VERSION 5.7 ;
BUSBITCHARS "[]" ;
DIVIDERCHAR "/" ;

PROPERTYDEFINITIONS
  MACRO CatenaDesignType STRING ;
END PROPERTYDEFINITIONS

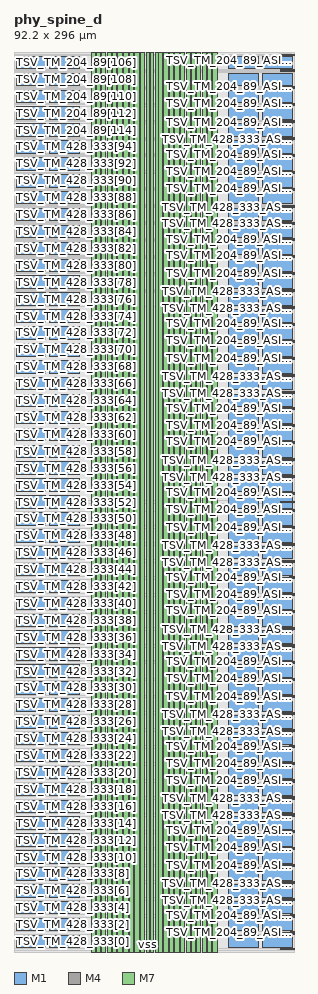
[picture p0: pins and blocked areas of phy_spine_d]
MACRO phy_spine_d
  CLASS RING ;
  ORIGIN 0 0 ;
  FOREIGN phy_spine_d 0 0 ;
  SIZE 92.2 BY 296 ;
  SYMMETRY X Y R90 ;
  PIN TSV_TM_204_89[0]
    DIRECTION OUTPUT ;
    USE SIGNAL ;
    PORT
      LAYER M1 ;
        RECT 81.82 1.38 91.5 5.5 ;
    END
  END TSV_TM_204_89[0]
  PIN TSV_TM_204_89[100]
    DIRECTION OUTPUT ;
    USE SIGNAL ;
    PORT
      LAYER M1 ;
        RECT 81.82 279.38 91.5 283.5 ;
    END
  END TSV_TM_204_89[100]
  PIN TSV_TM_204_89[101]
    DIRECTION OUTPUT ;
    USE SIGNAL ;
    PORT
      LAYER M1 ;
        RECT 70.7 279.38 80.38 283.5 ;
    END
  END TSV_TM_204_89[101]
  PIN TSV_TM_204_89[102]
    DIRECTION OUTPUT ;
    USE SIGNAL ;
    PORT
      LAYER M1 ;
        RECT 81.82 284.94 91.5 289.06 ;
    END
  END TSV_TM_204_89[102]
  PIN TSV_TM_204_89[103]
    DIRECTION OUTPUT ;
    USE SIGNAL ;
    PORT
      LAYER M1 ;
        RECT 70.7 284.94 80.38 289.06 ;
    END
  END TSV_TM_204_89[103]
  PIN TSV_TM_204_89[104]
    DIRECTION OUTPUT ;
    USE SIGNAL ;
    PORT
      LAYER M1 ;
        RECT 81.82 290.5 91.5 294.62 ;
    END
  END TSV_TM_204_89[104]
  PIN TSV_TM_204_89[105]
    DIRECTION OUTPUT ;
    USE SIGNAL ;
    PORT
      LAYER M1 ;
        RECT 70.7 290.5 80.38 294.62 ;
    END
  END TSV_TM_204_89[105]
  PIN TSV_TM_204_89[106]
    DIRECTION OUTPUT ;
    USE SIGNAL ;
    PORT
      LAYER M1 ;
        RECT 11.79 290.5 21.47 294.62 ;
    END
  END TSV_TM_204_89[106]
  PIN TSV_TM_204_89[107]
    DIRECTION OUTPUT ;
    USE SIGNAL ;
    PORT
      LAYER M1 ;
        RECT 0.67 290.5 10.35 294.62 ;
    END
  END TSV_TM_204_89[107]
  PIN TSV_TM_204_89[108]
    DIRECTION OUTPUT ;
    USE SIGNAL ;
    PORT
      LAYER M1 ;
        RECT 11.79 284.94 21.47 289.06 ;
    END
  END TSV_TM_204_89[108]
  PIN TSV_TM_204_89[109]
    DIRECTION OUTPUT ;
    USE SIGNAL ;
    PORT
      LAYER M1 ;
        RECT 0.67 284.94 10.35 289.06 ;
    END
  END TSV_TM_204_89[109]
  PIN TSV_TM_204_89[10]
    DIRECTION OUTPUT ;
    USE SIGNAL ;
    PORT
      LAYER M1 ;
        RECT 81.82 29.18 91.5 33.3 ;
    END
  END TSV_TM_204_89[10]
  PIN TSV_TM_204_89[110]
    DIRECTION OUTPUT ;
    USE SIGNAL ;
    PORT
      LAYER M1 ;
        RECT 11.79 279.38 21.47 283.5 ;
    END
  END TSV_TM_204_89[110]
  PIN TSV_TM_204_89[111]
    DIRECTION OUTPUT ;
    USE SIGNAL ;
    PORT
      LAYER M1 ;
        RECT 0.67 279.38 10.35 283.5 ;
    END
  END TSV_TM_204_89[111]
  PIN TSV_TM_204_89[112]
    DIRECTION OUTPUT ;
    USE SIGNAL ;
    PORT
      LAYER M1 ;
        RECT 11.79 273.82 21.47 277.94 ;
    END
  END TSV_TM_204_89[112]
  PIN TSV_TM_204_89[113]
    DIRECTION OUTPUT ;
    USE SIGNAL ;
    PORT
      LAYER M1 ;
        RECT 0.67 273.82 10.35 277.94 ;
    END
  END TSV_TM_204_89[113]
  PIN TSV_TM_204_89[114]
    DIRECTION OUTPUT ;
    USE SIGNAL ;
    PORT
      LAYER M1 ;
        RECT 11.79 268.26 21.47 272.38 ;
    END
  END TSV_TM_204_89[114]
  PIN TSV_TM_204_89[115]
    DIRECTION OUTPUT ;
    USE SIGNAL ;
    PORT
      LAYER M1 ;
        RECT 0.67 268.26 10.35 272.38 ;
    END
  END TSV_TM_204_89[115]
  PIN TSV_TM_204_89[11]
    DIRECTION OUTPUT ;
    USE SIGNAL ;
    PORT
      LAYER M1 ;
        RECT 70.7 29.18 80.38 33.3 ;
    END
  END TSV_TM_204_89[11]
  PIN TSV_TM_204_89[12]
    DIRECTION OUTPUT ;
    USE SIGNAL ;
    PORT
      LAYER M1 ;
        RECT 81.82 34.74 91.5 38.86 ;
    END
  END TSV_TM_204_89[12]
  PIN TSV_TM_204_89[13]
    DIRECTION OUTPUT ;
    USE SIGNAL ;
    PORT
      LAYER M1 ;
        RECT 70.7 34.74 80.38 38.86 ;
    END
  END TSV_TM_204_89[13]
  PIN TSV_TM_204_89[14]
    DIRECTION OUTPUT ;
    USE SIGNAL ;
    PORT
      LAYER M1 ;
        RECT 81.82 40.3 91.5 44.42 ;
    END
  END TSV_TM_204_89[14]
  PIN TSV_TM_204_89[15]
    DIRECTION OUTPUT ;
    USE SIGNAL ;
    PORT
      LAYER M1 ;
        RECT 70.7 40.3 80.38 44.42 ;
    END
  END TSV_TM_204_89[15]
  PIN TSV_TM_204_89[16]
    DIRECTION OUTPUT ;
    USE SIGNAL ;
    PORT
      LAYER M1 ;
        RECT 81.82 45.86 91.5 49.98 ;
    END
  END TSV_TM_204_89[16]
  PIN TSV_TM_204_89[17]
    DIRECTION OUTPUT ;
    USE SIGNAL ;
    PORT
      LAYER M1 ;
        RECT 70.7 45.86 80.38 49.98 ;
    END
  END TSV_TM_204_89[17]
  PIN TSV_TM_204_89[18]
    DIRECTION OUTPUT ;
    USE SIGNAL ;
    PORT
      LAYER M1 ;
        RECT 81.82 51.42 91.5 55.54 ;
    END
  END TSV_TM_204_89[18]
  PIN TSV_TM_204_89[19]
    DIRECTION OUTPUT ;
    USE SIGNAL ;
    PORT
      LAYER M1 ;
        RECT 70.7 51.42 80.38 55.54 ;
    END
  END TSV_TM_204_89[19]
  PIN TSV_TM_204_89[1]
    DIRECTION OUTPUT ;
    USE SIGNAL ;
    PORT
      LAYER M1 ;
        RECT 70.7 1.38 80.38 5.5 ;
    END
  END TSV_TM_204_89[1]
  PIN TSV_TM_204_89[20]
    DIRECTION OUTPUT ;
    USE SIGNAL ;
    PORT
      LAYER M1 ;
        RECT 81.82 56.98 91.5 61.1 ;
    END
  END TSV_TM_204_89[20]
  PIN TSV_TM_204_89[21]
    DIRECTION OUTPUT ;
    USE SIGNAL ;
    PORT
      LAYER M1 ;
        RECT 70.7 56.98 80.38 61.1 ;
    END
  END TSV_TM_204_89[21]
  PIN TSV_TM_204_89[22]
    DIRECTION OUTPUT ;
    USE SIGNAL ;
    PORT
      LAYER M1 ;
        RECT 81.82 62.54 91.5 66.66 ;
    END
  END TSV_TM_204_89[22]
  PIN TSV_TM_204_89[23]
    DIRECTION OUTPUT ;
    USE SIGNAL ;
    PORT
      LAYER M1 ;
        RECT 70.7 62.54 80.38 66.66 ;
    END
  END TSV_TM_204_89[23]
  PIN TSV_TM_204_89[24]
    DIRECTION OUTPUT ;
    USE SIGNAL ;
    PORT
      LAYER M1 ;
        RECT 81.82 68.1 91.5 72.22 ;
    END
  END TSV_TM_204_89[24]
  PIN TSV_TM_204_89[25]
    DIRECTION OUTPUT ;
    USE SIGNAL ;
    PORT
      LAYER M1 ;
        RECT 70.7 68.1 80.38 72.22 ;
    END
  END TSV_TM_204_89[25]
  PIN TSV_TM_204_89[26]
    DIRECTION OUTPUT ;
    USE SIGNAL ;
    PORT
      LAYER M1 ;
        RECT 81.82 73.66 91.5 77.78 ;
    END
  END TSV_TM_204_89[26]
  PIN TSV_TM_204_89[27]
    DIRECTION OUTPUT ;
    USE SIGNAL ;
    PORT
      LAYER M1 ;
        RECT 70.7 73.66 80.38 77.78 ;
    END
  END TSV_TM_204_89[27]
  PIN TSV_TM_204_89[28]
    DIRECTION OUTPUT ;
    USE SIGNAL ;
    PORT
      LAYER M1 ;
        RECT 81.82 79.22 91.5 83.34 ;
    END
  END TSV_TM_204_89[28]
  PIN TSV_TM_204_89[29]
    DIRECTION OUTPUT ;
    USE SIGNAL ;
    PORT
      LAYER M1 ;
        RECT 70.7 79.22 80.38 83.34 ;
    END
  END TSV_TM_204_89[29]
  PIN TSV_TM_204_89[2]
    DIRECTION OUTPUT ;
    USE SIGNAL ;
    PORT
      LAYER M1 ;
        RECT 81.82 6.94 91.5 11.06 ;
    END
  END TSV_TM_204_89[2]
  PIN TSV_TM_204_89[30]
    DIRECTION OUTPUT ;
    USE SIGNAL ;
    PORT
      LAYER M1 ;
        RECT 81.82 84.78 91.5 88.9 ;
    END
  END TSV_TM_204_89[30]
  PIN TSV_TM_204_89[31]
    DIRECTION OUTPUT ;
    USE SIGNAL ;
    PORT
      LAYER M1 ;
        RECT 70.7 84.78 80.38 88.9 ;
    END
  END TSV_TM_204_89[31]
  PIN TSV_TM_204_89[32]
    DIRECTION OUTPUT ;
    USE SIGNAL ;
    PORT
      LAYER M1 ;
        RECT 81.82 90.34 91.5 94.46 ;
    END
  END TSV_TM_204_89[32]
  PIN TSV_TM_204_89[33]
    DIRECTION OUTPUT ;
    USE SIGNAL ;
    PORT
      LAYER M1 ;
        RECT 70.7 90.34 80.38 94.46 ;
    END
  END TSV_TM_204_89[33]
  PIN TSV_TM_204_89[34]
    DIRECTION OUTPUT ;
    USE SIGNAL ;
    PORT
      LAYER M1 ;
        RECT 81.82 95.9 91.5 100.02 ;
    END
  END TSV_TM_204_89[34]
  PIN TSV_TM_204_89[35]
    DIRECTION OUTPUT ;
    USE SIGNAL ;
    PORT
      LAYER M1 ;
        RECT 70.7 95.9 80.38 100.02 ;
    END
  END TSV_TM_204_89[35]
  PIN TSV_TM_204_89[36]
    DIRECTION OUTPUT ;
    USE SIGNAL ;
    PORT
      LAYER M1 ;
        RECT 81.82 101.46 91.5 105.58 ;
    END
  END TSV_TM_204_89[36]
  PIN TSV_TM_204_89[37]
    DIRECTION OUTPUT ;
    USE SIGNAL ;
    PORT
      LAYER M1 ;
        RECT 70.7 101.46 80.38 105.58 ;
    END
  END TSV_TM_204_89[37]
  PIN TSV_TM_204_89[38]
    DIRECTION OUTPUT ;
    USE SIGNAL ;
    PORT
      LAYER M1 ;
        RECT 81.82 107.02 91.5 111.14 ;
    END
  END TSV_TM_204_89[38]
  PIN TSV_TM_204_89[39]
    DIRECTION OUTPUT ;
    USE SIGNAL ;
    PORT
      LAYER M1 ;
        RECT 70.7 107.02 80.38 111.14 ;
    END
  END TSV_TM_204_89[39]
  PIN TSV_TM_204_89[3]
    DIRECTION OUTPUT ;
    USE SIGNAL ;
    PORT
      LAYER M1 ;
        RECT 70.7 6.94 80.38 11.06 ;
    END
  END TSV_TM_204_89[3]
  PIN TSV_TM_204_89[40]
    DIRECTION OUTPUT ;
    USE SIGNAL ;
    PORT
      LAYER M1 ;
        RECT 81.82 112.58 91.5 116.7 ;
    END
  END TSV_TM_204_89[40]
  PIN TSV_TM_204_89[41]
    DIRECTION OUTPUT ;
    USE SIGNAL ;
    PORT
      LAYER M1 ;
        RECT 70.7 112.58 80.38 116.7 ;
    END
  END TSV_TM_204_89[41]
  PIN TSV_TM_204_89[42]
    DIRECTION OUTPUT ;
    USE SIGNAL ;
    PORT
      LAYER M1 ;
        RECT 81.82 118.14 91.5 122.26 ;
    END
  END TSV_TM_204_89[42]
  PIN TSV_TM_204_89[43]
    DIRECTION OUTPUT ;
    USE SIGNAL ;
    PORT
      LAYER M1 ;
        RECT 70.7 118.14 80.38 122.26 ;
    END
  END TSV_TM_204_89[43]
  PIN TSV_TM_204_89[44]
    DIRECTION OUTPUT ;
    USE SIGNAL ;
    PORT
      LAYER M1 ;
        RECT 81.82 123.7 91.5 127.82 ;
    END
  END TSV_TM_204_89[44]
  PIN TSV_TM_204_89[45]
    DIRECTION OUTPUT ;
    USE SIGNAL ;
    PORT
      LAYER M1 ;
        RECT 70.7 123.7 80.38 127.82 ;
    END
  END TSV_TM_204_89[45]
  PIN TSV_TM_204_89[46]
    DIRECTION OUTPUT ;
    USE SIGNAL ;
    PORT
      LAYER M1 ;
        RECT 81.82 129.26 91.5 133.38 ;
    END
  END TSV_TM_204_89[46]
  PIN TSV_TM_204_89[47]
    DIRECTION OUTPUT ;
    USE SIGNAL ;
    PORT
      LAYER M1 ;
        RECT 70.7 129.26 80.38 133.38 ;
    END
  END TSV_TM_204_89[47]
  PIN TSV_TM_204_89[48]
    DIRECTION OUTPUT ;
    USE SIGNAL ;
    PORT
      LAYER M1 ;
        RECT 81.82 134.82 91.5 138.94 ;
    END
  END TSV_TM_204_89[48]
  PIN TSV_TM_204_89[49]
    DIRECTION OUTPUT ;
    USE SIGNAL ;
    PORT
      LAYER M1 ;
        RECT 70.7 134.82 80.38 138.94 ;
    END
  END TSV_TM_204_89[49]
  PIN TSV_TM_204_89[4]
    DIRECTION OUTPUT ;
    USE SIGNAL ;
    PORT
      LAYER M1 ;
        RECT 81.82 12.5 91.5 16.62 ;
    END
  END TSV_TM_204_89[4]
  PIN TSV_TM_204_89[50]
    DIRECTION OUTPUT ;
    USE SIGNAL ;
    PORT
      LAYER M1 ;
        RECT 81.82 140.38 91.5 144.5 ;
    END
  END TSV_TM_204_89[50]
  PIN TSV_TM_204_89[51]
    DIRECTION OUTPUT ;
    USE SIGNAL ;
    PORT
      LAYER M1 ;
        RECT 70.7 140.38 80.38 144.5 ;
    END
  END TSV_TM_204_89[51]
  PIN TSV_TM_204_89[52]
    DIRECTION OUTPUT ;
    USE SIGNAL ;
    PORT
      LAYER M1 ;
        RECT 81.82 145.94 91.5 150.06 ;
    END
  END TSV_TM_204_89[52]
  PIN TSV_TM_204_89[53]
    DIRECTION OUTPUT ;
    USE SIGNAL ;
    PORT
      LAYER M1 ;
        RECT 70.7 145.94 80.38 150.06 ;
    END
  END TSV_TM_204_89[53]
  PIN TSV_TM_204_89[54]
    DIRECTION OUTPUT ;
    USE SIGNAL ;
    PORT
      LAYER M1 ;
        RECT 81.82 151.5 91.5 155.62 ;
    END
  END TSV_TM_204_89[54]
  PIN TSV_TM_204_89[55]
    DIRECTION OUTPUT ;
    USE SIGNAL ;
    PORT
      LAYER M1 ;
        RECT 70.7 151.5 80.38 155.62 ;
    END
  END TSV_TM_204_89[55]
  PIN TSV_TM_204_89[56]
    DIRECTION OUTPUT ;
    USE SIGNAL ;
    PORT
      LAYER M1 ;
        RECT 81.82 157.06 91.5 161.18 ;
    END
  END TSV_TM_204_89[56]
  PIN TSV_TM_204_89[57]
    DIRECTION OUTPUT ;
    USE SIGNAL ;
    PORT
      LAYER M1 ;
        RECT 70.7 157.06 80.38 161.18 ;
    END
  END TSV_TM_204_89[57]
  PIN TSV_TM_204_89[58]
    DIRECTION OUTPUT ;
    USE SIGNAL ;
    PORT
      LAYER M1 ;
        RECT 81.82 162.62 91.5 166.74 ;
    END
  END TSV_TM_204_89[58]
  PIN TSV_TM_204_89[59]
    DIRECTION OUTPUT ;
    USE SIGNAL ;
    PORT
      LAYER M1 ;
        RECT 70.7 162.62 80.38 166.74 ;
    END
  END TSV_TM_204_89[59]
  PIN TSV_TM_204_89[5]
    DIRECTION OUTPUT ;
    USE SIGNAL ;
    PORT
      LAYER M1 ;
        RECT 70.7 12.5 80.38 16.62 ;
    END
  END TSV_TM_204_89[5]
  PIN TSV_TM_204_89[60]
    DIRECTION OUTPUT ;
    USE SIGNAL ;
    PORT
      LAYER M1 ;
        RECT 81.82 168.18 91.5 172.3 ;
    END
  END TSV_TM_204_89[60]
  PIN TSV_TM_204_89[61]
    DIRECTION OUTPUT ;
    USE SIGNAL ;
    PORT
      LAYER M1 ;
        RECT 70.7 168.18 80.38 172.3 ;
    END
  END TSV_TM_204_89[61]
  PIN TSV_TM_204_89[62]
    DIRECTION OUTPUT ;
    USE SIGNAL ;
    PORT
      LAYER M1 ;
        RECT 81.82 173.74 91.5 177.86 ;
    END
  END TSV_TM_204_89[62]
  PIN TSV_TM_204_89[63]
    DIRECTION OUTPUT ;
    USE SIGNAL ;
    PORT
      LAYER M1 ;
        RECT 70.7 173.74 80.38 177.86 ;
    END
  END TSV_TM_204_89[63]
  PIN TSV_TM_204_89[64]
    DIRECTION OUTPUT ;
    USE SIGNAL ;
    PORT
      LAYER M1 ;
        RECT 81.82 179.3 91.5 183.42 ;
    END
  END TSV_TM_204_89[64]
  PIN TSV_TM_204_89[65]
    DIRECTION OUTPUT ;
    USE SIGNAL ;
    PORT
      LAYER M1 ;
        RECT 70.7 179.3 80.38 183.42 ;
    END
  END TSV_TM_204_89[65]
  PIN TSV_TM_204_89[66]
    DIRECTION OUTPUT ;
    USE SIGNAL ;
    PORT
      LAYER M1 ;
        RECT 81.82 184.86 91.5 188.98 ;
    END
  END TSV_TM_204_89[66]
  PIN TSV_TM_204_89[67]
    DIRECTION OUTPUT ;
    USE SIGNAL ;
    PORT
      LAYER M1 ;
        RECT 70.7 184.86 80.38 188.98 ;
    END
  END TSV_TM_204_89[67]
  PIN TSV_TM_204_89[68]
    DIRECTION OUTPUT ;
    USE SIGNAL ;
    PORT
      LAYER M1 ;
        RECT 81.82 190.42 91.5 194.54 ;
    END
  END TSV_TM_204_89[68]
  PIN TSV_TM_204_89[69]
    DIRECTION OUTPUT ;
    USE SIGNAL ;
    PORT
      LAYER M1 ;
        RECT 70.7 190.42 80.38 194.54 ;
    END
  END TSV_TM_204_89[69]
  PIN TSV_TM_204_89[6]
    DIRECTION OUTPUT ;
    USE SIGNAL ;
    PORT
      LAYER M1 ;
        RECT 81.82 18.06 91.5 22.18 ;
    END
  END TSV_TM_204_89[6]
  PIN TSV_TM_204_89[70]
    DIRECTION OUTPUT ;
    USE SIGNAL ;
    PORT
      LAYER M1 ;
        RECT 81.82 195.98 91.5 200.1 ;
    END
  END TSV_TM_204_89[70]
  PIN TSV_TM_204_89[71]
    DIRECTION OUTPUT ;
    USE SIGNAL ;
    PORT
      LAYER M1 ;
        RECT 70.7 195.98 80.38 200.1 ;
    END
  END TSV_TM_204_89[71]
  PIN TSV_TM_204_89[72]
    DIRECTION OUTPUT ;
    USE SIGNAL ;
    PORT
      LAYER M1 ;
        RECT 81.82 201.54 91.5 205.66 ;
    END
  END TSV_TM_204_89[72]
  PIN TSV_TM_204_89[73]
    DIRECTION OUTPUT ;
    USE SIGNAL ;
    PORT
      LAYER M1 ;
        RECT 70.7 201.54 80.38 205.66 ;
    END
  END TSV_TM_204_89[73]
  PIN TSV_TM_204_89[74]
    DIRECTION OUTPUT ;
    USE SIGNAL ;
    PORT
      LAYER M1 ;
        RECT 81.82 207.1 91.5 211.22 ;
    END
  END TSV_TM_204_89[74]
  PIN TSV_TM_204_89[75]
    DIRECTION OUTPUT ;
    USE SIGNAL ;
    PORT
      LAYER M1 ;
        RECT 70.7 207.1 80.38 211.22 ;
    END
  END TSV_TM_204_89[75]
  PIN TSV_TM_204_89[76]
    DIRECTION OUTPUT ;
    USE SIGNAL ;
    PORT
      LAYER M1 ;
        RECT 81.82 212.66 91.5 216.78 ;
    END
  END TSV_TM_204_89[76]
  PIN TSV_TM_204_89[77]
    DIRECTION OUTPUT ;
    USE SIGNAL ;
    PORT
      LAYER M1 ;
        RECT 70.7 212.66 80.38 216.78 ;
    END
  END TSV_TM_204_89[77]
  PIN TSV_TM_204_89[78]
    DIRECTION OUTPUT ;
    USE SIGNAL ;
    PORT
      LAYER M1 ;
        RECT 81.82 218.22 91.5 222.34 ;
    END
  END TSV_TM_204_89[78]
  PIN TSV_TM_204_89[79]
    DIRECTION OUTPUT ;
    USE SIGNAL ;
    PORT
      LAYER M1 ;
        RECT 70.7 218.22 80.38 222.34 ;
    END
  END TSV_TM_204_89[79]
  PIN TSV_TM_204_89[7]
    DIRECTION OUTPUT ;
    USE SIGNAL ;
    PORT
      LAYER M1 ;
        RECT 70.7 18.06 80.38 22.18 ;
    END
  END TSV_TM_204_89[7]
  PIN TSV_TM_204_89[80]
    DIRECTION OUTPUT ;
    USE SIGNAL ;
    PORT
      LAYER M1 ;
        RECT 81.82 223.78 91.5 227.9 ;
    END
  END TSV_TM_204_89[80]
  PIN TSV_TM_204_89[81]
    DIRECTION OUTPUT ;
    USE SIGNAL ;
    PORT
      LAYER M1 ;
        RECT 70.7 223.78 80.38 227.9 ;
    END
  END TSV_TM_204_89[81]
  PIN TSV_TM_204_89[82]
    DIRECTION OUTPUT ;
    USE SIGNAL ;
    PORT
      LAYER M1 ;
        RECT 81.82 229.34 91.5 233.46 ;
    END
  END TSV_TM_204_89[82]
  PIN TSV_TM_204_89[83]
    DIRECTION OUTPUT ;
    USE SIGNAL ;
    PORT
      LAYER M1 ;
        RECT 70.7 229.34 80.38 233.46 ;
    END
  END TSV_TM_204_89[83]
  PIN TSV_TM_204_89[84]
    DIRECTION OUTPUT ;
    USE SIGNAL ;
    PORT
      LAYER M1 ;
        RECT 81.82 234.9 91.5 239.02 ;
    END
  END TSV_TM_204_89[84]
  PIN TSV_TM_204_89[85]
    DIRECTION OUTPUT ;
    USE SIGNAL ;
    PORT
      LAYER M1 ;
        RECT 70.7 234.9 80.38 239.02 ;
    END
  END TSV_TM_204_89[85]
  PIN TSV_TM_204_89[86]
    DIRECTION OUTPUT ;
    USE SIGNAL ;
    PORT
      LAYER M1 ;
        RECT 81.82 240.46 91.5 244.58 ;
    END
  END TSV_TM_204_89[86]
  PIN TSV_TM_204_89[87]
    DIRECTION OUTPUT ;
    USE SIGNAL ;
    PORT
      LAYER M1 ;
        RECT 70.7 240.46 80.38 244.58 ;
    END
  END TSV_TM_204_89[87]
  PIN TSV_TM_204_89[88]
    DIRECTION OUTPUT ;
    USE SIGNAL ;
    PORT
      LAYER M1 ;
        RECT 81.82 246.02 91.5 250.14 ;
    END
  END TSV_TM_204_89[88]
  PIN TSV_TM_204_89[89]
    DIRECTION OUTPUT ;
    USE SIGNAL ;
    PORT
      LAYER M1 ;
        RECT 70.7 246.02 80.38 250.14 ;
    END
  END TSV_TM_204_89[89]
  PIN TSV_TM_204_89[8]
    DIRECTION OUTPUT ;
    USE SIGNAL ;
    PORT
      LAYER M1 ;
        RECT 81.82 23.62 91.5 27.74 ;
    END
  END TSV_TM_204_89[8]
  PIN TSV_TM_204_89[90]
    DIRECTION OUTPUT ;
    USE SIGNAL ;
    PORT
      LAYER M1 ;
        RECT 81.82 251.58 91.5 255.7 ;
    END
  END TSV_TM_204_89[90]
  PIN TSV_TM_204_89[91]
    DIRECTION OUTPUT ;
    USE SIGNAL ;
    PORT
      LAYER M1 ;
        RECT 70.7 251.58 80.38 255.7 ;
    END
  END TSV_TM_204_89[91]
  PIN TSV_TM_204_89[92]
    DIRECTION OUTPUT ;
    USE SIGNAL ;
    PORT
      LAYER M1 ;
        RECT 81.82 257.14 91.5 261.26 ;
    END
  END TSV_TM_204_89[92]
  PIN TSV_TM_204_89[93]
    DIRECTION OUTPUT ;
    USE SIGNAL ;
    PORT
      LAYER M1 ;
        RECT 70.7 257.14 80.38 261.26 ;
    END
  END TSV_TM_204_89[93]
  PIN TSV_TM_204_89[94]
    DIRECTION OUTPUT ;
    USE SIGNAL ;
    PORT
      LAYER M1 ;
        RECT 81.82 262.7 91.5 266.82 ;
    END
  END TSV_TM_204_89[94]
  PIN TSV_TM_204_89[95]
    DIRECTION OUTPUT ;
    USE SIGNAL ;
    PORT
      LAYER M1 ;
        RECT 70.7 262.7 80.38 266.82 ;
    END
  END TSV_TM_204_89[95]
  PIN TSV_TM_204_89[96]
    DIRECTION OUTPUT ;
    USE SIGNAL ;
    PORT
      LAYER M1 ;
        RECT 81.82 268.26 91.5 272.38 ;
    END
  END TSV_TM_204_89[96]
  PIN TSV_TM_204_89[97]
    DIRECTION OUTPUT ;
    USE SIGNAL ;
    PORT
      LAYER M1 ;
        RECT 70.7 268.26 80.38 272.38 ;
    END
  END TSV_TM_204_89[97]
  PIN TSV_TM_204_89[98]
    DIRECTION OUTPUT ;
    USE SIGNAL ;
    PORT
      LAYER M1 ;
        RECT 81.82 273.82 91.5 277.94 ;
    END
  END TSV_TM_204_89[98]
  PIN TSV_TM_204_89[99]
    DIRECTION OUTPUT ;
    USE SIGNAL ;
    PORT
      LAYER M1 ;
        RECT 70.7 273.82 80.38 277.94 ;
    END
  END TSV_TM_204_89[99]
  PIN TSV_TM_204_89[9]
    DIRECTION OUTPUT ;
    USE SIGNAL ;
    PORT
      LAYER M1 ;
        RECT 70.7 23.62 80.38 27.74 ;
    END
  END TSV_TM_204_89[9]
  PIN TSV_TM_428_333[0]
    DIRECTION OUTPUT ;
    USE SIGNAL ;
    PORT
      LAYER M1 ;
        RECT 11.79 1.38 21.47 5.5 ;
    END
  END TSV_TM_428_333[0]
  PIN TSV_TM_428_333[10]
    DIRECTION OUTPUT ;
    USE SIGNAL ;
    PORT
      LAYER M1 ;
        RECT 11.79 29.18 21.47 33.3 ;
    END
  END TSV_TM_428_333[10]
  PIN TSV_TM_428_333[11]
    DIRECTION OUTPUT ;
    USE SIGNAL ;
    PORT
      LAYER M1 ;
        RECT 0.67 29.18 10.35 33.3 ;
    END
  END TSV_TM_428_333[11]
  PIN TSV_TM_428_333[12]
    DIRECTION OUTPUT ;
    USE SIGNAL ;
    PORT
      LAYER M1 ;
        RECT 11.79 34.74 21.47 38.86 ;
    END
  END TSV_TM_428_333[12]
  PIN TSV_TM_428_333[13]
    DIRECTION OUTPUT ;
    USE SIGNAL ;
    PORT
      LAYER M1 ;
        RECT 0.67 34.74 10.35 38.86 ;
    END
  END TSV_TM_428_333[13]
  PIN TSV_TM_428_333[14]
    DIRECTION OUTPUT ;
    USE SIGNAL ;
    PORT
      LAYER M1 ;
        RECT 11.79 40.3 21.47 44.42 ;
    END
  END TSV_TM_428_333[14]
  PIN TSV_TM_428_333[15]
    DIRECTION OUTPUT ;
    USE SIGNAL ;
    PORT
      LAYER M1 ;
        RECT 0.67 40.3 10.35 44.42 ;
    END
  END TSV_TM_428_333[15]
  PIN TSV_TM_428_333[16]
    DIRECTION OUTPUT ;
    USE SIGNAL ;
    PORT
      LAYER M1 ;
        RECT 11.79 45.86 21.47 49.98 ;
    END
  END TSV_TM_428_333[16]
  PIN TSV_TM_428_333[17]
    DIRECTION OUTPUT ;
    USE SIGNAL ;
    PORT
      LAYER M1 ;
        RECT 0.67 45.86 10.35 49.98 ;
    END
  END TSV_TM_428_333[17]
  PIN TSV_TM_428_333[18]
    DIRECTION OUTPUT ;
    USE SIGNAL ;
    PORT
      LAYER M1 ;
        RECT 11.79 51.42 21.47 55.54 ;
    END
  END TSV_TM_428_333[18]
  PIN TSV_TM_428_333[19]
    DIRECTION OUTPUT ;
    USE SIGNAL ;
    PORT
      LAYER M1 ;
        RECT 0.67 51.42 10.35 55.54 ;
    END
  END TSV_TM_428_333[19]
  PIN TSV_TM_428_333[1]
    DIRECTION OUTPUT ;
    USE SIGNAL ;
    PORT
      LAYER M1 ;
        RECT 0.67 1.38 10.35 5.5 ;
    END
  END TSV_TM_428_333[1]
  PIN TSV_TM_428_333[20]
    DIRECTION OUTPUT ;
    USE SIGNAL ;
    PORT
      LAYER M1 ;
        RECT 11.79 56.98 21.47 61.1 ;
    END
  END TSV_TM_428_333[20]
  PIN TSV_TM_428_333[21]
    DIRECTION OUTPUT ;
    USE SIGNAL ;
    PORT
      LAYER M1 ;
        RECT 0.67 56.98 10.35 61.1 ;
    END
  END TSV_TM_428_333[21]
  PIN TSV_TM_428_333[22]
    DIRECTION OUTPUT ;
    USE SIGNAL ;
    PORT
      LAYER M1 ;
        RECT 11.79 62.54 21.47 66.66 ;
    END
  END TSV_TM_428_333[22]
  PIN TSV_TM_428_333[23]
    DIRECTION OUTPUT ;
    USE SIGNAL ;
    PORT
      LAYER M1 ;
        RECT 0.67 62.54 10.35 66.66 ;
    END
  END TSV_TM_428_333[23]
  PIN TSV_TM_428_333[24]
    DIRECTION OUTPUT ;
    USE SIGNAL ;
    PORT
      LAYER M1 ;
        RECT 11.79 68.1 21.47 72.22 ;
    END
  END TSV_TM_428_333[24]
  PIN TSV_TM_428_333[25]
    DIRECTION OUTPUT ;
    USE SIGNAL ;
    PORT
      LAYER M1 ;
        RECT 0.67 68.1 10.35 72.22 ;
    END
  END TSV_TM_428_333[25]
  PIN TSV_TM_428_333[26]
    DIRECTION OUTPUT ;
    USE SIGNAL ;
    PORT
      LAYER M1 ;
        RECT 11.79 73.66 21.47 77.78 ;
    END
  END TSV_TM_428_333[26]
  PIN TSV_TM_428_333[27]
    DIRECTION OUTPUT ;
    USE SIGNAL ;
    PORT
      LAYER M1 ;
        RECT 0.67 73.66 10.35 77.78 ;
    END
  END TSV_TM_428_333[27]
  PIN TSV_TM_428_333[28]
    DIRECTION OUTPUT ;
    USE SIGNAL ;
    PORT
      LAYER M1 ;
        RECT 11.79 79.22 21.47 83.34 ;
    END
  END TSV_TM_428_333[28]
  PIN TSV_TM_428_333[29]
    DIRECTION OUTPUT ;
    USE SIGNAL ;
    PORT
      LAYER M1 ;
        RECT 0.67 79.22 10.35 83.34 ;
    END
  END TSV_TM_428_333[29]
  PIN TSV_TM_428_333[2]
    DIRECTION OUTPUT ;
    USE SIGNAL ;
    PORT
      LAYER M1 ;
        RECT 11.79 6.94 21.47 11.06 ;
    END
  END TSV_TM_428_333[2]
  PIN TSV_TM_428_333[30]
    DIRECTION OUTPUT ;
    USE SIGNAL ;
    PORT
      LAYER M1 ;
        RECT 11.79 84.78 21.47 88.9 ;
    END
  END TSV_TM_428_333[30]
  PIN TSV_TM_428_333[31]
    DIRECTION OUTPUT ;
    USE SIGNAL ;
    PORT
      LAYER M1 ;
        RECT 0.67 84.78 10.35 88.9 ;
    END
  END TSV_TM_428_333[31]
  PIN TSV_TM_428_333[32]
    DIRECTION OUTPUT ;
    USE SIGNAL ;
    PORT
      LAYER M1 ;
        RECT 11.79 90.34 21.47 94.46 ;
    END
  END TSV_TM_428_333[32]
  PIN TSV_TM_428_333[33]
    DIRECTION OUTPUT ;
    USE SIGNAL ;
    PORT
      LAYER M1 ;
        RECT 0.67 90.34 10.35 94.46 ;
    END
  END TSV_TM_428_333[33]
  PIN TSV_TM_428_333[34]
    DIRECTION OUTPUT ;
    USE SIGNAL ;
    PORT
      LAYER M1 ;
        RECT 11.79 95.9 21.47 100.02 ;
    END
  END TSV_TM_428_333[34]
  PIN TSV_TM_428_333[35]
    DIRECTION OUTPUT ;
    USE SIGNAL ;
    PORT
      LAYER M1 ;
        RECT 0.67 95.9 10.35 100.02 ;
    END
  END TSV_TM_428_333[35]
  PIN TSV_TM_428_333[36]
    DIRECTION OUTPUT ;
    USE SIGNAL ;
    PORT
      LAYER M1 ;
        RECT 11.79 101.46 21.47 105.58 ;
    END
  END TSV_TM_428_333[36]
  PIN TSV_TM_428_333[37]
    DIRECTION OUTPUT ;
    USE SIGNAL ;
    PORT
      LAYER M1 ;
        RECT 0.67 101.46 10.35 105.58 ;
    END
  END TSV_TM_428_333[37]
  PIN TSV_TM_428_333[38]
    DIRECTION OUTPUT ;
    USE SIGNAL ;
    PORT
      LAYER M1 ;
        RECT 11.79 107.02 21.47 111.14 ;
    END
  END TSV_TM_428_333[38]
  PIN TSV_TM_428_333[39]
    DIRECTION OUTPUT ;
    USE SIGNAL ;
    PORT
      LAYER M1 ;
        RECT 0.67 107.02 10.35 111.14 ;
    END
  END TSV_TM_428_333[39]
  PIN TSV_TM_428_333[3]
    DIRECTION OUTPUT ;
    USE SIGNAL ;
    PORT
      LAYER M1 ;
        RECT 0.67 6.94 10.35 11.06 ;
    END
  END TSV_TM_428_333[3]
  PIN TSV_TM_428_333[40]
    DIRECTION OUTPUT ;
    USE SIGNAL ;
    PORT
      LAYER M1 ;
        RECT 11.79 112.58 21.47 116.7 ;
    END
  END TSV_TM_428_333[40]
  PIN TSV_TM_428_333[41]
    DIRECTION OUTPUT ;
    USE SIGNAL ;
    PORT
      LAYER M1 ;
        RECT 0.67 112.58 10.35 116.7 ;
    END
  END TSV_TM_428_333[41]
  PIN TSV_TM_428_333[42]
    DIRECTION OUTPUT ;
    USE SIGNAL ;
    PORT
      LAYER M1 ;
        RECT 11.79 118.14 21.47 122.26 ;
    END
  END TSV_TM_428_333[42]
  PIN TSV_TM_428_333[43]
    DIRECTION OUTPUT ;
    USE SIGNAL ;
    PORT
      LAYER M1 ;
        RECT 0.67 118.14 10.35 122.26 ;
    END
  END TSV_TM_428_333[43]
  PIN TSV_TM_428_333[44]
    DIRECTION OUTPUT ;
    USE SIGNAL ;
    PORT
      LAYER M1 ;
        RECT 11.79 123.7 21.47 127.82 ;
    END
  END TSV_TM_428_333[44]
  PIN TSV_TM_428_333[45]
    DIRECTION OUTPUT ;
    USE SIGNAL ;
    PORT
      LAYER M1 ;
        RECT 0.67 123.7 10.35 127.82 ;
    END
  END TSV_TM_428_333[45]
  PIN TSV_TM_428_333[46]
    DIRECTION OUTPUT ;
    USE SIGNAL ;
    PORT
      LAYER M1 ;
        RECT 11.79 129.26 21.47 133.38 ;
    END
  END TSV_TM_428_333[46]
  PIN TSV_TM_428_333[47]
    DIRECTION OUTPUT ;
    USE SIGNAL ;
    PORT
      LAYER M1 ;
        RECT 0.67 129.26 10.35 133.38 ;
    END
  END TSV_TM_428_333[47]
  PIN TSV_TM_428_333[48]
    DIRECTION OUTPUT ;
    USE SIGNAL ;
    PORT
      LAYER M1 ;
        RECT 11.79 134.82 21.47 138.94 ;
    END
  END TSV_TM_428_333[48]
  PIN TSV_TM_428_333[49]
    DIRECTION OUTPUT ;
    USE SIGNAL ;
    PORT
      LAYER M1 ;
        RECT 0.67 134.82 10.35 138.94 ;
    END
  END TSV_TM_428_333[49]
  PIN TSV_TM_428_333[4]
    DIRECTION OUTPUT ;
    USE SIGNAL ;
    PORT
      LAYER M1 ;
        RECT 11.79 12.5 21.47 16.62 ;
    END
  END TSV_TM_428_333[4]
  PIN TSV_TM_428_333[50]
    DIRECTION OUTPUT ;
    USE SIGNAL ;
    PORT
      LAYER M1 ;
        RECT 11.79 140.38 21.47 144.5 ;
    END
  END TSV_TM_428_333[50]
  PIN TSV_TM_428_333[51]
    DIRECTION OUTPUT ;
    USE SIGNAL ;
    PORT
      LAYER M1 ;
        RECT 0.67 140.38 10.35 144.5 ;
    END
  END TSV_TM_428_333[51]
  PIN TSV_TM_428_333[52]
    DIRECTION OUTPUT ;
    USE SIGNAL ;
    PORT
      LAYER M1 ;
        RECT 11.79 145.94 21.47 150.06 ;
    END
  END TSV_TM_428_333[52]
  PIN TSV_TM_428_333[53]
    DIRECTION OUTPUT ;
    USE SIGNAL ;
    PORT
      LAYER M1 ;
        RECT 0.67 145.94 10.35 150.06 ;
    END
  END TSV_TM_428_333[53]
  PIN TSV_TM_428_333[54]
    DIRECTION OUTPUT ;
    USE SIGNAL ;
    PORT
      LAYER M1 ;
        RECT 11.79 151.5 21.47 155.62 ;
    END
  END TSV_TM_428_333[54]
  PIN TSV_TM_428_333[55]
    DIRECTION OUTPUT ;
    USE SIGNAL ;
    PORT
      LAYER M1 ;
        RECT 0.67 151.5 10.35 155.62 ;
    END
  END TSV_TM_428_333[55]
  PIN TSV_TM_428_333[56]
    DIRECTION OUTPUT ;
    USE SIGNAL ;
    PORT
      LAYER M1 ;
        RECT 11.79 157.06 21.47 161.18 ;
    END
  END TSV_TM_428_333[56]
  PIN TSV_TM_428_333[57]
    DIRECTION OUTPUT ;
    USE SIGNAL ;
    PORT
      LAYER M1 ;
        RECT 0.67 157.06 10.35 161.18 ;
    END
  END TSV_TM_428_333[57]
  PIN TSV_TM_428_333[58]
    DIRECTION OUTPUT ;
    USE SIGNAL ;
    PORT
      LAYER M1 ;
        RECT 11.79 162.62 21.47 166.74 ;
    END
  END TSV_TM_428_333[58]
  PIN TSV_TM_428_333[59]
    DIRECTION OUTPUT ;
    USE SIGNAL ;
    PORT
      LAYER M1 ;
        RECT 0.67 162.62 10.35 166.74 ;
    END
  END TSV_TM_428_333[59]
  PIN TSV_TM_428_333[5]
    DIRECTION OUTPUT ;
    USE SIGNAL ;
    PORT
      LAYER M1 ;
        RECT 0.67 12.5 10.35 16.62 ;
    END
  END TSV_TM_428_333[5]
  PIN TSV_TM_428_333[60]
    DIRECTION OUTPUT ;
    USE SIGNAL ;
    PORT
      LAYER M1 ;
        RECT 11.79 168.18 21.47 172.3 ;
    END
  END TSV_TM_428_333[60]
  PIN TSV_TM_428_333[61]
    DIRECTION OUTPUT ;
    USE SIGNAL ;
    PORT
      LAYER M1 ;
        RECT 0.67 168.18 10.35 172.3 ;
    END
  END TSV_TM_428_333[61]
  PIN TSV_TM_428_333[62]
    DIRECTION OUTPUT ;
    USE SIGNAL ;
    PORT
      LAYER M1 ;
        RECT 11.79 173.74 21.47 177.86 ;
    END
  END TSV_TM_428_333[62]
  PIN TSV_TM_428_333[63]
    DIRECTION OUTPUT ;
    USE SIGNAL ;
    PORT
      LAYER M1 ;
        RECT 0.67 173.74 10.35 177.86 ;
    END
  END TSV_TM_428_333[63]
  PIN TSV_TM_428_333[64]
    DIRECTION OUTPUT ;
    USE SIGNAL ;
    PORT
      LAYER M1 ;
        RECT 11.79 179.3 21.47 183.42 ;
    END
  END TSV_TM_428_333[64]
  PIN TSV_TM_428_333[65]
    DIRECTION OUTPUT ;
    USE SIGNAL ;
    PORT
      LAYER M1 ;
        RECT 0.67 179.3 10.35 183.42 ;
    END
  END TSV_TM_428_333[65]
  PIN TSV_TM_428_333[66]
    DIRECTION OUTPUT ;
    USE SIGNAL ;
    PORT
      LAYER M1 ;
        RECT 11.79 184.86 21.47 188.98 ;
    END
  END TSV_TM_428_333[66]
  PIN TSV_TM_428_333[67]
    DIRECTION OUTPUT ;
    USE SIGNAL ;
    PORT
      LAYER M1 ;
        RECT 0.67 184.86 10.35 188.98 ;
    END
  END TSV_TM_428_333[67]
  PIN TSV_TM_428_333[68]
    DIRECTION OUTPUT ;
    USE SIGNAL ;
    PORT
      LAYER M1 ;
        RECT 11.79 190.42 21.47 194.54 ;
    END
  END TSV_TM_428_333[68]
  PIN TSV_TM_428_333[69]
    DIRECTION OUTPUT ;
    USE SIGNAL ;
    PORT
      LAYER M1 ;
        RECT 0.67 190.42 10.35 194.54 ;
    END
  END TSV_TM_428_333[69]
  PIN TSV_TM_428_333[6]
    DIRECTION OUTPUT ;
    USE SIGNAL ;
    PORT
      LAYER M1 ;
        RECT 11.79 18.06 21.47 22.18 ;
    END
  END TSV_TM_428_333[6]
  PIN TSV_TM_428_333[70]
    DIRECTION OUTPUT ;
    USE SIGNAL ;
    PORT
      LAYER M1 ;
        RECT 11.79 195.98 21.47 200.1 ;
    END
  END TSV_TM_428_333[70]
  PIN TSV_TM_428_333[71]
    DIRECTION OUTPUT ;
    USE SIGNAL ;
    PORT
      LAYER M1 ;
        RECT 0.67 195.98 10.35 200.1 ;
    END
  END TSV_TM_428_333[71]
  PIN TSV_TM_428_333[72]
    DIRECTION OUTPUT ;
    USE SIGNAL ;
    PORT
      LAYER M1 ;
        RECT 11.79 201.54 21.47 205.66 ;
    END
  END TSV_TM_428_333[72]
  PIN TSV_TM_428_333[73]
    DIRECTION OUTPUT ;
    USE SIGNAL ;
    PORT
      LAYER M1 ;
        RECT 0.67 201.54 10.35 205.66 ;
    END
  END TSV_TM_428_333[73]
  PIN TSV_TM_428_333[74]
    DIRECTION OUTPUT ;
    USE SIGNAL ;
    PORT
      LAYER M1 ;
        RECT 11.79 207.1 21.47 211.22 ;
    END
  END TSV_TM_428_333[74]
  PIN TSV_TM_428_333[75]
    DIRECTION OUTPUT ;
    USE SIGNAL ;
    PORT
      LAYER M1 ;
        RECT 0.67 207.1 10.35 211.22 ;
    END
  END TSV_TM_428_333[75]
  PIN TSV_TM_428_333[76]
    DIRECTION OUTPUT ;
    USE SIGNAL ;
    PORT
      LAYER M1 ;
        RECT 11.79 212.66 21.47 216.78 ;
    END
  END TSV_TM_428_333[76]
  PIN TSV_TM_428_333[77]
    DIRECTION OUTPUT ;
    USE SIGNAL ;
    PORT
      LAYER M1 ;
        RECT 0.67 212.66 10.35 216.78 ;
    END
  END TSV_TM_428_333[77]
  PIN TSV_TM_428_333[78]
    DIRECTION OUTPUT ;
    USE SIGNAL ;
    PORT
      LAYER M1 ;
        RECT 11.79 218.22 21.47 222.34 ;
    END
  END TSV_TM_428_333[78]
  PIN TSV_TM_428_333[79]
    DIRECTION OUTPUT ;
    USE SIGNAL ;
    PORT
      LAYER M1 ;
        RECT 0.67 218.22 10.35 222.34 ;
    END
  END TSV_TM_428_333[79]
  PIN TSV_TM_428_333[7]
    DIRECTION OUTPUT ;
    USE SIGNAL ;
    PORT
      LAYER M1 ;
        RECT 0.67 18.06 10.35 22.18 ;
    END
  END TSV_TM_428_333[7]
  PIN TSV_TM_428_333[80]
    DIRECTION OUTPUT ;
    USE SIGNAL ;
    PORT
      LAYER M1 ;
        RECT 11.79 223.78 21.47 227.9 ;
    END
  END TSV_TM_428_333[80]
  PIN TSV_TM_428_333[81]
    DIRECTION OUTPUT ;
    USE SIGNAL ;
    PORT
      LAYER M1 ;
        RECT 0.67 223.78 10.35 227.9 ;
    END
  END TSV_TM_428_333[81]
  PIN TSV_TM_428_333[82]
    DIRECTION OUTPUT ;
    USE SIGNAL ;
    PORT
      LAYER M1 ;
        RECT 11.79 229.34 21.47 233.46 ;
    END
  END TSV_TM_428_333[82]
  PIN TSV_TM_428_333[83]
    DIRECTION OUTPUT ;
    USE SIGNAL ;
    PORT
      LAYER M1 ;
        RECT 0.67 229.34 10.35 233.46 ;
    END
  END TSV_TM_428_333[83]
  PIN TSV_TM_428_333[84]
    DIRECTION OUTPUT ;
    USE SIGNAL ;
    PORT
      LAYER M1 ;
        RECT 11.79 234.9 21.47 239.02 ;
    END
  END TSV_TM_428_333[84]
  PIN TSV_TM_428_333[85]
    DIRECTION OUTPUT ;
    USE SIGNAL ;
    PORT
      LAYER M1 ;
        RECT 0.67 234.9 10.35 239.02 ;
    END
  END TSV_TM_428_333[85]
  PIN TSV_TM_428_333[86]
    DIRECTION OUTPUT ;
    USE SIGNAL ;
    PORT
      LAYER M1 ;
        RECT 11.79 240.46 21.47 244.58 ;
    END
  END TSV_TM_428_333[86]
  PIN TSV_TM_428_333[87]
    DIRECTION OUTPUT ;
    USE SIGNAL ;
    PORT
      LAYER M1 ;
        RECT 0.67 240.46 10.35 244.58 ;
    END
  END TSV_TM_428_333[87]
  PIN TSV_TM_428_333[88]
    DIRECTION OUTPUT ;
    USE SIGNAL ;
    PORT
      LAYER M1 ;
        RECT 11.79 246.02 21.47 250.14 ;
    END
  END TSV_TM_428_333[88]
  PIN TSV_TM_428_333[89]
    DIRECTION OUTPUT ;
    USE SIGNAL ;
    PORT
      LAYER M1 ;
        RECT 0.67 246.02 10.35 250.14 ;
    END
  END TSV_TM_428_333[89]
  PIN TSV_TM_428_333[8]
    DIRECTION OUTPUT ;
    USE SIGNAL ;
    PORT
      LAYER M1 ;
        RECT 11.79 23.62 21.47 27.74 ;
    END
  END TSV_TM_428_333[8]
  PIN TSV_TM_428_333[90]
    DIRECTION OUTPUT ;
    USE SIGNAL ;
    PORT
      LAYER M1 ;
        RECT 11.79 251.58 21.47 255.7 ;
    END
  END TSV_TM_428_333[90]
  PIN TSV_TM_428_333[91]
    DIRECTION OUTPUT ;
    USE SIGNAL ;
    PORT
      LAYER M1 ;
        RECT 0.67 251.58 10.35 255.7 ;
    END
  END TSV_TM_428_333[91]
  PIN TSV_TM_428_333[92]
    DIRECTION OUTPUT ;
    USE SIGNAL ;
    PORT
      LAYER M1 ;
        RECT 11.79 257.14 21.47 261.26 ;
    END
  END TSV_TM_428_333[92]
  PIN TSV_TM_428_333[93]
    DIRECTION OUTPUT ;
    USE SIGNAL ;
    PORT
      LAYER M1 ;
        RECT 0.67 257.14 10.35 261.26 ;
    END
  END TSV_TM_428_333[93]
  PIN TSV_TM_428_333[94]
    DIRECTION OUTPUT ;
    USE SIGNAL ;
    PORT
      LAYER M1 ;
        RECT 11.79 262.7 21.47 266.82 ;
    END
  END TSV_TM_428_333[94]
  PIN TSV_TM_428_333[95]
    DIRECTION OUTPUT ;
    USE SIGNAL ;
    PORT
      LAYER M1 ;
        RECT 0.67 262.7 10.35 266.82 ;
    END
  END TSV_TM_428_333[95]
  PIN TSV_TM_428_333[9]
    DIRECTION OUTPUT ;
    USE SIGNAL ;
    PORT
      LAYER M1 ;
        RECT 0.67 23.62 10.35 27.74 ;
    END
  END TSV_TM_428_333[9]
  PIN TSV_TM_204_89_ASIC[0]
    DIRECTION INPUT ;
    USE SIGNAL ;
    PORT
      LAYER M4 ;
        RECT 87.505 0.71 92.2 0.81 ;
    END
  END TSV_TM_204_89_ASIC[0]
  PIN TSV_TM_204_89_ASIC[100]
    DIRECTION INPUT ;
    USE SIGNAL ;
    PORT
      LAYER M4 ;
        RECT 87.505 278.71 92.2 278.81 ;
    END
  END TSV_TM_204_89_ASIC[100]
  PIN TSV_TM_204_89_ASIC[101]
    DIRECTION INPUT ;
    USE SIGNAL ;
    PORT
      LAYER M4 ;
        RECT 87.505 278.91 92.2 279.01 ;
    END
  END TSV_TM_204_89_ASIC[101]
  PIN TSV_TM_204_89_ASIC[102]
    DIRECTION INPUT ;
    USE SIGNAL ;
    PORT
      LAYER M4 ;
        RECT 90.865 284.31 92.2 284.41 ;
        RECT 87.505 284.27 90.965 284.37 ;
    END
  END TSV_TM_204_89_ASIC[102]
  PIN TSV_TM_204_89_ASIC[103]
    DIRECTION INPUT ;
    USE SIGNAL ;
    PORT
      LAYER M4 ;
        RECT 90.665 284.51 92.2 284.61 ;
        RECT 87.505 284.47 90.765 284.57 ;
    END
  END TSV_TM_204_89_ASIC[103]
  PIN TSV_TM_204_89_ASIC[104]
    DIRECTION INPUT ;
    USE SIGNAL ;
    PORT
      LAYER M4 ;
        RECT 90.865 289.91 92.2 290.01 ;
        RECT 87.505 289.83 90.965 289.93 ;
    END
  END TSV_TM_204_89_ASIC[104]
  PIN TSV_TM_204_89_ASIC[105]
    DIRECTION INPUT ;
    USE SIGNAL ;
    PORT
      LAYER M4 ;
        RECT 90.665 290.11 92.2 290.21 ;
        RECT 87.505 290.03 90.765 290.13 ;
    END
  END TSV_TM_204_89_ASIC[105]
  PIN TSV_TM_204_89_ASIC[106]
    DIRECTION INPUT ;
    USE SIGNAL ;
    PORT
      LAYER M4 ;
        RECT 90.865 295.11 92.2 295.21 ;
        RECT 87.505 295.19 90.965 295.29 ;
    END
  END TSV_TM_204_89_ASIC[106]
  PIN TSV_TM_204_89_ASIC[107]
    DIRECTION INPUT ;
    USE SIGNAL ;
    PORT
      LAYER M4 ;
        RECT 90.665 294.91 92.2 295.01 ;
        RECT 87.505 294.99 90.765 295.09 ;
    END
  END TSV_TM_204_89_ASIC[107]
  PIN TSV_TM_204_89_ASIC[108]
    DIRECTION INPUT ;
    USE SIGNAL ;
    PORT
      LAYER M4 ;
        RECT 91.065 289.71 92.2 289.81 ;
        RECT 87.505 289.63 91.165 289.73 ;
    END
  END TSV_TM_204_89_ASIC[108]
  PIN TSV_TM_204_89_ASIC[109]
    DIRECTION INPUT ;
    USE SIGNAL ;
    PORT
      LAYER M4 ;
        RECT 91.265 289.51 92.2 289.61 ;
        RECT 87.505 289.43 91.365 289.53 ;
    END
  END TSV_TM_204_89_ASIC[109]
  PIN TSV_TM_204_89_ASIC[10]
    DIRECTION INPUT ;
    USE SIGNAL ;
    PORT
      LAYER M4 ;
        RECT 87.505 28.51 92.2 28.61 ;
    END
  END TSV_TM_204_89_ASIC[10]
  PIN TSV_TM_204_89_ASIC[110]
    DIRECTION INPUT ;
    USE SIGNAL ;
    PORT
      LAYER M4 ;
        RECT 91.065 284.11 92.2 284.21 ;
        RECT 87.505 284.07 91.165 284.17 ;
    END
  END TSV_TM_204_89_ASIC[110]
  PIN TSV_TM_204_89_ASIC[111]
    DIRECTION INPUT ;
    USE SIGNAL ;
    PORT
      LAYER M4 ;
        RECT 91.265 283.91 92.2 284.01 ;
        RECT 87.505 283.87 91.365 283.97 ;
    END
  END TSV_TM_204_89_ASIC[111]
  PIN TSV_TM_204_89_ASIC[112]
    DIRECTION INPUT ;
    USE SIGNAL ;
    PORT
      LAYER M4 ;
        RECT 87.505 278.51 92.2 278.61 ;
    END
  END TSV_TM_204_89_ASIC[112]
  PIN TSV_TM_204_89_ASIC[113]
    DIRECTION INPUT ;
    USE SIGNAL ;
    PORT
      LAYER M4 ;
        RECT 87.505 278.31 92.2 278.41 ;
    END
  END TSV_TM_204_89_ASIC[113]
  PIN TSV_TM_204_89_ASIC[114]
    DIRECTION INPUT ;
    USE SIGNAL ;
    PORT
      LAYER M4 ;
        RECT 90.865 272.91 92.2 273.01 ;
        RECT 87.505 272.95 90.965 273.05 ;
    END
  END TSV_TM_204_89_ASIC[114]
  PIN TSV_TM_204_89_ASIC[115]
    DIRECTION INPUT ;
    USE SIGNAL ;
    PORT
      LAYER M4 ;
        RECT 90.665 272.71 92.2 272.81 ;
        RECT 87.505 272.75 90.765 272.85 ;
    END
  END TSV_TM_204_89_ASIC[115]
  PIN TSV_TM_204_89_ASIC[11]
    DIRECTION INPUT ;
    USE SIGNAL ;
    PORT
      LAYER M4 ;
        RECT 87.505 28.71 92.2 28.81 ;
    END
  END TSV_TM_204_89_ASIC[11]
  PIN TSV_TM_204_89_ASIC[12]
    DIRECTION INPUT ;
    USE SIGNAL ;
    PORT
      LAYER M4 ;
        RECT 90.865 34.11 92.2 34.21 ;
        RECT 87.505 34.07 90.965 34.17 ;
    END
  END TSV_TM_204_89_ASIC[12]
  PIN TSV_TM_204_89_ASIC[13]
    DIRECTION INPUT ;
    USE SIGNAL ;
    PORT
      LAYER M4 ;
        RECT 90.665 34.31 92.2 34.41 ;
        RECT 87.505 34.27 90.765 34.37 ;
    END
  END TSV_TM_204_89_ASIC[13]
  PIN TSV_TM_204_89_ASIC[14]
    DIRECTION INPUT ;
    USE SIGNAL ;
    PORT
      LAYER M4 ;
        RECT 90.865 39.71 92.2 39.81 ;
        RECT 87.505 39.63 90.965 39.73 ;
    END
  END TSV_TM_204_89_ASIC[14]
  PIN TSV_TM_204_89_ASIC[15]
    DIRECTION INPUT ;
    USE SIGNAL ;
    PORT
      LAYER M4 ;
        RECT 90.665 39.91 92.2 40.01 ;
        RECT 87.505 39.83 90.765 39.93 ;
    END
  END TSV_TM_204_89_ASIC[15]
  PIN TSV_TM_204_89_ASIC[16]
    DIRECTION INPUT ;
    USE SIGNAL ;
    PORT
      LAYER M4 ;
        RECT 91.065 45.11 92.2 45.21 ;
        RECT 87.505 45.19 91.165 45.29 ;
    END
  END TSV_TM_204_89_ASIC[16]
  PIN TSV_TM_204_89_ASIC[17]
    DIRECTION INPUT ;
    USE SIGNAL ;
    PORT
      LAYER M4 ;
        RECT 91.265 45.31 92.2 45.41 ;
        RECT 87.505 45.39 91.365 45.49 ;
    END
  END TSV_TM_204_89_ASIC[17]
  PIN TSV_TM_204_89_ASIC[18]
    DIRECTION INPUT ;
    USE SIGNAL ;
    PORT
      LAYER M4 ;
        RECT 91.065 50.71 92.2 50.81 ;
        RECT 87.505 50.75 91.165 50.85 ;
    END
  END TSV_TM_204_89_ASIC[18]
  PIN TSV_TM_204_89_ASIC[19]
    DIRECTION INPUT ;
    USE SIGNAL ;
    PORT
      LAYER M4 ;
        RECT 91.265 50.91 92.2 51.01 ;
        RECT 87.505 50.95 91.365 51.05 ;
    END
  END TSV_TM_204_89_ASIC[19]
  PIN TSV_TM_204_89_ASIC[1]
    DIRECTION INPUT ;
    USE SIGNAL ;
    PORT
      LAYER M4 ;
        RECT 87.505 0.91 92.2 1.01 ;
    END
  END TSV_TM_204_89_ASIC[1]
  PIN TSV_TM_204_89_ASIC[20]
    DIRECTION INPUT ;
    USE SIGNAL ;
    PORT
      LAYER M4 ;
        RECT 87.505 56.31 92.2 56.41 ;
    END
  END TSV_TM_204_89_ASIC[20]
  PIN TSV_TM_204_89_ASIC[21]
    DIRECTION INPUT ;
    USE SIGNAL ;
    PORT
      LAYER M4 ;
        RECT 87.505 56.51 92.2 56.61 ;
    END
  END TSV_TM_204_89_ASIC[21]
  PIN TSV_TM_204_89_ASIC[22]
    DIRECTION INPUT ;
    USE SIGNAL ;
    PORT
      LAYER M4 ;
        RECT 90.865 61.91 92.2 62.01 ;
        RECT 87.505 61.87 90.965 61.97 ;
    END
  END TSV_TM_204_89_ASIC[22]
  PIN TSV_TM_204_89_ASIC[23]
    DIRECTION INPUT ;
    USE SIGNAL ;
    PORT
      LAYER M4 ;
        RECT 90.665 62.11 92.2 62.21 ;
        RECT 87.505 62.07 90.765 62.17 ;
    END
  END TSV_TM_204_89_ASIC[23]
  PIN TSV_TM_204_89_ASIC[24]
    DIRECTION INPUT ;
    USE SIGNAL ;
    PORT
      LAYER M4 ;
        RECT 90.865 67.51 92.2 67.61 ;
        RECT 87.505 67.43 90.965 67.53 ;
    END
  END TSV_TM_204_89_ASIC[24]
  PIN TSV_TM_204_89_ASIC[25]
    DIRECTION INPUT ;
    USE SIGNAL ;
    PORT
      LAYER M4 ;
        RECT 90.665 67.71 92.2 67.81 ;
        RECT 87.505 67.63 90.765 67.73 ;
    END
  END TSV_TM_204_89_ASIC[25]
  PIN TSV_TM_204_89_ASIC[26]
    DIRECTION INPUT ;
    USE SIGNAL ;
    PORT
      LAYER M4 ;
        RECT 91.065 72.91 92.2 73.01 ;
        RECT 87.505 72.99 91.165 73.09 ;
    END
  END TSV_TM_204_89_ASIC[26]
  PIN TSV_TM_204_89_ASIC[27]
    DIRECTION INPUT ;
    USE SIGNAL ;
    PORT
      LAYER M4 ;
        RECT 91.265 73.11 92.2 73.21 ;
        RECT 87.505 73.19 91.365 73.29 ;
    END
  END TSV_TM_204_89_ASIC[27]
  PIN TSV_TM_204_89_ASIC[28]
    DIRECTION INPUT ;
    USE SIGNAL ;
    PORT
      LAYER M4 ;
        RECT 91.065 78.51 92.2 78.61 ;
        RECT 87.505 78.55 91.165 78.65 ;
    END
  END TSV_TM_204_89_ASIC[28]
  PIN TSV_TM_204_89_ASIC[29]
    DIRECTION INPUT ;
    USE SIGNAL ;
    PORT
      LAYER M4 ;
        RECT 91.265 78.71 92.2 78.81 ;
        RECT 87.505 78.75 91.365 78.85 ;
    END
  END TSV_TM_204_89_ASIC[29]
  PIN TSV_TM_204_89_ASIC[2]
    DIRECTION INPUT ;
    USE SIGNAL ;
    PORT
      LAYER M4 ;
        RECT 91 6.31 92.2 6.41 ;
        RECT 87.505 6.27 91.1 6.37 ;
    END
  END TSV_TM_204_89_ASIC[2]
  PIN TSV_TM_204_89_ASIC[30]
    DIRECTION INPUT ;
    USE SIGNAL ;
    PORT
      LAYER M4 ;
        RECT 87.505 84.11 92.2 84.21 ;
    END
  END TSV_TM_204_89_ASIC[30]
  PIN TSV_TM_204_89_ASIC[31]
    DIRECTION INPUT ;
    USE SIGNAL ;
    PORT
      LAYER M4 ;
        RECT 87.505 84.31 92.2 84.41 ;
    END
  END TSV_TM_204_89_ASIC[31]
  PIN TSV_TM_204_89_ASIC[32]
    DIRECTION INPUT ;
    USE SIGNAL ;
    PORT
      LAYER M4 ;
        RECT 90.865 89.71 92.2 89.81 ;
        RECT 87.505 89.67 90.965 89.77 ;
    END
  END TSV_TM_204_89_ASIC[32]
  PIN TSV_TM_204_89_ASIC[33]
    DIRECTION INPUT ;
    USE SIGNAL ;
    PORT
      LAYER M4 ;
        RECT 90.665 89.91 92.2 90.01 ;
        RECT 87.505 89.87 90.765 89.97 ;
    END
  END TSV_TM_204_89_ASIC[33]
  PIN TSV_TM_204_89_ASIC[34]
    DIRECTION INPUT ;
    USE SIGNAL ;
    PORT
      LAYER M4 ;
        RECT 90.865 95.31 92.2 95.41 ;
        RECT 87.505 95.23 90.965 95.33 ;
    END
  END TSV_TM_204_89_ASIC[34]
  PIN TSV_TM_204_89_ASIC[35]
    DIRECTION INPUT ;
    USE SIGNAL ;
    PORT
      LAYER M4 ;
        RECT 90.665 95.51 92.2 95.61 ;
        RECT 87.505 95.43 90.765 95.53 ;
    END
  END TSV_TM_204_89_ASIC[35]
  PIN TSV_TM_204_89_ASIC[36]
    DIRECTION INPUT ;
    USE SIGNAL ;
    PORT
      LAYER M4 ;
        RECT 91.065 100.71 92.2 100.81 ;
        RECT 87.505 100.79 91.165 100.89 ;
    END
  END TSV_TM_204_89_ASIC[36]
  PIN TSV_TM_204_89_ASIC[37]
    DIRECTION INPUT ;
    USE SIGNAL ;
    PORT
      LAYER M4 ;
        RECT 91.265 100.91 92.2 101.01 ;
        RECT 87.505 100.99 91.365 101.09 ;
    END
  END TSV_TM_204_89_ASIC[37]
  PIN TSV_TM_204_89_ASIC[38]
    DIRECTION INPUT ;
    USE SIGNAL ;
    PORT
      LAYER M4 ;
        RECT 91.065 106.31 92.2 106.41 ;
        RECT 87.505 106.35 91.165 106.45 ;
    END
  END TSV_TM_204_89_ASIC[38]
  PIN TSV_TM_204_89_ASIC[39]
    DIRECTION INPUT ;
    USE SIGNAL ;
    PORT
      LAYER M4 ;
        RECT 91.265 106.51 92.2 106.61 ;
        RECT 87.505 106.55 91.365 106.65 ;
    END
  END TSV_TM_204_89_ASIC[39]
  PIN TSV_TM_204_89_ASIC[3]
    DIRECTION INPUT ;
    USE SIGNAL ;
    PORT
      LAYER M4 ;
        RECT 90.8 6.51 92.2 6.61 ;
        RECT 87.505 6.47 90.9 6.57 ;
    END
  END TSV_TM_204_89_ASIC[3]
  PIN TSV_TM_204_89_ASIC[40]
    DIRECTION INPUT ;
    USE SIGNAL ;
    PORT
      LAYER M4 ;
        RECT 87.505 111.91 92.2 112.01 ;
    END
  END TSV_TM_204_89_ASIC[40]
  PIN TSV_TM_204_89_ASIC[41]
    DIRECTION INPUT ;
    USE SIGNAL ;
    PORT
      LAYER M4 ;
        RECT 87.505 112.11 92.2 112.21 ;
    END
  END TSV_TM_204_89_ASIC[41]
  PIN TSV_TM_204_89_ASIC[42]
    DIRECTION INPUT ;
    USE SIGNAL ;
    PORT
      LAYER M4 ;
        RECT 90.865 117.51 92.2 117.61 ;
        RECT 87.505 117.47 90.965 117.57 ;
    END
  END TSV_TM_204_89_ASIC[42]
  PIN TSV_TM_204_89_ASIC[43]
    DIRECTION INPUT ;
    USE SIGNAL ;
    PORT
      LAYER M4 ;
        RECT 90.665 117.71 92.2 117.81 ;
        RECT 87.505 117.67 90.765 117.77 ;
    END
  END TSV_TM_204_89_ASIC[43]
  PIN TSV_TM_204_89_ASIC[44]
    DIRECTION INPUT ;
    USE SIGNAL ;
    PORT
      LAYER M4 ;
        RECT 90.865 123.11 92.2 123.21 ;
        RECT 87.505 123.03 90.965 123.13 ;
    END
  END TSV_TM_204_89_ASIC[44]
  PIN TSV_TM_204_89_ASIC[45]
    DIRECTION INPUT ;
    USE SIGNAL ;
    PORT
      LAYER M4 ;
        RECT 90.665 123.31 92.2 123.41 ;
        RECT 87.505 123.23 90.765 123.33 ;
    END
  END TSV_TM_204_89_ASIC[45]
  PIN TSV_TM_204_89_ASIC[46]
    DIRECTION INPUT ;
    USE SIGNAL ;
    PORT
      LAYER M4 ;
        RECT 91.065 128.51 92.2 128.61 ;
        RECT 87.505 128.59 91.165 128.69 ;
    END
  END TSV_TM_204_89_ASIC[46]
  PIN TSV_TM_204_89_ASIC[47]
    DIRECTION INPUT ;
    USE SIGNAL ;
    PORT
      LAYER M4 ;
        RECT 91.265 128.71 92.2 128.81 ;
        RECT 87.505 128.79 91.365 128.89 ;
    END
  END TSV_TM_204_89_ASIC[47]
  PIN TSV_TM_204_89_ASIC[48]
    DIRECTION INPUT ;
    USE SIGNAL ;
    PORT
      LAYER M4 ;
        RECT 91.065 134.11 92.2 134.21 ;
        RECT 87.505 134.15 91.165 134.25 ;
    END
  END TSV_TM_204_89_ASIC[48]
  PIN TSV_TM_204_89_ASIC[49]
    DIRECTION INPUT ;
    USE SIGNAL ;
    PORT
      LAYER M4 ;
        RECT 91.265 134.31 92.2 134.41 ;
        RECT 87.505 134.35 91.365 134.45 ;
    END
  END TSV_TM_204_89_ASIC[49]
  PIN TSV_TM_204_89_ASIC[4]
    DIRECTION INPUT ;
    USE SIGNAL ;
    PORT
      LAYER M4 ;
        RECT 91 11.91 92.2 12.01 ;
        RECT 87.505 11.83 91.1 11.93 ;
    END
  END TSV_TM_204_89_ASIC[4]
  PIN TSV_TM_204_89_ASIC[50]
    DIRECTION INPUT ;
    USE SIGNAL ;
    PORT
      LAYER M4 ;
        RECT 87.505 139.71 92.2 139.81 ;
    END
  END TSV_TM_204_89_ASIC[50]
  PIN TSV_TM_204_89_ASIC[51]
    DIRECTION INPUT ;
    USE SIGNAL ;
    PORT
      LAYER M4 ;
        RECT 87.505 139.91 92.2 140.01 ;
    END
  END TSV_TM_204_89_ASIC[51]
  PIN TSV_TM_204_89_ASIC[52]
    DIRECTION INPUT ;
    USE SIGNAL ;
    PORT
      LAYER M4 ;
        RECT 90.865 145.31 92.2 145.41 ;
        RECT 87.505 145.27 90.965 145.37 ;
    END
  END TSV_TM_204_89_ASIC[52]
  PIN TSV_TM_204_89_ASIC[53]
    DIRECTION INPUT ;
    USE SIGNAL ;
    PORT
      LAYER M4 ;
        RECT 90.665 145.51 92.2 145.61 ;
        RECT 87.505 145.47 90.765 145.57 ;
    END
  END TSV_TM_204_89_ASIC[53]
  PIN TSV_TM_204_89_ASIC[54]
    DIRECTION INPUT ;
    USE SIGNAL ;
    PORT
      LAYER M4 ;
        RECT 90.865 150.91 92.2 151.01 ;
        RECT 87.505 150.83 90.965 150.93 ;
    END
  END TSV_TM_204_89_ASIC[54]
  PIN TSV_TM_204_89_ASIC[55]
    DIRECTION INPUT ;
    USE SIGNAL ;
    PORT
      LAYER M4 ;
        RECT 90.665 151.11 92.2 151.21 ;
        RECT 87.505 151.03 90.765 151.13 ;
    END
  END TSV_TM_204_89_ASIC[55]
  PIN TSV_TM_204_89_ASIC[56]
    DIRECTION INPUT ;
    USE SIGNAL ;
    PORT
      LAYER M4 ;
        RECT 91.065 156.31 92.2 156.41 ;
        RECT 87.505 156.39 91.165 156.49 ;
    END
  END TSV_TM_204_89_ASIC[56]
  PIN TSV_TM_204_89_ASIC[57]
    DIRECTION INPUT ;
    USE SIGNAL ;
    PORT
      LAYER M4 ;
        RECT 91.265 156.51 92.2 156.61 ;
        RECT 87.505 156.59 91.365 156.69 ;
    END
  END TSV_TM_204_89_ASIC[57]
  PIN TSV_TM_204_89_ASIC[58]
    DIRECTION INPUT ;
    USE SIGNAL ;
    PORT
      LAYER M4 ;
        RECT 91.065 161.91 92.2 162.01 ;
        RECT 87.505 161.95 91.165 162.05 ;
    END
  END TSV_TM_204_89_ASIC[58]
  PIN TSV_TM_204_89_ASIC[59]
    DIRECTION INPUT ;
    USE SIGNAL ;
    PORT
      LAYER M4 ;
        RECT 91.265 162.11 92.2 162.21 ;
        RECT 87.505 162.15 91.365 162.25 ;
    END
  END TSV_TM_204_89_ASIC[59]
  PIN TSV_TM_204_89_ASIC[5]
    DIRECTION INPUT ;
    USE SIGNAL ;
    PORT
      LAYER M4 ;
        RECT 90.8 12.11 92.2 12.21 ;
        RECT 87.505 12.03 90.9 12.13 ;
    END
  END TSV_TM_204_89_ASIC[5]
  PIN TSV_TM_204_89_ASIC[60]
    DIRECTION INPUT ;
    USE SIGNAL ;
    PORT
      LAYER M4 ;
        RECT 87.505 167.51 92.2 167.61 ;
    END
  END TSV_TM_204_89_ASIC[60]
  PIN TSV_TM_204_89_ASIC[61]
    DIRECTION INPUT ;
    USE SIGNAL ;
    PORT
      LAYER M4 ;
        RECT 87.505 167.71 92.2 167.81 ;
    END
  END TSV_TM_204_89_ASIC[61]
  PIN TSV_TM_204_89_ASIC[62]
    DIRECTION INPUT ;
    USE SIGNAL ;
    PORT
      LAYER M4 ;
        RECT 90.865 173.11 92.2 173.21 ;
        RECT 87.505 173.07 90.965 173.17 ;
    END
  END TSV_TM_204_89_ASIC[62]
  PIN TSV_TM_204_89_ASIC[63]
    DIRECTION INPUT ;
    USE SIGNAL ;
    PORT
      LAYER M4 ;
        RECT 90.665 173.31 92.2 173.41 ;
        RECT 87.505 173.27 90.765 173.37 ;
    END
  END TSV_TM_204_89_ASIC[63]
  PIN TSV_TM_204_89_ASIC[64]
    DIRECTION INPUT ;
    USE SIGNAL ;
    PORT
      LAYER M4 ;
        RECT 90.865 178.71 92.2 178.81 ;
        RECT 87.505 178.63 90.965 178.73 ;
    END
  END TSV_TM_204_89_ASIC[64]
  PIN TSV_TM_204_89_ASIC[65]
    DIRECTION INPUT ;
    USE SIGNAL ;
    PORT
      LAYER M4 ;
        RECT 90.665 178.91 92.2 179.01 ;
        RECT 87.505 178.83 90.765 178.93 ;
    END
  END TSV_TM_204_89_ASIC[65]
  PIN TSV_TM_204_89_ASIC[66]
    DIRECTION INPUT ;
    USE SIGNAL ;
    PORT
      LAYER M4 ;
        RECT 91.065 184.11 92.2 184.21 ;
        RECT 87.505 184.19 91.165 184.29 ;
    END
  END TSV_TM_204_89_ASIC[66]
  PIN TSV_TM_204_89_ASIC[67]
    DIRECTION INPUT ;
    USE SIGNAL ;
    PORT
      LAYER M4 ;
        RECT 91.265 184.31 92.2 184.41 ;
        RECT 87.505 184.39 91.365 184.49 ;
    END
  END TSV_TM_204_89_ASIC[67]
  PIN TSV_TM_204_89_ASIC[68]
    DIRECTION INPUT ;
    USE SIGNAL ;
    PORT
      LAYER M4 ;
        RECT 91.065 189.71 92.2 189.81 ;
        RECT 87.505 189.75 91.165 189.85 ;
    END
  END TSV_TM_204_89_ASIC[68]
  PIN TSV_TM_204_89_ASIC[69]
    DIRECTION INPUT ;
    USE SIGNAL ;
    PORT
      LAYER M4 ;
        RECT 91.265 189.91 92.2 190.01 ;
        RECT 87.505 189.95 91.365 190.05 ;
    END
  END TSV_TM_204_89_ASIC[69]
  PIN TSV_TM_204_89_ASIC[6]
    DIRECTION INPUT ;
    USE SIGNAL ;
    PORT
      LAYER M4 ;
        RECT 91.2 17.31 92.2 17.41 ;
        RECT 87.505 17.39 91.3 17.49 ;
    END
  END TSV_TM_204_89_ASIC[6]
  PIN TSV_TM_204_89_ASIC[70]
    DIRECTION INPUT ;
    USE SIGNAL ;
    PORT
      LAYER M4 ;
        RECT 87.505 195.31 92.2 195.41 ;
    END
  END TSV_TM_204_89_ASIC[70]
  PIN TSV_TM_204_89_ASIC[71]
    DIRECTION INPUT ;
    USE SIGNAL ;
    PORT
      LAYER M4 ;
        RECT 87.505 195.51 92.2 195.61 ;
    END
  END TSV_TM_204_89_ASIC[71]
  PIN TSV_TM_204_89_ASIC[72]
    DIRECTION INPUT ;
    USE SIGNAL ;
    PORT
      LAYER M4 ;
        RECT 90.865 200.91 92.2 201.01 ;
        RECT 87.505 200.87 90.965 200.97 ;
    END
  END TSV_TM_204_89_ASIC[72]
  PIN TSV_TM_204_89_ASIC[73]
    DIRECTION INPUT ;
    USE SIGNAL ;
    PORT
      LAYER M4 ;
        RECT 90.665 201.11 92.2 201.21 ;
        RECT 87.505 201.07 90.765 201.17 ;
    END
  END TSV_TM_204_89_ASIC[73]
  PIN TSV_TM_204_89_ASIC[74]
    DIRECTION INPUT ;
    USE SIGNAL ;
    PORT
      LAYER M4 ;
        RECT 90.865 206.51 92.2 206.61 ;
        RECT 87.505 206.43 90.965 206.53 ;
    END
  END TSV_TM_204_89_ASIC[74]
  PIN TSV_TM_204_89_ASIC[75]
    DIRECTION INPUT ;
    USE SIGNAL ;
    PORT
      LAYER M4 ;
        RECT 90.665 206.71 92.2 206.81 ;
        RECT 87.505 206.63 90.765 206.73 ;
    END
  END TSV_TM_204_89_ASIC[75]
  PIN TSV_TM_204_89_ASIC[76]
    DIRECTION INPUT ;
    USE SIGNAL ;
    PORT
      LAYER M4 ;
        RECT 91.065 211.91 92.2 212.01 ;
        RECT 87.505 211.99 91.165 212.09 ;
    END
  END TSV_TM_204_89_ASIC[76]
  PIN TSV_TM_204_89_ASIC[77]
    DIRECTION INPUT ;
    USE SIGNAL ;
    PORT
      LAYER M4 ;
        RECT 91.265 212.11 92.2 212.21 ;
        RECT 87.505 212.19 91.365 212.29 ;
    END
  END TSV_TM_204_89_ASIC[77]
  PIN TSV_TM_204_89_ASIC[78]
    DIRECTION INPUT ;
    USE SIGNAL ;
    PORT
      LAYER M4 ;
        RECT 91.065 217.51 92.2 217.61 ;
        RECT 87.505 217.55 91.165 217.65 ;
    END
  END TSV_TM_204_89_ASIC[78]
  PIN TSV_TM_204_89_ASIC[79]
    DIRECTION INPUT ;
    USE SIGNAL ;
    PORT
      LAYER M4 ;
        RECT 91.265 217.71 92.2 217.81 ;
        RECT 87.505 217.75 91.365 217.85 ;
    END
  END TSV_TM_204_89_ASIC[79]
  PIN TSV_TM_204_89_ASIC[7]
    DIRECTION INPUT ;
    USE SIGNAL ;
    PORT
      LAYER M4 ;
        RECT 91.4 17.51 92.2 17.61 ;
        RECT 87.505 17.59 91.5 17.69 ;
    END
  END TSV_TM_204_89_ASIC[7]
  PIN TSV_TM_204_89_ASIC[80]
    DIRECTION INPUT ;
    USE SIGNAL ;
    PORT
      LAYER M4 ;
        RECT 87.505 223.11 92.2 223.21 ;
    END
  END TSV_TM_204_89_ASIC[80]
  PIN TSV_TM_204_89_ASIC[81]
    DIRECTION INPUT ;
    USE SIGNAL ;
    PORT
      LAYER M4 ;
        RECT 87.505 223.31 92.2 223.41 ;
    END
  END TSV_TM_204_89_ASIC[81]
  PIN TSV_TM_204_89_ASIC[82]
    DIRECTION INPUT ;
    USE SIGNAL ;
    PORT
      LAYER M4 ;
        RECT 90.865 228.71 92.2 228.81 ;
        RECT 87.505 228.67 90.965 228.77 ;
    END
  END TSV_TM_204_89_ASIC[82]
  PIN TSV_TM_204_89_ASIC[83]
    DIRECTION INPUT ;
    USE SIGNAL ;
    PORT
      LAYER M4 ;
        RECT 90.665 228.91 92.2 229.01 ;
        RECT 87.505 228.87 90.765 228.97 ;
    END
  END TSV_TM_204_89_ASIC[83]
  PIN TSV_TM_204_89_ASIC[84]
    DIRECTION INPUT ;
    USE SIGNAL ;
    PORT
      LAYER M4 ;
        RECT 90.865 234.31 92.2 234.41 ;
        RECT 87.505 234.23 90.965 234.33 ;
    END
  END TSV_TM_204_89_ASIC[84]
  PIN TSV_TM_204_89_ASIC[85]
    DIRECTION INPUT ;
    USE SIGNAL ;
    PORT
      LAYER M4 ;
        RECT 90.665 234.51 92.2 234.61 ;
        RECT 87.505 234.43 90.765 234.53 ;
    END
  END TSV_TM_204_89_ASIC[85]
  PIN TSV_TM_204_89_ASIC[86]
    DIRECTION INPUT ;
    USE SIGNAL ;
    PORT
      LAYER M4 ;
        RECT 91.065 239.71 92.2 239.81 ;
        RECT 87.505 239.79 91.165 239.89 ;
    END
  END TSV_TM_204_89_ASIC[86]
  PIN TSV_TM_204_89_ASIC[87]
    DIRECTION INPUT ;
    USE SIGNAL ;
    PORT
      LAYER M4 ;
        RECT 91.265 239.91 92.2 240.01 ;
        RECT 87.505 239.99 91.365 240.09 ;
    END
  END TSV_TM_204_89_ASIC[87]
  PIN TSV_TM_204_89_ASIC[88]
    DIRECTION INPUT ;
    USE SIGNAL ;
    PORT
      LAYER M4 ;
        RECT 91.065 245.31 92.2 245.41 ;
        RECT 87.505 245.35 91.165 245.45 ;
    END
  END TSV_TM_204_89_ASIC[88]
  PIN TSV_TM_204_89_ASIC[89]
    DIRECTION INPUT ;
    USE SIGNAL ;
    PORT
      LAYER M4 ;
        RECT 91.265 245.51 92.2 245.61 ;
        RECT 87.505 245.55 91.365 245.65 ;
    END
  END TSV_TM_204_89_ASIC[89]
  PIN TSV_TM_204_89_ASIC[8]
    DIRECTION INPUT ;
    USE SIGNAL ;
    PORT
      LAYER M4 ;
        RECT 91.065 22.91 92.2 23.01 ;
        RECT 87.505 22.95 91.165 23.05 ;
    END
  END TSV_TM_204_89_ASIC[8]
  PIN TSV_TM_204_89_ASIC[90]
    DIRECTION INPUT ;
    USE SIGNAL ;
    PORT
      LAYER M4 ;
        RECT 87.505 250.91 92.2 251.01 ;
    END
  END TSV_TM_204_89_ASIC[90]
  PIN TSV_TM_204_89_ASIC[91]
    DIRECTION INPUT ;
    USE SIGNAL ;
    PORT
      LAYER M4 ;
        RECT 87.505 251.11 92.2 251.21 ;
    END
  END TSV_TM_204_89_ASIC[91]
  PIN TSV_TM_204_89_ASIC[92]
    DIRECTION INPUT ;
    USE SIGNAL ;
    PORT
      LAYER M4 ;
        RECT 90.865 256.51 92.2 256.61 ;
        RECT 87.505 256.47 90.965 256.57 ;
    END
  END TSV_TM_204_89_ASIC[92]
  PIN TSV_TM_204_89_ASIC[93]
    DIRECTION INPUT ;
    USE SIGNAL ;
    PORT
      LAYER M4 ;
        RECT 90.665 256.71 92.2 256.81 ;
        RECT 87.505 256.67 90.765 256.77 ;
    END
  END TSV_TM_204_89_ASIC[93]
  PIN TSV_TM_204_89_ASIC[94]
    DIRECTION INPUT ;
    USE SIGNAL ;
    PORT
      LAYER M4 ;
        RECT 90.865 262.11 92.2 262.21 ;
        RECT 87.505 262.03 90.965 262.13 ;
    END
  END TSV_TM_204_89_ASIC[94]
  PIN TSV_TM_204_89_ASIC[95]
    DIRECTION INPUT ;
    USE SIGNAL ;
    PORT
      LAYER M4 ;
        RECT 90.665 262.31 92.2 262.41 ;
        RECT 87.505 262.23 90.765 262.33 ;
    END
  END TSV_TM_204_89_ASIC[95]
  PIN TSV_TM_204_89_ASIC[96]
    DIRECTION INPUT ;
    USE SIGNAL ;
    PORT
      LAYER M4 ;
        RECT 91.065 267.51 92.2 267.61 ;
        RECT 87.505 267.59 91.165 267.69 ;
    END
  END TSV_TM_204_89_ASIC[96]
  PIN TSV_TM_204_89_ASIC[97]
    DIRECTION INPUT ;
    USE SIGNAL ;
    PORT
      LAYER M4 ;
        RECT 91.265 267.71 92.2 267.81 ;
        RECT 87.505 267.79 91.365 267.89 ;
    END
  END TSV_TM_204_89_ASIC[97]
  PIN TSV_TM_204_89_ASIC[98]
    DIRECTION INPUT ;
    USE SIGNAL ;
    PORT
      LAYER M4 ;
        RECT 91.065 273.11 92.2 273.21 ;
        RECT 87.505 273.15 91.165 273.25 ;
    END
  END TSV_TM_204_89_ASIC[98]
  PIN TSV_TM_204_89_ASIC[99]
    DIRECTION INPUT ;
    USE SIGNAL ;
    PORT
      LAYER M4 ;
        RECT 91.265 273.31 92.2 273.41 ;
        RECT 87.505 273.35 91.365 273.45 ;
    END
  END TSV_TM_204_89_ASIC[99]
  PIN TSV_TM_204_89_ASIC[9]
    DIRECTION INPUT ;
    USE SIGNAL ;
    PORT
      LAYER M4 ;
        RECT 91.265 23.11 92.2 23.21 ;
        RECT 87.505 23.15 91.365 23.25 ;
    END
  END TSV_TM_204_89_ASIC[9]
  PIN TSV_TM_428_333_ASIC[0]
    DIRECTION INPUT ;
    USE SIGNAL ;
    PORT
      LAYER M4 ;
        RECT 91.4 5.91 92.2 6.01 ;
        RECT 87.505 5.87 91.5 5.97 ;
    END
  END TSV_TM_428_333_ASIC[0]
  PIN TSV_TM_428_333_ASIC[10]
    DIRECTION INPUT ;
    USE SIGNAL ;
    PORT
      LAYER M4 ;
        RECT 91.265 33.71 92.2 33.81 ;
        RECT 87.505 33.67 91.365 33.77 ;
    END
  END TSV_TM_428_333_ASIC[10]
  PIN TSV_TM_428_333_ASIC[11]
    DIRECTION INPUT ;
    USE SIGNAL ;
    PORT
      LAYER M4 ;
        RECT 91.065 33.91 92.2 34.01 ;
        RECT 87.505 33.87 91.165 33.97 ;
    END
  END TSV_TM_428_333_ASIC[11]
  PIN TSV_TM_428_333_ASIC[12]
    DIRECTION INPUT ;
    USE SIGNAL ;
    PORT
      LAYER M4 ;
        RECT 91.265 39.31 92.2 39.41 ;
        RECT 87.505 39.23 91.365 39.33 ;
    END
  END TSV_TM_428_333_ASIC[12]
  PIN TSV_TM_428_333_ASIC[13]
    DIRECTION INPUT ;
    USE SIGNAL ;
    PORT
      LAYER M4 ;
        RECT 91.065 39.51 92.2 39.61 ;
        RECT 87.505 39.43 91.165 39.53 ;
    END
  END TSV_TM_428_333_ASIC[13]
  PIN TSV_TM_428_333_ASIC[14]
    DIRECTION INPUT ;
    USE SIGNAL ;
    PORT
      LAYER M4 ;
        RECT 90.665 44.71 92.2 44.81 ;
        RECT 87.505 44.79 90.765 44.89 ;
    END
  END TSV_TM_428_333_ASIC[14]
  PIN TSV_TM_428_333_ASIC[15]
    DIRECTION INPUT ;
    USE SIGNAL ;
    PORT
      LAYER M4 ;
        RECT 90.865 44.91 92.2 45.01 ;
        RECT 87.505 44.99 90.965 45.09 ;
    END
  END TSV_TM_428_333_ASIC[15]
  PIN TSV_TM_428_333_ASIC[16]
    DIRECTION INPUT ;
    USE SIGNAL ;
    PORT
      LAYER M4 ;
        RECT 90.665 50.31 92.2 50.41 ;
        RECT 87.505 50.35 90.765 50.45 ;
    END
  END TSV_TM_428_333_ASIC[16]
  PIN TSV_TM_428_333_ASIC[17]
    DIRECTION INPUT ;
    USE SIGNAL ;
    PORT
      LAYER M4 ;
        RECT 90.865 50.51 92.2 50.61 ;
        RECT 87.505 50.55 90.965 50.65 ;
    END
  END TSV_TM_428_333_ASIC[17]
  PIN TSV_TM_428_333_ASIC[18]
    DIRECTION INPUT ;
    USE SIGNAL ;
    PORT
      LAYER M4 ;
        RECT 87.505 55.91 92.2 56.01 ;
    END
  END TSV_TM_428_333_ASIC[18]
  PIN TSV_TM_428_333_ASIC[19]
    DIRECTION INPUT ;
    USE SIGNAL ;
    PORT
      LAYER M4 ;
        RECT 87.505 56.11 92.2 56.21 ;
    END
  END TSV_TM_428_333_ASIC[19]
  PIN TSV_TM_428_333_ASIC[1]
    DIRECTION INPUT ;
    USE SIGNAL ;
    PORT
      LAYER M4 ;
        RECT 91.2 6.11 92.2 6.21 ;
        RECT 87.505 6.07 91.3 6.17 ;
    END
  END TSV_TM_428_333_ASIC[1]
  PIN TSV_TM_428_333_ASIC[20]
    DIRECTION INPUT ;
    USE SIGNAL ;
    PORT
      LAYER M4 ;
        RECT 91.265 61.51 92.2 61.61 ;
        RECT 87.505 61.47 91.365 61.57 ;
    END
  END TSV_TM_428_333_ASIC[20]
  PIN TSV_TM_428_333_ASIC[21]
    DIRECTION INPUT ;
    USE SIGNAL ;
    PORT
      LAYER M4 ;
        RECT 91.065 61.71 92.2 61.81 ;
        RECT 87.505 61.67 91.165 61.77 ;
    END
  END TSV_TM_428_333_ASIC[21]
  PIN TSV_TM_428_333_ASIC[22]
    DIRECTION INPUT ;
    USE SIGNAL ;
    PORT
      LAYER M4 ;
        RECT 91.265 67.11 92.2 67.21 ;
        RECT 87.505 67.03 91.365 67.13 ;
    END
  END TSV_TM_428_333_ASIC[22]
  PIN TSV_TM_428_333_ASIC[23]
    DIRECTION INPUT ;
    USE SIGNAL ;
    PORT
      LAYER M4 ;
        RECT 91.065 67.31 92.2 67.41 ;
        RECT 87.505 67.23 91.165 67.33 ;
    END
  END TSV_TM_428_333_ASIC[23]
  PIN TSV_TM_428_333_ASIC[24]
    DIRECTION INPUT ;
    USE SIGNAL ;
    PORT
      LAYER M4 ;
        RECT 90.665 72.51 92.2 72.61 ;
        RECT 87.505 72.59 90.765 72.69 ;
    END
  END TSV_TM_428_333_ASIC[24]
  PIN TSV_TM_428_333_ASIC[25]
    DIRECTION INPUT ;
    USE SIGNAL ;
    PORT
      LAYER M4 ;
        RECT 90.865 72.71 92.2 72.81 ;
        RECT 87.505 72.79 90.965 72.89 ;
    END
  END TSV_TM_428_333_ASIC[25]
  PIN TSV_TM_428_333_ASIC[26]
    DIRECTION INPUT ;
    USE SIGNAL ;
    PORT
      LAYER M4 ;
        RECT 90.665 78.11 92.2 78.21 ;
        RECT 87.505 78.15 90.765 78.25 ;
    END
  END TSV_TM_428_333_ASIC[26]
  PIN TSV_TM_428_333_ASIC[27]
    DIRECTION INPUT ;
    USE SIGNAL ;
    PORT
      LAYER M4 ;
        RECT 90.865 78.31 92.2 78.41 ;
        RECT 87.505 78.35 90.965 78.45 ;
    END
  END TSV_TM_428_333_ASIC[27]
  PIN TSV_TM_428_333_ASIC[28]
    DIRECTION INPUT ;
    USE SIGNAL ;
    PORT
      LAYER M4 ;
        RECT 87.505 83.71 92.2 83.81 ;
    END
  END TSV_TM_428_333_ASIC[28]
  PIN TSV_TM_428_333_ASIC[29]
    DIRECTION INPUT ;
    USE SIGNAL ;
    PORT
      LAYER M4 ;
        RECT 87.505 83.91 92.2 84.01 ;
    END
  END TSV_TM_428_333_ASIC[29]
  PIN TSV_TM_428_333_ASIC[2]
    DIRECTION INPUT ;
    USE SIGNAL ;
    PORT
      LAYER M4 ;
        RECT 91.4 11.51 92.2 11.61 ;
        RECT 87.505 11.43 91.5 11.53 ;
    END
  END TSV_TM_428_333_ASIC[2]
  PIN TSV_TM_428_333_ASIC[30]
    DIRECTION INPUT ;
    USE SIGNAL ;
    PORT
      LAYER M4 ;
        RECT 91.265 89.31 92.2 89.41 ;
        RECT 87.505 89.27 91.365 89.37 ;
    END
  END TSV_TM_428_333_ASIC[30]
  PIN TSV_TM_428_333_ASIC[31]
    DIRECTION INPUT ;
    USE SIGNAL ;
    PORT
      LAYER M4 ;
        RECT 91.065 89.51 92.2 89.61 ;
        RECT 87.505 89.47 91.165 89.57 ;
    END
  END TSV_TM_428_333_ASIC[31]
  PIN TSV_TM_428_333_ASIC[32]
    DIRECTION INPUT ;
    USE SIGNAL ;
    PORT
      LAYER M4 ;
        RECT 91.265 94.91 92.2 95.01 ;
        RECT 87.505 94.83 91.365 94.93 ;
    END
  END TSV_TM_428_333_ASIC[32]
  PIN TSV_TM_428_333_ASIC[33]
    DIRECTION INPUT ;
    USE SIGNAL ;
    PORT
      LAYER M4 ;
        RECT 91.065 95.11 92.2 95.21 ;
        RECT 87.505 95.03 91.165 95.13 ;
    END
  END TSV_TM_428_333_ASIC[33]
  PIN TSV_TM_428_333_ASIC[34]
    DIRECTION INPUT ;
    USE SIGNAL ;
    PORT
      LAYER M4 ;
        RECT 90.665 100.31 92.2 100.41 ;
        RECT 87.505 100.39 90.765 100.49 ;
    END
  END TSV_TM_428_333_ASIC[34]
  PIN TSV_TM_428_333_ASIC[35]
    DIRECTION INPUT ;
    USE SIGNAL ;
    PORT
      LAYER M4 ;
        RECT 90.865 100.51 92.2 100.61 ;
        RECT 87.505 100.59 90.965 100.69 ;
    END
  END TSV_TM_428_333_ASIC[35]
  PIN TSV_TM_428_333_ASIC[36]
    DIRECTION INPUT ;
    USE SIGNAL ;
    PORT
      LAYER M4 ;
        RECT 90.665 105.91 92.2 106.01 ;
        RECT 87.505 105.95 90.765 106.05 ;
    END
  END TSV_TM_428_333_ASIC[36]
  PIN TSV_TM_428_333_ASIC[37]
    DIRECTION INPUT ;
    USE SIGNAL ;
    PORT
      LAYER M4 ;
        RECT 90.865 106.11 92.2 106.21 ;
        RECT 87.505 106.15 90.965 106.25 ;
    END
  END TSV_TM_428_333_ASIC[37]
  PIN TSV_TM_428_333_ASIC[38]
    DIRECTION INPUT ;
    USE SIGNAL ;
    PORT
      LAYER M4 ;
        RECT 87.505 111.51 92.2 111.61 ;
    END
  END TSV_TM_428_333_ASIC[38]
  PIN TSV_TM_428_333_ASIC[39]
    DIRECTION INPUT ;
    USE SIGNAL ;
    PORT
      LAYER M4 ;
        RECT 87.505 111.71 92.2 111.81 ;
    END
  END TSV_TM_428_333_ASIC[39]
  PIN TSV_TM_428_333_ASIC[3]
    DIRECTION INPUT ;
    USE SIGNAL ;
    PORT
      LAYER M4 ;
        RECT 91.2 11.71 92.2 11.81 ;
        RECT 87.505 11.63 91.3 11.73 ;
    END
  END TSV_TM_428_333_ASIC[3]
  PIN TSV_TM_428_333_ASIC[40]
    DIRECTION INPUT ;
    USE SIGNAL ;
    PORT
      LAYER M4 ;
        RECT 91.265 117.11 92.2 117.21 ;
        RECT 87.505 117.07 91.365 117.17 ;
    END
  END TSV_TM_428_333_ASIC[40]
  PIN TSV_TM_428_333_ASIC[41]
    DIRECTION INPUT ;
    USE SIGNAL ;
    PORT
      LAYER M4 ;
        RECT 91.065 117.31 92.2 117.41 ;
        RECT 87.505 117.27 91.165 117.37 ;
    END
  END TSV_TM_428_333_ASIC[41]
  PIN TSV_TM_428_333_ASIC[42]
    DIRECTION INPUT ;
    USE SIGNAL ;
    PORT
      LAYER M4 ;
        RECT 91.265 122.71 92.2 122.81 ;
        RECT 87.505 122.63 91.365 122.73 ;
    END
  END TSV_TM_428_333_ASIC[42]
  PIN TSV_TM_428_333_ASIC[43]
    DIRECTION INPUT ;
    USE SIGNAL ;
    PORT
      LAYER M4 ;
        RECT 91.065 122.91 92.2 123.01 ;
        RECT 87.505 122.83 91.165 122.93 ;
    END
  END TSV_TM_428_333_ASIC[43]
  PIN TSV_TM_428_333_ASIC[44]
    DIRECTION INPUT ;
    USE SIGNAL ;
    PORT
      LAYER M4 ;
        RECT 90.665 128.11 92.2 128.21 ;
        RECT 87.505 128.19 90.765 128.29 ;
    END
  END TSV_TM_428_333_ASIC[44]
  PIN TSV_TM_428_333_ASIC[45]
    DIRECTION INPUT ;
    USE SIGNAL ;
    PORT
      LAYER M4 ;
        RECT 90.865 128.31 92.2 128.41 ;
        RECT 87.505 128.39 90.965 128.49 ;
    END
  END TSV_TM_428_333_ASIC[45]
  PIN TSV_TM_428_333_ASIC[46]
    DIRECTION INPUT ;
    USE SIGNAL ;
    PORT
      LAYER M4 ;
        RECT 90.665 133.71 92.2 133.81 ;
        RECT 87.505 133.75 90.765 133.85 ;
    END
  END TSV_TM_428_333_ASIC[46]
  PIN TSV_TM_428_333_ASIC[47]
    DIRECTION INPUT ;
    USE SIGNAL ;
    PORT
      LAYER M4 ;
        RECT 90.865 133.91 92.2 134.01 ;
        RECT 87.505 133.95 90.965 134.05 ;
    END
  END TSV_TM_428_333_ASIC[47]
  PIN TSV_TM_428_333_ASIC[48]
    DIRECTION INPUT ;
    USE SIGNAL ;
    PORT
      LAYER M4 ;
        RECT 87.505 139.31 92.2 139.41 ;
    END
  END TSV_TM_428_333_ASIC[48]
  PIN TSV_TM_428_333_ASIC[49]
    DIRECTION INPUT ;
    USE SIGNAL ;
    PORT
      LAYER M4 ;
        RECT 87.505 139.51 92.2 139.61 ;
    END
  END TSV_TM_428_333_ASIC[49]
  PIN TSV_TM_428_333_ASIC[4]
    DIRECTION INPUT ;
    USE SIGNAL ;
    PORT
      LAYER M4 ;
        RECT 90.8 16.91 92.2 17.01 ;
        RECT 87.505 16.99 90.9 17.09 ;
    END
  END TSV_TM_428_333_ASIC[4]
  PIN TSV_TM_428_333_ASIC[50]
    DIRECTION INPUT ;
    USE SIGNAL ;
    PORT
      LAYER M4 ;
        RECT 91.265 144.91 92.2 145.01 ;
        RECT 87.505 144.87 91.365 144.97 ;
    END
  END TSV_TM_428_333_ASIC[50]
  PIN TSV_TM_428_333_ASIC[51]
    DIRECTION INPUT ;
    USE SIGNAL ;
    PORT
      LAYER M4 ;
        RECT 91.065 145.11 92.2 145.21 ;
        RECT 87.505 145.07 91.165 145.17 ;
    END
  END TSV_TM_428_333_ASIC[51]
  PIN TSV_TM_428_333_ASIC[52]
    DIRECTION INPUT ;
    USE SIGNAL ;
    PORT
      LAYER M4 ;
        RECT 91.265 150.51 92.2 150.61 ;
        RECT 87.505 150.43 91.365 150.53 ;
    END
  END TSV_TM_428_333_ASIC[52]
  PIN TSV_TM_428_333_ASIC[53]
    DIRECTION INPUT ;
    USE SIGNAL ;
    PORT
      LAYER M4 ;
        RECT 91.065 150.71 92.2 150.81 ;
        RECT 87.505 150.63 91.165 150.73 ;
    END
  END TSV_TM_428_333_ASIC[53]
  PIN TSV_TM_428_333_ASIC[54]
    DIRECTION INPUT ;
    USE SIGNAL ;
    PORT
      LAYER M4 ;
        RECT 90.665 155.91 92.2 156.01 ;
        RECT 87.505 155.99 90.765 156.09 ;
    END
  END TSV_TM_428_333_ASIC[54]
  PIN TSV_TM_428_333_ASIC[55]
    DIRECTION INPUT ;
    USE SIGNAL ;
    PORT
      LAYER M4 ;
        RECT 90.865 156.11 92.2 156.21 ;
        RECT 87.505 156.19 90.965 156.29 ;
    END
  END TSV_TM_428_333_ASIC[55]
  PIN TSV_TM_428_333_ASIC[56]
    DIRECTION INPUT ;
    USE SIGNAL ;
    PORT
      LAYER M4 ;
        RECT 90.665 161.51 92.2 161.61 ;
        RECT 87.505 161.55 90.765 161.65 ;
    END
  END TSV_TM_428_333_ASIC[56]
  PIN TSV_TM_428_333_ASIC[57]
    DIRECTION INPUT ;
    USE SIGNAL ;
    PORT
      LAYER M4 ;
        RECT 90.865 161.71 92.2 161.81 ;
        RECT 87.505 161.75 90.965 161.85 ;
    END
  END TSV_TM_428_333_ASIC[57]
  PIN TSV_TM_428_333_ASIC[58]
    DIRECTION INPUT ;
    USE SIGNAL ;
    PORT
      LAYER M4 ;
        RECT 87.505 167.11 92.2 167.21 ;
    END
  END TSV_TM_428_333_ASIC[58]
  PIN TSV_TM_428_333_ASIC[59]
    DIRECTION INPUT ;
    USE SIGNAL ;
    PORT
      LAYER M4 ;
        RECT 87.505 167.31 92.2 167.41 ;
    END
  END TSV_TM_428_333_ASIC[59]
  PIN TSV_TM_428_333_ASIC[5]
    DIRECTION INPUT ;
    USE SIGNAL ;
    PORT
      LAYER M4 ;
        RECT 91 17.11 92.2 17.21 ;
        RECT 87.505 17.19 91.1 17.29 ;
    END
  END TSV_TM_428_333_ASIC[5]
  PIN TSV_TM_428_333_ASIC[60]
    DIRECTION INPUT ;
    USE SIGNAL ;
    PORT
      LAYER M4 ;
        RECT 91.265 172.71 92.2 172.81 ;
        RECT 87.505 172.67 91.365 172.77 ;
    END
  END TSV_TM_428_333_ASIC[60]
  PIN TSV_TM_428_333_ASIC[61]
    DIRECTION INPUT ;
    USE SIGNAL ;
    PORT
      LAYER M4 ;
        RECT 91.065 172.91 92.2 173.01 ;
        RECT 87.505 172.87 91.165 172.97 ;
    END
  END TSV_TM_428_333_ASIC[61]
  PIN TSV_TM_428_333_ASIC[62]
    DIRECTION INPUT ;
    USE SIGNAL ;
    PORT
      LAYER M4 ;
        RECT 91.265 178.31 92.2 178.41 ;
        RECT 87.505 178.23 91.365 178.33 ;
    END
  END TSV_TM_428_333_ASIC[62]
  PIN TSV_TM_428_333_ASIC[63]
    DIRECTION INPUT ;
    USE SIGNAL ;
    PORT
      LAYER M4 ;
        RECT 91.065 178.51 92.2 178.61 ;
        RECT 87.505 178.43 91.165 178.53 ;
    END
  END TSV_TM_428_333_ASIC[63]
  PIN TSV_TM_428_333_ASIC[64]
    DIRECTION INPUT ;
    USE SIGNAL ;
    PORT
      LAYER M4 ;
        RECT 90.665 183.71 92.2 183.81 ;
        RECT 87.505 183.79 90.765 183.89 ;
    END
  END TSV_TM_428_333_ASIC[64]
  PIN TSV_TM_428_333_ASIC[65]
    DIRECTION INPUT ;
    USE SIGNAL ;
    PORT
      LAYER M4 ;
        RECT 90.865 183.91 92.2 184.01 ;
        RECT 87.505 183.99 90.965 184.09 ;
    END
  END TSV_TM_428_333_ASIC[65]
  PIN TSV_TM_428_333_ASIC[66]
    DIRECTION INPUT ;
    USE SIGNAL ;
    PORT
      LAYER M4 ;
        RECT 90.665 189.31 92.2 189.41 ;
        RECT 87.505 189.35 90.765 189.45 ;
    END
  END TSV_TM_428_333_ASIC[66]
  PIN TSV_TM_428_333_ASIC[67]
    DIRECTION INPUT ;
    USE SIGNAL ;
    PORT
      LAYER M4 ;
        RECT 90.865 189.51 92.2 189.61 ;
        RECT 87.505 189.55 90.965 189.65 ;
    END
  END TSV_TM_428_333_ASIC[67]
  PIN TSV_TM_428_333_ASIC[68]
    DIRECTION INPUT ;
    USE SIGNAL ;
    PORT
      LAYER M4 ;
        RECT 87.505 194.91 92.2 195.01 ;
    END
  END TSV_TM_428_333_ASIC[68]
  PIN TSV_TM_428_333_ASIC[69]
    DIRECTION INPUT ;
    USE SIGNAL ;
    PORT
      LAYER M4 ;
        RECT 87.505 195.11 92.2 195.21 ;
    END
  END TSV_TM_428_333_ASIC[69]
  PIN TSV_TM_428_333_ASIC[6]
    DIRECTION INPUT ;
    USE SIGNAL ;
    PORT
      LAYER M4 ;
        RECT 90.665 22.51 92.2 22.61 ;
        RECT 87.505 22.55 90.765 22.65 ;
    END
  END TSV_TM_428_333_ASIC[6]
  PIN TSV_TM_428_333_ASIC[70]
    DIRECTION INPUT ;
    USE SIGNAL ;
    PORT
      LAYER M4 ;
        RECT 91.265 200.51 92.2 200.61 ;
        RECT 87.505 200.47 91.365 200.57 ;
    END
  END TSV_TM_428_333_ASIC[70]
  PIN TSV_TM_428_333_ASIC[71]
    DIRECTION INPUT ;
    USE SIGNAL ;
    PORT
      LAYER M4 ;
        RECT 91.065 200.71 92.2 200.81 ;
        RECT 87.505 200.67 91.165 200.77 ;
    END
  END TSV_TM_428_333_ASIC[71]
  PIN TSV_TM_428_333_ASIC[72]
    DIRECTION INPUT ;
    USE SIGNAL ;
    PORT
      LAYER M4 ;
        RECT 91.265 206.11 92.2 206.21 ;
        RECT 87.505 206.03 91.365 206.13 ;
    END
  END TSV_TM_428_333_ASIC[72]
  PIN TSV_TM_428_333_ASIC[73]
    DIRECTION INPUT ;
    USE SIGNAL ;
    PORT
      LAYER M4 ;
        RECT 91.065 206.31 92.2 206.41 ;
        RECT 87.505 206.23 91.165 206.33 ;
    END
  END TSV_TM_428_333_ASIC[73]
  PIN TSV_TM_428_333_ASIC[74]
    DIRECTION INPUT ;
    USE SIGNAL ;
    PORT
      LAYER M4 ;
        RECT 90.665 211.51 92.2 211.61 ;
        RECT 87.505 211.59 90.765 211.69 ;
    END
  END TSV_TM_428_333_ASIC[74]
  PIN TSV_TM_428_333_ASIC[75]
    DIRECTION INPUT ;
    USE SIGNAL ;
    PORT
      LAYER M4 ;
        RECT 90.865 211.71 92.2 211.81 ;
        RECT 87.505 211.79 90.965 211.89 ;
    END
  END TSV_TM_428_333_ASIC[75]
  PIN TSV_TM_428_333_ASIC[76]
    DIRECTION INPUT ;
    USE SIGNAL ;
    PORT
      LAYER M4 ;
        RECT 90.665 217.11 92.2 217.21 ;
        RECT 87.505 217.15 90.765 217.25 ;
    END
  END TSV_TM_428_333_ASIC[76]
  PIN TSV_TM_428_333_ASIC[77]
    DIRECTION INPUT ;
    USE SIGNAL ;
    PORT
      LAYER M4 ;
        RECT 90.865 217.31 92.2 217.41 ;
        RECT 87.505 217.35 90.965 217.45 ;
    END
  END TSV_TM_428_333_ASIC[77]
  PIN TSV_TM_428_333_ASIC[78]
    DIRECTION INPUT ;
    USE SIGNAL ;
    PORT
      LAYER M4 ;
        RECT 87.505 222.71 92.2 222.81 ;
    END
  END TSV_TM_428_333_ASIC[78]
  PIN TSV_TM_428_333_ASIC[79]
    DIRECTION INPUT ;
    USE SIGNAL ;
    PORT
      LAYER M4 ;
        RECT 87.505 222.91 92.2 223.01 ;
    END
  END TSV_TM_428_333_ASIC[79]
  PIN TSV_TM_428_333_ASIC[7]
    DIRECTION INPUT ;
    USE SIGNAL ;
    PORT
      LAYER M4 ;
        RECT 90.865 22.71 92.2 22.81 ;
        RECT 87.505 22.75 90.965 22.85 ;
    END
  END TSV_TM_428_333_ASIC[7]
  PIN TSV_TM_428_333_ASIC[80]
    DIRECTION INPUT ;
    USE SIGNAL ;
    PORT
      LAYER M4 ;
        RECT 91.265 228.31 92.2 228.41 ;
        RECT 87.505 228.27 91.365 228.37 ;
    END
  END TSV_TM_428_333_ASIC[80]
  PIN TSV_TM_428_333_ASIC[81]
    DIRECTION INPUT ;
    USE SIGNAL ;
    PORT
      LAYER M4 ;
        RECT 91.065 228.51 92.2 228.61 ;
        RECT 87.505 228.47 91.165 228.57 ;
    END
  END TSV_TM_428_333_ASIC[81]
  PIN TSV_TM_428_333_ASIC[82]
    DIRECTION INPUT ;
    USE SIGNAL ;
    PORT
      LAYER M4 ;
        RECT 91.265 233.91 92.2 234.01 ;
        RECT 87.505 233.83 91.365 233.93 ;
    END
  END TSV_TM_428_333_ASIC[82]
  PIN TSV_TM_428_333_ASIC[83]
    DIRECTION INPUT ;
    USE SIGNAL ;
    PORT
      LAYER M4 ;
        RECT 91.065 234.11 92.2 234.21 ;
        RECT 87.505 234.03 91.165 234.13 ;
    END
  END TSV_TM_428_333_ASIC[83]
  PIN TSV_TM_428_333_ASIC[84]
    DIRECTION INPUT ;
    USE SIGNAL ;
    PORT
      LAYER M4 ;
        RECT 90.665 239.31 92.2 239.41 ;
        RECT 87.505 239.39 90.765 239.49 ;
    END
  END TSV_TM_428_333_ASIC[84]
  PIN TSV_TM_428_333_ASIC[85]
    DIRECTION INPUT ;
    USE SIGNAL ;
    PORT
      LAYER M4 ;
        RECT 90.865 239.51 92.2 239.61 ;
        RECT 87.505 239.59 90.965 239.69 ;
    END
  END TSV_TM_428_333_ASIC[85]
  PIN TSV_TM_428_333_ASIC[86]
    DIRECTION INPUT ;
    USE SIGNAL ;
    PORT
      LAYER M4 ;
        RECT 90.665 244.91 92.2 245.01 ;
        RECT 87.505 244.95 90.765 245.05 ;
    END
  END TSV_TM_428_333_ASIC[86]
  PIN TSV_TM_428_333_ASIC[87]
    DIRECTION INPUT ;
    USE SIGNAL ;
    PORT
      LAYER M4 ;
        RECT 90.865 245.11 92.2 245.21 ;
        RECT 87.505 245.15 90.965 245.25 ;
    END
  END TSV_TM_428_333_ASIC[87]
  PIN TSV_TM_428_333_ASIC[88]
    DIRECTION INPUT ;
    USE SIGNAL ;
    PORT
      LAYER M4 ;
        RECT 87.505 250.51 92.2 250.61 ;
    END
  END TSV_TM_428_333_ASIC[88]
  PIN TSV_TM_428_333_ASIC[89]
    DIRECTION INPUT ;
    USE SIGNAL ;
    PORT
      LAYER M4 ;
        RECT 87.505 250.71 92.2 250.81 ;
    END
  END TSV_TM_428_333_ASIC[89]
  PIN TSV_TM_428_333_ASIC[8]
    DIRECTION INPUT ;
    USE SIGNAL ;
    PORT
      LAYER M4 ;
        RECT 87.505 28.11 92.2 28.21 ;
    END
  END TSV_TM_428_333_ASIC[8]
  PIN TSV_TM_428_333_ASIC[90]
    DIRECTION INPUT ;
    USE SIGNAL ;
    PORT
      LAYER M4 ;
        RECT 91.265 256.11 92.2 256.21 ;
        RECT 87.505 256.07 91.365 256.17 ;
    END
  END TSV_TM_428_333_ASIC[90]
  PIN TSV_TM_428_333_ASIC[91]
    DIRECTION INPUT ;
    USE SIGNAL ;
    PORT
      LAYER M4 ;
        RECT 91.065 256.31 92.2 256.41 ;
        RECT 87.505 256.27 91.165 256.37 ;
    END
  END TSV_TM_428_333_ASIC[91]
  PIN TSV_TM_428_333_ASIC[92]
    DIRECTION INPUT ;
    USE SIGNAL ;
    PORT
      LAYER M4 ;
        RECT 91.265 261.71 92.2 261.81 ;
        RECT 87.505 261.63 91.365 261.73 ;
    END
  END TSV_TM_428_333_ASIC[92]
  PIN TSV_TM_428_333_ASIC[93]
    DIRECTION INPUT ;
    USE SIGNAL ;
    PORT
      LAYER M4 ;
        RECT 91.065 261.91 92.2 262.01 ;
        RECT 87.505 261.83 91.165 261.93 ;
    END
  END TSV_TM_428_333_ASIC[93]
  PIN TSV_TM_428_333_ASIC[94]
    DIRECTION INPUT ;
    USE SIGNAL ;
    PORT
      LAYER M4 ;
        RECT 90.665 267.11 92.2 267.21 ;
        RECT 87.505 267.19 90.765 267.29 ;
    END
  END TSV_TM_428_333_ASIC[94]
  PIN TSV_TM_428_333_ASIC[95]
    DIRECTION INPUT ;
    USE SIGNAL ;
    PORT
      LAYER M4 ;
        RECT 90.865 267.31 92.2 267.41 ;
        RECT 87.505 267.39 90.965 267.49 ;
    END
  END TSV_TM_428_333_ASIC[95]
  PIN TSV_TM_428_333_ASIC[9]
    DIRECTION INPUT ;
    USE SIGNAL ;
    PORT
      LAYER M4 ;
        RECT 87.505 28.31 92.2 28.41 ;
    END
  END TSV_TM_428_333_ASIC[9]
  PIN ls_en_asic
    DIRECTION INPUT ;
    USE SIGNAL ;
    PORT
      LAYER M4 ;
        RECT 87.485 147.95 92.2 148.05 ;
    END
  END ls_en_asic
  PIN vss
    DIRECTION INOUT ;
    USE GROUND ;
    SHAPE RING ;
    PORT
      LAYER M4 ;
        RECT 87.485 148.15 92.2 148.25 ;
    END
    PORT
      LAYER M4 ;
        RECT 87.485 147.75 92.2 147.85 ;
    END
    PORT
      LAYER M7 ;
        RECT 43.485 0 44.485 296 ;
    END
    PORT
      LAYER M7 ;
        RECT 47.685 0 48.685 296 ;
    END
  END vss
  PIN vdd
    DIRECTION INOUT ;
    USE POWER ;
    SHAPE RING ;
    PORT
      LAYER M7 ;
        RECT 44.785 0 45.785 296 ;
    END
    PORT
      LAYER M7 ;
        RECT 46.385 0 47.385 296 ;
    END
  END vdd
  PIN vdd_array
    DIRECTION INOUT ;
    USE SIGNAL ;
    PORT
      LAYER M7 ;
        RECT 25.385 0 26.785 296 ;
    END
    PORT
      LAYER M7 ;
        RECT 27.085 0 28.485 296 ;
    END
    PORT
      LAYER M7 ;
        RECT 28.785 0 30.185 296 ;
    END
    PORT
      LAYER M7 ;
        RECT 36.155 0 37.555 296 ;
    END
    PORT
      LAYER M7 ;
        RECT 37.855 0 39.255 296 ;
    END
    PORT
      LAYER M7 ;
        RECT 52.915 0 54.315 296 ;
    END
    PORT
      LAYER M7 ;
        RECT 54.615 0 56.015 296 ;
    END
    PORT
      LAYER M7 ;
        RECT 61.985 0 63.385 296 ;
    END
    PORT
      LAYER M7 ;
        RECT 63.685 0 65.085 296 ;
    END
    PORT
      LAYER M7 ;
        RECT 65.385 0 66.785 296 ;
    END
  END vdd_array
  PIN vss_array
    DIRECTION INOUT ;
    USE SIGNAL ;
    PORT
      LAYER M7 ;
        RECT 30.765 0 32.165 296 ;
    END
    PORT
      LAYER M7 ;
        RECT 32.465 0 33.865 296 ;
    END
    PORT
      LAYER M7 ;
        RECT 34.165 0 35.565 296 ;
    END
    PORT
      LAYER M7 ;
        RECT 39.755 0 41.155 296 ;
    END
    PORT
      LAYER M7 ;
        RECT 41.455 0 42.855 296 ;
    END
    PORT
      LAYER M7 ;
        RECT 49.315 0 50.715 296 ;
    END
    PORT
      LAYER M7 ;
        RECT 51.015 0 52.415 296 ;
    END
    PORT
      LAYER M7 ;
        RECT 56.605 0 58.005 296 ;
    END
    PORT
      LAYER M7 ;
        RECT 58.305 0 59.705 296 ;
    END
    PORT
      LAYER M7 ;
        RECT 60.005 0 61.405 296 ;
    END
  END vss_array
  OBS
    LAYER M1 ;
      RECT 42.89 0.07 49.28 0.62 ;
      RECT 67.8 0.07 68.03 0.61 ;
      RECT 24.14 0.07 24.37 0.61 ;
      RECT 24.14 0.07 68.03 0.3 ;
      RECT 24.14 295.7 68.03 295.93 ;
      RECT 67.8 295.39 68.03 295.93 ;
      RECT 42.89 295.38 49.28 295.93 ;
      RECT 24.14 295.39 24.37 295.93 ;
    LAYER M1 SPACING 0.05 ;
      RECT 0 294.725 92.2 296 ;
      RECT 91.605 0 92.2 296 ;
      RECT 80.485 0 81.715 296 ;
      RECT 21.575 0 70.595 296 ;
      RECT 10.455 0 11.685 296 ;
      RECT 0 0 0.565 296 ;
      RECT 0 289.165 92.2 290.395 ;
      RECT 0 283.605 92.2 284.835 ;
      RECT 0 278.045 92.2 279.275 ;
      RECT 0 272.485 92.2 273.715 ;
      RECT 0 266.925 92.2 268.155 ;
      RECT 0 261.365 92.2 262.595 ;
      RECT 0 255.805 92.2 257.035 ;
      RECT 0 250.245 92.2 251.475 ;
      RECT 0 244.685 92.2 245.915 ;
      RECT 0 239.125 92.2 240.355 ;
      RECT 0 233.565 92.2 234.795 ;
      RECT 0 228.005 92.2 229.235 ;
      RECT 0 222.445 92.2 223.675 ;
      RECT 0 216.885 92.2 218.115 ;
      RECT 0 211.325 92.2 212.555 ;
      RECT 0 205.765 92.2 206.995 ;
      RECT 0 200.205 92.2 201.435 ;
      RECT 0 194.645 92.2 195.875 ;
      RECT 0 189.085 92.2 190.315 ;
      RECT 0 183.525 92.2 184.755 ;
      RECT 0 177.965 92.2 179.195 ;
      RECT 0 172.405 92.2 173.635 ;
      RECT 0 166.845 92.2 168.075 ;
      RECT 0 161.285 92.2 162.515 ;
      RECT 0 155.725 92.2 156.955 ;
      RECT 0 150.165 92.2 151.395 ;
      RECT 0 144.605 92.2 145.835 ;
      RECT 0 139.045 92.2 140.275 ;
      RECT 0 133.485 92.2 134.715 ;
      RECT 0 127.925 92.2 129.155 ;
      RECT 0 122.365 92.2 123.595 ;
      RECT 0 116.805 92.2 118.035 ;
      RECT 0 111.245 92.2 112.475 ;
      RECT 0 105.685 92.2 106.915 ;
      RECT 0 100.125 92.2 101.355 ;
      RECT 0 94.565 92.2 95.795 ;
      RECT 0 89.005 92.2 90.235 ;
      RECT 0 83.445 92.2 84.675 ;
      RECT 0 77.885 92.2 79.115 ;
      RECT 0 72.325 92.2 73.555 ;
      RECT 0 66.765 92.2 67.995 ;
      RECT 0 61.205 92.2 62.435 ;
      RECT 0 55.645 92.2 56.875 ;
      RECT 0 50.085 92.2 51.315 ;
      RECT 0 44.525 92.2 45.755 ;
      RECT 0 38.965 92.2 40.195 ;
      RECT 0 33.405 92.2 34.635 ;
      RECT 0 27.845 92.2 29.075 ;
      RECT 0 22.285 92.2 23.515 ;
      RECT 0 16.725 92.2 17.955 ;
      RECT 0 11.165 92.2 12.395 ;
      RECT 0 5.605 92.2 6.835 ;
      RECT 0 0 92.2 1.275 ;
    LAYER M2 ;
      RECT 47.6 0.07 48.1 0.62 ;
      RECT 47.6 295.38 48.1 295.93 ;
      RECT 44.07 0.07 44.57 0.62 ;
      RECT 44.07 295.38 44.57 295.93 ;
    LAYER M2 SPACING 0.05 ;
      RECT 0 294.725 92.2 296 ;
      RECT 91.605 0 92.2 296 ;
      RECT 86.61 294.435 86.68 296 ;
      RECT 80.485 0 81.715 296 ;
      RECT 75.565 294.645 75.635 296 ;
      RECT 75.425 294.645 75.495 296 ;
      RECT 21.575 0 70.595 296 ;
      RECT 16.655 294.645 16.725 296 ;
      RECT 16.515 294.645 16.585 296 ;
      RECT 10.455 0 11.685 296 ;
      RECT 5.535 294.435 5.605 296 ;
      RECT 5.395 294.435 5.465 296 ;
      RECT 0 0 0.565 296 ;
      RECT 75.565 289.165 75.635 290.725 ;
      RECT 75.425 289.165 75.495 290.725 ;
      RECT 16.655 289.085 16.725 290.42 ;
      RECT 16.515 289.085 16.585 290.42 ;
      RECT 0 289.165 92.2 290.395 ;
      RECT 86.62 288.875 86.69 290.395 ;
      RECT 75.45 289.085 75.52 290.395 ;
      RECT 5.535 288.875 5.605 290.395 ;
      RECT 5.395 288.875 5.465 290.395 ;
      RECT 75.565 283.605 75.635 285.165 ;
      RECT 75.425 283.605 75.495 285.165 ;
      RECT 16.655 283.605 16.725 285.165 ;
      RECT 16.515 283.605 16.585 285.165 ;
      RECT 5.535 283.315 5.605 284.84 ;
      RECT 5.395 283.315 5.465 284.84 ;
      RECT 0 283.605 92.2 284.835 ;
      RECT 86.685 283.315 86.755 284.835 ;
      RECT 86.545 283.315 86.615 284.835 ;
      RECT 75.46 283.525 75.53 284.835 ;
      RECT 16.61 283.525 16.68 284.835 ;
      RECT 16.655 278.045 16.725 279.605 ;
      RECT 16.515 278.045 16.585 279.605 ;
      RECT 86.685 277.755 86.755 279.29 ;
      RECT 86.545 277.755 86.615 279.29 ;
      RECT 0 278.045 92.2 279.275 ;
      RECT 75.565 277.965 75.635 279.275 ;
      RECT 75.425 277.965 75.495 279.275 ;
      RECT 16.62 277.965 16.69 279.275 ;
      RECT 5.45 277.755 5.52 279.275 ;
      RECT 16.63 272.405 16.7 274.105 ;
      RECT 0 272.485 92.2 273.715 ;
      RECT 86.62 272.195 86.69 273.715 ;
      RECT 75.565 272.405 75.635 273.715 ;
      RECT 75.425 272.405 75.495 273.715 ;
      RECT 5.46 272.195 5.53 273.715 ;
      RECT 75.565 266.845 75.635 268.545 ;
      RECT 75.425 266.845 75.495 268.545 ;
      RECT 16.655 266.845 16.725 268.16 ;
      RECT 16.515 266.845 16.585 268.16 ;
      RECT 0 266.925 92.2 268.155 ;
      RECT 86.63 266.635 86.7 268.155 ;
      RECT 5.535 266.635 5.605 268.155 ;
      RECT 5.395 266.635 5.465 268.155 ;
      RECT 16.655 261.285 16.725 262.985 ;
      RECT 16.515 261.285 16.585 262.985 ;
      RECT 75.565 261.365 75.635 262.925 ;
      RECT 75.425 261.365 75.495 262.925 ;
      RECT 5.535 261.075 5.605 262.61 ;
      RECT 5.395 261.075 5.465 262.61 ;
      RECT 0 261.365 92.2 262.595 ;
      RECT 86.64 261.075 86.71 262.595 ;
      RECT 75.47 261.285 75.54 262.595 ;
      RECT 75.48 255.725 75.55 257.425 ;
      RECT 16.655 255.805 16.725 257.365 ;
      RECT 16.515 255.805 16.585 257.365 ;
      RECT 0 255.805 92.2 257.035 ;
      RECT 86.685 255.515 86.755 257.035 ;
      RECT 86.545 255.515 86.615 257.035 ;
      RECT 16.63 255.725 16.7 257.035 ;
      RECT 5.46 255.515 5.53 257.035 ;
      RECT 16.655 250.165 16.725 251.87 ;
      RECT 16.515 250.165 16.585 251.87 ;
      RECT 86.685 249.955 86.755 251.51 ;
      RECT 86.545 249.955 86.615 251.51 ;
      RECT 75.565 250.165 75.635 251.48 ;
      RECT 75.425 250.165 75.495 251.48 ;
      RECT 0 250.245 92.2 251.475 ;
      RECT 5.47 249.955 5.54 251.475 ;
      RECT 75.565 244.605 75.635 245.96 ;
      RECT 75.425 244.605 75.495 245.96 ;
      RECT 16.655 244.605 16.725 245.93 ;
      RECT 16.515 244.605 16.585 245.93 ;
      RECT 0 244.685 92.2 245.915 ;
      RECT 86.64 244.395 86.71 245.915 ;
      RECT 5.535 244.395 5.605 245.915 ;
      RECT 5.395 244.395 5.465 245.915 ;
      RECT 75.565 239.125 75.635 240.685 ;
      RECT 75.425 239.125 75.495 240.685 ;
      RECT 16.655 239.125 16.725 240.685 ;
      RECT 16.515 239.125 16.585 240.685 ;
      RECT 0 239.125 92.2 240.355 ;
      RECT 86.685 238.835 86.755 240.355 ;
      RECT 86.545 238.835 86.615 240.355 ;
      RECT 75.48 239.045 75.55 240.355 ;
      RECT 16.63 239.045 16.7 240.355 ;
      RECT 5.535 238.835 5.605 240.355 ;
      RECT 5.395 238.835 5.465 240.355 ;
      RECT 75.565 233.485 75.635 235.19 ;
      RECT 75.425 233.485 75.495 235.19 ;
      RECT 16.655 233.565 16.725 235.125 ;
      RECT 16.515 233.565 16.585 235.125 ;
      RECT 0 233.565 92.2 234.795 ;
      RECT 86.685 233.275 86.755 234.795 ;
      RECT 86.545 233.275 86.615 234.795 ;
      RECT 16.64 233.485 16.71 234.795 ;
      RECT 5.47 233.275 5.54 234.795 ;
      RECT 16.65 227.925 16.72 229.625 ;
      RECT 86.685 227.715 86.755 229.28 ;
      RECT 86.545 227.715 86.615 229.28 ;
      RECT 0 228.005 92.2 229.235 ;
      RECT 75.565 227.925 75.635 229.235 ;
      RECT 75.425 227.925 75.495 229.235 ;
      RECT 5.48 227.715 5.55 229.235 ;
      RECT 75.565 222.365 75.635 224.065 ;
      RECT 75.425 222.365 75.495 224.065 ;
      RECT 0 222.445 92.2 223.675 ;
      RECT 86.65 222.155 86.72 223.675 ;
      RECT 16.655 222.365 16.725 223.675 ;
      RECT 16.515 222.365 16.585 223.675 ;
      RECT 5.535 222.155 5.605 223.675 ;
      RECT 5.395 222.155 5.465 223.675 ;
      RECT 16.655 216.805 16.725 218.505 ;
      RECT 16.515 216.805 16.585 218.505 ;
      RECT 75.565 216.885 75.635 218.445 ;
      RECT 75.425 216.885 75.495 218.445 ;
      RECT 5.535 216.595 5.605 218.12 ;
      RECT 5.395 216.595 5.465 218.12 ;
      RECT 0 216.885 92.2 218.115 ;
      RECT 86.66 216.595 86.73 218.115 ;
      RECT 75.49 216.805 75.56 218.115 ;
      RECT 75.565 211.325 75.635 212.885 ;
      RECT 75.425 211.325 75.495 212.885 ;
      RECT 16.655 211.325 16.725 212.885 ;
      RECT 16.515 211.325 16.585 212.885 ;
      RECT 5.535 211.035 5.605 212.6 ;
      RECT 5.395 211.035 5.465 212.6 ;
      RECT 0 211.325 92.2 212.555 ;
      RECT 86.685 211.035 86.755 212.555 ;
      RECT 86.545 211.035 86.615 212.555 ;
      RECT 75.5 211.245 75.57 212.555 ;
      RECT 16.65 211.245 16.72 212.555 ;
      RECT 16.655 205.765 16.725 207.325 ;
      RECT 16.515 205.765 16.585 207.325 ;
      RECT 86.685 205.475 86.755 207.02 ;
      RECT 86.545 205.475 86.615 207.02 ;
      RECT 0 205.765 92.2 206.995 ;
      RECT 75.565 205.685 75.635 206.995 ;
      RECT 75.425 205.685 75.495 206.995 ;
      RECT 16.66 205.685 16.73 206.995 ;
      RECT 16.52 205.685 16.59 206.995 ;
      RECT 5.49 205.475 5.56 206.995 ;
      RECT 75.565 200.125 75.635 201.47 ;
      RECT 75.425 200.125 75.495 201.47 ;
      RECT 16.655 200.125 16.725 201.44 ;
      RECT 16.515 200.125 16.585 201.44 ;
      RECT 0 200.205 92.2 201.435 ;
      RECT 86.66 199.915 86.73 201.435 ;
      RECT 5.535 199.915 5.605 201.435 ;
      RECT 5.395 199.915 5.465 201.435 ;
      RECT 75.565 194.645 75.635 196.205 ;
      RECT 75.425 194.645 75.495 196.205 ;
      RECT 16.655 194.565 16.725 195.92 ;
      RECT 16.515 194.565 16.585 195.92 ;
      RECT 0 194.645 92.2 195.875 ;
      RECT 86.67 194.355 86.74 195.875 ;
      RECT 75.5 194.565 75.57 195.875 ;
      RECT 5.535 194.355 5.605 195.875 ;
      RECT 5.395 194.355 5.465 195.875 ;
      RECT 75.565 189.085 75.635 190.645 ;
      RECT 75.425 189.085 75.495 190.645 ;
      RECT 16.655 189.085 16.725 190.645 ;
      RECT 16.515 189.085 16.585 190.645 ;
      RECT 0 189.085 92.2 190.315 ;
      RECT 86.685 188.795 86.755 190.315 ;
      RECT 86.545 188.795 86.615 190.315 ;
      RECT 75.51 189.005 75.58 190.315 ;
      RECT 16.66 189.005 16.73 190.315 ;
      RECT 16.52 189.005 16.59 190.315 ;
      RECT 5.49 188.795 5.56 190.315 ;
      RECT 16.67 183.445 16.74 185.145 ;
      RECT 16.53 183.445 16.6 185.145 ;
      RECT 86.685 183.235 86.755 184.79 ;
      RECT 86.545 183.235 86.615 184.79 ;
      RECT 0 183.525 92.2 184.755 ;
      RECT 75.565 183.445 75.635 184.755 ;
      RECT 75.425 183.445 75.495 184.755 ;
      RECT 5.5 183.235 5.57 184.755 ;
      RECT 75.565 177.885 75.635 179.24 ;
      RECT 75.425 177.885 75.495 179.24 ;
      RECT 0 177.965 92.2 179.195 ;
      RECT 86.67 177.675 86.74 179.195 ;
      RECT 16.655 177.885 16.725 179.195 ;
      RECT 16.515 177.885 16.585 179.195 ;
      RECT 5.535 177.675 5.605 179.195 ;
      RECT 5.395 177.675 5.465 179.195 ;
      RECT 16.655 172.325 16.725 174.025 ;
      RECT 16.515 172.325 16.585 174.025 ;
      RECT 75.565 172.405 75.635 173.965 ;
      RECT 75.425 172.405 75.495 173.965 ;
      RECT 0 172.405 92.2 173.635 ;
      RECT 86.685 172.115 86.755 173.635 ;
      RECT 86.545 172.115 86.615 173.635 ;
      RECT 75.51 172.325 75.58 173.635 ;
      RECT 5.535 172.115 5.605 173.635 ;
      RECT 5.395 172.115 5.465 173.635 ;
      RECT 75.565 166.845 75.635 168.405 ;
      RECT 75.425 166.845 75.495 168.405 ;
      RECT 16.655 166.845 16.725 168.405 ;
      RECT 16.515 166.845 16.585 168.405 ;
      RECT 5.535 166.555 5.605 168.11 ;
      RECT 5.395 166.555 5.465 168.11 ;
      RECT 0 166.845 92.2 168.075 ;
      RECT 86.685 166.555 86.755 168.075 ;
      RECT 86.545 166.555 86.615 168.075 ;
      RECT 75.52 166.765 75.59 168.075 ;
      RECT 16.67 166.765 16.74 168.075 ;
      RECT 16.53 166.765 16.6 168.075 ;
      RECT 16.655 161.285 16.725 162.845 ;
      RECT 16.515 161.285 16.585 162.845 ;
      RECT 86.685 160.995 86.755 162.56 ;
      RECT 86.545 160.995 86.615 162.56 ;
      RECT 0 161.285 92.2 162.515 ;
      RECT 75.565 161.205 75.635 162.515 ;
      RECT 75.425 161.205 75.495 162.515 ;
      RECT 16.54 161.205 16.61 162.515 ;
      RECT 5.51 160.995 5.58 162.515 ;
      RECT 75.565 155.645 75.635 156.98 ;
      RECT 75.425 155.645 75.495 156.98 ;
      RECT 0 155.725 92.2 156.955 ;
      RECT 86.68 155.435 86.75 156.955 ;
      RECT 16.655 155.645 16.725 156.955 ;
      RECT 16.515 155.645 16.585 156.955 ;
      RECT 5.535 155.435 5.605 156.955 ;
      RECT 5.395 155.435 5.465 156.955 ;
      RECT 75.565 150.165 75.635 151.725 ;
      RECT 75.425 150.165 75.495 151.725 ;
      RECT 16.655 150.085 16.725 151.43 ;
      RECT 16.515 150.085 16.585 151.43 ;
      RECT 0 150.165 92.2 151.395 ;
      RECT 86.69 149.875 86.76 151.395 ;
      RECT 86.55 149.875 86.62 151.395 ;
      RECT 75.52 150.085 75.59 151.395 ;
      RECT 5.535 149.875 5.605 151.395 ;
      RECT 5.395 149.875 5.465 151.395 ;
      RECT 75.565 144.605 75.635 146.165 ;
      RECT 75.425 144.605 75.495 146.165 ;
      RECT 16.655 144.605 16.725 146.165 ;
      RECT 16.515 144.605 16.585 146.165 ;
      RECT 5.535 144.315 5.605 145.88 ;
      RECT 5.395 144.315 5.465 145.88 ;
      RECT 0 144.605 92.2 145.835 ;
      RECT 86.685 144.315 86.755 145.835 ;
      RECT 86.545 144.315 86.615 145.835 ;
      RECT 75.53 144.525 75.6 145.835 ;
      RECT 16.54 144.525 16.61 145.835 ;
      RECT 16.655 139.045 16.725 140.605 ;
      RECT 16.515 139.045 16.585 140.605 ;
      RECT 86.685 138.755 86.755 140.3 ;
      RECT 86.545 138.755 86.615 140.3 ;
      RECT 0 139.045 92.2 140.275 ;
      RECT 75.565 138.965 75.635 140.275 ;
      RECT 75.425 138.965 75.495 140.275 ;
      RECT 16.55 138.965 16.62 140.275 ;
      RECT 5.52 138.755 5.59 140.275 ;
      RECT 75.565 133.405 75.635 134.75 ;
      RECT 75.425 133.405 75.495 134.75 ;
      RECT 0 133.485 92.2 134.715 ;
      RECT 86.69 133.195 86.76 134.715 ;
      RECT 86.55 133.195 86.62 134.715 ;
      RECT 16.655 133.405 16.725 134.715 ;
      RECT 16.515 133.405 16.585 134.715 ;
      RECT 5.535 133.195 5.605 134.715 ;
      RECT 5.395 133.195 5.465 134.715 ;
      RECT 75.565 127.925 75.635 129.485 ;
      RECT 75.425 127.925 75.495 129.485 ;
      RECT 16.655 127.845 16.725 129.2 ;
      RECT 16.515 127.845 16.585 129.2 ;
      RECT 0 127.925 92.2 129.155 ;
      RECT 86.7 127.635 86.77 129.155 ;
      RECT 86.56 127.635 86.63 129.155 ;
      RECT 75.53 127.845 75.6 129.155 ;
      RECT 5.535 127.635 5.605 129.155 ;
      RECT 5.395 127.635 5.465 129.155 ;
      RECT 75.565 122.365 75.635 123.925 ;
      RECT 75.425 122.365 75.495 123.925 ;
      RECT 16.655 122.365 16.725 123.925 ;
      RECT 16.515 122.365 16.585 123.925 ;
      RECT 5.535 122.075 5.605 123.62 ;
      RECT 5.395 122.075 5.465 123.62 ;
      RECT 0 122.365 92.2 123.595 ;
      RECT 86.685 122.075 86.755 123.595 ;
      RECT 86.545 122.075 86.615 123.595 ;
      RECT 75.54 122.285 75.61 123.595 ;
      RECT 16.55 122.285 16.62 123.595 ;
      RECT 16.655 116.805 16.725 118.365 ;
      RECT 16.515 116.805 16.585 118.365 ;
      RECT 86.685 116.515 86.755 118.07 ;
      RECT 86.545 116.515 86.615 118.07 ;
      RECT 0 116.805 92.2 118.035 ;
      RECT 75.565 116.725 75.635 118.035 ;
      RECT 75.425 116.725 75.495 118.035 ;
      RECT 16.56 116.725 16.63 118.035 ;
      RECT 5.53 116.515 5.6 118.035 ;
      RECT 75.565 111.165 75.635 112.49 ;
      RECT 75.425 111.165 75.495 112.49 ;
      RECT 0 111.245 92.2 112.475 ;
      RECT 86.7 110.955 86.77 112.475 ;
      RECT 86.56 110.955 86.63 112.475 ;
      RECT 16.655 111.165 16.725 112.475 ;
      RECT 16.515 111.165 16.585 112.475 ;
      RECT 5.54 110.955 5.61 112.475 ;
      RECT 5.4 110.955 5.47 112.475 ;
      RECT 75.565 105.685 75.635 107.245 ;
      RECT 75.425 105.685 75.495 107.245 ;
      RECT 16.655 105.605 16.725 106.94 ;
      RECT 16.515 105.605 16.585 106.94 ;
      RECT 0 105.685 92.2 106.915 ;
      RECT 86.57 105.395 86.64 106.915 ;
      RECT 75.54 105.605 75.61 106.915 ;
      RECT 5.535 105.395 5.605 106.915 ;
      RECT 5.395 105.395 5.465 106.915 ;
      RECT 75.565 100.125 75.635 101.685 ;
      RECT 75.425 100.125 75.495 101.685 ;
      RECT 16.655 100.125 16.725 101.685 ;
      RECT 16.515 100.125 16.585 101.685 ;
      RECT 5.535 99.835 5.605 101.39 ;
      RECT 5.395 99.835 5.465 101.39 ;
      RECT 0 100.125 92.2 101.355 ;
      RECT 86.685 99.835 86.755 101.355 ;
      RECT 86.545 99.835 86.615 101.355 ;
      RECT 75.55 100.045 75.62 101.355 ;
      RECT 16.56 100.045 16.63 101.355 ;
      RECT 16.655 94.565 16.725 96.125 ;
      RECT 16.515 94.565 16.585 96.125 ;
      RECT 86.685 94.275 86.755 95.81 ;
      RECT 86.545 94.275 86.615 95.81 ;
      RECT 0 94.565 92.2 95.795 ;
      RECT 75.565 94.485 75.635 95.795 ;
      RECT 75.425 94.485 75.495 95.795 ;
      RECT 16.57 94.485 16.64 95.795 ;
      RECT 5.54 94.275 5.61 95.795 ;
      RECT 5.4 94.275 5.47 95.795 ;
      RECT 75.565 88.925 75.635 90.26 ;
      RECT 75.425 88.925 75.495 90.26 ;
      RECT 0 89.005 92.2 90.235 ;
      RECT 86.57 88.715 86.64 90.235 ;
      RECT 16.655 88.925 16.725 90.235 ;
      RECT 16.515 88.925 16.585 90.235 ;
      RECT 5.535 88.715 5.605 90.235 ;
      RECT 5.395 88.715 5.465 90.235 ;
      RECT 75.565 83.445 75.635 85.005 ;
      RECT 75.425 83.445 75.495 85.005 ;
      RECT 16.655 83.365 16.725 84.71 ;
      RECT 16.515 83.365 16.585 84.71 ;
      RECT 0 83.445 92.2 84.675 ;
      RECT 86.58 83.155 86.65 84.675 ;
      RECT 75.55 83.365 75.62 84.675 ;
      RECT 5.535 83.155 5.605 84.675 ;
      RECT 5.395 83.155 5.465 84.675 ;
      RECT 75.565 77.885 75.635 79.445 ;
      RECT 75.425 77.885 75.495 79.445 ;
      RECT 16.655 77.885 16.725 79.445 ;
      RECT 16.515 77.885 16.585 79.445 ;
      RECT 5.535 77.595 5.605 79.13 ;
      RECT 5.395 77.595 5.465 79.13 ;
      RECT 0 77.885 92.2 79.115 ;
      RECT 86.685 77.595 86.755 79.115 ;
      RECT 86.545 77.595 86.615 79.115 ;
      RECT 75.56 77.805 75.63 79.115 ;
      RECT 16.57 77.805 16.64 79.115 ;
      RECT 16.655 72.325 16.725 73.885 ;
      RECT 16.515 72.325 16.585 73.885 ;
      RECT 86.685 72.035 86.755 73.58 ;
      RECT 86.545 72.035 86.615 73.58 ;
      RECT 0 72.325 92.2 73.555 ;
      RECT 75.565 72.245 75.635 73.555 ;
      RECT 75.425 72.245 75.495 73.555 ;
      RECT 16.58 72.245 16.65 73.555 ;
      RECT 5.55 72.035 5.62 73.555 ;
      RECT 5.41 72.035 5.48 73.555 ;
      RECT 75.565 66.685 75.635 68 ;
      RECT 75.425 66.685 75.495 68 ;
      RECT 0 66.765 92.2 67.995 ;
      RECT 86.58 66.475 86.65 67.995 ;
      RECT 16.655 66.685 16.725 67.995 ;
      RECT 16.515 66.685 16.585 67.995 ;
      RECT 5.42 66.475 5.49 67.995 ;
      RECT 75.565 61.205 75.635 62.765 ;
      RECT 75.425 61.205 75.495 62.765 ;
      RECT 16.655 61.125 16.725 62.45 ;
      RECT 16.515 61.125 16.585 62.45 ;
      RECT 0 61.205 92.2 62.435 ;
      RECT 86.59 60.915 86.66 62.435 ;
      RECT 75.56 61.125 75.63 62.435 ;
      RECT 5.535 60.915 5.605 62.435 ;
      RECT 5.395 60.915 5.465 62.435 ;
      RECT 75.565 55.645 75.635 57.205 ;
      RECT 75.425 55.645 75.495 57.205 ;
      RECT 16.655 55.645 16.725 57.205 ;
      RECT 16.515 55.645 16.585 57.205 ;
      RECT 5.535 55.355 5.605 56.9 ;
      RECT 5.395 55.355 5.465 56.9 ;
      RECT 0 55.645 92.2 56.875 ;
      RECT 86.685 55.355 86.755 56.875 ;
      RECT 86.545 55.355 86.615 56.875 ;
      RECT 75.57 55.565 75.64 56.875 ;
      RECT 75.43 55.565 75.5 56.875 ;
      RECT 16.58 55.565 16.65 56.875 ;
      RECT 75.565 50.005 75.635 51.71 ;
      RECT 75.425 50.005 75.495 51.71 ;
      RECT 16.655 50.085 16.725 51.645 ;
      RECT 16.515 50.085 16.585 51.645 ;
      RECT 86.685 49.795 86.755 51.32 ;
      RECT 86.545 49.795 86.615 51.32 ;
      RECT 0 50.085 92.2 51.315 ;
      RECT 16.59 50.005 16.66 51.315 ;
      RECT 5.42 49.795 5.49 51.315 ;
      RECT 86.685 44.235 86.755 45.8 ;
      RECT 86.545 44.235 86.615 45.8 ;
      RECT 75.565 44.445 75.635 45.77 ;
      RECT 75.425 44.445 75.495 45.77 ;
      RECT 0 44.525 92.2 45.755 ;
      RECT 16.655 44.445 16.725 45.755 ;
      RECT 16.515 44.445 16.585 45.755 ;
      RECT 5.43 44.235 5.5 45.755 ;
      RECT 75.565 38.965 75.635 40.525 ;
      RECT 75.425 38.965 75.495 40.525 ;
      RECT 16.655 38.885 16.725 40.22 ;
      RECT 16.515 38.885 16.585 40.22 ;
      RECT 0 38.965 92.2 40.195 ;
      RECT 86.6 38.675 86.67 40.195 ;
      RECT 75.57 38.885 75.64 40.195 ;
      RECT 75.43 38.885 75.5 40.195 ;
      RECT 5.535 38.675 5.605 40.195 ;
      RECT 5.395 38.675 5.465 40.195 ;
      RECT 75.565 33.405 75.635 34.965 ;
      RECT 75.425 33.405 75.495 34.965 ;
      RECT 16.655 33.405 16.725 34.965 ;
      RECT 16.515 33.405 16.585 34.965 ;
      RECT 5.535 33.115 5.605 34.64 ;
      RECT 5.395 33.115 5.465 34.64 ;
      RECT 0 33.405 92.2 34.635 ;
      RECT 86.685 33.115 86.755 34.635 ;
      RECT 86.545 33.115 86.615 34.635 ;
      RECT 75.58 33.325 75.65 34.635 ;
      RECT 75.44 33.325 75.51 34.635 ;
      RECT 16.59 33.325 16.66 34.635 ;
      RECT 16.655 27.845 16.725 29.405 ;
      RECT 16.515 27.845 16.585 29.405 ;
      RECT 86.685 27.555 86.755 29.09 ;
      RECT 86.545 27.555 86.615 29.09 ;
      RECT 0 27.845 92.2 29.075 ;
      RECT 75.565 27.765 75.635 29.075 ;
      RECT 75.425 27.765 75.495 29.075 ;
      RECT 16.6 27.765 16.67 29.075 ;
      RECT 5.43 27.555 5.5 29.075 ;
      RECT 0 22.285 92.2 23.515 ;
      RECT 86.6 21.995 86.67 23.515 ;
      RECT 75.565 22.205 75.635 23.515 ;
      RECT 75.425 22.205 75.495 23.515 ;
      RECT 16.655 22.205 16.725 23.515 ;
      RECT 16.515 22.205 16.585 23.515 ;
      RECT 5.44 21.995 5.51 23.515 ;
      RECT 75.565 16.645 75.635 18.345 ;
      RECT 75.425 16.645 75.495 18.345 ;
      RECT 16.655 16.645 16.725 17.96 ;
      RECT 16.515 16.645 16.585 17.96 ;
      RECT 0 16.725 92.2 17.955 ;
      RECT 86.61 16.435 86.68 17.955 ;
      RECT 5.535 16.435 5.605 17.955 ;
      RECT 5.395 16.435 5.465 17.955 ;
      RECT 16.655 11.085 16.725 12.785 ;
      RECT 16.515 11.085 16.585 12.785 ;
      RECT 75.565 11.165 75.635 12.725 ;
      RECT 75.425 11.165 75.495 12.725 ;
      RECT 5.535 10.875 5.605 12.41 ;
      RECT 5.395 10.875 5.465 12.41 ;
      RECT 0 11.165 92.2 12.395 ;
      RECT 86.62 10.875 86.69 12.395 ;
      RECT 75.45 11.085 75.52 12.395 ;
      RECT 75.46 5.525 75.53 7.225 ;
      RECT 16.655 5.605 16.725 7.165 ;
      RECT 16.515 5.605 16.585 7.165 ;
      RECT 0 5.605 92.2 6.835 ;
      RECT 86.685 5.315 86.755 6.835 ;
      RECT 86.545 5.315 86.615 6.835 ;
      RECT 16.61 5.525 16.68 6.835 ;
      RECT 5.44 5.315 5.51 6.835 ;
      RECT 16.55 0 16.62 1.405 ;
      RECT 86.685 0 86.755 1.31 ;
      RECT 86.545 0 86.615 1.31 ;
      RECT 75.565 0 75.635 1.28 ;
      RECT 75.425 0 75.495 1.28 ;
      RECT 5.535 0 5.605 1.28 ;
      RECT 5.395 0 5.465 1.28 ;
      RECT 0 0 92.2 1.275 ;
      RECT 81.885 1.55 91.435 1.97 ;
      RECT 81.885 7.11 91.435 7.53 ;
      RECT 81.885 12.67 91.435 13.09 ;
      RECT 81.885 18.23 91.435 18.65 ;
      RECT 81.885 23.79 91.435 24.21 ;
      RECT 81.885 29.35 91.435 29.77 ;
      RECT 81.885 34.91 91.435 35.33 ;
      RECT 81.885 40.47 91.435 40.89 ;
      RECT 81.885 46.03 91.435 46.45 ;
      RECT 81.885 51.59 91.435 52.01 ;
      RECT 81.885 57.15 91.435 57.57 ;
      RECT 81.885 62.71 91.435 63.13 ;
      RECT 81.885 68.27 91.435 68.69 ;
      RECT 81.885 73.83 91.435 74.25 ;
      RECT 81.885 79.39 91.435 79.81 ;
      RECT 81.885 84.95 91.435 85.37 ;
      RECT 81.885 90.51 91.435 90.93 ;
      RECT 81.885 96.07 91.435 96.49 ;
      RECT 81.885 101.63 91.435 102.05 ;
      RECT 81.885 107.19 91.435 107.61 ;
      RECT 81.885 112.75 91.435 113.17 ;
      RECT 81.885 118.31 91.435 118.73 ;
      RECT 81.885 123.87 91.435 124.29 ;
      RECT 81.885 129.43 91.435 129.85 ;
      RECT 81.885 134.99 91.435 135.41 ;
      RECT 81.885 140.55 91.435 140.97 ;
      RECT 81.885 146.11 91.435 146.53 ;
      RECT 81.885 151.67 91.435 152.09 ;
      RECT 81.885 157.23 91.435 157.65 ;
      RECT 81.885 162.79 91.435 163.21 ;
      RECT 81.885 168.35 91.435 168.77 ;
      RECT 81.885 173.91 91.435 174.33 ;
      RECT 81.885 179.47 91.435 179.89 ;
      RECT 81.885 185.03 91.435 185.45 ;
      RECT 81.885 190.59 91.435 191.01 ;
      RECT 81.885 196.15 91.435 196.57 ;
      RECT 81.885 201.71 91.435 202.13 ;
      RECT 81.885 207.27 91.435 207.69 ;
      RECT 81.885 212.83 91.435 213.25 ;
      RECT 81.885 218.39 91.435 218.81 ;
      RECT 81.885 223.95 91.435 224.37 ;
      RECT 81.885 229.51 91.435 229.93 ;
      RECT 81.885 235.07 91.435 235.49 ;
      RECT 81.885 240.63 91.435 241.05 ;
      RECT 81.885 246.19 91.435 246.61 ;
      RECT 81.885 251.75 91.435 252.17 ;
      RECT 81.885 257.31 91.435 257.73 ;
      RECT 81.885 262.87 91.435 263.29 ;
      RECT 81.885 268.43 91.435 268.85 ;
      RECT 81.885 273.99 91.435 274.41 ;
      RECT 81.885 279.55 91.435 279.97 ;
      RECT 81.885 285.11 91.435 285.53 ;
      RECT 81.885 290.67 91.435 291.09 ;
      RECT 86.7 107.805 86.77 108.155 ;
      RECT 86.7 108.255 86.77 108.605 ;
      RECT 86.7 108.705 86.77 109.055 ;
      RECT 86.7 109.155 86.77 109.505 ;
      RECT 86.7 109.605 86.77 109.955 ;
      RECT 86.7 110.055 86.77 110.405 ;
      RECT 86.7 110.505 86.77 110.855 ;
      RECT 86.7 124.485 86.77 124.835 ;
      RECT 86.7 124.935 86.77 125.285 ;
      RECT 86.7 125.385 86.77 125.735 ;
      RECT 86.7 125.835 86.77 126.185 ;
      RECT 86.7 126.285 86.77 126.635 ;
      RECT 86.7 126.735 86.77 127.085 ;
      RECT 86.7 127.185 86.77 127.535 ;
      RECT 86.69 130.045 86.76 130.395 ;
      RECT 86.69 130.495 86.76 130.845 ;
      RECT 86.69 130.945 86.76 131.295 ;
      RECT 86.69 131.395 86.76 131.745 ;
      RECT 86.69 131.845 86.76 132.195 ;
      RECT 86.69 132.295 86.76 132.645 ;
      RECT 86.69 132.745 86.76 133.095 ;
      RECT 86.69 146.725 86.76 147.075 ;
      RECT 86.69 147.175 86.76 147.525 ;
      RECT 86.69 147.625 86.76 147.975 ;
      RECT 86.69 148.075 86.76 148.425 ;
      RECT 86.69 148.525 86.76 148.875 ;
      RECT 86.69 148.975 86.76 149.325 ;
      RECT 86.69 149.425 86.76 149.775 ;
      RECT 86.685 2.165 86.755 2.515 ;
      RECT 86.685 2.615 86.755 2.965 ;
      RECT 86.685 3.065 86.755 3.415 ;
      RECT 86.685 3.515 86.755 3.865 ;
      RECT 86.685 3.965 86.755 4.315 ;
      RECT 86.685 4.415 86.755 4.765 ;
      RECT 86.685 4.865 86.755 5.215 ;
      RECT 86.685 24.405 86.755 24.755 ;
      RECT 86.685 24.855 86.755 25.205 ;
      RECT 86.685 25.305 86.755 25.655 ;
      RECT 86.685 25.755 86.755 26.105 ;
      RECT 86.685 26.205 86.755 26.555 ;
      RECT 86.685 26.655 86.755 27.005 ;
      RECT 86.685 27.105 86.755 27.455 ;
      RECT 86.685 29.965 86.755 30.315 ;
      RECT 86.685 30.415 86.755 30.765 ;
      RECT 86.685 30.865 86.755 31.215 ;
      RECT 86.685 31.315 86.755 31.665 ;
      RECT 86.685 31.765 86.755 32.115 ;
      RECT 86.685 32.215 86.755 32.565 ;
      RECT 86.685 32.665 86.755 33.015 ;
      RECT 86.685 41.085 86.755 41.435 ;
      RECT 86.685 41.535 86.755 41.885 ;
      RECT 86.685 41.985 86.755 42.335 ;
      RECT 86.685 42.435 86.755 42.785 ;
      RECT 86.685 42.885 86.755 43.235 ;
      RECT 86.685 43.335 86.755 43.685 ;
      RECT 86.685 43.785 86.755 44.135 ;
      RECT 86.685 46.645 86.755 46.995 ;
      RECT 86.685 47.095 86.755 47.445 ;
      RECT 86.685 47.545 86.755 47.895 ;
      RECT 86.685 47.995 86.755 48.345 ;
      RECT 86.685 48.445 86.755 48.795 ;
      RECT 86.685 48.895 86.755 49.245 ;
      RECT 86.685 49.345 86.755 49.695 ;
      RECT 86.685 52.205 86.755 52.555 ;
      RECT 86.685 52.655 86.755 53.005 ;
      RECT 86.685 53.105 86.755 53.455 ;
      RECT 86.685 53.555 86.755 53.905 ;
      RECT 86.685 54.005 86.755 54.355 ;
      RECT 86.685 54.455 86.755 54.805 ;
      RECT 86.685 54.905 86.755 55.255 ;
      RECT 86.685 68.885 86.755 69.235 ;
      RECT 86.685 69.335 86.755 69.685 ;
      RECT 86.685 69.785 86.755 70.135 ;
      RECT 86.685 70.235 86.755 70.585 ;
      RECT 86.685 70.685 86.755 71.035 ;
      RECT 86.685 71.135 86.755 71.485 ;
      RECT 86.685 71.585 86.755 71.935 ;
      RECT 86.685 74.445 86.755 74.795 ;
      RECT 86.685 74.895 86.755 75.245 ;
      RECT 86.685 75.345 86.755 75.695 ;
      RECT 86.685 75.795 86.755 76.145 ;
      RECT 86.685 76.245 86.755 76.595 ;
      RECT 86.685 76.695 86.755 77.045 ;
      RECT 86.685 77.145 86.755 77.495 ;
      RECT 86.685 91.125 86.755 91.475 ;
      RECT 86.685 91.575 86.755 91.925 ;
      RECT 86.685 92.025 86.755 92.375 ;
      RECT 86.685 92.475 86.755 92.825 ;
      RECT 86.685 92.925 86.755 93.275 ;
      RECT 86.685 93.375 86.755 93.725 ;
      RECT 86.685 93.825 86.755 94.175 ;
      RECT 86.685 96.685 86.755 97.035 ;
      RECT 86.685 97.135 86.755 97.485 ;
      RECT 86.685 97.585 86.755 97.935 ;
      RECT 86.685 98.035 86.755 98.385 ;
      RECT 86.685 98.485 86.755 98.835 ;
      RECT 86.685 98.935 86.755 99.285 ;
      RECT 86.685 99.385 86.755 99.735 ;
      RECT 86.685 113.365 86.755 113.715 ;
      RECT 86.685 113.815 86.755 114.165 ;
      RECT 86.685 114.265 86.755 114.615 ;
      RECT 86.685 114.715 86.755 115.065 ;
      RECT 86.685 115.165 86.755 115.515 ;
      RECT 86.685 115.615 86.755 115.965 ;
      RECT 86.685 116.065 86.755 116.415 ;
      RECT 86.685 118.925 86.755 119.275 ;
      RECT 86.685 119.375 86.755 119.725 ;
      RECT 86.685 119.825 86.755 120.175 ;
      RECT 86.685 120.275 86.755 120.625 ;
      RECT 86.685 120.725 86.755 121.075 ;
      RECT 86.685 121.175 86.755 121.525 ;
      RECT 86.685 121.625 86.755 121.975 ;
      RECT 86.685 135.605 86.755 135.955 ;
      RECT 86.685 136.055 86.755 136.405 ;
      RECT 86.685 136.505 86.755 136.855 ;
      RECT 86.685 136.955 86.755 137.305 ;
      RECT 86.685 137.405 86.755 137.755 ;
      RECT 86.685 137.855 86.755 138.205 ;
      RECT 86.685 138.305 86.755 138.655 ;
      RECT 86.685 141.165 86.755 141.515 ;
      RECT 86.685 141.615 86.755 141.965 ;
      RECT 86.685 142.065 86.755 142.415 ;
      RECT 86.685 142.515 86.755 142.865 ;
      RECT 86.685 142.965 86.755 143.315 ;
      RECT 86.685 143.415 86.755 143.765 ;
      RECT 86.685 143.865 86.755 144.215 ;
      RECT 86.685 157.845 86.755 158.195 ;
      RECT 86.685 158.295 86.755 158.645 ;
      RECT 86.685 158.745 86.755 159.095 ;
      RECT 86.685 159.195 86.755 159.545 ;
      RECT 86.685 159.645 86.755 159.995 ;
      RECT 86.685 160.095 86.755 160.445 ;
      RECT 86.685 160.545 86.755 160.895 ;
      RECT 86.685 163.405 86.755 163.755 ;
      RECT 86.685 163.855 86.755 164.205 ;
      RECT 86.685 164.305 86.755 164.655 ;
      RECT 86.685 164.755 86.755 165.105 ;
      RECT 86.685 165.205 86.755 165.555 ;
      RECT 86.685 165.655 86.755 166.005 ;
      RECT 86.685 166.105 86.755 166.455 ;
      RECT 86.685 168.965 86.755 169.315 ;
      RECT 86.685 169.415 86.755 169.765 ;
      RECT 86.685 169.865 86.755 170.215 ;
      RECT 86.685 170.315 86.755 170.665 ;
      RECT 86.685 170.765 86.755 171.115 ;
      RECT 86.685 171.215 86.755 171.565 ;
      RECT 86.685 171.665 86.755 172.015 ;
      RECT 86.685 180.085 86.755 180.435 ;
      RECT 86.685 180.535 86.755 180.885 ;
      RECT 86.685 180.985 86.755 181.335 ;
      RECT 86.685 181.435 86.755 181.785 ;
      RECT 86.685 181.885 86.755 182.235 ;
      RECT 86.685 182.335 86.755 182.685 ;
      RECT 86.685 182.785 86.755 183.135 ;
      RECT 86.685 185.645 86.755 185.995 ;
      RECT 86.685 186.095 86.755 186.445 ;
      RECT 86.685 186.545 86.755 186.895 ;
      RECT 86.685 186.995 86.755 187.345 ;
      RECT 86.685 187.445 86.755 187.795 ;
      RECT 86.685 187.895 86.755 188.245 ;
      RECT 86.685 188.345 86.755 188.695 ;
      RECT 86.685 202.325 86.755 202.675 ;
      RECT 86.685 202.775 86.755 203.125 ;
      RECT 86.685 203.225 86.755 203.575 ;
      RECT 86.685 203.675 86.755 204.025 ;
      RECT 86.685 204.125 86.755 204.475 ;
      RECT 86.685 204.575 86.755 204.925 ;
      RECT 86.685 205.025 86.755 205.375 ;
      RECT 86.685 207.885 86.755 208.235 ;
      RECT 86.685 208.335 86.755 208.685 ;
      RECT 86.685 208.785 86.755 209.135 ;
      RECT 86.685 209.235 86.755 209.585 ;
      RECT 86.685 209.685 86.755 210.035 ;
      RECT 86.685 210.135 86.755 210.485 ;
      RECT 86.685 210.585 86.755 210.935 ;
      RECT 86.685 224.565 86.755 224.915 ;
      RECT 86.685 225.015 86.755 225.365 ;
      RECT 86.685 225.465 86.755 225.815 ;
      RECT 86.685 225.915 86.755 226.265 ;
      RECT 86.685 226.365 86.755 226.715 ;
      RECT 86.685 226.815 86.755 227.165 ;
      RECT 86.685 227.265 86.755 227.615 ;
      RECT 86.685 230.125 86.755 230.475 ;
      RECT 86.685 230.575 86.755 230.925 ;
      RECT 86.685 231.025 86.755 231.375 ;
      RECT 86.685 231.475 86.755 231.825 ;
      RECT 86.685 231.925 86.755 232.275 ;
      RECT 86.685 232.375 86.755 232.725 ;
      RECT 86.685 232.825 86.755 233.175 ;
      RECT 86.685 235.685 86.755 236.035 ;
      RECT 86.685 236.135 86.755 236.485 ;
      RECT 86.685 236.585 86.755 236.935 ;
      RECT 86.685 237.035 86.755 237.385 ;
      RECT 86.685 237.485 86.755 237.835 ;
      RECT 86.685 237.935 86.755 238.285 ;
      RECT 86.685 238.385 86.755 238.735 ;
      RECT 86.685 246.805 86.755 247.155 ;
      RECT 86.685 247.255 86.755 247.605 ;
      RECT 86.685 247.705 86.755 248.055 ;
      RECT 86.685 248.155 86.755 248.505 ;
      RECT 86.685 248.605 86.755 248.955 ;
      RECT 86.685 249.055 86.755 249.405 ;
      RECT 86.685 249.505 86.755 249.855 ;
      RECT 86.685 252.365 86.755 252.715 ;
      RECT 86.685 252.815 86.755 253.165 ;
      RECT 86.685 253.265 86.755 253.615 ;
      RECT 86.685 253.715 86.755 254.065 ;
      RECT 86.685 254.165 86.755 254.515 ;
      RECT 86.685 254.615 86.755 254.965 ;
      RECT 86.685 255.065 86.755 255.415 ;
      RECT 86.685 274.605 86.755 274.955 ;
      RECT 86.685 275.055 86.755 275.405 ;
      RECT 86.685 275.505 86.755 275.855 ;
      RECT 86.685 275.955 86.755 276.305 ;
      RECT 86.685 276.405 86.755 276.755 ;
      RECT 86.685 276.855 86.755 277.205 ;
      RECT 86.685 277.305 86.755 277.655 ;
      RECT 86.685 280.165 86.755 280.515 ;
      RECT 86.685 280.615 86.755 280.965 ;
      RECT 86.685 281.065 86.755 281.415 ;
      RECT 86.685 281.515 86.755 281.865 ;
      RECT 86.685 281.965 86.755 282.315 ;
      RECT 86.685 282.415 86.755 282.765 ;
      RECT 86.685 282.865 86.755 283.215 ;
      RECT 86.68 152.285 86.75 152.635 ;
      RECT 86.68 152.735 86.75 153.085 ;
      RECT 86.68 153.185 86.75 153.535 ;
      RECT 86.68 153.635 86.75 153.985 ;
      RECT 86.68 154.085 86.75 154.435 ;
      RECT 86.68 154.535 86.75 154.885 ;
      RECT 86.68 154.985 86.75 155.335 ;
      RECT 86.67 174.525 86.74 174.875 ;
      RECT 86.67 174.975 86.74 175.325 ;
      RECT 86.67 175.425 86.74 175.775 ;
      RECT 86.67 175.875 86.74 176.225 ;
      RECT 86.67 176.325 86.74 176.675 ;
      RECT 86.67 176.775 86.74 177.125 ;
      RECT 86.67 177.225 86.74 177.575 ;
      RECT 86.67 191.205 86.74 191.555 ;
      RECT 86.67 191.655 86.74 192.005 ;
      RECT 86.67 192.105 86.74 192.455 ;
      RECT 86.67 192.555 86.74 192.905 ;
      RECT 86.67 193.005 86.74 193.355 ;
      RECT 86.67 193.455 86.74 193.805 ;
      RECT 86.67 193.905 86.74 194.255 ;
      RECT 86.66 196.765 86.73 197.115 ;
      RECT 86.66 197.215 86.73 197.565 ;
      RECT 86.66 197.665 86.73 198.015 ;
      RECT 86.66 198.115 86.73 198.465 ;
      RECT 86.66 198.565 86.73 198.915 ;
      RECT 86.66 199.015 86.73 199.365 ;
      RECT 86.66 199.465 86.73 199.815 ;
      RECT 86.66 213.445 86.73 213.795 ;
      RECT 86.66 213.895 86.73 214.245 ;
      RECT 86.66 214.345 86.73 214.695 ;
      RECT 86.66 214.795 86.73 215.145 ;
      RECT 86.66 215.245 86.73 215.595 ;
      RECT 86.66 215.695 86.73 216.045 ;
      RECT 86.66 216.145 86.73 216.495 ;
      RECT 86.65 219.005 86.72 219.355 ;
      RECT 86.65 219.455 86.72 219.805 ;
      RECT 86.65 219.905 86.72 220.255 ;
      RECT 86.65 220.355 86.72 220.705 ;
      RECT 86.65 220.805 86.72 221.155 ;
      RECT 86.65 221.255 86.72 221.605 ;
      RECT 86.65 221.705 86.72 222.055 ;
      RECT 86.64 241.245 86.71 241.595 ;
      RECT 86.64 241.695 86.71 242.045 ;
      RECT 86.64 242.145 86.71 242.495 ;
      RECT 86.64 242.595 86.71 242.945 ;
      RECT 86.64 243.045 86.71 243.395 ;
      RECT 86.64 243.495 86.71 243.845 ;
      RECT 86.64 243.945 86.71 244.295 ;
      RECT 86.64 257.925 86.71 258.275 ;
      RECT 86.64 258.375 86.71 258.725 ;
      RECT 86.64 258.825 86.71 259.175 ;
      RECT 86.64 259.275 86.71 259.625 ;
      RECT 86.64 259.725 86.71 260.075 ;
      RECT 86.64 260.175 86.71 260.525 ;
      RECT 86.64 260.625 86.71 260.975 ;
      RECT 86.63 263.485 86.7 263.835 ;
      RECT 86.63 263.935 86.7 264.285 ;
      RECT 86.63 264.385 86.7 264.735 ;
      RECT 86.63 264.835 86.7 265.185 ;
      RECT 86.63 265.285 86.7 265.635 ;
      RECT 86.63 265.735 86.7 266.085 ;
      RECT 86.63 266.185 86.7 266.535 ;
      RECT 86.62 7.725 86.69 8.075 ;
      RECT 86.62 8.175 86.69 8.525 ;
      RECT 86.62 8.625 86.69 8.975 ;
      RECT 86.62 9.075 86.69 9.425 ;
      RECT 86.62 9.525 86.69 9.875 ;
      RECT 86.62 9.975 86.69 10.325 ;
      RECT 86.62 10.425 86.69 10.775 ;
      RECT 86.62 269.045 86.69 269.395 ;
      RECT 86.62 269.495 86.69 269.845 ;
      RECT 86.62 269.945 86.69 270.295 ;
      RECT 86.62 270.395 86.69 270.745 ;
      RECT 86.62 270.845 86.69 271.195 ;
      RECT 86.62 271.295 86.69 271.645 ;
      RECT 86.62 271.745 86.69 272.095 ;
      RECT 86.62 285.725 86.69 286.075 ;
      RECT 86.62 286.175 86.69 286.525 ;
      RECT 86.62 286.625 86.69 286.975 ;
      RECT 86.62 287.075 86.69 287.425 ;
      RECT 86.62 287.525 86.69 287.875 ;
      RECT 86.62 287.975 86.69 288.325 ;
      RECT 86.62 288.425 86.69 288.775 ;
      RECT 86.61 13.285 86.68 13.635 ;
      RECT 86.61 13.735 86.68 14.085 ;
      RECT 86.61 14.185 86.68 14.535 ;
      RECT 86.61 14.635 86.68 14.985 ;
      RECT 86.61 15.085 86.68 15.435 ;
      RECT 86.61 15.535 86.68 15.885 ;
      RECT 86.61 15.985 86.68 16.335 ;
      RECT 86.61 291.285 86.68 291.635 ;
      RECT 86.61 291.735 86.68 292.085 ;
      RECT 86.61 292.185 86.68 292.535 ;
      RECT 86.61 292.635 86.68 292.985 ;
      RECT 86.61 293.085 86.68 293.435 ;
      RECT 86.61 293.535 86.68 293.885 ;
      RECT 86.61 293.985 86.68 294.335 ;
      RECT 86.6 18.845 86.67 19.195 ;
      RECT 86.6 19.295 86.67 19.645 ;
      RECT 86.6 19.745 86.67 20.095 ;
      RECT 86.6 20.195 86.67 20.545 ;
      RECT 86.6 20.645 86.67 20.995 ;
      RECT 86.6 21.095 86.67 21.445 ;
      RECT 86.6 21.545 86.67 21.895 ;
      RECT 86.6 35.525 86.67 35.875 ;
      RECT 86.6 35.975 86.67 36.325 ;
      RECT 86.6 36.425 86.67 36.775 ;
      RECT 86.6 36.875 86.67 37.225 ;
      RECT 86.6 37.325 86.67 37.675 ;
      RECT 86.6 37.775 86.67 38.125 ;
      RECT 86.6 38.225 86.67 38.575 ;
      RECT 86.59 57.765 86.66 58.115 ;
      RECT 86.59 58.215 86.66 58.565 ;
      RECT 86.59 58.665 86.66 59.015 ;
      RECT 86.59 59.115 86.66 59.465 ;
      RECT 86.59 59.565 86.66 59.915 ;
      RECT 86.59 60.015 86.66 60.365 ;
      RECT 86.59 60.465 86.66 60.815 ;
      RECT 86.58 63.325 86.65 63.675 ;
      RECT 86.58 63.775 86.65 64.125 ;
      RECT 86.58 64.225 86.65 64.575 ;
      RECT 86.58 64.675 86.65 65.025 ;
      RECT 86.58 65.125 86.65 65.475 ;
      RECT 86.58 65.575 86.65 65.925 ;
      RECT 86.58 66.025 86.65 66.375 ;
      RECT 86.58 80.005 86.65 80.355 ;
      RECT 86.58 80.455 86.65 80.805 ;
      RECT 86.58 80.905 86.65 81.255 ;
      RECT 86.58 81.355 86.65 81.705 ;
      RECT 86.58 81.805 86.65 82.155 ;
      RECT 86.58 82.255 86.65 82.605 ;
      RECT 86.58 82.705 86.65 83.055 ;
      RECT 86.57 85.565 86.64 85.915 ;
      RECT 86.57 86.015 86.64 86.365 ;
      RECT 86.57 86.465 86.64 86.815 ;
      RECT 86.57 86.915 86.64 87.265 ;
      RECT 86.57 87.365 86.64 87.715 ;
      RECT 86.57 87.815 86.64 88.165 ;
      RECT 86.57 88.265 86.64 88.615 ;
      RECT 86.57 102.245 86.64 102.595 ;
      RECT 86.57 102.695 86.64 103.045 ;
      RECT 86.57 103.145 86.64 103.495 ;
      RECT 86.57 103.595 86.64 103.945 ;
      RECT 86.57 104.045 86.64 104.395 ;
      RECT 86.57 104.495 86.64 104.845 ;
      RECT 86.57 104.945 86.64 105.295 ;
      RECT 86.56 107.805 86.63 108.155 ;
      RECT 86.56 108.255 86.63 108.605 ;
      RECT 86.56 108.705 86.63 109.055 ;
      RECT 86.56 109.155 86.63 109.505 ;
      RECT 86.56 109.605 86.63 109.955 ;
      RECT 86.56 110.055 86.63 110.405 ;
      RECT 86.56 110.505 86.63 110.855 ;
      RECT 86.56 124.485 86.63 124.835 ;
      RECT 86.56 124.935 86.63 125.285 ;
      RECT 86.56 125.385 86.63 125.735 ;
      RECT 86.56 125.835 86.63 126.185 ;
      RECT 86.56 126.285 86.63 126.635 ;
      RECT 86.56 126.735 86.63 127.085 ;
      RECT 86.56 127.185 86.63 127.535 ;
      RECT 86.55 130.045 86.62 130.395 ;
      RECT 86.55 130.495 86.62 130.845 ;
      RECT 86.55 130.945 86.62 131.295 ;
      RECT 86.55 131.395 86.62 131.745 ;
      RECT 86.55 131.845 86.62 132.195 ;
      RECT 86.55 132.295 86.62 132.645 ;
      RECT 86.55 132.745 86.62 133.095 ;
      RECT 86.55 146.725 86.62 147.075 ;
      RECT 86.55 147.175 86.62 147.525 ;
      RECT 86.55 147.625 86.62 147.975 ;
      RECT 86.55 148.075 86.62 148.425 ;
      RECT 86.55 148.525 86.62 148.875 ;
      RECT 86.55 148.975 86.62 149.325 ;
      RECT 86.55 149.425 86.62 149.775 ;
      RECT 86.545 2.165 86.615 2.515 ;
      RECT 86.545 2.615 86.615 2.965 ;
      RECT 86.545 3.065 86.615 3.415 ;
      RECT 86.545 3.515 86.615 3.865 ;
      RECT 86.545 3.965 86.615 4.315 ;
      RECT 86.545 4.415 86.615 4.765 ;
      RECT 86.545 4.865 86.615 5.215 ;
      RECT 86.545 24.405 86.615 24.755 ;
      RECT 86.545 24.855 86.615 25.205 ;
      RECT 86.545 25.305 86.615 25.655 ;
      RECT 86.545 25.755 86.615 26.105 ;
      RECT 86.545 26.205 86.615 26.555 ;
      RECT 86.545 26.655 86.615 27.005 ;
      RECT 86.545 27.105 86.615 27.455 ;
      RECT 86.545 29.965 86.615 30.315 ;
      RECT 86.545 30.415 86.615 30.765 ;
      RECT 86.545 30.865 86.615 31.215 ;
      RECT 86.545 31.315 86.615 31.665 ;
      RECT 86.545 31.765 86.615 32.115 ;
      RECT 86.545 32.215 86.615 32.565 ;
      RECT 86.545 32.665 86.615 33.015 ;
      RECT 86.545 41.085 86.615 41.435 ;
      RECT 86.545 41.535 86.615 41.885 ;
      RECT 86.545 41.985 86.615 42.335 ;
      RECT 86.545 42.435 86.615 42.785 ;
      RECT 86.545 42.885 86.615 43.235 ;
      RECT 86.545 43.335 86.615 43.685 ;
      RECT 86.545 43.785 86.615 44.135 ;
      RECT 86.545 46.645 86.615 46.995 ;
      RECT 86.545 47.095 86.615 47.445 ;
      RECT 86.545 47.545 86.615 47.895 ;
      RECT 86.545 47.995 86.615 48.345 ;
      RECT 86.545 48.445 86.615 48.795 ;
      RECT 86.545 48.895 86.615 49.245 ;
      RECT 86.545 49.345 86.615 49.695 ;
      RECT 86.545 52.205 86.615 52.555 ;
      RECT 86.545 52.655 86.615 53.005 ;
      RECT 86.545 53.105 86.615 53.455 ;
      RECT 86.545 53.555 86.615 53.905 ;
      RECT 86.545 54.005 86.615 54.355 ;
      RECT 86.545 54.455 86.615 54.805 ;
      RECT 86.545 54.905 86.615 55.255 ;
      RECT 86.545 68.885 86.615 69.235 ;
      RECT 86.545 69.335 86.615 69.685 ;
      RECT 86.545 69.785 86.615 70.135 ;
      RECT 86.545 70.235 86.615 70.585 ;
      RECT 86.545 70.685 86.615 71.035 ;
      RECT 86.545 71.135 86.615 71.485 ;
      RECT 86.545 71.585 86.615 71.935 ;
      RECT 86.545 74.445 86.615 74.795 ;
      RECT 86.545 74.895 86.615 75.245 ;
      RECT 86.545 75.345 86.615 75.695 ;
      RECT 86.545 75.795 86.615 76.145 ;
      RECT 86.545 76.245 86.615 76.595 ;
      RECT 86.545 76.695 86.615 77.045 ;
      RECT 86.545 77.145 86.615 77.495 ;
      RECT 86.545 91.125 86.615 91.475 ;
      RECT 86.545 91.575 86.615 91.925 ;
      RECT 86.545 92.025 86.615 92.375 ;
      RECT 86.545 92.475 86.615 92.825 ;
      RECT 86.545 92.925 86.615 93.275 ;
      RECT 86.545 93.375 86.615 93.725 ;
      RECT 86.545 93.825 86.615 94.175 ;
      RECT 86.545 96.685 86.615 97.035 ;
      RECT 86.545 97.135 86.615 97.485 ;
      RECT 86.545 97.585 86.615 97.935 ;
      RECT 86.545 98.035 86.615 98.385 ;
      RECT 86.545 98.485 86.615 98.835 ;
      RECT 86.545 98.935 86.615 99.285 ;
      RECT 86.545 99.385 86.615 99.735 ;
      RECT 86.545 113.365 86.615 113.715 ;
      RECT 86.545 113.815 86.615 114.165 ;
      RECT 86.545 114.265 86.615 114.615 ;
      RECT 86.545 114.715 86.615 115.065 ;
      RECT 86.545 115.165 86.615 115.515 ;
      RECT 86.545 115.615 86.615 115.965 ;
      RECT 86.545 116.065 86.615 116.415 ;
      RECT 86.545 118.925 86.615 119.275 ;
      RECT 86.545 119.375 86.615 119.725 ;
      RECT 86.545 119.825 86.615 120.175 ;
      RECT 86.545 120.275 86.615 120.625 ;
      RECT 86.545 120.725 86.615 121.075 ;
      RECT 86.545 121.175 86.615 121.525 ;
      RECT 86.545 121.625 86.615 121.975 ;
      RECT 86.545 135.605 86.615 135.955 ;
      RECT 86.545 136.055 86.615 136.405 ;
      RECT 86.545 136.505 86.615 136.855 ;
      RECT 86.545 136.955 86.615 137.305 ;
      RECT 86.545 137.405 86.615 137.755 ;
      RECT 86.545 137.855 86.615 138.205 ;
      RECT 86.545 138.305 86.615 138.655 ;
      RECT 86.545 141.165 86.615 141.515 ;
      RECT 86.545 141.615 86.615 141.965 ;
      RECT 86.545 142.065 86.615 142.415 ;
      RECT 86.545 142.515 86.615 142.865 ;
      RECT 86.545 142.965 86.615 143.315 ;
      RECT 86.545 143.415 86.615 143.765 ;
      RECT 86.545 143.865 86.615 144.215 ;
      RECT 86.545 157.845 86.615 158.195 ;
      RECT 86.545 158.295 86.615 158.645 ;
      RECT 86.545 158.745 86.615 159.095 ;
      RECT 86.545 159.195 86.615 159.545 ;
      RECT 86.545 159.645 86.615 159.995 ;
      RECT 86.545 160.095 86.615 160.445 ;
      RECT 86.545 160.545 86.615 160.895 ;
      RECT 86.545 163.405 86.615 163.755 ;
      RECT 86.545 163.855 86.615 164.205 ;
      RECT 86.545 164.305 86.615 164.655 ;
      RECT 86.545 164.755 86.615 165.105 ;
      RECT 86.545 165.205 86.615 165.555 ;
      RECT 86.545 165.655 86.615 166.005 ;
      RECT 86.545 166.105 86.615 166.455 ;
      RECT 86.545 168.965 86.615 169.315 ;
      RECT 86.545 169.415 86.615 169.765 ;
      RECT 86.545 169.865 86.615 170.215 ;
      RECT 86.545 170.315 86.615 170.665 ;
      RECT 86.545 170.765 86.615 171.115 ;
      RECT 86.545 171.215 86.615 171.565 ;
      RECT 86.545 171.665 86.615 172.015 ;
      RECT 86.545 180.085 86.615 180.435 ;
      RECT 86.545 180.535 86.615 180.885 ;
      RECT 86.545 180.985 86.615 181.335 ;
      RECT 86.545 181.435 86.615 181.785 ;
      RECT 86.545 181.885 86.615 182.235 ;
      RECT 86.545 182.335 86.615 182.685 ;
      RECT 86.545 182.785 86.615 183.135 ;
      RECT 86.545 185.645 86.615 185.995 ;
      RECT 86.545 186.095 86.615 186.445 ;
      RECT 86.545 186.545 86.615 186.895 ;
      RECT 86.545 186.995 86.615 187.345 ;
      RECT 86.545 187.445 86.615 187.795 ;
      RECT 86.545 187.895 86.615 188.245 ;
      RECT 86.545 188.345 86.615 188.695 ;
      RECT 86.545 202.325 86.615 202.675 ;
      RECT 86.545 202.775 86.615 203.125 ;
      RECT 86.545 203.225 86.615 203.575 ;
      RECT 86.545 203.675 86.615 204.025 ;
      RECT 86.545 204.125 86.615 204.475 ;
      RECT 86.545 204.575 86.615 204.925 ;
      RECT 86.545 205.025 86.615 205.375 ;
      RECT 86.545 207.885 86.615 208.235 ;
      RECT 86.545 208.335 86.615 208.685 ;
      RECT 86.545 208.785 86.615 209.135 ;
      RECT 86.545 209.235 86.615 209.585 ;
      RECT 86.545 209.685 86.615 210.035 ;
      RECT 86.545 210.135 86.615 210.485 ;
      RECT 86.545 210.585 86.615 210.935 ;
      RECT 86.545 224.565 86.615 224.915 ;
      RECT 86.545 225.015 86.615 225.365 ;
      RECT 86.545 225.465 86.615 225.815 ;
      RECT 86.545 225.915 86.615 226.265 ;
      RECT 86.545 226.365 86.615 226.715 ;
      RECT 86.545 226.815 86.615 227.165 ;
      RECT 86.545 227.265 86.615 227.615 ;
      RECT 86.545 230.125 86.615 230.475 ;
      RECT 86.545 230.575 86.615 230.925 ;
      RECT 86.545 231.025 86.615 231.375 ;
      RECT 86.545 231.475 86.615 231.825 ;
      RECT 86.545 231.925 86.615 232.275 ;
      RECT 86.545 232.375 86.615 232.725 ;
      RECT 86.545 232.825 86.615 233.175 ;
      RECT 86.545 235.685 86.615 236.035 ;
      RECT 86.545 236.135 86.615 236.485 ;
      RECT 86.545 236.585 86.615 236.935 ;
      RECT 86.545 237.035 86.615 237.385 ;
      RECT 86.545 237.485 86.615 237.835 ;
      RECT 86.545 237.935 86.615 238.285 ;
      RECT 86.545 238.385 86.615 238.735 ;
      RECT 86.545 246.805 86.615 247.155 ;
      RECT 86.545 247.255 86.615 247.605 ;
      RECT 86.545 247.705 86.615 248.055 ;
      RECT 86.545 248.155 86.615 248.505 ;
      RECT 86.545 248.605 86.615 248.955 ;
      RECT 86.545 249.055 86.615 249.405 ;
      RECT 86.545 249.505 86.615 249.855 ;
      RECT 86.545 252.365 86.615 252.715 ;
      RECT 86.545 252.815 86.615 253.165 ;
      RECT 86.545 253.265 86.615 253.615 ;
      RECT 86.545 253.715 86.615 254.065 ;
      RECT 86.545 254.165 86.615 254.515 ;
      RECT 86.545 254.615 86.615 254.965 ;
      RECT 86.545 255.065 86.615 255.415 ;
      RECT 86.545 274.605 86.615 274.955 ;
      RECT 86.545 275.055 86.615 275.405 ;
      RECT 86.545 275.505 86.615 275.855 ;
      RECT 86.545 275.955 86.615 276.305 ;
      RECT 86.545 276.405 86.615 276.755 ;
      RECT 86.545 276.855 86.615 277.205 ;
      RECT 86.545 277.305 86.615 277.655 ;
      RECT 86.545 280.165 86.615 280.515 ;
      RECT 86.545 280.615 86.615 280.965 ;
      RECT 86.545 281.065 86.615 281.415 ;
      RECT 86.545 281.515 86.615 281.865 ;
      RECT 86.545 281.965 86.615 282.315 ;
      RECT 86.545 282.415 86.615 282.765 ;
      RECT 86.545 282.865 86.615 283.215 ;
      RECT 70.765 4.91 80.315 5.33 ;
      RECT 70.765 10.47 80.315 10.89 ;
      RECT 70.765 16.03 80.315 16.45 ;
      RECT 70.765 21.59 80.315 22.01 ;
      RECT 70.765 27.15 80.315 27.57 ;
      RECT 70.765 32.71 80.315 33.13 ;
      RECT 70.765 38.27 80.315 38.69 ;
      RECT 70.765 43.83 80.315 44.25 ;
      RECT 70.765 49.39 80.315 49.81 ;
      RECT 70.765 54.95 80.315 55.37 ;
      RECT 70.765 60.51 80.315 60.93 ;
      RECT 70.765 66.07 80.315 66.49 ;
      RECT 70.765 71.63 80.315 72.05 ;
      RECT 70.765 77.19 80.315 77.61 ;
      RECT 70.765 82.75 80.315 83.17 ;
      RECT 70.765 88.31 80.315 88.73 ;
      RECT 70.765 93.87 80.315 94.29 ;
      RECT 70.765 99.43 80.315 99.85 ;
      RECT 70.765 104.99 80.315 105.41 ;
      RECT 70.765 110.55 80.315 110.97 ;
      RECT 70.765 116.11 80.315 116.53 ;
      RECT 70.765 121.67 80.315 122.09 ;
      RECT 70.765 127.23 80.315 127.65 ;
      RECT 70.765 132.79 80.315 133.21 ;
      RECT 70.765 138.35 80.315 138.77 ;
      RECT 70.765 143.91 80.315 144.33 ;
      RECT 70.765 149.47 80.315 149.89 ;
      RECT 70.765 155.03 80.315 155.45 ;
      RECT 70.765 160.59 80.315 161.01 ;
      RECT 70.765 166.15 80.315 166.57 ;
      RECT 70.765 171.71 80.315 172.13 ;
      RECT 70.765 177.27 80.315 177.69 ;
      RECT 70.765 182.83 80.315 183.25 ;
      RECT 70.765 188.39 80.315 188.81 ;
      RECT 70.765 193.95 80.315 194.37 ;
      RECT 70.765 199.51 80.315 199.93 ;
      RECT 70.765 205.07 80.315 205.49 ;
      RECT 70.765 210.63 80.315 211.05 ;
      RECT 70.765 216.19 80.315 216.61 ;
      RECT 70.765 221.75 80.315 222.17 ;
      RECT 70.765 227.31 80.315 227.73 ;
      RECT 70.765 232.87 80.315 233.29 ;
      RECT 70.765 238.43 80.315 238.85 ;
      RECT 70.765 243.99 80.315 244.41 ;
      RECT 70.765 249.55 80.315 249.97 ;
      RECT 70.765 255.11 80.315 255.53 ;
      RECT 70.765 260.67 80.315 261.09 ;
      RECT 70.765 266.23 80.315 266.65 ;
      RECT 70.765 271.79 80.315 272.21 ;
      RECT 70.765 277.35 80.315 277.77 ;
      RECT 70.765 282.91 80.315 283.33 ;
      RECT 70.765 288.47 80.315 288.89 ;
      RECT 70.765 294.03 80.315 294.45 ;
      RECT 75.565 1.38 75.635 1.73 ;
      RECT 75.565 1.83 75.635 2.18 ;
      RECT 75.565 2.28 75.635 2.63 ;
      RECT 75.565 2.73 75.635 3.08 ;
      RECT 75.565 3.18 75.635 3.53 ;
      RECT 75.565 3.63 75.635 3.98 ;
      RECT 75.565 4.08 75.635 4.43 ;
      RECT 75.565 12.825 75.635 13.175 ;
      RECT 75.565 13.275 75.635 13.625 ;
      RECT 75.565 13.725 75.635 14.075 ;
      RECT 75.565 14.175 75.635 14.525 ;
      RECT 75.565 14.625 75.635 14.975 ;
      RECT 75.565 15.075 75.635 15.425 ;
      RECT 75.565 18.445 75.635 18.795 ;
      RECT 75.565 18.895 75.635 19.245 ;
      RECT 75.565 19.345 75.635 19.695 ;
      RECT 75.565 19.795 75.635 20.145 ;
      RECT 75.565 20.245 75.635 20.595 ;
      RECT 75.565 20.695 75.635 21.045 ;
      RECT 75.565 23.61 75.635 23.96 ;
      RECT 75.565 24.06 75.635 24.41 ;
      RECT 75.565 24.51 75.635 24.86 ;
      RECT 75.565 24.96 75.635 25.31 ;
      RECT 75.565 25.41 75.635 25.76 ;
      RECT 75.565 25.86 75.635 26.21 ;
      RECT 75.565 26.31 75.635 26.66 ;
      RECT 75.565 29.13 75.635 29.48 ;
      RECT 75.565 29.58 75.635 29.93 ;
      RECT 75.565 30.03 75.635 30.38 ;
      RECT 75.565 30.48 75.635 30.83 ;
      RECT 75.565 30.93 75.635 31.28 ;
      RECT 75.565 31.38 75.635 31.73 ;
      RECT 75.565 31.83 75.635 32.18 ;
      RECT 75.565 35.065 75.635 35.415 ;
      RECT 75.565 35.515 75.635 35.865 ;
      RECT 75.565 35.965 75.635 36.315 ;
      RECT 75.565 36.415 75.635 36.765 ;
      RECT 75.565 36.865 75.635 37.215 ;
      RECT 75.565 37.315 75.635 37.665 ;
      RECT 75.565 40.625 75.635 40.975 ;
      RECT 75.565 41.075 75.635 41.425 ;
      RECT 75.565 41.525 75.635 41.875 ;
      RECT 75.565 41.975 75.635 42.325 ;
      RECT 75.565 42.425 75.635 42.775 ;
      RECT 75.565 42.875 75.635 43.225 ;
      RECT 75.565 45.87 75.635 46.22 ;
      RECT 75.565 46.32 75.635 46.67 ;
      RECT 75.565 46.77 75.635 47.12 ;
      RECT 75.565 47.22 75.635 47.57 ;
      RECT 75.565 47.67 75.635 48.02 ;
      RECT 75.565 48.12 75.635 48.47 ;
      RECT 75.565 48.57 75.635 48.92 ;
      RECT 75.565 51.81 75.635 52.16 ;
      RECT 75.565 52.26 75.635 52.61 ;
      RECT 75.565 52.71 75.635 53.06 ;
      RECT 75.565 53.16 75.635 53.51 ;
      RECT 75.565 53.61 75.635 53.96 ;
      RECT 75.565 54.06 75.635 54.41 ;
      RECT 75.565 57.305 75.635 57.655 ;
      RECT 75.565 57.755 75.635 58.105 ;
      RECT 75.565 58.205 75.635 58.555 ;
      RECT 75.565 58.655 75.635 59.005 ;
      RECT 75.565 59.105 75.635 59.455 ;
      RECT 75.565 59.555 75.635 59.905 ;
      RECT 75.565 62.865 75.635 63.215 ;
      RECT 75.565 63.315 75.635 63.665 ;
      RECT 75.565 63.765 75.635 64.115 ;
      RECT 75.565 64.215 75.635 64.565 ;
      RECT 75.565 64.665 75.635 65.015 ;
      RECT 75.565 65.115 75.635 65.465 ;
      RECT 75.565 68.1 75.635 68.45 ;
      RECT 75.565 68.55 75.635 68.9 ;
      RECT 75.565 69 75.635 69.35 ;
      RECT 75.565 69.45 75.635 69.8 ;
      RECT 75.565 69.9 75.635 70.25 ;
      RECT 75.565 70.35 75.635 70.7 ;
      RECT 75.565 70.8 75.635 71.15 ;
      RECT 75.565 73.62 75.635 73.97 ;
      RECT 75.565 74.07 75.635 74.42 ;
      RECT 75.565 74.52 75.635 74.87 ;
      RECT 75.565 74.97 75.635 75.32 ;
      RECT 75.565 75.42 75.635 75.77 ;
      RECT 75.565 75.87 75.635 76.22 ;
      RECT 75.565 76.32 75.635 76.67 ;
      RECT 75.565 79.545 75.635 79.895 ;
      RECT 75.565 79.995 75.635 80.345 ;
      RECT 75.565 80.445 75.635 80.795 ;
      RECT 75.565 80.895 75.635 81.245 ;
      RECT 75.565 81.345 75.635 81.695 ;
      RECT 75.565 81.795 75.635 82.145 ;
      RECT 75.565 85.105 75.635 85.455 ;
      RECT 75.565 85.555 75.635 85.905 ;
      RECT 75.565 86.005 75.635 86.355 ;
      RECT 75.565 86.455 75.635 86.805 ;
      RECT 75.565 86.905 75.635 87.255 ;
      RECT 75.565 87.355 75.635 87.705 ;
      RECT 75.565 90.36 75.635 90.71 ;
      RECT 75.565 90.81 75.635 91.16 ;
      RECT 75.565 91.26 75.635 91.61 ;
      RECT 75.565 91.71 75.635 92.06 ;
      RECT 75.565 92.16 75.635 92.51 ;
      RECT 75.565 92.61 75.635 92.96 ;
      RECT 75.565 93.06 75.635 93.41 ;
      RECT 75.565 95.85 75.635 96.2 ;
      RECT 75.565 96.3 75.635 96.65 ;
      RECT 75.565 96.75 75.635 97.1 ;
      RECT 75.565 97.2 75.635 97.55 ;
      RECT 75.565 97.65 75.635 98 ;
      RECT 75.565 98.1 75.635 98.45 ;
      RECT 75.565 98.55 75.635 98.9 ;
      RECT 75.565 101.785 75.635 102.135 ;
      RECT 75.565 102.235 75.635 102.585 ;
      RECT 75.565 102.685 75.635 103.035 ;
      RECT 75.565 103.135 75.635 103.485 ;
      RECT 75.565 103.585 75.635 103.935 ;
      RECT 75.565 104.035 75.635 104.385 ;
      RECT 75.565 107.345 75.635 107.695 ;
      RECT 75.565 107.795 75.635 108.145 ;
      RECT 75.565 108.245 75.635 108.595 ;
      RECT 75.565 108.695 75.635 109.045 ;
      RECT 75.565 109.145 75.635 109.495 ;
      RECT 75.565 109.595 75.635 109.945 ;
      RECT 75.565 112.59 75.635 112.94 ;
      RECT 75.565 113.04 75.635 113.39 ;
      RECT 75.565 113.49 75.635 113.84 ;
      RECT 75.565 113.94 75.635 114.29 ;
      RECT 75.565 114.39 75.635 114.74 ;
      RECT 75.565 114.84 75.635 115.19 ;
      RECT 75.565 115.29 75.635 115.64 ;
      RECT 75.565 118.11 75.635 118.46 ;
      RECT 75.565 118.56 75.635 118.91 ;
      RECT 75.565 119.01 75.635 119.36 ;
      RECT 75.565 119.46 75.635 119.81 ;
      RECT 75.565 119.91 75.635 120.26 ;
      RECT 75.565 120.36 75.635 120.71 ;
      RECT 75.565 120.81 75.635 121.16 ;
      RECT 75.565 124.025 75.635 124.375 ;
      RECT 75.565 124.475 75.635 124.825 ;
      RECT 75.565 124.925 75.635 125.275 ;
      RECT 75.565 125.375 75.635 125.725 ;
      RECT 75.565 125.825 75.635 126.175 ;
      RECT 75.565 126.275 75.635 126.625 ;
      RECT 75.565 129.585 75.635 129.935 ;
      RECT 75.565 130.035 75.635 130.385 ;
      RECT 75.565 130.485 75.635 130.835 ;
      RECT 75.565 130.935 75.635 131.285 ;
      RECT 75.565 131.385 75.635 131.735 ;
      RECT 75.565 131.835 75.635 132.185 ;
      RECT 75.565 134.85 75.635 135.2 ;
      RECT 75.565 135.3 75.635 135.65 ;
      RECT 75.565 135.75 75.635 136.1 ;
      RECT 75.565 136.2 75.635 136.55 ;
      RECT 75.565 136.65 75.635 137 ;
      RECT 75.565 137.1 75.635 137.45 ;
      RECT 75.565 137.55 75.635 137.9 ;
      RECT 75.565 140.34 75.635 140.69 ;
      RECT 75.565 140.79 75.635 141.14 ;
      RECT 75.565 141.24 75.635 141.59 ;
      RECT 75.565 141.69 75.635 142.04 ;
      RECT 75.565 142.14 75.635 142.49 ;
      RECT 75.565 142.59 75.635 142.94 ;
      RECT 75.565 143.04 75.635 143.39 ;
      RECT 75.565 146.265 75.635 146.615 ;
      RECT 75.565 146.715 75.635 147.065 ;
      RECT 75.565 147.165 75.635 147.515 ;
      RECT 75.565 147.615 75.635 147.965 ;
      RECT 75.565 148.065 75.635 148.415 ;
      RECT 75.565 148.515 75.635 148.865 ;
      RECT 75.565 151.825 75.635 152.175 ;
      RECT 75.565 152.275 75.635 152.625 ;
      RECT 75.565 152.725 75.635 153.075 ;
      RECT 75.565 153.175 75.635 153.525 ;
      RECT 75.565 153.625 75.635 153.975 ;
      RECT 75.565 154.075 75.635 154.425 ;
      RECT 75.565 157.08 75.635 157.43 ;
      RECT 75.565 157.53 75.635 157.88 ;
      RECT 75.565 157.98 75.635 158.33 ;
      RECT 75.565 158.43 75.635 158.78 ;
      RECT 75.565 158.88 75.635 159.23 ;
      RECT 75.565 159.33 75.635 159.68 ;
      RECT 75.565 159.78 75.635 160.13 ;
      RECT 75.565 162.6 75.635 162.95 ;
      RECT 75.565 163.05 75.635 163.4 ;
      RECT 75.565 163.5 75.635 163.85 ;
      RECT 75.565 163.95 75.635 164.3 ;
      RECT 75.565 164.4 75.635 164.75 ;
      RECT 75.565 164.85 75.635 165.2 ;
      RECT 75.565 165.3 75.635 165.65 ;
      RECT 75.565 168.505 75.635 168.855 ;
      RECT 75.565 168.955 75.635 169.305 ;
      RECT 75.565 169.405 75.635 169.755 ;
      RECT 75.565 169.855 75.635 170.205 ;
      RECT 75.565 170.305 75.635 170.655 ;
      RECT 75.565 170.755 75.635 171.105 ;
      RECT 75.565 174.065 75.635 174.415 ;
      RECT 75.565 174.515 75.635 174.865 ;
      RECT 75.565 174.965 75.635 175.315 ;
      RECT 75.565 175.415 75.635 175.765 ;
      RECT 75.565 175.865 75.635 176.215 ;
      RECT 75.565 176.315 75.635 176.665 ;
      RECT 75.565 179.34 75.635 179.69 ;
      RECT 75.565 179.79 75.635 180.14 ;
      RECT 75.565 180.24 75.635 180.59 ;
      RECT 75.565 180.69 75.635 181.04 ;
      RECT 75.565 181.14 75.635 181.49 ;
      RECT 75.565 181.59 75.635 181.94 ;
      RECT 75.565 182.04 75.635 182.39 ;
      RECT 75.565 184.83 75.635 185.18 ;
      RECT 75.565 185.28 75.635 185.63 ;
      RECT 75.565 185.73 75.635 186.08 ;
      RECT 75.565 186.18 75.635 186.53 ;
      RECT 75.565 186.63 75.635 186.98 ;
      RECT 75.565 187.08 75.635 187.43 ;
      RECT 75.565 187.53 75.635 187.88 ;
      RECT 75.565 190.745 75.635 191.095 ;
      RECT 75.565 191.195 75.635 191.545 ;
      RECT 75.565 191.645 75.635 191.995 ;
      RECT 75.565 192.095 75.635 192.445 ;
      RECT 75.565 192.545 75.635 192.895 ;
      RECT 75.565 192.995 75.635 193.345 ;
      RECT 75.565 196.305 75.635 196.655 ;
      RECT 75.565 196.755 75.635 197.105 ;
      RECT 75.565 197.205 75.635 197.555 ;
      RECT 75.565 197.655 75.635 198.005 ;
      RECT 75.565 198.105 75.635 198.455 ;
      RECT 75.565 198.555 75.635 198.905 ;
      RECT 75.565 201.57 75.635 201.92 ;
      RECT 75.565 202.02 75.635 202.37 ;
      RECT 75.565 202.47 75.635 202.82 ;
      RECT 75.565 202.92 75.635 203.27 ;
      RECT 75.565 203.37 75.635 203.72 ;
      RECT 75.565 203.82 75.635 204.17 ;
      RECT 75.565 204.27 75.635 204.62 ;
      RECT 75.565 207.09 75.635 207.44 ;
      RECT 75.565 207.54 75.635 207.89 ;
      RECT 75.565 207.99 75.635 208.34 ;
      RECT 75.565 208.44 75.635 208.79 ;
      RECT 75.565 208.89 75.635 209.24 ;
      RECT 75.565 209.34 75.635 209.69 ;
      RECT 75.565 209.79 75.635 210.14 ;
      RECT 75.565 212.985 75.635 213.335 ;
      RECT 75.565 213.435 75.635 213.785 ;
      RECT 75.565 213.885 75.635 214.235 ;
      RECT 75.565 214.335 75.635 214.685 ;
      RECT 75.565 214.785 75.635 215.135 ;
      RECT 75.565 215.235 75.635 215.585 ;
      RECT 75.565 218.545 75.635 218.895 ;
      RECT 75.565 218.995 75.635 219.345 ;
      RECT 75.565 219.445 75.635 219.795 ;
      RECT 75.565 219.895 75.635 220.245 ;
      RECT 75.565 220.345 75.635 220.695 ;
      RECT 75.565 220.795 75.635 221.145 ;
      RECT 75.565 224.165 75.635 224.515 ;
      RECT 75.565 224.615 75.635 224.965 ;
      RECT 75.565 225.065 75.635 225.415 ;
      RECT 75.565 225.515 75.635 225.865 ;
      RECT 75.565 225.965 75.635 226.315 ;
      RECT 75.565 226.415 75.635 226.765 ;
      RECT 75.565 229.32 75.635 229.67 ;
      RECT 75.565 229.77 75.635 230.12 ;
      RECT 75.565 230.22 75.635 230.57 ;
      RECT 75.565 230.67 75.635 231.02 ;
      RECT 75.565 231.12 75.635 231.47 ;
      RECT 75.565 231.57 75.635 231.92 ;
      RECT 75.565 232.02 75.635 232.37 ;
      RECT 75.565 235.29 75.635 235.64 ;
      RECT 75.565 235.74 75.635 236.09 ;
      RECT 75.565 236.19 75.635 236.54 ;
      RECT 75.565 236.64 75.635 236.99 ;
      RECT 75.565 237.09 75.635 237.44 ;
      RECT 75.565 237.54 75.635 237.89 ;
      RECT 75.565 240.785 75.635 241.135 ;
      RECT 75.565 241.235 75.635 241.585 ;
      RECT 75.565 241.685 75.635 242.035 ;
      RECT 75.565 242.135 75.635 242.485 ;
      RECT 75.565 242.585 75.635 242.935 ;
      RECT 75.565 243.035 75.635 243.385 ;
      RECT 75.565 246.06 75.635 246.41 ;
      RECT 75.565 246.51 75.635 246.86 ;
      RECT 75.565 246.96 75.635 247.31 ;
      RECT 75.565 247.41 75.635 247.76 ;
      RECT 75.565 247.86 75.635 248.21 ;
      RECT 75.565 248.31 75.635 248.66 ;
      RECT 75.565 248.76 75.635 249.11 ;
      RECT 75.565 251.58 75.635 251.93 ;
      RECT 75.565 252.03 75.635 252.38 ;
      RECT 75.565 252.48 75.635 252.83 ;
      RECT 75.565 252.93 75.635 253.28 ;
      RECT 75.565 253.38 75.635 253.73 ;
      RECT 75.565 253.83 75.635 254.18 ;
      RECT 75.565 254.28 75.635 254.63 ;
      RECT 75.565 263.025 75.635 263.375 ;
      RECT 75.565 263.475 75.635 263.825 ;
      RECT 75.565 263.925 75.635 264.275 ;
      RECT 75.565 264.375 75.635 264.725 ;
      RECT 75.565 264.825 75.635 265.175 ;
      RECT 75.565 265.275 75.635 265.625 ;
      RECT 75.565 268.645 75.635 268.995 ;
      RECT 75.565 269.095 75.635 269.445 ;
      RECT 75.565 269.545 75.635 269.895 ;
      RECT 75.565 269.995 75.635 270.345 ;
      RECT 75.565 270.445 75.635 270.795 ;
      RECT 75.565 270.895 75.635 271.245 ;
      RECT 75.565 273.81 75.635 274.16 ;
      RECT 75.565 274.26 75.635 274.61 ;
      RECT 75.565 274.71 75.635 275.06 ;
      RECT 75.565 275.16 75.635 275.51 ;
      RECT 75.565 275.61 75.635 275.96 ;
      RECT 75.565 276.06 75.635 276.41 ;
      RECT 75.565 276.51 75.635 276.86 ;
      RECT 75.565 279.33 75.635 279.68 ;
      RECT 75.565 279.78 75.635 280.13 ;
      RECT 75.565 280.23 75.635 280.58 ;
      RECT 75.565 280.68 75.635 281.03 ;
      RECT 75.565 281.13 75.635 281.48 ;
      RECT 75.565 281.58 75.635 281.93 ;
      RECT 75.565 282.03 75.635 282.38 ;
      RECT 75.565 285.265 75.635 285.615 ;
      RECT 75.565 285.715 75.635 286.065 ;
      RECT 75.565 286.165 75.635 286.515 ;
      RECT 75.565 286.615 75.635 286.965 ;
      RECT 75.565 287.065 75.635 287.415 ;
      RECT 75.565 287.515 75.635 287.865 ;
      RECT 75.565 290.825 75.635 291.175 ;
      RECT 75.565 291.275 75.635 291.625 ;
      RECT 75.565 291.725 75.635 292.075 ;
      RECT 75.565 292.175 75.635 292.525 ;
      RECT 75.565 292.625 75.635 292.975 ;
      RECT 75.565 293.075 75.635 293.425 ;
      RECT 75.48 257.525 75.55 257.875 ;
      RECT 75.48 257.975 75.55 258.325 ;
      RECT 75.48 258.425 75.55 258.775 ;
      RECT 75.48 258.875 75.55 259.225 ;
      RECT 75.48 259.325 75.55 259.675 ;
      RECT 75.48 259.775 75.55 260.125 ;
      RECT 75.46 7.325 75.53 7.675 ;
      RECT 75.46 7.775 75.53 8.125 ;
      RECT 75.46 8.225 75.53 8.575 ;
      RECT 75.46 8.675 75.53 9.025 ;
      RECT 75.46 9.125 75.53 9.475 ;
      RECT 75.46 9.575 75.53 9.925 ;
      RECT 75.425 1.38 75.495 1.73 ;
      RECT 75.425 1.83 75.495 2.18 ;
      RECT 75.425 2.28 75.495 2.63 ;
      RECT 75.425 2.73 75.495 3.08 ;
      RECT 75.425 3.18 75.495 3.53 ;
      RECT 75.425 3.63 75.495 3.98 ;
      RECT 75.425 4.08 75.495 4.43 ;
      RECT 75.425 12.825 75.495 13.175 ;
      RECT 75.425 13.275 75.495 13.625 ;
      RECT 75.425 13.725 75.495 14.075 ;
      RECT 75.425 14.175 75.495 14.525 ;
      RECT 75.425 14.625 75.495 14.975 ;
      RECT 75.425 15.075 75.495 15.425 ;
      RECT 75.425 18.445 75.495 18.795 ;
      RECT 75.425 18.895 75.495 19.245 ;
      RECT 75.425 19.345 75.495 19.695 ;
      RECT 75.425 19.795 75.495 20.145 ;
      RECT 75.425 20.245 75.495 20.595 ;
      RECT 75.425 20.695 75.495 21.045 ;
      RECT 75.425 23.61 75.495 23.96 ;
      RECT 75.425 24.06 75.495 24.41 ;
      RECT 75.425 24.51 75.495 24.86 ;
      RECT 75.425 24.96 75.495 25.31 ;
      RECT 75.425 25.41 75.495 25.76 ;
      RECT 75.425 25.86 75.495 26.21 ;
      RECT 75.425 26.31 75.495 26.66 ;
      RECT 75.425 29.13 75.495 29.48 ;
      RECT 75.425 29.58 75.495 29.93 ;
      RECT 75.425 30.03 75.495 30.38 ;
      RECT 75.425 30.48 75.495 30.83 ;
      RECT 75.425 30.93 75.495 31.28 ;
      RECT 75.425 31.38 75.495 31.73 ;
      RECT 75.425 31.83 75.495 32.18 ;
      RECT 75.425 35.065 75.495 35.415 ;
      RECT 75.425 35.515 75.495 35.865 ;
      RECT 75.425 35.965 75.495 36.315 ;
      RECT 75.425 36.415 75.495 36.765 ;
      RECT 75.425 36.865 75.495 37.215 ;
      RECT 75.425 37.315 75.495 37.665 ;
      RECT 75.425 40.625 75.495 40.975 ;
      RECT 75.425 41.075 75.495 41.425 ;
      RECT 75.425 41.525 75.495 41.875 ;
      RECT 75.425 41.975 75.495 42.325 ;
      RECT 75.425 42.425 75.495 42.775 ;
      RECT 75.425 42.875 75.495 43.225 ;
      RECT 75.425 45.87 75.495 46.22 ;
      RECT 75.425 46.32 75.495 46.67 ;
      RECT 75.425 46.77 75.495 47.12 ;
      RECT 75.425 47.22 75.495 47.57 ;
      RECT 75.425 47.67 75.495 48.02 ;
      RECT 75.425 48.12 75.495 48.47 ;
      RECT 75.425 48.57 75.495 48.92 ;
      RECT 75.425 51.81 75.495 52.16 ;
      RECT 75.425 52.26 75.495 52.61 ;
      RECT 75.425 52.71 75.495 53.06 ;
      RECT 75.425 53.16 75.495 53.51 ;
      RECT 75.425 53.61 75.495 53.96 ;
      RECT 75.425 54.06 75.495 54.41 ;
      RECT 75.425 57.305 75.495 57.655 ;
      RECT 75.425 57.755 75.495 58.105 ;
      RECT 75.425 58.205 75.495 58.555 ;
      RECT 75.425 58.655 75.495 59.005 ;
      RECT 75.425 59.105 75.495 59.455 ;
      RECT 75.425 59.555 75.495 59.905 ;
      RECT 75.425 62.865 75.495 63.215 ;
      RECT 75.425 63.315 75.495 63.665 ;
      RECT 75.425 63.765 75.495 64.115 ;
      RECT 75.425 64.215 75.495 64.565 ;
      RECT 75.425 64.665 75.495 65.015 ;
      RECT 75.425 65.115 75.495 65.465 ;
      RECT 75.425 68.1 75.495 68.45 ;
      RECT 75.425 68.55 75.495 68.9 ;
      RECT 75.425 69 75.495 69.35 ;
      RECT 75.425 69.45 75.495 69.8 ;
      RECT 75.425 69.9 75.495 70.25 ;
      RECT 75.425 70.35 75.495 70.7 ;
      RECT 75.425 70.8 75.495 71.15 ;
      RECT 75.425 73.62 75.495 73.97 ;
      RECT 75.425 74.07 75.495 74.42 ;
      RECT 75.425 74.52 75.495 74.87 ;
      RECT 75.425 74.97 75.495 75.32 ;
      RECT 75.425 75.42 75.495 75.77 ;
      RECT 75.425 75.87 75.495 76.22 ;
      RECT 75.425 76.32 75.495 76.67 ;
      RECT 75.425 79.545 75.495 79.895 ;
      RECT 75.425 79.995 75.495 80.345 ;
      RECT 75.425 80.445 75.495 80.795 ;
      RECT 75.425 80.895 75.495 81.245 ;
      RECT 75.425 81.345 75.495 81.695 ;
      RECT 75.425 81.795 75.495 82.145 ;
      RECT 75.425 85.105 75.495 85.455 ;
      RECT 75.425 85.555 75.495 85.905 ;
      RECT 75.425 86.005 75.495 86.355 ;
      RECT 75.425 86.455 75.495 86.805 ;
      RECT 75.425 86.905 75.495 87.255 ;
      RECT 75.425 87.355 75.495 87.705 ;
      RECT 75.425 90.36 75.495 90.71 ;
      RECT 75.425 90.81 75.495 91.16 ;
      RECT 75.425 91.26 75.495 91.61 ;
      RECT 75.425 91.71 75.495 92.06 ;
      RECT 75.425 92.16 75.495 92.51 ;
      RECT 75.425 92.61 75.495 92.96 ;
      RECT 75.425 93.06 75.495 93.41 ;
      RECT 75.425 95.85 75.495 96.2 ;
      RECT 75.425 96.3 75.495 96.65 ;
      RECT 75.425 96.75 75.495 97.1 ;
      RECT 75.425 97.2 75.495 97.55 ;
      RECT 75.425 97.65 75.495 98 ;
      RECT 75.425 98.1 75.495 98.45 ;
      RECT 75.425 98.55 75.495 98.9 ;
      RECT 75.425 101.785 75.495 102.135 ;
      RECT 75.425 102.235 75.495 102.585 ;
      RECT 75.425 102.685 75.495 103.035 ;
      RECT 75.425 103.135 75.495 103.485 ;
      RECT 75.425 103.585 75.495 103.935 ;
      RECT 75.425 104.035 75.495 104.385 ;
      RECT 75.425 107.345 75.495 107.695 ;
      RECT 75.425 107.795 75.495 108.145 ;
      RECT 75.425 108.245 75.495 108.595 ;
      RECT 75.425 108.695 75.495 109.045 ;
      RECT 75.425 109.145 75.495 109.495 ;
      RECT 75.425 109.595 75.495 109.945 ;
      RECT 75.425 112.59 75.495 112.94 ;
      RECT 75.425 113.04 75.495 113.39 ;
      RECT 75.425 113.49 75.495 113.84 ;
      RECT 75.425 113.94 75.495 114.29 ;
      RECT 75.425 114.39 75.495 114.74 ;
      RECT 75.425 114.84 75.495 115.19 ;
      RECT 75.425 115.29 75.495 115.64 ;
      RECT 75.425 118.11 75.495 118.46 ;
      RECT 75.425 118.56 75.495 118.91 ;
      RECT 75.425 119.01 75.495 119.36 ;
      RECT 75.425 119.46 75.495 119.81 ;
      RECT 75.425 119.91 75.495 120.26 ;
      RECT 75.425 120.36 75.495 120.71 ;
      RECT 75.425 120.81 75.495 121.16 ;
      RECT 75.425 124.025 75.495 124.375 ;
      RECT 75.425 124.475 75.495 124.825 ;
      RECT 75.425 124.925 75.495 125.275 ;
      RECT 75.425 125.375 75.495 125.725 ;
      RECT 75.425 125.825 75.495 126.175 ;
      RECT 75.425 126.275 75.495 126.625 ;
      RECT 75.425 129.585 75.495 129.935 ;
      RECT 75.425 130.035 75.495 130.385 ;
      RECT 75.425 130.485 75.495 130.835 ;
      RECT 75.425 130.935 75.495 131.285 ;
      RECT 75.425 131.385 75.495 131.735 ;
      RECT 75.425 131.835 75.495 132.185 ;
      RECT 75.425 134.85 75.495 135.2 ;
      RECT 75.425 135.3 75.495 135.65 ;
      RECT 75.425 135.75 75.495 136.1 ;
      RECT 75.425 136.2 75.495 136.55 ;
      RECT 75.425 136.65 75.495 137 ;
      RECT 75.425 137.1 75.495 137.45 ;
      RECT 75.425 137.55 75.495 137.9 ;
      RECT 75.425 140.34 75.495 140.69 ;
      RECT 75.425 140.79 75.495 141.14 ;
      RECT 75.425 141.24 75.495 141.59 ;
      RECT 75.425 141.69 75.495 142.04 ;
      RECT 75.425 142.14 75.495 142.49 ;
      RECT 75.425 142.59 75.495 142.94 ;
      RECT 75.425 143.04 75.495 143.39 ;
      RECT 75.425 146.265 75.495 146.615 ;
      RECT 75.425 146.715 75.495 147.065 ;
      RECT 75.425 147.165 75.495 147.515 ;
      RECT 75.425 147.615 75.495 147.965 ;
      RECT 75.425 148.065 75.495 148.415 ;
      RECT 75.425 148.515 75.495 148.865 ;
      RECT 75.425 151.825 75.495 152.175 ;
      RECT 75.425 152.275 75.495 152.625 ;
      RECT 75.425 152.725 75.495 153.075 ;
      RECT 75.425 153.175 75.495 153.525 ;
      RECT 75.425 153.625 75.495 153.975 ;
      RECT 75.425 154.075 75.495 154.425 ;
      RECT 75.425 157.08 75.495 157.43 ;
      RECT 75.425 157.53 75.495 157.88 ;
      RECT 75.425 157.98 75.495 158.33 ;
      RECT 75.425 158.43 75.495 158.78 ;
      RECT 75.425 158.88 75.495 159.23 ;
      RECT 75.425 159.33 75.495 159.68 ;
      RECT 75.425 159.78 75.495 160.13 ;
      RECT 75.425 162.6 75.495 162.95 ;
      RECT 75.425 163.05 75.495 163.4 ;
      RECT 75.425 163.5 75.495 163.85 ;
      RECT 75.425 163.95 75.495 164.3 ;
      RECT 75.425 164.4 75.495 164.75 ;
      RECT 75.425 164.85 75.495 165.2 ;
      RECT 75.425 165.3 75.495 165.65 ;
      RECT 75.425 168.505 75.495 168.855 ;
      RECT 75.425 168.955 75.495 169.305 ;
      RECT 75.425 169.405 75.495 169.755 ;
      RECT 75.425 169.855 75.495 170.205 ;
      RECT 75.425 170.305 75.495 170.655 ;
      RECT 75.425 170.755 75.495 171.105 ;
      RECT 75.425 174.065 75.495 174.415 ;
      RECT 75.425 174.515 75.495 174.865 ;
      RECT 75.425 174.965 75.495 175.315 ;
      RECT 75.425 175.415 75.495 175.765 ;
      RECT 75.425 175.865 75.495 176.215 ;
      RECT 75.425 176.315 75.495 176.665 ;
      RECT 75.425 179.34 75.495 179.69 ;
      RECT 75.425 179.79 75.495 180.14 ;
      RECT 75.425 180.24 75.495 180.59 ;
      RECT 75.425 180.69 75.495 181.04 ;
      RECT 75.425 181.14 75.495 181.49 ;
      RECT 75.425 181.59 75.495 181.94 ;
      RECT 75.425 182.04 75.495 182.39 ;
      RECT 75.425 184.83 75.495 185.18 ;
      RECT 75.425 185.28 75.495 185.63 ;
      RECT 75.425 185.73 75.495 186.08 ;
      RECT 75.425 186.18 75.495 186.53 ;
      RECT 75.425 186.63 75.495 186.98 ;
      RECT 75.425 187.08 75.495 187.43 ;
      RECT 75.425 187.53 75.495 187.88 ;
      RECT 75.425 190.745 75.495 191.095 ;
      RECT 75.425 191.195 75.495 191.545 ;
      RECT 75.425 191.645 75.495 191.995 ;
      RECT 75.425 192.095 75.495 192.445 ;
      RECT 75.425 192.545 75.495 192.895 ;
      RECT 75.425 192.995 75.495 193.345 ;
      RECT 75.425 196.305 75.495 196.655 ;
      RECT 75.425 196.755 75.495 197.105 ;
      RECT 75.425 197.205 75.495 197.555 ;
      RECT 75.425 197.655 75.495 198.005 ;
      RECT 75.425 198.105 75.495 198.455 ;
      RECT 75.425 198.555 75.495 198.905 ;
      RECT 75.425 201.57 75.495 201.92 ;
      RECT 75.425 202.02 75.495 202.37 ;
      RECT 75.425 202.47 75.495 202.82 ;
      RECT 75.425 202.92 75.495 203.27 ;
      RECT 75.425 203.37 75.495 203.72 ;
      RECT 75.425 203.82 75.495 204.17 ;
      RECT 75.425 204.27 75.495 204.62 ;
      RECT 75.425 207.09 75.495 207.44 ;
      RECT 75.425 207.54 75.495 207.89 ;
      RECT 75.425 207.99 75.495 208.34 ;
      RECT 75.425 208.44 75.495 208.79 ;
      RECT 75.425 208.89 75.495 209.24 ;
      RECT 75.425 209.34 75.495 209.69 ;
      RECT 75.425 209.79 75.495 210.14 ;
      RECT 75.425 212.985 75.495 213.335 ;
      RECT 75.425 213.435 75.495 213.785 ;
      RECT 75.425 213.885 75.495 214.235 ;
      RECT 75.425 214.335 75.495 214.685 ;
      RECT 75.425 214.785 75.495 215.135 ;
      RECT 75.425 215.235 75.495 215.585 ;
      RECT 75.425 218.545 75.495 218.895 ;
      RECT 75.425 218.995 75.495 219.345 ;
      RECT 75.425 219.445 75.495 219.795 ;
      RECT 75.425 219.895 75.495 220.245 ;
      RECT 75.425 220.345 75.495 220.695 ;
      RECT 75.425 220.795 75.495 221.145 ;
      RECT 75.425 224.165 75.495 224.515 ;
      RECT 75.425 224.615 75.495 224.965 ;
      RECT 75.425 225.065 75.495 225.415 ;
      RECT 75.425 225.515 75.495 225.865 ;
      RECT 75.425 225.965 75.495 226.315 ;
      RECT 75.425 226.415 75.495 226.765 ;
      RECT 75.425 229.32 75.495 229.67 ;
      RECT 75.425 229.77 75.495 230.12 ;
      RECT 75.425 230.22 75.495 230.57 ;
      RECT 75.425 230.67 75.495 231.02 ;
      RECT 75.425 231.12 75.495 231.47 ;
      RECT 75.425 231.57 75.495 231.92 ;
      RECT 75.425 232.02 75.495 232.37 ;
      RECT 75.425 235.29 75.495 235.64 ;
      RECT 75.425 235.74 75.495 236.09 ;
      RECT 75.425 236.19 75.495 236.54 ;
      RECT 75.425 236.64 75.495 236.99 ;
      RECT 75.425 237.09 75.495 237.44 ;
      RECT 75.425 237.54 75.495 237.89 ;
      RECT 75.425 240.785 75.495 241.135 ;
      RECT 75.425 241.235 75.495 241.585 ;
      RECT 75.425 241.685 75.495 242.035 ;
      RECT 75.425 242.135 75.495 242.485 ;
      RECT 75.425 242.585 75.495 242.935 ;
      RECT 75.425 243.035 75.495 243.385 ;
      RECT 75.425 246.06 75.495 246.41 ;
      RECT 75.425 246.51 75.495 246.86 ;
      RECT 75.425 246.96 75.495 247.31 ;
      RECT 75.425 247.41 75.495 247.76 ;
      RECT 75.425 247.86 75.495 248.21 ;
      RECT 75.425 248.31 75.495 248.66 ;
      RECT 75.425 248.76 75.495 249.11 ;
      RECT 75.425 251.58 75.495 251.93 ;
      RECT 75.425 252.03 75.495 252.38 ;
      RECT 75.425 252.48 75.495 252.83 ;
      RECT 75.425 252.93 75.495 253.28 ;
      RECT 75.425 253.38 75.495 253.73 ;
      RECT 75.425 253.83 75.495 254.18 ;
      RECT 75.425 254.28 75.495 254.63 ;
      RECT 75.425 263.025 75.495 263.375 ;
      RECT 75.425 263.475 75.495 263.825 ;
      RECT 75.425 263.925 75.495 264.275 ;
      RECT 75.425 264.375 75.495 264.725 ;
      RECT 75.425 264.825 75.495 265.175 ;
      RECT 75.425 265.275 75.495 265.625 ;
      RECT 75.425 268.645 75.495 268.995 ;
      RECT 75.425 269.095 75.495 269.445 ;
      RECT 75.425 269.545 75.495 269.895 ;
      RECT 75.425 269.995 75.495 270.345 ;
      RECT 75.425 270.445 75.495 270.795 ;
      RECT 75.425 270.895 75.495 271.245 ;
      RECT 75.425 273.81 75.495 274.16 ;
      RECT 75.425 274.26 75.495 274.61 ;
      RECT 75.425 274.71 75.495 275.06 ;
      RECT 75.425 275.16 75.495 275.51 ;
      RECT 75.425 275.61 75.495 275.96 ;
      RECT 75.425 276.06 75.495 276.41 ;
      RECT 75.425 276.51 75.495 276.86 ;
      RECT 75.425 279.33 75.495 279.68 ;
      RECT 75.425 279.78 75.495 280.13 ;
      RECT 75.425 280.23 75.495 280.58 ;
      RECT 75.425 280.68 75.495 281.03 ;
      RECT 75.425 281.13 75.495 281.48 ;
      RECT 75.425 281.58 75.495 281.93 ;
      RECT 75.425 282.03 75.495 282.38 ;
      RECT 75.425 285.265 75.495 285.615 ;
      RECT 75.425 285.715 75.495 286.065 ;
      RECT 75.425 286.165 75.495 286.515 ;
      RECT 75.425 286.615 75.495 286.965 ;
      RECT 75.425 287.065 75.495 287.415 ;
      RECT 75.425 287.515 75.495 287.865 ;
      RECT 75.425 290.825 75.495 291.175 ;
      RECT 75.425 291.275 75.495 291.625 ;
      RECT 75.425 291.725 75.495 292.075 ;
      RECT 75.425 292.175 75.495 292.525 ;
      RECT 75.425 292.625 75.495 292.975 ;
      RECT 75.425 293.075 75.495 293.425 ;
      RECT 11.855 4.91 21.405 5.33 ;
      RECT 11.855 10.47 21.405 10.89 ;
      RECT 11.855 16.03 21.405 16.45 ;
      RECT 11.855 21.59 21.405 22.01 ;
      RECT 11.855 27.15 21.405 27.57 ;
      RECT 11.855 32.71 21.405 33.13 ;
      RECT 11.855 38.27 21.405 38.69 ;
      RECT 11.855 43.83 21.405 44.25 ;
      RECT 11.855 49.39 21.405 49.81 ;
      RECT 11.855 54.95 21.405 55.37 ;
      RECT 11.855 60.51 21.405 60.93 ;
      RECT 11.855 66.07 21.405 66.49 ;
      RECT 11.855 71.63 21.405 72.05 ;
      RECT 11.855 77.19 21.405 77.61 ;
      RECT 11.855 82.75 21.405 83.17 ;
      RECT 11.855 88.31 21.405 88.73 ;
      RECT 11.855 93.87 21.405 94.29 ;
      RECT 11.855 99.43 21.405 99.85 ;
      RECT 11.855 104.99 21.405 105.41 ;
      RECT 11.855 110.55 21.405 110.97 ;
      RECT 11.855 116.11 21.405 116.53 ;
      RECT 11.855 121.67 21.405 122.09 ;
      RECT 11.855 127.23 21.405 127.65 ;
      RECT 11.855 132.79 21.405 133.21 ;
      RECT 11.855 138.35 21.405 138.77 ;
      RECT 11.855 143.91 21.405 144.33 ;
      RECT 11.855 149.47 21.405 149.89 ;
      RECT 11.855 155.03 21.405 155.45 ;
      RECT 11.855 160.59 21.405 161.01 ;
      RECT 11.855 166.15 21.405 166.57 ;
      RECT 11.855 171.71 21.405 172.13 ;
      RECT 11.855 177.27 21.405 177.69 ;
      RECT 11.855 182.83 21.405 183.25 ;
      RECT 11.855 188.39 21.405 188.81 ;
      RECT 11.855 193.95 21.405 194.37 ;
      RECT 11.855 199.51 21.405 199.93 ;
      RECT 11.855 205.07 21.405 205.49 ;
      RECT 11.855 210.63 21.405 211.05 ;
      RECT 11.855 216.19 21.405 216.61 ;
      RECT 11.855 221.75 21.405 222.17 ;
      RECT 11.855 227.31 21.405 227.73 ;
      RECT 11.855 232.87 21.405 233.29 ;
      RECT 11.855 238.43 21.405 238.85 ;
      RECT 11.855 243.99 21.405 244.41 ;
      RECT 11.855 249.55 21.405 249.97 ;
      RECT 11.855 255.11 21.405 255.53 ;
      RECT 11.855 260.67 21.405 261.09 ;
      RECT 11.855 266.23 21.405 266.65 ;
      RECT 11.855 271.79 21.405 272.21 ;
      RECT 11.855 277.35 21.405 277.77 ;
      RECT 11.855 282.91 21.405 283.33 ;
      RECT 11.855 288.47 21.405 288.89 ;
      RECT 11.855 294.03 21.405 294.45 ;
      RECT 16.67 185.245 16.74 185.595 ;
      RECT 16.67 185.695 16.74 186.045 ;
      RECT 16.67 186.145 16.74 186.495 ;
      RECT 16.67 186.595 16.74 186.945 ;
      RECT 16.67 187.045 16.74 187.395 ;
      RECT 16.67 187.495 16.74 187.845 ;
      RECT 16.655 7.265 16.725 7.615 ;
      RECT 16.655 7.715 16.725 8.065 ;
      RECT 16.655 8.165 16.725 8.515 ;
      RECT 16.655 8.615 16.725 8.965 ;
      RECT 16.655 9.065 16.725 9.415 ;
      RECT 16.655 9.515 16.725 9.865 ;
      RECT 16.655 12.885 16.725 13.235 ;
      RECT 16.655 13.335 16.725 13.685 ;
      RECT 16.655 13.785 16.725 14.135 ;
      RECT 16.655 14.235 16.725 14.585 ;
      RECT 16.655 14.685 16.725 15.035 ;
      RECT 16.655 15.135 16.725 15.485 ;
      RECT 16.655 18.06 16.725 18.41 ;
      RECT 16.655 18.51 16.725 18.86 ;
      RECT 16.655 18.96 16.725 19.31 ;
      RECT 16.655 19.41 16.725 19.76 ;
      RECT 16.655 19.86 16.725 20.21 ;
      RECT 16.655 20.31 16.725 20.66 ;
      RECT 16.655 20.76 16.725 21.11 ;
      RECT 16.655 23.58 16.725 23.93 ;
      RECT 16.655 24.03 16.725 24.38 ;
      RECT 16.655 24.48 16.725 24.83 ;
      RECT 16.655 24.93 16.725 25.28 ;
      RECT 16.655 25.38 16.725 25.73 ;
      RECT 16.655 25.83 16.725 26.18 ;
      RECT 16.655 26.28 16.725 26.63 ;
      RECT 16.655 29.505 16.725 29.855 ;
      RECT 16.655 29.955 16.725 30.305 ;
      RECT 16.655 30.405 16.725 30.755 ;
      RECT 16.655 30.855 16.725 31.205 ;
      RECT 16.655 31.305 16.725 31.655 ;
      RECT 16.655 31.755 16.725 32.105 ;
      RECT 16.655 35.065 16.725 35.415 ;
      RECT 16.655 35.515 16.725 35.865 ;
      RECT 16.655 35.965 16.725 36.315 ;
      RECT 16.655 36.415 16.725 36.765 ;
      RECT 16.655 36.865 16.725 37.215 ;
      RECT 16.655 37.315 16.725 37.665 ;
      RECT 16.655 40.32 16.725 40.67 ;
      RECT 16.655 40.77 16.725 41.12 ;
      RECT 16.655 41.22 16.725 41.57 ;
      RECT 16.655 41.67 16.725 42.02 ;
      RECT 16.655 42.12 16.725 42.47 ;
      RECT 16.655 42.57 16.725 42.92 ;
      RECT 16.655 43.02 16.725 43.37 ;
      RECT 16.655 45.81 16.725 46.16 ;
      RECT 16.655 46.26 16.725 46.61 ;
      RECT 16.655 46.71 16.725 47.06 ;
      RECT 16.655 47.16 16.725 47.51 ;
      RECT 16.655 47.61 16.725 47.96 ;
      RECT 16.655 48.06 16.725 48.41 ;
      RECT 16.655 48.51 16.725 48.86 ;
      RECT 16.655 51.745 16.725 52.095 ;
      RECT 16.655 52.195 16.725 52.545 ;
      RECT 16.655 52.645 16.725 52.995 ;
      RECT 16.655 53.095 16.725 53.445 ;
      RECT 16.655 53.545 16.725 53.895 ;
      RECT 16.655 53.995 16.725 54.345 ;
      RECT 16.655 57.305 16.725 57.655 ;
      RECT 16.655 57.755 16.725 58.105 ;
      RECT 16.655 58.205 16.725 58.555 ;
      RECT 16.655 58.655 16.725 59.005 ;
      RECT 16.655 59.105 16.725 59.455 ;
      RECT 16.655 59.555 16.725 59.905 ;
      RECT 16.655 62.55 16.725 62.9 ;
      RECT 16.655 63 16.725 63.35 ;
      RECT 16.655 63.45 16.725 63.8 ;
      RECT 16.655 63.9 16.725 64.25 ;
      RECT 16.655 64.35 16.725 64.7 ;
      RECT 16.655 64.8 16.725 65.15 ;
      RECT 16.655 65.25 16.725 65.6 ;
      RECT 16.655 68.07 16.725 68.42 ;
      RECT 16.655 68.52 16.725 68.87 ;
      RECT 16.655 68.97 16.725 69.32 ;
      RECT 16.655 69.42 16.725 69.77 ;
      RECT 16.655 69.87 16.725 70.22 ;
      RECT 16.655 70.32 16.725 70.67 ;
      RECT 16.655 70.77 16.725 71.12 ;
      RECT 16.655 73.985 16.725 74.335 ;
      RECT 16.655 74.435 16.725 74.785 ;
      RECT 16.655 74.885 16.725 75.235 ;
      RECT 16.655 75.335 16.725 75.685 ;
      RECT 16.655 75.785 16.725 76.135 ;
      RECT 16.655 76.235 16.725 76.585 ;
      RECT 16.655 79.545 16.725 79.895 ;
      RECT 16.655 79.995 16.725 80.345 ;
      RECT 16.655 80.445 16.725 80.795 ;
      RECT 16.655 80.895 16.725 81.245 ;
      RECT 16.655 81.345 16.725 81.695 ;
      RECT 16.655 81.795 16.725 82.145 ;
      RECT 16.655 84.81 16.725 85.16 ;
      RECT 16.655 85.26 16.725 85.61 ;
      RECT 16.655 85.71 16.725 86.06 ;
      RECT 16.655 86.16 16.725 86.51 ;
      RECT 16.655 86.61 16.725 86.96 ;
      RECT 16.655 87.06 16.725 87.41 ;
      RECT 16.655 87.51 16.725 87.86 ;
      RECT 16.655 90.3 16.725 90.65 ;
      RECT 16.655 90.75 16.725 91.1 ;
      RECT 16.655 91.2 16.725 91.55 ;
      RECT 16.655 91.65 16.725 92 ;
      RECT 16.655 92.1 16.725 92.45 ;
      RECT 16.655 92.55 16.725 92.9 ;
      RECT 16.655 93 16.725 93.35 ;
      RECT 16.655 96.225 16.725 96.575 ;
      RECT 16.655 96.675 16.725 97.025 ;
      RECT 16.655 97.125 16.725 97.475 ;
      RECT 16.655 97.575 16.725 97.925 ;
      RECT 16.655 98.025 16.725 98.375 ;
      RECT 16.655 98.475 16.725 98.825 ;
      RECT 16.655 101.785 16.725 102.135 ;
      RECT 16.655 102.235 16.725 102.585 ;
      RECT 16.655 102.685 16.725 103.035 ;
      RECT 16.655 103.135 16.725 103.485 ;
      RECT 16.655 103.585 16.725 103.935 ;
      RECT 16.655 104.035 16.725 104.385 ;
      RECT 16.655 107.04 16.725 107.39 ;
      RECT 16.655 107.49 16.725 107.84 ;
      RECT 16.655 107.94 16.725 108.29 ;
      RECT 16.655 108.39 16.725 108.74 ;
      RECT 16.655 108.84 16.725 109.19 ;
      RECT 16.655 109.29 16.725 109.64 ;
      RECT 16.655 109.74 16.725 110.09 ;
      RECT 16.655 112.56 16.725 112.91 ;
      RECT 16.655 113.01 16.725 113.36 ;
      RECT 16.655 113.46 16.725 113.81 ;
      RECT 16.655 113.91 16.725 114.26 ;
      RECT 16.655 114.36 16.725 114.71 ;
      RECT 16.655 114.81 16.725 115.16 ;
      RECT 16.655 115.26 16.725 115.61 ;
      RECT 16.655 118.465 16.725 118.815 ;
      RECT 16.655 118.915 16.725 119.265 ;
      RECT 16.655 119.365 16.725 119.715 ;
      RECT 16.655 119.815 16.725 120.165 ;
      RECT 16.655 120.265 16.725 120.615 ;
      RECT 16.655 120.715 16.725 121.065 ;
      RECT 16.655 124.025 16.725 124.375 ;
      RECT 16.655 124.475 16.725 124.825 ;
      RECT 16.655 124.925 16.725 125.275 ;
      RECT 16.655 125.375 16.725 125.725 ;
      RECT 16.655 125.825 16.725 126.175 ;
      RECT 16.655 126.275 16.725 126.625 ;
      RECT 16.655 129.3 16.725 129.65 ;
      RECT 16.655 129.75 16.725 130.1 ;
      RECT 16.655 130.2 16.725 130.55 ;
      RECT 16.655 130.65 16.725 131 ;
      RECT 16.655 131.1 16.725 131.45 ;
      RECT 16.655 131.55 16.725 131.9 ;
      RECT 16.655 132 16.725 132.35 ;
      RECT 16.655 134.79 16.725 135.14 ;
      RECT 16.655 135.24 16.725 135.59 ;
      RECT 16.655 135.69 16.725 136.04 ;
      RECT 16.655 136.14 16.725 136.49 ;
      RECT 16.655 136.59 16.725 136.94 ;
      RECT 16.655 137.04 16.725 137.39 ;
      RECT 16.655 137.49 16.725 137.84 ;
      RECT 16.655 140.705 16.725 141.055 ;
      RECT 16.655 141.155 16.725 141.505 ;
      RECT 16.655 141.605 16.725 141.955 ;
      RECT 16.655 142.055 16.725 142.405 ;
      RECT 16.655 142.505 16.725 142.855 ;
      RECT 16.655 142.955 16.725 143.305 ;
      RECT 16.655 146.265 16.725 146.615 ;
      RECT 16.655 146.715 16.725 147.065 ;
      RECT 16.655 147.165 16.725 147.515 ;
      RECT 16.655 147.615 16.725 147.965 ;
      RECT 16.655 148.065 16.725 148.415 ;
      RECT 16.655 148.515 16.725 148.865 ;
      RECT 16.655 151.53 16.725 151.88 ;
      RECT 16.655 151.98 16.725 152.33 ;
      RECT 16.655 152.43 16.725 152.78 ;
      RECT 16.655 152.88 16.725 153.23 ;
      RECT 16.655 153.33 16.725 153.68 ;
      RECT 16.655 153.78 16.725 154.13 ;
      RECT 16.655 154.23 16.725 154.58 ;
      RECT 16.655 157.05 16.725 157.4 ;
      RECT 16.655 157.5 16.725 157.85 ;
      RECT 16.655 157.95 16.725 158.3 ;
      RECT 16.655 158.4 16.725 158.75 ;
      RECT 16.655 158.85 16.725 159.2 ;
      RECT 16.655 159.3 16.725 159.65 ;
      RECT 16.655 159.75 16.725 160.1 ;
      RECT 16.655 162.945 16.725 163.295 ;
      RECT 16.655 163.395 16.725 163.745 ;
      RECT 16.655 163.845 16.725 164.195 ;
      RECT 16.655 164.295 16.725 164.645 ;
      RECT 16.655 164.745 16.725 165.095 ;
      RECT 16.655 165.195 16.725 165.545 ;
      RECT 16.655 168.505 16.725 168.855 ;
      RECT 16.655 168.955 16.725 169.305 ;
      RECT 16.655 169.405 16.725 169.755 ;
      RECT 16.655 169.855 16.725 170.205 ;
      RECT 16.655 170.305 16.725 170.655 ;
      RECT 16.655 170.755 16.725 171.105 ;
      RECT 16.655 174.125 16.725 174.475 ;
      RECT 16.655 174.575 16.725 174.925 ;
      RECT 16.655 175.025 16.725 175.375 ;
      RECT 16.655 175.475 16.725 175.825 ;
      RECT 16.655 175.925 16.725 176.275 ;
      RECT 16.655 176.375 16.725 176.725 ;
      RECT 16.655 179.28 16.725 179.63 ;
      RECT 16.655 179.73 16.725 180.08 ;
      RECT 16.655 180.18 16.725 180.53 ;
      RECT 16.655 180.63 16.725 180.98 ;
      RECT 16.655 181.08 16.725 181.43 ;
      RECT 16.655 181.53 16.725 181.88 ;
      RECT 16.655 181.98 16.725 182.33 ;
      RECT 16.655 190.745 16.725 191.095 ;
      RECT 16.655 191.195 16.725 191.545 ;
      RECT 16.655 191.645 16.725 191.995 ;
      RECT 16.655 192.095 16.725 192.445 ;
      RECT 16.655 192.545 16.725 192.895 ;
      RECT 16.655 192.995 16.725 193.345 ;
      RECT 16.655 196.02 16.725 196.37 ;
      RECT 16.655 196.47 16.725 196.82 ;
      RECT 16.655 196.92 16.725 197.27 ;
      RECT 16.655 197.37 16.725 197.72 ;
      RECT 16.655 197.82 16.725 198.17 ;
      RECT 16.655 198.27 16.725 198.62 ;
      RECT 16.655 198.72 16.725 199.07 ;
      RECT 16.655 201.54 16.725 201.89 ;
      RECT 16.655 201.99 16.725 202.34 ;
      RECT 16.655 202.44 16.725 202.79 ;
      RECT 16.655 202.89 16.725 203.24 ;
      RECT 16.655 203.34 16.725 203.69 ;
      RECT 16.655 203.79 16.725 204.14 ;
      RECT 16.655 204.24 16.725 204.59 ;
      RECT 16.655 207.425 16.725 207.775 ;
      RECT 16.655 207.875 16.725 208.225 ;
      RECT 16.655 208.325 16.725 208.675 ;
      RECT 16.655 208.775 16.725 209.125 ;
      RECT 16.655 209.225 16.725 209.575 ;
      RECT 16.655 209.675 16.725 210.025 ;
      RECT 16.655 212.985 16.725 213.335 ;
      RECT 16.655 213.435 16.725 213.785 ;
      RECT 16.655 213.885 16.725 214.235 ;
      RECT 16.655 214.335 16.725 214.685 ;
      RECT 16.655 214.785 16.725 215.135 ;
      RECT 16.655 215.235 16.725 215.585 ;
      RECT 16.655 218.605 16.725 218.955 ;
      RECT 16.655 219.055 16.725 219.405 ;
      RECT 16.655 219.505 16.725 219.855 ;
      RECT 16.655 219.955 16.725 220.305 ;
      RECT 16.655 220.405 16.725 220.755 ;
      RECT 16.655 220.855 16.725 221.205 ;
      RECT 16.655 223.77 16.725 224.12 ;
      RECT 16.655 224.22 16.725 224.57 ;
      RECT 16.655 224.67 16.725 225.02 ;
      RECT 16.655 225.12 16.725 225.47 ;
      RECT 16.655 225.57 16.725 225.92 ;
      RECT 16.655 226.02 16.725 226.37 ;
      RECT 16.655 226.47 16.725 226.82 ;
      RECT 16.655 235.225 16.725 235.575 ;
      RECT 16.655 235.675 16.725 236.025 ;
      RECT 16.655 236.125 16.725 236.475 ;
      RECT 16.655 236.575 16.725 236.925 ;
      RECT 16.655 237.025 16.725 237.375 ;
      RECT 16.655 237.475 16.725 237.825 ;
      RECT 16.655 240.785 16.725 241.135 ;
      RECT 16.655 241.235 16.725 241.585 ;
      RECT 16.655 241.685 16.725 242.035 ;
      RECT 16.655 242.135 16.725 242.485 ;
      RECT 16.655 242.585 16.725 242.935 ;
      RECT 16.655 243.035 16.725 243.385 ;
      RECT 16.655 246.03 16.725 246.38 ;
      RECT 16.655 246.48 16.725 246.83 ;
      RECT 16.655 246.93 16.725 247.28 ;
      RECT 16.655 247.38 16.725 247.73 ;
      RECT 16.655 247.83 16.725 248.18 ;
      RECT 16.655 248.28 16.725 248.63 ;
      RECT 16.655 248.73 16.725 249.08 ;
      RECT 16.655 251.97 16.725 252.32 ;
      RECT 16.655 252.42 16.725 252.77 ;
      RECT 16.655 252.87 16.725 253.22 ;
      RECT 16.655 253.32 16.725 253.67 ;
      RECT 16.655 253.77 16.725 254.12 ;
      RECT 16.655 254.22 16.725 254.57 ;
      RECT 16.655 257.465 16.725 257.815 ;
      RECT 16.655 257.915 16.725 258.265 ;
      RECT 16.655 258.365 16.725 258.715 ;
      RECT 16.655 258.815 16.725 259.165 ;
      RECT 16.655 259.265 16.725 259.615 ;
      RECT 16.655 259.715 16.725 260.065 ;
      RECT 16.655 263.085 16.725 263.435 ;
      RECT 16.655 263.535 16.725 263.885 ;
      RECT 16.655 263.985 16.725 264.335 ;
      RECT 16.655 264.435 16.725 264.785 ;
      RECT 16.655 264.885 16.725 265.235 ;
      RECT 16.655 265.335 16.725 265.685 ;
      RECT 16.655 268.26 16.725 268.61 ;
      RECT 16.655 268.71 16.725 269.06 ;
      RECT 16.655 269.16 16.725 269.51 ;
      RECT 16.655 269.61 16.725 269.96 ;
      RECT 16.655 270.06 16.725 270.41 ;
      RECT 16.655 270.51 16.725 270.86 ;
      RECT 16.655 270.96 16.725 271.31 ;
      RECT 16.655 279.705 16.725 280.055 ;
      RECT 16.655 280.155 16.725 280.505 ;
      RECT 16.655 280.605 16.725 280.955 ;
      RECT 16.655 281.055 16.725 281.405 ;
      RECT 16.655 281.505 16.725 281.855 ;
      RECT 16.655 281.955 16.725 282.305 ;
      RECT 16.655 285.265 16.725 285.615 ;
      RECT 16.655 285.715 16.725 286.065 ;
      RECT 16.655 286.165 16.725 286.515 ;
      RECT 16.655 286.615 16.725 286.965 ;
      RECT 16.655 287.065 16.725 287.415 ;
      RECT 16.655 287.515 16.725 287.865 ;
      RECT 16.655 290.52 16.725 290.87 ;
      RECT 16.655 290.97 16.725 291.32 ;
      RECT 16.655 291.42 16.725 291.77 ;
      RECT 16.655 291.87 16.725 292.22 ;
      RECT 16.655 292.32 16.725 292.67 ;
      RECT 16.655 292.77 16.725 293.12 ;
      RECT 16.655 293.22 16.725 293.57 ;
      RECT 16.65 229.725 16.72 230.075 ;
      RECT 16.65 230.175 16.72 230.525 ;
      RECT 16.65 230.625 16.72 230.975 ;
      RECT 16.65 231.075 16.72 231.425 ;
      RECT 16.65 231.525 16.72 231.875 ;
      RECT 16.65 231.975 16.72 232.325 ;
      RECT 16.63 274.205 16.7 274.555 ;
      RECT 16.63 274.655 16.7 275.005 ;
      RECT 16.63 275.105 16.7 275.455 ;
      RECT 16.63 275.555 16.7 275.905 ;
      RECT 16.63 276.005 16.7 276.355 ;
      RECT 16.63 276.455 16.7 276.805 ;
      RECT 16.55 1.505 16.62 1.855 ;
      RECT 16.55 1.955 16.62 2.305 ;
      RECT 16.55 2.405 16.62 2.755 ;
      RECT 16.55 2.855 16.62 3.205 ;
      RECT 16.55 3.305 16.62 3.655 ;
      RECT 16.55 3.755 16.62 4.105 ;
      RECT 16.55 4.205 16.62 4.555 ;
      RECT 16.53 185.245 16.6 185.595 ;
      RECT 16.53 185.695 16.6 186.045 ;
      RECT 16.53 186.145 16.6 186.495 ;
      RECT 16.53 186.595 16.6 186.945 ;
      RECT 16.53 187.045 16.6 187.395 ;
      RECT 16.53 187.495 16.6 187.845 ;
      RECT 16.515 7.265 16.585 7.615 ;
      RECT 16.515 7.715 16.585 8.065 ;
      RECT 16.515 8.165 16.585 8.515 ;
      RECT 16.515 8.615 16.585 8.965 ;
      RECT 16.515 9.065 16.585 9.415 ;
      RECT 16.515 9.515 16.585 9.865 ;
      RECT 16.515 12.885 16.585 13.235 ;
      RECT 16.515 13.335 16.585 13.685 ;
      RECT 16.515 13.785 16.585 14.135 ;
      RECT 16.515 14.235 16.585 14.585 ;
      RECT 16.515 14.685 16.585 15.035 ;
      RECT 16.515 15.135 16.585 15.485 ;
      RECT 16.515 18.06 16.585 18.41 ;
      RECT 16.515 18.51 16.585 18.86 ;
      RECT 16.515 18.96 16.585 19.31 ;
      RECT 16.515 19.41 16.585 19.76 ;
      RECT 16.515 19.86 16.585 20.21 ;
      RECT 16.515 20.31 16.585 20.66 ;
      RECT 16.515 20.76 16.585 21.11 ;
      RECT 16.515 23.58 16.585 23.93 ;
      RECT 16.515 24.03 16.585 24.38 ;
      RECT 16.515 24.48 16.585 24.83 ;
      RECT 16.515 24.93 16.585 25.28 ;
      RECT 16.515 25.38 16.585 25.73 ;
      RECT 16.515 25.83 16.585 26.18 ;
      RECT 16.515 26.28 16.585 26.63 ;
      RECT 16.515 29.505 16.585 29.855 ;
      RECT 16.515 29.955 16.585 30.305 ;
      RECT 16.515 30.405 16.585 30.755 ;
      RECT 16.515 30.855 16.585 31.205 ;
      RECT 16.515 31.305 16.585 31.655 ;
      RECT 16.515 31.755 16.585 32.105 ;
      RECT 16.515 35.065 16.585 35.415 ;
      RECT 16.515 35.515 16.585 35.865 ;
      RECT 16.515 35.965 16.585 36.315 ;
      RECT 16.515 36.415 16.585 36.765 ;
      RECT 16.515 36.865 16.585 37.215 ;
      RECT 16.515 37.315 16.585 37.665 ;
      RECT 16.515 40.32 16.585 40.67 ;
      RECT 16.515 40.77 16.585 41.12 ;
      RECT 16.515 41.22 16.585 41.57 ;
      RECT 16.515 41.67 16.585 42.02 ;
      RECT 16.515 42.12 16.585 42.47 ;
      RECT 16.515 42.57 16.585 42.92 ;
      RECT 16.515 43.02 16.585 43.37 ;
      RECT 16.515 45.81 16.585 46.16 ;
      RECT 16.515 46.26 16.585 46.61 ;
      RECT 16.515 46.71 16.585 47.06 ;
      RECT 16.515 47.16 16.585 47.51 ;
      RECT 16.515 47.61 16.585 47.96 ;
      RECT 16.515 48.06 16.585 48.41 ;
      RECT 16.515 48.51 16.585 48.86 ;
      RECT 16.515 51.745 16.585 52.095 ;
      RECT 16.515 52.195 16.585 52.545 ;
      RECT 16.515 52.645 16.585 52.995 ;
      RECT 16.515 53.095 16.585 53.445 ;
      RECT 16.515 53.545 16.585 53.895 ;
      RECT 16.515 53.995 16.585 54.345 ;
      RECT 16.515 57.305 16.585 57.655 ;
      RECT 16.515 57.755 16.585 58.105 ;
      RECT 16.515 58.205 16.585 58.555 ;
      RECT 16.515 58.655 16.585 59.005 ;
      RECT 16.515 59.105 16.585 59.455 ;
      RECT 16.515 59.555 16.585 59.905 ;
      RECT 16.515 62.55 16.585 62.9 ;
      RECT 16.515 63 16.585 63.35 ;
      RECT 16.515 63.45 16.585 63.8 ;
      RECT 16.515 63.9 16.585 64.25 ;
      RECT 16.515 64.35 16.585 64.7 ;
      RECT 16.515 64.8 16.585 65.15 ;
      RECT 16.515 65.25 16.585 65.6 ;
      RECT 16.515 68.07 16.585 68.42 ;
      RECT 16.515 68.52 16.585 68.87 ;
      RECT 16.515 68.97 16.585 69.32 ;
      RECT 16.515 69.42 16.585 69.77 ;
      RECT 16.515 69.87 16.585 70.22 ;
      RECT 16.515 70.32 16.585 70.67 ;
      RECT 16.515 70.77 16.585 71.12 ;
      RECT 16.515 73.985 16.585 74.335 ;
      RECT 16.515 74.435 16.585 74.785 ;
      RECT 16.515 74.885 16.585 75.235 ;
      RECT 16.515 75.335 16.585 75.685 ;
      RECT 16.515 75.785 16.585 76.135 ;
      RECT 16.515 76.235 16.585 76.585 ;
      RECT 16.515 79.545 16.585 79.895 ;
      RECT 16.515 79.995 16.585 80.345 ;
      RECT 16.515 80.445 16.585 80.795 ;
      RECT 16.515 80.895 16.585 81.245 ;
      RECT 16.515 81.345 16.585 81.695 ;
      RECT 16.515 81.795 16.585 82.145 ;
      RECT 16.515 84.81 16.585 85.16 ;
      RECT 16.515 85.26 16.585 85.61 ;
      RECT 16.515 85.71 16.585 86.06 ;
      RECT 16.515 86.16 16.585 86.51 ;
      RECT 16.515 86.61 16.585 86.96 ;
      RECT 16.515 87.06 16.585 87.41 ;
      RECT 16.515 87.51 16.585 87.86 ;
      RECT 16.515 90.3 16.585 90.65 ;
      RECT 16.515 90.75 16.585 91.1 ;
      RECT 16.515 91.2 16.585 91.55 ;
      RECT 16.515 91.65 16.585 92 ;
      RECT 16.515 92.1 16.585 92.45 ;
      RECT 16.515 92.55 16.585 92.9 ;
      RECT 16.515 93 16.585 93.35 ;
      RECT 16.515 96.225 16.585 96.575 ;
      RECT 16.515 96.675 16.585 97.025 ;
      RECT 16.515 97.125 16.585 97.475 ;
      RECT 16.515 97.575 16.585 97.925 ;
      RECT 16.515 98.025 16.585 98.375 ;
      RECT 16.515 98.475 16.585 98.825 ;
      RECT 16.515 101.785 16.585 102.135 ;
      RECT 16.515 102.235 16.585 102.585 ;
      RECT 16.515 102.685 16.585 103.035 ;
      RECT 16.515 103.135 16.585 103.485 ;
      RECT 16.515 103.585 16.585 103.935 ;
      RECT 16.515 104.035 16.585 104.385 ;
      RECT 16.515 107.04 16.585 107.39 ;
      RECT 16.515 107.49 16.585 107.84 ;
      RECT 16.515 107.94 16.585 108.29 ;
      RECT 16.515 108.39 16.585 108.74 ;
      RECT 16.515 108.84 16.585 109.19 ;
      RECT 16.515 109.29 16.585 109.64 ;
      RECT 16.515 109.74 16.585 110.09 ;
      RECT 16.515 112.56 16.585 112.91 ;
      RECT 16.515 113.01 16.585 113.36 ;
      RECT 16.515 113.46 16.585 113.81 ;
      RECT 16.515 113.91 16.585 114.26 ;
      RECT 16.515 114.36 16.585 114.71 ;
      RECT 16.515 114.81 16.585 115.16 ;
      RECT 16.515 115.26 16.585 115.61 ;
      RECT 16.515 118.465 16.585 118.815 ;
      RECT 16.515 118.915 16.585 119.265 ;
      RECT 16.515 119.365 16.585 119.715 ;
      RECT 16.515 119.815 16.585 120.165 ;
      RECT 16.515 120.265 16.585 120.615 ;
      RECT 16.515 120.715 16.585 121.065 ;
      RECT 16.515 124.025 16.585 124.375 ;
      RECT 16.515 124.475 16.585 124.825 ;
      RECT 16.515 124.925 16.585 125.275 ;
      RECT 16.515 125.375 16.585 125.725 ;
      RECT 16.515 125.825 16.585 126.175 ;
      RECT 16.515 126.275 16.585 126.625 ;
      RECT 16.515 129.3 16.585 129.65 ;
      RECT 16.515 129.75 16.585 130.1 ;
      RECT 16.515 130.2 16.585 130.55 ;
      RECT 16.515 130.65 16.585 131 ;
      RECT 16.515 131.1 16.585 131.45 ;
      RECT 16.515 131.55 16.585 131.9 ;
      RECT 16.515 132 16.585 132.35 ;
      RECT 16.515 134.79 16.585 135.14 ;
      RECT 16.515 135.24 16.585 135.59 ;
      RECT 16.515 135.69 16.585 136.04 ;
      RECT 16.515 136.14 16.585 136.49 ;
      RECT 16.515 136.59 16.585 136.94 ;
      RECT 16.515 137.04 16.585 137.39 ;
      RECT 16.515 137.49 16.585 137.84 ;
      RECT 16.515 140.705 16.585 141.055 ;
      RECT 16.515 141.155 16.585 141.505 ;
      RECT 16.515 141.605 16.585 141.955 ;
      RECT 16.515 142.055 16.585 142.405 ;
      RECT 16.515 142.505 16.585 142.855 ;
      RECT 16.515 142.955 16.585 143.305 ;
      RECT 16.515 146.265 16.585 146.615 ;
      RECT 16.515 146.715 16.585 147.065 ;
      RECT 16.515 147.165 16.585 147.515 ;
      RECT 16.515 147.615 16.585 147.965 ;
      RECT 16.515 148.065 16.585 148.415 ;
      RECT 16.515 148.515 16.585 148.865 ;
      RECT 16.515 151.53 16.585 151.88 ;
      RECT 16.515 151.98 16.585 152.33 ;
      RECT 16.515 152.43 16.585 152.78 ;
      RECT 16.515 152.88 16.585 153.23 ;
      RECT 16.515 153.33 16.585 153.68 ;
      RECT 16.515 153.78 16.585 154.13 ;
      RECT 16.515 154.23 16.585 154.58 ;
      RECT 16.515 157.05 16.585 157.4 ;
      RECT 16.515 157.5 16.585 157.85 ;
      RECT 16.515 157.95 16.585 158.3 ;
      RECT 16.515 158.4 16.585 158.75 ;
      RECT 16.515 158.85 16.585 159.2 ;
      RECT 16.515 159.3 16.585 159.65 ;
      RECT 16.515 159.75 16.585 160.1 ;
      RECT 16.515 162.945 16.585 163.295 ;
      RECT 16.515 163.395 16.585 163.745 ;
      RECT 16.515 163.845 16.585 164.195 ;
      RECT 16.515 164.295 16.585 164.645 ;
      RECT 16.515 164.745 16.585 165.095 ;
      RECT 16.515 165.195 16.585 165.545 ;
      RECT 16.515 168.505 16.585 168.855 ;
      RECT 16.515 168.955 16.585 169.305 ;
      RECT 16.515 169.405 16.585 169.755 ;
      RECT 16.515 169.855 16.585 170.205 ;
      RECT 16.515 170.305 16.585 170.655 ;
      RECT 16.515 170.755 16.585 171.105 ;
      RECT 16.515 174.125 16.585 174.475 ;
      RECT 16.515 174.575 16.585 174.925 ;
      RECT 16.515 175.025 16.585 175.375 ;
      RECT 16.515 175.475 16.585 175.825 ;
      RECT 16.515 175.925 16.585 176.275 ;
      RECT 16.515 176.375 16.585 176.725 ;
      RECT 16.515 179.28 16.585 179.63 ;
      RECT 16.515 179.73 16.585 180.08 ;
      RECT 16.515 180.18 16.585 180.53 ;
      RECT 16.515 180.63 16.585 180.98 ;
      RECT 16.515 181.08 16.585 181.43 ;
      RECT 16.515 181.53 16.585 181.88 ;
      RECT 16.515 181.98 16.585 182.33 ;
      RECT 16.515 190.745 16.585 191.095 ;
      RECT 16.515 191.195 16.585 191.545 ;
      RECT 16.515 191.645 16.585 191.995 ;
      RECT 16.515 192.095 16.585 192.445 ;
      RECT 16.515 192.545 16.585 192.895 ;
      RECT 16.515 192.995 16.585 193.345 ;
      RECT 16.515 196.02 16.585 196.37 ;
      RECT 16.515 196.47 16.585 196.82 ;
      RECT 16.515 196.92 16.585 197.27 ;
      RECT 16.515 197.37 16.585 197.72 ;
      RECT 16.515 197.82 16.585 198.17 ;
      RECT 16.515 198.27 16.585 198.62 ;
      RECT 16.515 198.72 16.585 199.07 ;
      RECT 16.515 201.54 16.585 201.89 ;
      RECT 16.515 201.99 16.585 202.34 ;
      RECT 16.515 202.44 16.585 202.79 ;
      RECT 16.515 202.89 16.585 203.24 ;
      RECT 16.515 203.34 16.585 203.69 ;
      RECT 16.515 203.79 16.585 204.14 ;
      RECT 16.515 204.24 16.585 204.59 ;
      RECT 16.515 207.425 16.585 207.775 ;
      RECT 16.515 207.875 16.585 208.225 ;
      RECT 16.515 208.325 16.585 208.675 ;
      RECT 16.515 208.775 16.585 209.125 ;
      RECT 16.515 209.225 16.585 209.575 ;
      RECT 16.515 209.675 16.585 210.025 ;
      RECT 16.515 212.985 16.585 213.335 ;
      RECT 16.515 213.435 16.585 213.785 ;
      RECT 16.515 213.885 16.585 214.235 ;
      RECT 16.515 214.335 16.585 214.685 ;
      RECT 16.515 214.785 16.585 215.135 ;
      RECT 16.515 215.235 16.585 215.585 ;
      RECT 16.515 218.605 16.585 218.955 ;
      RECT 16.515 219.055 16.585 219.405 ;
      RECT 16.515 219.505 16.585 219.855 ;
      RECT 16.515 219.955 16.585 220.305 ;
      RECT 16.515 220.405 16.585 220.755 ;
      RECT 16.515 220.855 16.585 221.205 ;
      RECT 16.515 223.77 16.585 224.12 ;
      RECT 16.515 224.22 16.585 224.57 ;
      RECT 16.515 224.67 16.585 225.02 ;
      RECT 16.515 225.12 16.585 225.47 ;
      RECT 16.515 225.57 16.585 225.92 ;
      RECT 16.515 226.02 16.585 226.37 ;
      RECT 16.515 226.47 16.585 226.82 ;
      RECT 16.515 235.225 16.585 235.575 ;
      RECT 16.515 235.675 16.585 236.025 ;
      RECT 16.515 236.125 16.585 236.475 ;
      RECT 16.515 236.575 16.585 236.925 ;
      RECT 16.515 237.025 16.585 237.375 ;
      RECT 16.515 237.475 16.585 237.825 ;
      RECT 16.515 240.785 16.585 241.135 ;
      RECT 16.515 241.235 16.585 241.585 ;
      RECT 16.515 241.685 16.585 242.035 ;
      RECT 16.515 242.135 16.585 242.485 ;
      RECT 16.515 242.585 16.585 242.935 ;
      RECT 16.515 243.035 16.585 243.385 ;
      RECT 16.515 246.03 16.585 246.38 ;
      RECT 16.515 246.48 16.585 246.83 ;
      RECT 16.515 246.93 16.585 247.28 ;
      RECT 16.515 247.38 16.585 247.73 ;
      RECT 16.515 247.83 16.585 248.18 ;
      RECT 16.515 248.28 16.585 248.63 ;
      RECT 16.515 248.73 16.585 249.08 ;
      RECT 16.515 251.97 16.585 252.32 ;
      RECT 16.515 252.42 16.585 252.77 ;
      RECT 16.515 252.87 16.585 253.22 ;
      RECT 16.515 253.32 16.585 253.67 ;
      RECT 16.515 253.77 16.585 254.12 ;
      RECT 16.515 254.22 16.585 254.57 ;
      RECT 16.515 257.465 16.585 257.815 ;
      RECT 16.515 257.915 16.585 258.265 ;
      RECT 16.515 258.365 16.585 258.715 ;
      RECT 16.515 258.815 16.585 259.165 ;
      RECT 16.515 259.265 16.585 259.615 ;
      RECT 16.515 259.715 16.585 260.065 ;
      RECT 16.515 263.085 16.585 263.435 ;
      RECT 16.515 263.535 16.585 263.885 ;
      RECT 16.515 263.985 16.585 264.335 ;
      RECT 16.515 264.435 16.585 264.785 ;
      RECT 16.515 264.885 16.585 265.235 ;
      RECT 16.515 265.335 16.585 265.685 ;
      RECT 16.515 268.26 16.585 268.61 ;
      RECT 16.515 268.71 16.585 269.06 ;
      RECT 16.515 269.16 16.585 269.51 ;
      RECT 16.515 269.61 16.585 269.96 ;
      RECT 16.515 270.06 16.585 270.41 ;
      RECT 16.515 270.51 16.585 270.86 ;
      RECT 16.515 270.96 16.585 271.31 ;
      RECT 16.515 279.705 16.585 280.055 ;
      RECT 16.515 280.155 16.585 280.505 ;
      RECT 16.515 280.605 16.585 280.955 ;
      RECT 16.515 281.055 16.585 281.405 ;
      RECT 16.515 281.505 16.585 281.855 ;
      RECT 16.515 281.955 16.585 282.305 ;
      RECT 16.515 285.265 16.585 285.615 ;
      RECT 16.515 285.715 16.585 286.065 ;
      RECT 16.515 286.165 16.585 286.515 ;
      RECT 16.515 286.615 16.585 286.965 ;
      RECT 16.515 287.065 16.585 287.415 ;
      RECT 16.515 287.515 16.585 287.865 ;
      RECT 16.515 290.52 16.585 290.87 ;
      RECT 16.515 290.97 16.585 291.32 ;
      RECT 16.515 291.42 16.585 291.77 ;
      RECT 16.515 291.87 16.585 292.22 ;
      RECT 16.515 292.32 16.585 292.67 ;
      RECT 16.515 292.77 16.585 293.12 ;
      RECT 16.515 293.22 16.585 293.57 ;
      RECT 0.735 1.55 10.285 1.97 ;
      RECT 0.735 7.11 10.285 7.53 ;
      RECT 0.735 12.67 10.285 13.09 ;
      RECT 0.735 18.23 10.285 18.65 ;
      RECT 0.735 23.79 10.285 24.21 ;
      RECT 0.735 29.35 10.285 29.77 ;
      RECT 0.735 34.91 10.285 35.33 ;
      RECT 0.735 40.47 10.285 40.89 ;
      RECT 0.735 46.03 10.285 46.45 ;
      RECT 0.735 51.59 10.285 52.01 ;
      RECT 0.735 57.15 10.285 57.57 ;
      RECT 0.735 62.71 10.285 63.13 ;
      RECT 0.735 68.27 10.285 68.69 ;
      RECT 0.735 73.83 10.285 74.25 ;
      RECT 0.735 79.39 10.285 79.81 ;
      RECT 0.735 84.95 10.285 85.37 ;
      RECT 0.735 90.51 10.285 90.93 ;
      RECT 0.735 96.07 10.285 96.49 ;
      RECT 0.735 101.63 10.285 102.05 ;
      RECT 0.735 107.19 10.285 107.61 ;
      RECT 0.735 112.75 10.285 113.17 ;
      RECT 0.735 118.31 10.285 118.73 ;
      RECT 0.735 123.87 10.285 124.29 ;
      RECT 0.735 129.43 10.285 129.85 ;
      RECT 0.735 134.99 10.285 135.41 ;
      RECT 0.735 140.55 10.285 140.97 ;
      RECT 0.735 146.11 10.285 146.53 ;
      RECT 0.735 151.67 10.285 152.09 ;
      RECT 0.735 157.23 10.285 157.65 ;
      RECT 0.735 162.79 10.285 163.21 ;
      RECT 0.735 168.35 10.285 168.77 ;
      RECT 0.735 173.91 10.285 174.33 ;
      RECT 0.735 179.47 10.285 179.89 ;
      RECT 0.735 185.03 10.285 185.45 ;
      RECT 0.735 190.59 10.285 191.01 ;
      RECT 0.735 196.15 10.285 196.57 ;
      RECT 0.735 201.71 10.285 202.13 ;
      RECT 0.735 207.27 10.285 207.69 ;
      RECT 0.735 212.83 10.285 213.25 ;
      RECT 0.735 218.39 10.285 218.81 ;
      RECT 0.735 223.95 10.285 224.37 ;
      RECT 0.735 229.51 10.285 229.93 ;
      RECT 0.735 235.07 10.285 235.49 ;
      RECT 0.735 240.63 10.285 241.05 ;
      RECT 0.735 246.19 10.285 246.61 ;
      RECT 0.735 251.75 10.285 252.17 ;
      RECT 0.735 257.31 10.285 257.73 ;
      RECT 0.735 262.87 10.285 263.29 ;
      RECT 0.735 268.43 10.285 268.85 ;
      RECT 0.735 273.99 10.285 274.41 ;
      RECT 0.735 279.55 10.285 279.97 ;
      RECT 0.735 285.11 10.285 285.53 ;
      RECT 0.735 290.67 10.285 291.09 ;
      RECT 5.55 68.885 5.62 69.235 ;
      RECT 5.55 69.335 5.62 69.685 ;
      RECT 5.55 69.785 5.62 70.135 ;
      RECT 5.55 70.235 5.62 70.585 ;
      RECT 5.55 70.685 5.62 71.035 ;
      RECT 5.55 71.135 5.62 71.485 ;
      RECT 5.55 71.585 5.62 71.935 ;
      RECT 5.54 91.125 5.61 91.475 ;
      RECT 5.54 91.575 5.61 91.925 ;
      RECT 5.54 92.025 5.61 92.375 ;
      RECT 5.54 92.475 5.61 92.825 ;
      RECT 5.54 92.925 5.61 93.275 ;
      RECT 5.54 93.375 5.61 93.725 ;
      RECT 5.54 93.825 5.61 94.175 ;
      RECT 5.54 107.805 5.61 108.155 ;
      RECT 5.54 108.255 5.61 108.605 ;
      RECT 5.54 108.705 5.61 109.055 ;
      RECT 5.54 109.155 5.61 109.505 ;
      RECT 5.54 109.605 5.61 109.955 ;
      RECT 5.54 110.055 5.61 110.405 ;
      RECT 5.54 110.505 5.61 110.855 ;
      RECT 5.535 7.725 5.605 8.075 ;
      RECT 5.535 8.175 5.605 8.525 ;
      RECT 5.535 8.625 5.605 8.975 ;
      RECT 5.535 9.075 5.605 9.425 ;
      RECT 5.535 9.525 5.605 9.875 ;
      RECT 5.535 9.975 5.605 10.325 ;
      RECT 5.535 10.425 5.605 10.775 ;
      RECT 5.535 13.285 5.605 13.635 ;
      RECT 5.535 13.735 5.605 14.085 ;
      RECT 5.535 14.185 5.605 14.535 ;
      RECT 5.535 14.635 5.605 14.985 ;
      RECT 5.535 15.085 5.605 15.435 ;
      RECT 5.535 15.535 5.605 15.885 ;
      RECT 5.535 15.985 5.605 16.335 ;
      RECT 5.535 29.965 5.605 30.315 ;
      RECT 5.535 30.415 5.605 30.765 ;
      RECT 5.535 30.865 5.605 31.215 ;
      RECT 5.535 31.315 5.605 31.665 ;
      RECT 5.535 31.765 5.605 32.115 ;
      RECT 5.535 32.215 5.605 32.565 ;
      RECT 5.535 32.665 5.605 33.015 ;
      RECT 5.535 35.525 5.605 35.875 ;
      RECT 5.535 35.975 5.605 36.325 ;
      RECT 5.535 36.425 5.605 36.775 ;
      RECT 5.535 36.875 5.605 37.225 ;
      RECT 5.535 37.325 5.605 37.675 ;
      RECT 5.535 37.775 5.605 38.125 ;
      RECT 5.535 38.225 5.605 38.575 ;
      RECT 5.535 52.205 5.605 52.555 ;
      RECT 5.535 52.655 5.605 53.005 ;
      RECT 5.535 53.105 5.605 53.455 ;
      RECT 5.535 53.555 5.605 53.905 ;
      RECT 5.535 54.005 5.605 54.355 ;
      RECT 5.535 54.455 5.605 54.805 ;
      RECT 5.535 54.905 5.605 55.255 ;
      RECT 5.535 57.765 5.605 58.115 ;
      RECT 5.535 58.215 5.605 58.565 ;
      RECT 5.535 58.665 5.605 59.015 ;
      RECT 5.535 59.115 5.605 59.465 ;
      RECT 5.535 59.565 5.605 59.915 ;
      RECT 5.535 60.015 5.605 60.365 ;
      RECT 5.535 60.465 5.605 60.815 ;
      RECT 5.535 74.445 5.605 74.795 ;
      RECT 5.535 74.895 5.605 75.245 ;
      RECT 5.535 75.345 5.605 75.695 ;
      RECT 5.535 75.795 5.605 76.145 ;
      RECT 5.535 76.245 5.605 76.595 ;
      RECT 5.535 76.695 5.605 77.045 ;
      RECT 5.535 77.145 5.605 77.495 ;
      RECT 5.535 80.005 5.605 80.355 ;
      RECT 5.535 80.455 5.605 80.805 ;
      RECT 5.535 80.905 5.605 81.255 ;
      RECT 5.535 81.355 5.605 81.705 ;
      RECT 5.535 81.805 5.605 82.155 ;
      RECT 5.535 82.255 5.605 82.605 ;
      RECT 5.535 82.705 5.605 83.055 ;
      RECT 5.535 85.565 5.605 85.915 ;
      RECT 5.535 86.015 5.605 86.365 ;
      RECT 5.535 86.465 5.605 86.815 ;
      RECT 5.535 86.915 5.605 87.265 ;
      RECT 5.535 87.365 5.605 87.715 ;
      RECT 5.535 87.815 5.605 88.165 ;
      RECT 5.535 88.265 5.605 88.615 ;
      RECT 5.535 96.685 5.605 97.035 ;
      RECT 5.535 97.135 5.605 97.485 ;
      RECT 5.535 97.585 5.605 97.935 ;
      RECT 5.535 98.035 5.605 98.385 ;
      RECT 5.535 98.485 5.605 98.835 ;
      RECT 5.535 98.935 5.605 99.285 ;
      RECT 5.535 99.385 5.605 99.735 ;
      RECT 5.535 102.245 5.605 102.595 ;
      RECT 5.535 102.695 5.605 103.045 ;
      RECT 5.535 103.145 5.605 103.495 ;
      RECT 5.535 103.595 5.605 103.945 ;
      RECT 5.535 104.045 5.605 104.395 ;
      RECT 5.535 104.495 5.605 104.845 ;
      RECT 5.535 104.945 5.605 105.295 ;
      RECT 5.535 118.925 5.605 119.275 ;
      RECT 5.535 119.375 5.605 119.725 ;
      RECT 5.535 119.825 5.605 120.175 ;
      RECT 5.535 120.275 5.605 120.625 ;
      RECT 5.535 120.725 5.605 121.075 ;
      RECT 5.535 121.175 5.605 121.525 ;
      RECT 5.535 121.625 5.605 121.975 ;
      RECT 5.535 124.485 5.605 124.835 ;
      RECT 5.535 124.935 5.605 125.285 ;
      RECT 5.535 125.385 5.605 125.735 ;
      RECT 5.535 125.835 5.605 126.185 ;
      RECT 5.535 126.285 5.605 126.635 ;
      RECT 5.535 126.735 5.605 127.085 ;
      RECT 5.535 127.185 5.605 127.535 ;
      RECT 5.535 130.045 5.605 130.395 ;
      RECT 5.535 130.495 5.605 130.845 ;
      RECT 5.535 130.945 5.605 131.295 ;
      RECT 5.535 131.395 5.605 131.745 ;
      RECT 5.535 131.845 5.605 132.195 ;
      RECT 5.535 132.295 5.605 132.645 ;
      RECT 5.535 132.745 5.605 133.095 ;
      RECT 5.535 141.165 5.605 141.515 ;
      RECT 5.535 141.615 5.605 141.965 ;
      RECT 5.535 142.065 5.605 142.415 ;
      RECT 5.535 142.515 5.605 142.865 ;
      RECT 5.535 142.965 5.605 143.315 ;
      RECT 5.535 143.415 5.605 143.765 ;
      RECT 5.535 143.865 5.605 144.215 ;
      RECT 5.535 146.725 5.605 147.075 ;
      RECT 5.535 147.175 5.605 147.525 ;
      RECT 5.535 147.625 5.605 147.975 ;
      RECT 5.535 148.075 5.605 148.425 ;
      RECT 5.535 148.525 5.605 148.875 ;
      RECT 5.535 148.975 5.605 149.325 ;
      RECT 5.535 149.425 5.605 149.775 ;
      RECT 5.535 152.285 5.605 152.635 ;
      RECT 5.535 152.735 5.605 153.085 ;
      RECT 5.535 153.185 5.605 153.535 ;
      RECT 5.535 153.635 5.605 153.985 ;
      RECT 5.535 154.085 5.605 154.435 ;
      RECT 5.535 154.535 5.605 154.885 ;
      RECT 5.535 154.985 5.605 155.335 ;
      RECT 5.535 163.405 5.605 163.755 ;
      RECT 5.535 163.855 5.605 164.205 ;
      RECT 5.535 164.305 5.605 164.655 ;
      RECT 5.535 164.755 5.605 165.105 ;
      RECT 5.535 165.205 5.605 165.555 ;
      RECT 5.535 165.655 5.605 166.005 ;
      RECT 5.535 166.105 5.605 166.455 ;
      RECT 5.535 168.965 5.605 169.315 ;
      RECT 5.535 169.415 5.605 169.765 ;
      RECT 5.535 169.865 5.605 170.215 ;
      RECT 5.535 170.315 5.605 170.665 ;
      RECT 5.535 170.765 5.605 171.115 ;
      RECT 5.535 171.215 5.605 171.565 ;
      RECT 5.535 171.665 5.605 172.015 ;
      RECT 5.535 174.525 5.605 174.875 ;
      RECT 5.535 174.975 5.605 175.325 ;
      RECT 5.535 175.425 5.605 175.775 ;
      RECT 5.535 175.875 5.605 176.225 ;
      RECT 5.535 176.325 5.605 176.675 ;
      RECT 5.535 176.775 5.605 177.125 ;
      RECT 5.535 177.225 5.605 177.575 ;
      RECT 5.535 191.205 5.605 191.555 ;
      RECT 5.535 191.655 5.605 192.005 ;
      RECT 5.535 192.105 5.605 192.455 ;
      RECT 5.535 192.555 5.605 192.905 ;
      RECT 5.535 193.005 5.605 193.355 ;
      RECT 5.535 193.455 5.605 193.805 ;
      RECT 5.535 193.905 5.605 194.255 ;
      RECT 5.535 196.765 5.605 197.115 ;
      RECT 5.535 197.215 5.605 197.565 ;
      RECT 5.535 197.665 5.605 198.015 ;
      RECT 5.535 198.115 5.605 198.465 ;
      RECT 5.535 198.565 5.605 198.915 ;
      RECT 5.535 199.015 5.605 199.365 ;
      RECT 5.535 199.465 5.605 199.815 ;
      RECT 5.535 207.885 5.605 208.235 ;
      RECT 5.535 208.335 5.605 208.685 ;
      RECT 5.535 208.785 5.605 209.135 ;
      RECT 5.535 209.235 5.605 209.585 ;
      RECT 5.535 209.685 5.605 210.035 ;
      RECT 5.535 210.135 5.605 210.485 ;
      RECT 5.535 210.585 5.605 210.935 ;
      RECT 5.535 213.445 5.605 213.795 ;
      RECT 5.535 213.895 5.605 214.245 ;
      RECT 5.535 214.345 5.605 214.695 ;
      RECT 5.535 214.795 5.605 215.145 ;
      RECT 5.535 215.245 5.605 215.595 ;
      RECT 5.535 215.695 5.605 216.045 ;
      RECT 5.535 216.145 5.605 216.495 ;
      RECT 5.535 219.005 5.605 219.355 ;
      RECT 5.535 219.455 5.605 219.805 ;
      RECT 5.535 219.905 5.605 220.255 ;
      RECT 5.535 220.355 5.605 220.705 ;
      RECT 5.535 220.805 5.605 221.155 ;
      RECT 5.535 221.255 5.605 221.605 ;
      RECT 5.535 221.705 5.605 222.055 ;
      RECT 5.535 235.685 5.605 236.035 ;
      RECT 5.535 236.135 5.605 236.485 ;
      RECT 5.535 236.585 5.605 236.935 ;
      RECT 5.535 237.035 5.605 237.385 ;
      RECT 5.535 237.485 5.605 237.835 ;
      RECT 5.535 237.935 5.605 238.285 ;
      RECT 5.535 238.385 5.605 238.735 ;
      RECT 5.535 241.245 5.605 241.595 ;
      RECT 5.535 241.695 5.605 242.045 ;
      RECT 5.535 242.145 5.605 242.495 ;
      RECT 5.535 242.595 5.605 242.945 ;
      RECT 5.535 243.045 5.605 243.395 ;
      RECT 5.535 243.495 5.605 243.845 ;
      RECT 5.535 243.945 5.605 244.295 ;
      RECT 5.535 257.925 5.605 258.275 ;
      RECT 5.535 258.375 5.605 258.725 ;
      RECT 5.535 258.825 5.605 259.175 ;
      RECT 5.535 259.275 5.605 259.625 ;
      RECT 5.535 259.725 5.605 260.075 ;
      RECT 5.535 260.175 5.605 260.525 ;
      RECT 5.535 260.625 5.605 260.975 ;
      RECT 5.535 263.485 5.605 263.835 ;
      RECT 5.535 263.935 5.605 264.285 ;
      RECT 5.535 264.385 5.605 264.735 ;
      RECT 5.535 264.835 5.605 265.185 ;
      RECT 5.535 265.285 5.605 265.635 ;
      RECT 5.535 265.735 5.605 266.085 ;
      RECT 5.535 266.185 5.605 266.535 ;
      RECT 5.535 280.165 5.605 280.515 ;
      RECT 5.535 280.615 5.605 280.965 ;
      RECT 5.535 281.065 5.605 281.415 ;
      RECT 5.535 281.515 5.605 281.865 ;
      RECT 5.535 281.965 5.605 282.315 ;
      RECT 5.535 282.415 5.605 282.765 ;
      RECT 5.535 282.865 5.605 283.215 ;
      RECT 5.535 285.725 5.605 286.075 ;
      RECT 5.535 286.175 5.605 286.525 ;
      RECT 5.535 286.625 5.605 286.975 ;
      RECT 5.535 287.075 5.605 287.425 ;
      RECT 5.535 287.525 5.605 287.875 ;
      RECT 5.535 287.975 5.605 288.325 ;
      RECT 5.535 288.425 5.605 288.775 ;
      RECT 5.535 291.285 5.605 291.635 ;
      RECT 5.535 291.735 5.605 292.085 ;
      RECT 5.535 292.185 5.605 292.535 ;
      RECT 5.535 292.635 5.605 292.985 ;
      RECT 5.535 293.085 5.605 293.435 ;
      RECT 5.535 293.535 5.605 293.885 ;
      RECT 5.535 293.985 5.605 294.335 ;
      RECT 5.53 113.365 5.6 113.715 ;
      RECT 5.53 113.815 5.6 114.165 ;
      RECT 5.53 114.265 5.6 114.615 ;
      RECT 5.53 114.715 5.6 115.065 ;
      RECT 5.53 115.165 5.6 115.515 ;
      RECT 5.53 115.615 5.6 115.965 ;
      RECT 5.53 116.065 5.6 116.415 ;
      RECT 5.52 135.605 5.59 135.955 ;
      RECT 5.52 136.055 5.59 136.405 ;
      RECT 5.52 136.505 5.59 136.855 ;
      RECT 5.52 136.955 5.59 137.305 ;
      RECT 5.52 137.405 5.59 137.755 ;
      RECT 5.52 137.855 5.59 138.205 ;
      RECT 5.52 138.305 5.59 138.655 ;
      RECT 5.51 157.845 5.58 158.195 ;
      RECT 5.51 158.295 5.58 158.645 ;
      RECT 5.51 158.745 5.58 159.095 ;
      RECT 5.51 159.195 5.58 159.545 ;
      RECT 5.51 159.645 5.58 159.995 ;
      RECT 5.51 160.095 5.58 160.445 ;
      RECT 5.51 160.545 5.58 160.895 ;
      RECT 5.5 180.085 5.57 180.435 ;
      RECT 5.5 180.535 5.57 180.885 ;
      RECT 5.5 180.985 5.57 181.335 ;
      RECT 5.5 181.435 5.57 181.785 ;
      RECT 5.5 181.885 5.57 182.235 ;
      RECT 5.5 182.335 5.57 182.685 ;
      RECT 5.5 182.785 5.57 183.135 ;
      RECT 5.49 185.645 5.56 185.995 ;
      RECT 5.49 186.095 5.56 186.445 ;
      RECT 5.49 186.545 5.56 186.895 ;
      RECT 5.49 186.995 5.56 187.345 ;
      RECT 5.49 187.445 5.56 187.795 ;
      RECT 5.49 187.895 5.56 188.245 ;
      RECT 5.49 188.345 5.56 188.695 ;
      RECT 5.49 202.325 5.56 202.675 ;
      RECT 5.49 202.775 5.56 203.125 ;
      RECT 5.49 203.225 5.56 203.575 ;
      RECT 5.49 203.675 5.56 204.025 ;
      RECT 5.49 204.125 5.56 204.475 ;
      RECT 5.49 204.575 5.56 204.925 ;
      RECT 5.49 205.025 5.56 205.375 ;
      RECT 5.48 224.565 5.55 224.915 ;
      RECT 5.48 225.015 5.55 225.365 ;
      RECT 5.48 225.465 5.55 225.815 ;
      RECT 5.48 225.915 5.55 226.265 ;
      RECT 5.48 226.365 5.55 226.715 ;
      RECT 5.48 226.815 5.55 227.165 ;
      RECT 5.48 227.265 5.55 227.615 ;
      RECT 5.47 230.125 5.54 230.475 ;
      RECT 5.47 230.575 5.54 230.925 ;
      RECT 5.47 231.025 5.54 231.375 ;
      RECT 5.47 231.475 5.54 231.825 ;
      RECT 5.47 231.925 5.54 232.275 ;
      RECT 5.47 232.375 5.54 232.725 ;
      RECT 5.47 232.825 5.54 233.175 ;
      RECT 5.47 246.805 5.54 247.155 ;
      RECT 5.47 247.255 5.54 247.605 ;
      RECT 5.47 247.705 5.54 248.055 ;
      RECT 5.47 248.155 5.54 248.505 ;
      RECT 5.47 248.605 5.54 248.955 ;
      RECT 5.47 249.055 5.54 249.405 ;
      RECT 5.47 249.505 5.54 249.855 ;
      RECT 5.46 252.365 5.53 252.715 ;
      RECT 5.46 252.815 5.53 253.165 ;
      RECT 5.46 253.265 5.53 253.615 ;
      RECT 5.46 253.715 5.53 254.065 ;
      RECT 5.46 254.165 5.53 254.515 ;
      RECT 5.46 254.615 5.53 254.965 ;
      RECT 5.46 255.065 5.53 255.415 ;
      RECT 5.46 269.045 5.53 269.395 ;
      RECT 5.46 269.495 5.53 269.845 ;
      RECT 5.46 269.945 5.53 270.295 ;
      RECT 5.46 270.395 5.53 270.745 ;
      RECT 5.46 270.845 5.53 271.195 ;
      RECT 5.46 271.295 5.53 271.645 ;
      RECT 5.46 271.745 5.53 272.095 ;
      RECT 5.45 274.605 5.52 274.955 ;
      RECT 5.45 275.055 5.52 275.405 ;
      RECT 5.45 275.505 5.52 275.855 ;
      RECT 5.45 275.955 5.52 276.305 ;
      RECT 5.45 276.405 5.52 276.755 ;
      RECT 5.45 276.855 5.52 277.205 ;
      RECT 5.45 277.305 5.52 277.655 ;
      RECT 5.44 2.165 5.51 2.515 ;
      RECT 5.44 2.615 5.51 2.965 ;
      RECT 5.44 3.065 5.51 3.415 ;
      RECT 5.44 3.515 5.51 3.865 ;
      RECT 5.44 3.965 5.51 4.315 ;
      RECT 5.44 4.415 5.51 4.765 ;
      RECT 5.44 4.865 5.51 5.215 ;
      RECT 5.44 18.845 5.51 19.195 ;
      RECT 5.44 19.295 5.51 19.645 ;
      RECT 5.44 19.745 5.51 20.095 ;
      RECT 5.44 20.195 5.51 20.545 ;
      RECT 5.44 20.645 5.51 20.995 ;
      RECT 5.44 21.095 5.51 21.445 ;
      RECT 5.44 21.545 5.51 21.895 ;
      RECT 5.43 24.405 5.5 24.755 ;
      RECT 5.43 24.855 5.5 25.205 ;
      RECT 5.43 25.305 5.5 25.655 ;
      RECT 5.43 25.755 5.5 26.105 ;
      RECT 5.43 26.205 5.5 26.555 ;
      RECT 5.43 26.655 5.5 27.005 ;
      RECT 5.43 27.105 5.5 27.455 ;
      RECT 5.43 41.085 5.5 41.435 ;
      RECT 5.43 41.535 5.5 41.885 ;
      RECT 5.43 41.985 5.5 42.335 ;
      RECT 5.43 42.435 5.5 42.785 ;
      RECT 5.43 42.885 5.5 43.235 ;
      RECT 5.43 43.335 5.5 43.685 ;
      RECT 5.43 43.785 5.5 44.135 ;
      RECT 5.42 46.645 5.49 46.995 ;
      RECT 5.42 47.095 5.49 47.445 ;
      RECT 5.42 47.545 5.49 47.895 ;
      RECT 5.42 47.995 5.49 48.345 ;
      RECT 5.42 48.445 5.49 48.795 ;
      RECT 5.42 48.895 5.49 49.245 ;
      RECT 5.42 49.345 5.49 49.695 ;
      RECT 5.42 63.325 5.49 63.675 ;
      RECT 5.42 63.775 5.49 64.125 ;
      RECT 5.42 64.225 5.49 64.575 ;
      RECT 5.42 64.675 5.49 65.025 ;
      RECT 5.42 65.125 5.49 65.475 ;
      RECT 5.42 65.575 5.49 65.925 ;
      RECT 5.42 66.025 5.49 66.375 ;
      RECT 5.41 68.885 5.48 69.235 ;
      RECT 5.41 69.335 5.48 69.685 ;
      RECT 5.41 69.785 5.48 70.135 ;
      RECT 5.41 70.235 5.48 70.585 ;
      RECT 5.41 70.685 5.48 71.035 ;
      RECT 5.41 71.135 5.48 71.485 ;
      RECT 5.41 71.585 5.48 71.935 ;
      RECT 5.4 91.125 5.47 91.475 ;
      RECT 5.4 91.575 5.47 91.925 ;
      RECT 5.4 92.025 5.47 92.375 ;
      RECT 5.4 92.475 5.47 92.825 ;
      RECT 5.4 92.925 5.47 93.275 ;
      RECT 5.4 93.375 5.47 93.725 ;
      RECT 5.4 93.825 5.47 94.175 ;
      RECT 5.4 107.805 5.47 108.155 ;
      RECT 5.4 108.255 5.47 108.605 ;
      RECT 5.4 108.705 5.47 109.055 ;
      RECT 5.4 109.155 5.47 109.505 ;
      RECT 5.4 109.605 5.47 109.955 ;
      RECT 5.4 110.055 5.47 110.405 ;
      RECT 5.4 110.505 5.47 110.855 ;
      RECT 5.395 7.725 5.465 8.075 ;
      RECT 5.395 8.175 5.465 8.525 ;
      RECT 5.395 8.625 5.465 8.975 ;
      RECT 5.395 9.075 5.465 9.425 ;
      RECT 5.395 9.525 5.465 9.875 ;
      RECT 5.395 9.975 5.465 10.325 ;
      RECT 5.395 10.425 5.465 10.775 ;
      RECT 5.395 13.285 5.465 13.635 ;
      RECT 5.395 13.735 5.465 14.085 ;
      RECT 5.395 14.185 5.465 14.535 ;
      RECT 5.395 14.635 5.465 14.985 ;
      RECT 5.395 15.085 5.465 15.435 ;
      RECT 5.395 15.535 5.465 15.885 ;
      RECT 5.395 15.985 5.465 16.335 ;
      RECT 5.395 29.965 5.465 30.315 ;
      RECT 5.395 30.415 5.465 30.765 ;
      RECT 5.395 30.865 5.465 31.215 ;
      RECT 5.395 31.315 5.465 31.665 ;
      RECT 5.395 31.765 5.465 32.115 ;
      RECT 5.395 32.215 5.465 32.565 ;
      RECT 5.395 32.665 5.465 33.015 ;
      RECT 5.395 35.525 5.465 35.875 ;
      RECT 5.395 35.975 5.465 36.325 ;
      RECT 5.395 36.425 5.465 36.775 ;
      RECT 5.395 36.875 5.465 37.225 ;
      RECT 5.395 37.325 5.465 37.675 ;
      RECT 5.395 37.775 5.465 38.125 ;
      RECT 5.395 38.225 5.465 38.575 ;
      RECT 5.395 52.205 5.465 52.555 ;
      RECT 5.395 52.655 5.465 53.005 ;
      RECT 5.395 53.105 5.465 53.455 ;
      RECT 5.395 53.555 5.465 53.905 ;
      RECT 5.395 54.005 5.465 54.355 ;
      RECT 5.395 54.455 5.465 54.805 ;
      RECT 5.395 54.905 5.465 55.255 ;
      RECT 5.395 57.765 5.465 58.115 ;
      RECT 5.395 58.215 5.465 58.565 ;
      RECT 5.395 58.665 5.465 59.015 ;
      RECT 5.395 59.115 5.465 59.465 ;
      RECT 5.395 59.565 5.465 59.915 ;
      RECT 5.395 60.015 5.465 60.365 ;
      RECT 5.395 60.465 5.465 60.815 ;
      RECT 5.395 74.445 5.465 74.795 ;
      RECT 5.395 74.895 5.465 75.245 ;
      RECT 5.395 75.345 5.465 75.695 ;
      RECT 5.395 75.795 5.465 76.145 ;
      RECT 5.395 76.245 5.465 76.595 ;
      RECT 5.395 76.695 5.465 77.045 ;
      RECT 5.395 77.145 5.465 77.495 ;
      RECT 5.395 80.005 5.465 80.355 ;
      RECT 5.395 80.455 5.465 80.805 ;
      RECT 5.395 80.905 5.465 81.255 ;
      RECT 5.395 81.355 5.465 81.705 ;
      RECT 5.395 81.805 5.465 82.155 ;
      RECT 5.395 82.255 5.465 82.605 ;
      RECT 5.395 82.705 5.465 83.055 ;
      RECT 5.395 85.565 5.465 85.915 ;
      RECT 5.395 86.015 5.465 86.365 ;
      RECT 5.395 86.465 5.465 86.815 ;
      RECT 5.395 86.915 5.465 87.265 ;
      RECT 5.395 87.365 5.465 87.715 ;
      RECT 5.395 87.815 5.465 88.165 ;
      RECT 5.395 88.265 5.465 88.615 ;
      RECT 5.395 96.685 5.465 97.035 ;
      RECT 5.395 97.135 5.465 97.485 ;
      RECT 5.395 97.585 5.465 97.935 ;
      RECT 5.395 98.035 5.465 98.385 ;
      RECT 5.395 98.485 5.465 98.835 ;
      RECT 5.395 98.935 5.465 99.285 ;
      RECT 5.395 99.385 5.465 99.735 ;
      RECT 5.395 102.245 5.465 102.595 ;
      RECT 5.395 102.695 5.465 103.045 ;
      RECT 5.395 103.145 5.465 103.495 ;
      RECT 5.395 103.595 5.465 103.945 ;
      RECT 5.395 104.045 5.465 104.395 ;
      RECT 5.395 104.495 5.465 104.845 ;
      RECT 5.395 104.945 5.465 105.295 ;
      RECT 5.395 118.925 5.465 119.275 ;
      RECT 5.395 119.375 5.465 119.725 ;
      RECT 5.395 119.825 5.465 120.175 ;
      RECT 5.395 120.275 5.465 120.625 ;
      RECT 5.395 120.725 5.465 121.075 ;
      RECT 5.395 121.175 5.465 121.525 ;
      RECT 5.395 121.625 5.465 121.975 ;
      RECT 5.395 124.485 5.465 124.835 ;
      RECT 5.395 124.935 5.465 125.285 ;
      RECT 5.395 125.385 5.465 125.735 ;
      RECT 5.395 125.835 5.465 126.185 ;
      RECT 5.395 126.285 5.465 126.635 ;
      RECT 5.395 126.735 5.465 127.085 ;
      RECT 5.395 127.185 5.465 127.535 ;
      RECT 5.395 130.045 5.465 130.395 ;
      RECT 5.395 130.495 5.465 130.845 ;
      RECT 5.395 130.945 5.465 131.295 ;
      RECT 5.395 131.395 5.465 131.745 ;
      RECT 5.395 131.845 5.465 132.195 ;
      RECT 5.395 132.295 5.465 132.645 ;
      RECT 5.395 132.745 5.465 133.095 ;
      RECT 5.395 141.165 5.465 141.515 ;
      RECT 5.395 141.615 5.465 141.965 ;
      RECT 5.395 142.065 5.465 142.415 ;
      RECT 5.395 142.515 5.465 142.865 ;
      RECT 5.395 142.965 5.465 143.315 ;
      RECT 5.395 143.415 5.465 143.765 ;
      RECT 5.395 143.865 5.465 144.215 ;
      RECT 5.395 146.725 5.465 147.075 ;
      RECT 5.395 147.175 5.465 147.525 ;
      RECT 5.395 147.625 5.465 147.975 ;
      RECT 5.395 148.075 5.465 148.425 ;
      RECT 5.395 148.525 5.465 148.875 ;
      RECT 5.395 148.975 5.465 149.325 ;
      RECT 5.395 149.425 5.465 149.775 ;
      RECT 5.395 152.285 5.465 152.635 ;
      RECT 5.395 152.735 5.465 153.085 ;
      RECT 5.395 153.185 5.465 153.535 ;
      RECT 5.395 153.635 5.465 153.985 ;
      RECT 5.395 154.085 5.465 154.435 ;
      RECT 5.395 154.535 5.465 154.885 ;
      RECT 5.395 154.985 5.465 155.335 ;
      RECT 5.395 163.405 5.465 163.755 ;
      RECT 5.395 163.855 5.465 164.205 ;
      RECT 5.395 164.305 5.465 164.655 ;
      RECT 5.395 164.755 5.465 165.105 ;
      RECT 5.395 165.205 5.465 165.555 ;
      RECT 5.395 165.655 5.465 166.005 ;
      RECT 5.395 166.105 5.465 166.455 ;
      RECT 5.395 168.965 5.465 169.315 ;
      RECT 5.395 169.415 5.465 169.765 ;
      RECT 5.395 169.865 5.465 170.215 ;
      RECT 5.395 170.315 5.465 170.665 ;
      RECT 5.395 170.765 5.465 171.115 ;
      RECT 5.395 171.215 5.465 171.565 ;
      RECT 5.395 171.665 5.465 172.015 ;
      RECT 5.395 174.525 5.465 174.875 ;
      RECT 5.395 174.975 5.465 175.325 ;
      RECT 5.395 175.425 5.465 175.775 ;
      RECT 5.395 175.875 5.465 176.225 ;
      RECT 5.395 176.325 5.465 176.675 ;
      RECT 5.395 176.775 5.465 177.125 ;
      RECT 5.395 177.225 5.465 177.575 ;
      RECT 5.395 191.205 5.465 191.555 ;
      RECT 5.395 191.655 5.465 192.005 ;
      RECT 5.395 192.105 5.465 192.455 ;
      RECT 5.395 192.555 5.465 192.905 ;
      RECT 5.395 193.005 5.465 193.355 ;
      RECT 5.395 193.455 5.465 193.805 ;
      RECT 5.395 193.905 5.465 194.255 ;
      RECT 5.395 196.765 5.465 197.115 ;
      RECT 5.395 197.215 5.465 197.565 ;
      RECT 5.395 197.665 5.465 198.015 ;
      RECT 5.395 198.115 5.465 198.465 ;
      RECT 5.395 198.565 5.465 198.915 ;
      RECT 5.395 199.015 5.465 199.365 ;
      RECT 5.395 199.465 5.465 199.815 ;
      RECT 5.395 207.885 5.465 208.235 ;
      RECT 5.395 208.335 5.465 208.685 ;
      RECT 5.395 208.785 5.465 209.135 ;
      RECT 5.395 209.235 5.465 209.585 ;
      RECT 5.395 209.685 5.465 210.035 ;
      RECT 5.395 210.135 5.465 210.485 ;
      RECT 5.395 210.585 5.465 210.935 ;
      RECT 5.395 213.445 5.465 213.795 ;
      RECT 5.395 213.895 5.465 214.245 ;
      RECT 5.395 214.345 5.465 214.695 ;
      RECT 5.395 214.795 5.465 215.145 ;
      RECT 5.395 215.245 5.465 215.595 ;
      RECT 5.395 215.695 5.465 216.045 ;
      RECT 5.395 216.145 5.465 216.495 ;
      RECT 5.395 219.005 5.465 219.355 ;
      RECT 5.395 219.455 5.465 219.805 ;
      RECT 5.395 219.905 5.465 220.255 ;
      RECT 5.395 220.355 5.465 220.705 ;
      RECT 5.395 220.805 5.465 221.155 ;
      RECT 5.395 221.255 5.465 221.605 ;
      RECT 5.395 221.705 5.465 222.055 ;
      RECT 5.395 235.685 5.465 236.035 ;
      RECT 5.395 236.135 5.465 236.485 ;
      RECT 5.395 236.585 5.465 236.935 ;
      RECT 5.395 237.035 5.465 237.385 ;
      RECT 5.395 237.485 5.465 237.835 ;
      RECT 5.395 237.935 5.465 238.285 ;
      RECT 5.395 238.385 5.465 238.735 ;
      RECT 5.395 241.245 5.465 241.595 ;
      RECT 5.395 241.695 5.465 242.045 ;
      RECT 5.395 242.145 5.465 242.495 ;
      RECT 5.395 242.595 5.465 242.945 ;
      RECT 5.395 243.045 5.465 243.395 ;
      RECT 5.395 243.495 5.465 243.845 ;
      RECT 5.395 243.945 5.465 244.295 ;
      RECT 5.395 257.925 5.465 258.275 ;
      RECT 5.395 258.375 5.465 258.725 ;
      RECT 5.395 258.825 5.465 259.175 ;
      RECT 5.395 259.275 5.465 259.625 ;
      RECT 5.395 259.725 5.465 260.075 ;
      RECT 5.395 260.175 5.465 260.525 ;
      RECT 5.395 260.625 5.465 260.975 ;
      RECT 5.395 263.485 5.465 263.835 ;
      RECT 5.395 263.935 5.465 264.285 ;
      RECT 5.395 264.385 5.465 264.735 ;
      RECT 5.395 264.835 5.465 265.185 ;
      RECT 5.395 265.285 5.465 265.635 ;
      RECT 5.395 265.735 5.465 266.085 ;
      RECT 5.395 266.185 5.465 266.535 ;
      RECT 5.395 280.165 5.465 280.515 ;
      RECT 5.395 280.615 5.465 280.965 ;
      RECT 5.395 281.065 5.465 281.415 ;
      RECT 5.395 281.515 5.465 281.865 ;
      RECT 5.395 281.965 5.465 282.315 ;
      RECT 5.395 282.415 5.465 282.765 ;
      RECT 5.395 282.865 5.465 283.215 ;
      RECT 5.395 285.725 5.465 286.075 ;
      RECT 5.395 286.175 5.465 286.525 ;
      RECT 5.395 286.625 5.465 286.975 ;
      RECT 5.395 287.075 5.465 287.425 ;
      RECT 5.395 287.525 5.465 287.875 ;
      RECT 5.395 287.975 5.465 288.325 ;
      RECT 5.395 288.425 5.465 288.775 ;
      RECT 5.395 291.285 5.465 291.635 ;
      RECT 5.395 291.735 5.465 292.085 ;
      RECT 5.395 292.185 5.465 292.535 ;
      RECT 5.395 292.635 5.465 292.985 ;
      RECT 5.395 293.085 5.465 293.435 ;
      RECT 5.395 293.535 5.465 293.885 ;
      RECT 5.395 293.985 5.465 294.335 ;
    LAYER M3 ;
      RECT 47.6 0.07 48.1 0.88 ;
      RECT 47.6 295.12 48.1 295.93 ;
      RECT 44.07 0.07 44.57 0.88 ;
      RECT 44.07 295.12 44.57 295.93 ;
    LAYER M3 SPACING 0.05 ;
      RECT 0 0 92.2 296 ;
    LAYER M4 ;
      RECT 47.6 148.585 66.175 148.685 ;
      RECT 66.075 147.75 66.175 148.685 ;
      RECT 66.075 147.75 86.985 147.85 ;
      RECT 48.245 148.785 66.375 148.885 ;
      RECT 66.275 147.95 66.375 148.885 ;
      RECT 66.275 147.95 86.985 148.05 ;
      RECT 47.6 148.985 66.575 149.085 ;
      RECT 66.475 148.15 66.575 149.085 ;
      RECT 66.475 148.15 86.985 148.25 ;
      RECT 70.7 1.55 91.5 1.97 ;
      RECT 70.7 7.11 91.5 7.53 ;
      RECT 70.7 12.67 91.5 13.09 ;
      RECT 70.7 18.23 91.5 18.65 ;
      RECT 70.7 23.79 91.5 24.21 ;
      RECT 70.7 29.35 91.5 29.77 ;
      RECT 70.7 34.91 91.5 35.33 ;
      RECT 70.7 40.47 91.5 40.89 ;
      RECT 70.7 46.03 91.5 46.45 ;
      RECT 70.7 51.59 91.5 52.01 ;
      RECT 70.7 57.15 91.5 57.57 ;
      RECT 70.7 62.71 91.5 63.13 ;
      RECT 70.7 68.27 91.5 68.69 ;
      RECT 70.7 73.83 91.5 74.25 ;
      RECT 70.7 79.39 91.5 79.81 ;
      RECT 70.7 84.95 91.5 85.37 ;
      RECT 70.7 90.51 91.5 90.93 ;
      RECT 70.7 96.07 91.5 96.49 ;
      RECT 70.7 101.63 91.5 102.05 ;
      RECT 70.7 107.19 91.5 107.61 ;
      RECT 70.7 112.75 91.5 113.17 ;
      RECT 70.7 118.31 91.5 118.73 ;
      RECT 70.7 123.87 91.5 124.29 ;
      RECT 70.7 129.43 91.5 129.85 ;
      RECT 70.7 134.99 91.5 135.41 ;
      RECT 70.7 140.55 91.5 140.97 ;
      RECT 70.7 146.11 91.5 146.53 ;
      RECT 70.7 151.67 91.5 152.09 ;
      RECT 70.7 157.23 91.5 157.65 ;
      RECT 70.7 162.79 91.5 163.21 ;
      RECT 70.7 168.35 91.5 168.77 ;
      RECT 70.7 173.91 91.5 174.33 ;
      RECT 70.7 179.47 91.5 179.89 ;
      RECT 70.7 185.03 91.5 185.45 ;
      RECT 70.7 190.59 91.5 191.01 ;
      RECT 70.7 196.15 91.5 196.57 ;
      RECT 70.7 201.71 91.5 202.13 ;
      RECT 70.7 207.27 91.5 207.69 ;
      RECT 70.7 212.83 91.5 213.25 ;
      RECT 70.7 218.39 91.5 218.81 ;
      RECT 70.7 223.95 91.5 224.37 ;
      RECT 70.7 229.51 91.5 229.93 ;
      RECT 70.7 235.07 91.5 235.49 ;
      RECT 70.7 240.63 91.5 241.05 ;
      RECT 70.7 246.19 91.5 246.61 ;
      RECT 70.7 251.75 91.5 252.17 ;
      RECT 70.7 257.31 91.5 257.73 ;
      RECT 70.7 262.87 91.5 263.29 ;
      RECT 70.7 268.43 91.5 268.85 ;
      RECT 70.7 273.99 91.5 274.41 ;
      RECT 70.7 279.55 91.5 279.97 ;
      RECT 70.7 285.11 91.5 285.53 ;
      RECT 70.7 290.67 91.5 291.09 ;
      RECT 46.685 0.71 87.005 0.81 ;
      RECT 46.485 0.91 87.005 1.01 ;
      RECT 45.385 5.87 87.005 5.97 ;
      RECT 45.585 6.07 87.005 6.17 ;
      RECT 46.685 6.27 87.005 6.37 ;
      RECT 46.485 6.47 87.005 6.57 ;
      RECT 45.385 11.43 87.005 11.53 ;
      RECT 45.585 11.63 87.005 11.73 ;
      RECT 46.685 11.83 87.005 11.93 ;
      RECT 46.485 12.03 87.005 12.13 ;
      RECT 45.385 16.99 87.005 17.09 ;
      RECT 45.585 17.19 87.005 17.29 ;
      RECT 46.685 17.39 87.005 17.49 ;
      RECT 46.485 17.59 87.005 17.69 ;
      RECT 45.385 22.55 87.005 22.65 ;
      RECT 45.585 22.75 87.005 22.85 ;
      RECT 46.685 22.95 87.005 23.05 ;
      RECT 46.485 23.15 87.005 23.25 ;
      RECT 45.385 28.11 87.005 28.21 ;
      RECT 45.585 28.31 87.005 28.41 ;
      RECT 46.685 28.51 87.005 28.61 ;
      RECT 46.485 28.71 87.005 28.81 ;
      RECT 45.385 33.67 87.005 33.77 ;
      RECT 45.585 33.87 87.005 33.97 ;
      RECT 46.685 34.07 87.005 34.17 ;
      RECT 46.485 34.27 87.005 34.37 ;
      RECT 45.385 39.23 87.005 39.33 ;
      RECT 45.585 39.43 87.005 39.53 ;
      RECT 46.685 39.63 87.005 39.73 ;
      RECT 46.485 39.83 87.005 39.93 ;
      RECT 45.385 44.79 87.005 44.89 ;
      RECT 45.585 44.99 87.005 45.09 ;
      RECT 46.685 45.19 87.005 45.29 ;
      RECT 46.485 45.39 87.005 45.49 ;
      RECT 45.385 50.35 87.005 50.45 ;
      RECT 45.585 50.55 87.005 50.65 ;
      RECT 46.685 50.75 87.005 50.85 ;
      RECT 46.485 50.95 87.005 51.05 ;
      RECT 45.385 55.91 87.005 56.01 ;
      RECT 45.585 56.11 87.005 56.21 ;
      RECT 46.685 56.31 87.005 56.41 ;
      RECT 46.485 56.51 87.005 56.61 ;
      RECT 45.385 61.47 87.005 61.57 ;
      RECT 45.585 61.67 87.005 61.77 ;
      RECT 46.685 61.87 87.005 61.97 ;
      RECT 46.485 62.07 87.005 62.17 ;
      RECT 45.385 67.03 87.005 67.13 ;
      RECT 45.585 67.23 87.005 67.33 ;
      RECT 46.685 67.43 87.005 67.53 ;
      RECT 46.485 67.63 87.005 67.73 ;
      RECT 45.385 72.59 87.005 72.69 ;
      RECT 45.585 72.79 87.005 72.89 ;
      RECT 46.685 72.99 87.005 73.09 ;
      RECT 46.485 73.19 87.005 73.29 ;
      RECT 45.385 78.15 87.005 78.25 ;
      RECT 45.585 78.35 87.005 78.45 ;
      RECT 46.685 78.55 87.005 78.65 ;
      RECT 46.485 78.75 87.005 78.85 ;
      RECT 45.385 83.71 87.005 83.81 ;
      RECT 45.585 83.91 87.005 84.01 ;
      RECT 46.685 84.11 87.005 84.21 ;
      RECT 46.485 84.31 87.005 84.41 ;
      RECT 45.385 89.27 87.005 89.37 ;
      RECT 45.585 89.47 87.005 89.57 ;
      RECT 46.685 89.67 87.005 89.77 ;
      RECT 46.485 89.87 87.005 89.97 ;
      RECT 45.385 94.83 87.005 94.93 ;
      RECT 45.585 95.03 87.005 95.13 ;
      RECT 46.685 95.23 87.005 95.33 ;
      RECT 46.485 95.43 87.005 95.53 ;
      RECT 45.385 100.39 87.005 100.49 ;
      RECT 45.585 100.59 87.005 100.69 ;
      RECT 46.685 100.79 87.005 100.89 ;
      RECT 46.485 100.99 87.005 101.09 ;
      RECT 45.385 105.95 87.005 106.05 ;
      RECT 45.585 106.15 87.005 106.25 ;
      RECT 46.685 106.35 87.005 106.45 ;
      RECT 46.485 106.55 87.005 106.65 ;
      RECT 45.385 111.51 87.005 111.61 ;
      RECT 45.585 111.71 87.005 111.81 ;
      RECT 46.685 111.91 87.005 112.01 ;
      RECT 46.485 112.11 87.005 112.21 ;
      RECT 45.385 117.07 87.005 117.17 ;
      RECT 45.585 117.27 87.005 117.37 ;
      RECT 46.685 117.47 87.005 117.57 ;
      RECT 46.485 117.67 87.005 117.77 ;
      RECT 45.385 122.63 87.005 122.73 ;
      RECT 45.585 122.83 87.005 122.93 ;
      RECT 46.685 123.03 87.005 123.13 ;
      RECT 46.485 123.23 87.005 123.33 ;
      RECT 45.385 128.19 87.005 128.29 ;
      RECT 45.585 128.39 87.005 128.49 ;
      RECT 46.685 128.59 87.005 128.69 ;
      RECT 46.485 128.79 87.005 128.89 ;
      RECT 45.385 133.75 87.005 133.85 ;
      RECT 45.585 133.95 87.005 134.05 ;
      RECT 46.685 134.15 87.005 134.25 ;
      RECT 46.485 134.35 87.005 134.45 ;
      RECT 45.385 139.31 87.005 139.41 ;
      RECT 45.585 139.51 87.005 139.61 ;
      RECT 46.685 139.71 87.005 139.81 ;
      RECT 46.485 139.91 87.005 140.01 ;
      RECT 45.385 144.87 87.005 144.97 ;
      RECT 45.585 145.07 87.005 145.17 ;
      RECT 46.685 145.27 87.005 145.37 ;
      RECT 46.485 145.47 87.005 145.57 ;
      RECT 45.385 150.43 87.005 150.53 ;
      RECT 45.585 150.63 87.005 150.73 ;
      RECT 46.685 150.83 87.005 150.93 ;
      RECT 46.485 151.03 87.005 151.13 ;
      RECT 45.385 155.99 87.005 156.09 ;
      RECT 45.585 156.19 87.005 156.29 ;
      RECT 46.685 156.39 87.005 156.49 ;
      RECT 46.485 156.59 87.005 156.69 ;
      RECT 45.385 161.55 87.005 161.65 ;
      RECT 45.585 161.75 87.005 161.85 ;
      RECT 46.685 161.95 87.005 162.05 ;
      RECT 46.485 162.15 87.005 162.25 ;
      RECT 45.385 167.11 87.005 167.21 ;
      RECT 45.585 167.31 87.005 167.41 ;
      RECT 46.685 167.51 87.005 167.61 ;
      RECT 46.485 167.71 87.005 167.81 ;
      RECT 45.385 172.67 87.005 172.77 ;
      RECT 45.585 172.87 87.005 172.97 ;
      RECT 46.685 173.07 87.005 173.17 ;
      RECT 46.485 173.27 87.005 173.37 ;
      RECT 45.385 178.23 87.005 178.33 ;
      RECT 45.585 178.43 87.005 178.53 ;
      RECT 46.685 178.63 87.005 178.73 ;
      RECT 46.485 178.83 87.005 178.93 ;
      RECT 45.385 183.79 87.005 183.89 ;
      RECT 45.585 183.99 87.005 184.09 ;
      RECT 46.685 184.19 87.005 184.29 ;
      RECT 46.485 184.39 87.005 184.49 ;
      RECT 45.385 189.35 87.005 189.45 ;
      RECT 45.585 189.55 87.005 189.65 ;
      RECT 46.685 189.75 87.005 189.85 ;
      RECT 46.485 189.95 87.005 190.05 ;
      RECT 45.385 194.91 87.005 195.01 ;
      RECT 45.585 195.11 87.005 195.21 ;
      RECT 46.685 195.31 87.005 195.41 ;
      RECT 46.485 195.51 87.005 195.61 ;
      RECT 45.385 200.47 87.005 200.57 ;
      RECT 45.585 200.67 87.005 200.77 ;
      RECT 46.685 200.87 87.005 200.97 ;
      RECT 46.485 201.07 87.005 201.17 ;
      RECT 45.385 206.03 87.005 206.13 ;
      RECT 45.585 206.23 87.005 206.33 ;
      RECT 46.685 206.43 87.005 206.53 ;
      RECT 46.485 206.63 87.005 206.73 ;
      RECT 45.385 211.59 87.005 211.69 ;
      RECT 45.585 211.79 87.005 211.89 ;
      RECT 46.685 211.99 87.005 212.09 ;
      RECT 46.485 212.19 87.005 212.29 ;
      RECT 45.385 217.15 87.005 217.25 ;
      RECT 45.585 217.35 87.005 217.45 ;
      RECT 46.685 217.55 87.005 217.65 ;
      RECT 46.485 217.75 87.005 217.85 ;
      RECT 45.385 222.71 87.005 222.81 ;
      RECT 45.585 222.91 87.005 223.01 ;
      RECT 46.685 223.11 87.005 223.21 ;
      RECT 46.485 223.31 87.005 223.41 ;
      RECT 45.385 228.27 87.005 228.37 ;
      RECT 45.585 228.47 87.005 228.57 ;
      RECT 46.685 228.67 87.005 228.77 ;
      RECT 46.485 228.87 87.005 228.97 ;
      RECT 45.385 233.83 87.005 233.93 ;
      RECT 45.585 234.03 87.005 234.13 ;
      RECT 46.685 234.23 87.005 234.33 ;
      RECT 46.485 234.43 87.005 234.53 ;
      RECT 45.385 239.39 87.005 239.49 ;
      RECT 45.585 239.59 87.005 239.69 ;
      RECT 46.685 239.79 87.005 239.89 ;
      RECT 46.485 239.99 87.005 240.09 ;
      RECT 45.385 244.95 87.005 245.05 ;
      RECT 45.585 245.15 87.005 245.25 ;
      RECT 46.685 245.35 87.005 245.45 ;
      RECT 46.485 245.55 87.005 245.65 ;
      RECT 45.385 250.51 87.005 250.61 ;
      RECT 45.585 250.71 87.005 250.81 ;
      RECT 46.685 250.91 87.005 251.01 ;
      RECT 46.485 251.11 87.005 251.21 ;
      RECT 45.385 256.07 87.005 256.17 ;
      RECT 45.585 256.27 87.005 256.37 ;
      RECT 46.685 256.47 87.005 256.57 ;
      RECT 46.485 256.67 87.005 256.77 ;
      RECT 45.385 261.63 87.005 261.73 ;
      RECT 45.585 261.83 87.005 261.93 ;
      RECT 46.685 262.03 87.005 262.13 ;
      RECT 46.485 262.23 87.005 262.33 ;
      RECT 45.385 267.19 87.005 267.29 ;
      RECT 45.585 267.39 87.005 267.49 ;
      RECT 46.685 267.59 87.005 267.69 ;
      RECT 46.485 267.79 87.005 267.89 ;
      RECT 45.585 272.75 87.005 272.85 ;
      RECT 45.385 272.95 87.005 273.05 ;
      RECT 46.685 273.15 87.005 273.25 ;
      RECT 46.485 273.35 87.005 273.45 ;
      RECT 45.585 278.31 87.005 278.41 ;
      RECT 45.385 278.51 87.005 278.61 ;
      RECT 46.685 278.71 87.005 278.81 ;
      RECT 46.485 278.91 87.005 279.01 ;
      RECT 45.585 283.87 87.005 283.97 ;
      RECT 45.385 284.07 87.005 284.17 ;
      RECT 46.685 284.27 87.005 284.37 ;
      RECT 46.485 284.47 87.005 284.57 ;
      RECT 45.585 289.43 87.005 289.53 ;
      RECT 45.385 289.63 87.005 289.73 ;
      RECT 46.685 289.83 87.005 289.93 ;
      RECT 46.485 290.03 87.005 290.13 ;
      RECT 45.585 294.99 87.005 295.09 ;
      RECT 45.385 295.19 87.005 295.29 ;
    LAYER M4 SPACING 0.05 ;
      RECT 0 295.395 92.2 296 ;
      RECT 91.07 295.315 92.2 296 ;
      RECT 0 148.355 87.4 296 ;
      RECT 0 290.235 90.56 294.885 ;
      RECT 0 290.315 92.2 294.805 ;
      RECT 91.47 284.715 92.2 289.405 ;
      RECT 0 284.715 92.2 289.325 ;
      RECT 0 284.675 90.56 289.325 ;
      RECT 91.47 279.115 92.2 283.805 ;
      RECT 0 279.115 92.2 283.765 ;
      RECT 0 273.555 92.2 278.205 ;
      RECT 91.47 273.515 92.2 278.205 ;
      RECT 0 267.995 90.56 272.645 ;
      RECT 0 267.995 92.2 272.605 ;
      RECT 91.47 267.915 92.2 272.605 ;
      RECT 0 262.435 90.56 267.085 ;
      RECT 0 262.515 92.2 267.005 ;
      RECT 91.47 256.915 92.2 261.605 ;
      RECT 0 256.915 92.2 261.525 ;
      RECT 0 256.875 90.56 261.525 ;
      RECT 91.47 251.315 92.2 256.005 ;
      RECT 0 251.315 92.2 255.965 ;
      RECT 0 245.755 92.2 250.405 ;
      RECT 91.47 245.715 92.2 250.405 ;
      RECT 0 240.195 90.56 244.845 ;
      RECT 0 240.195 92.2 244.805 ;
      RECT 91.47 240.115 92.2 244.805 ;
      RECT 0 234.635 90.56 239.285 ;
      RECT 0 234.715 92.2 239.205 ;
      RECT 91.47 229.115 92.2 233.805 ;
      RECT 0 229.115 92.2 233.725 ;
      RECT 0 229.075 90.56 233.725 ;
      RECT 91.47 223.515 92.2 228.205 ;
      RECT 0 223.515 92.2 228.165 ;
      RECT 0 217.955 92.2 222.605 ;
      RECT 91.47 217.915 92.2 222.605 ;
      RECT 0 212.395 90.56 217.045 ;
      RECT 0 212.395 92.2 217.005 ;
      RECT 91.47 212.315 92.2 217.005 ;
      RECT 0 206.835 90.56 211.485 ;
      RECT 0 206.915 92.2 211.405 ;
      RECT 91.47 201.315 92.2 206.005 ;
      RECT 0 201.315 92.2 205.925 ;
      RECT 0 201.275 90.56 205.925 ;
      RECT 91.47 195.715 92.2 200.405 ;
      RECT 0 195.715 92.2 200.365 ;
      RECT 0 190.155 92.2 194.805 ;
      RECT 91.47 190.115 92.2 194.805 ;
      RECT 0 184.595 90.56 189.245 ;
      RECT 0 184.595 92.2 189.205 ;
      RECT 91.47 184.515 92.2 189.205 ;
      RECT 0 179.035 90.56 183.685 ;
      RECT 0 179.115 92.2 183.605 ;
      RECT 91.47 173.515 92.2 178.205 ;
      RECT 0 173.515 92.2 178.125 ;
      RECT 0 173.475 90.56 178.125 ;
      RECT 91.47 167.915 92.2 172.605 ;
      RECT 0 167.915 92.2 172.565 ;
      RECT 0 162.355 92.2 167.005 ;
      RECT 91.47 162.315 92.2 167.005 ;
      RECT 0 156.795 90.56 161.445 ;
      RECT 0 156.795 92.2 161.405 ;
      RECT 91.47 156.715 92.2 161.405 ;
      RECT 0 151.235 90.56 155.885 ;
      RECT 0 151.315 92.2 155.805 ;
      RECT 91.47 148.355 92.2 150.405 ;
      RECT 0 148.355 92.2 150.325 ;
      RECT 0 0 87.38 296 ;
      RECT 0 145.715 92.2 147.645 ;
      RECT 0 145.675 90.56 147.645 ;
      RECT 0 0 87.4 147.645 ;
      RECT 91.47 140.115 92.2 144.805 ;
      RECT 0 140.115 92.2 144.765 ;
      RECT 0 134.555 92.2 139.205 ;
      RECT 91.47 134.515 92.2 139.205 ;
      RECT 0 128.995 90.56 133.645 ;
      RECT 0 128.995 92.2 133.605 ;
      RECT 91.47 128.915 92.2 133.605 ;
      RECT 0 123.435 90.56 128.085 ;
      RECT 0 123.515 92.2 128.005 ;
      RECT 91.47 117.915 92.2 122.605 ;
      RECT 0 117.915 92.2 122.525 ;
      RECT 0 117.875 90.56 122.525 ;
      RECT 91.47 112.315 92.2 117.005 ;
      RECT 0 112.315 92.2 116.965 ;
      RECT 0 106.755 92.2 111.405 ;
      RECT 91.47 106.715 92.2 111.405 ;
      RECT 0 101.195 90.56 105.845 ;
      RECT 0 101.195 92.2 105.805 ;
      RECT 91.47 101.115 92.2 105.805 ;
      RECT 0 95.635 90.56 100.285 ;
      RECT 0 95.715 92.2 100.205 ;
      RECT 91.47 90.115 92.2 94.805 ;
      RECT 0 90.115 92.2 94.725 ;
      RECT 0 90.075 90.56 94.725 ;
      RECT 91.47 84.515 92.2 89.205 ;
      RECT 0 84.515 92.2 89.165 ;
      RECT 0 78.955 92.2 83.605 ;
      RECT 91.47 78.915 92.2 83.605 ;
      RECT 0 73.395 90.56 78.045 ;
      RECT 0 73.395 92.2 78.005 ;
      RECT 91.47 73.315 92.2 78.005 ;
      RECT 0 67.835 90.56 72.485 ;
      RECT 0 67.915 92.2 72.405 ;
      RECT 91.47 62.315 92.2 67.005 ;
      RECT 0 62.315 92.2 66.925 ;
      RECT 0 62.275 90.56 66.925 ;
      RECT 91.47 56.715 92.2 61.405 ;
      RECT 0 56.715 92.2 61.365 ;
      RECT 0 51.155 92.2 55.805 ;
      RECT 91.47 51.115 92.2 55.805 ;
      RECT 0 45.595 90.56 50.245 ;
      RECT 0 45.595 92.2 50.205 ;
      RECT 91.47 45.515 92.2 50.205 ;
      RECT 0 40.035 90.56 44.685 ;
      RECT 0 40.115 92.2 44.605 ;
      RECT 91.47 34.515 92.2 39.205 ;
      RECT 0 34.515 92.2 39.125 ;
      RECT 0 34.475 90.56 39.125 ;
      RECT 91.47 28.915 92.2 33.605 ;
      RECT 0 28.915 92.2 33.565 ;
      RECT 0 23.355 92.2 28.005 ;
      RECT 91.47 23.315 92.2 28.005 ;
      RECT 0 17.795 90.56 22.445 ;
      RECT 0 17.795 92.2 22.405 ;
      RECT 91.605 17.715 92.2 22.405 ;
      RECT 0 12.235 90.695 16.885 ;
      RECT 0 12.315 92.2 16.805 ;
      RECT 91.605 6.715 92.2 11.405 ;
      RECT 0 6.715 92.2 11.325 ;
      RECT 0 6.675 90.695 11.325 ;
      RECT 91.605 1.115 92.2 5.805 ;
      RECT 0 1.115 92.2 5.765 ;
      RECT 0 0 92.2 0.605 ;
    LAYER M5 ;
      RECT 90.88 295.24 91.23 295.31 ;
      RECT 90.81 0.605 91.16 0.675 ;
      RECT 90.36 0.605 90.71 0.675 ;
      RECT 89.91 0.605 90.26 0.675 ;
      RECT 89.46 0.605 89.81 0.675 ;
      RECT 89.01 0.605 89.36 0.675 ;
      RECT 88.56 0.605 88.91 0.675 ;
      RECT 88.11 0.605 88.46 0.675 ;
      RECT 87.66 0.605 88.01 0.675 ;
      RECT 87.445 72.96 87.795 73.03 ;
      RECT 87.445 84.06 87.795 84.13 ;
      RECT 87.445 139.665 87.795 139.735 ;
      RECT 87.445 223 87.795 223.07 ;
      RECT 87.445 267.53 87.795 267.6 ;
      RECT 87.42 117.305 87.77 117.375 ;
      RECT 87.42 117.445 87.77 117.515 ;
      RECT 87.42 272.985 87.77 273.055 ;
      RECT 87.42 273.125 87.77 273.195 ;
      RECT 87.415 161.785 87.765 161.855 ;
      RECT 87.415 161.925 87.765 161.995 ;
      RECT 87.41 206.265 87.76 206.335 ;
      RECT 87.41 206.405 87.76 206.475 ;
      RECT 87.41 289.665 87.76 289.735 ;
      RECT 87.41 289.805 87.76 289.875 ;
      RECT 87.405 106.185 87.755 106.255 ;
      RECT 87.405 106.325 87.755 106.395 ;
      RECT 87.405 189.585 87.755 189.655 ;
      RECT 87.405 189.725 87.755 189.795 ;
      RECT 87.4 122.865 87.75 122.935 ;
      RECT 87.4 123.005 87.75 123.075 ;
      RECT 87.4 150.665 87.75 150.735 ;
      RECT 87.4 150.805 87.75 150.875 ;
      RECT 87.395 11.665 87.745 11.735 ;
      RECT 87.395 11.805 87.745 11.875 ;
      RECT 87.395 167.345 87.745 167.415 ;
      RECT 87.395 167.485 87.745 167.555 ;
      RECT 87.395 195.145 87.745 195.215 ;
      RECT 87.395 195.285 87.745 195.355 ;
      RECT 87.39 56.145 87.74 56.215 ;
      RECT 87.39 56.285 87.74 56.355 ;
      RECT 87.39 239.625 87.74 239.695 ;
      RECT 87.39 239.765 87.74 239.835 ;
      RECT 87.385 100.625 87.735 100.695 ;
      RECT 87.385 100.765 87.735 100.835 ;
      RECT 87.385 184.025 87.735 184.095 ;
      RECT 87.385 184.165 87.735 184.235 ;
      RECT 87.385 245.185 87.735 245.255 ;
      RECT 87.385 245.325 87.735 245.395 ;
      RECT 87.38 228.505 87.73 228.575 ;
      RECT 87.38 228.645 87.73 228.715 ;
      RECT 87.375 45.025 87.725 45.095 ;
      RECT 87.375 45.165 87.725 45.235 ;
      RECT 87.375 145.105 87.725 145.175 ;
      RECT 87.375 145.245 87.725 145.315 ;
      RECT 87.37 89.505 87.72 89.575 ;
      RECT 87.37 89.645 87.72 89.715 ;
      RECT 87.37 172.905 87.72 172.975 ;
      RECT 87.37 173.045 87.72 173.115 ;
      RECT 87.365 33.905 87.715 33.975 ;
      RECT 87.365 34.045 87.715 34.115 ;
      RECT 87.365 95.065 87.715 95.135 ;
      RECT 87.365 95.205 87.715 95.275 ;
      RECT 87.365 133.985 87.715 134.055 ;
      RECT 87.365 134.125 87.715 134.195 ;
      RECT 87.365 217.385 87.715 217.455 ;
      RECT 87.365 217.525 87.715 217.595 ;
      RECT 87.36 261.865 87.71 261.935 ;
      RECT 87.36 262.005 87.71 262.075 ;
      RECT 87.355 28.345 87.705 28.415 ;
      RECT 87.355 28.485 87.705 28.555 ;
      RECT 87.35 6.105 87.7 6.175 ;
      RECT 87.35 6.245 87.7 6.315 ;
      RECT 87.35 22.785 87.7 22.855 ;
      RECT 87.35 22.925 87.7 22.995 ;
      RECT 87.35 39.465 87.7 39.535 ;
      RECT 87.35 39.605 87.7 39.675 ;
      RECT 87.35 250.745 87.7 250.815 ;
      RECT 87.35 250.885 87.7 250.955 ;
      RECT 87.345 67.265 87.695 67.335 ;
      RECT 87.345 67.405 87.695 67.475 ;
      RECT 87.34 111.745 87.69 111.815 ;
      RECT 87.34 111.885 87.69 111.955 ;
      RECT 87.34 178.465 87.69 178.535 ;
      RECT 87.34 178.605 87.69 178.675 ;
      RECT 87.34 211.825 87.69 211.895 ;
      RECT 87.34 211.965 87.69 212.035 ;
      RECT 87.335 156.225 87.685 156.295 ;
      RECT 87.335 156.365 87.685 156.435 ;
      RECT 87.33 284.105 87.68 284.175 ;
      RECT 87.33 284.245 87.68 284.315 ;
      RECT 87.32 61.705 87.67 61.775 ;
      RECT 87.32 61.845 87.67 61.915 ;
      RECT 87.32 78.385 87.67 78.455 ;
      RECT 87.32 78.525 87.67 78.595 ;
      RECT 87.285 234.07 87.635 234.14 ;
      RECT 87.285 234.21 87.635 234.28 ;
      RECT 87.285 278.6 87.635 278.67 ;
      RECT 87.28 295.24 87.63 295.31 ;
      RECT 87.25 128.425 87.6 128.495 ;
      RECT 87.25 128.565 87.6 128.635 ;
      RECT 87.21 0.605 87.56 0.675 ;
      RECT 87.17 256.305 87.52 256.375 ;
      RECT 87.17 256.445 87.52 256.515 ;
      RECT 87.165 50.585 87.515 50.655 ;
      RECT 87.165 50.725 87.515 50.795 ;
      RECT 87.16 200.705 87.51 200.775 ;
      RECT 87.16 200.845 87.51 200.915 ;
      RECT 87.04 17.265 87.39 17.335 ;
      RECT 86.995 72.96 87.345 73.03 ;
      RECT 86.995 84.06 87.345 84.13 ;
      RECT 86.995 139.665 87.345 139.735 ;
      RECT 86.995 223 87.345 223.07 ;
      RECT 86.995 267.53 87.345 267.6 ;
      RECT 86.97 117.305 87.32 117.375 ;
      RECT 86.97 117.445 87.32 117.515 ;
      RECT 86.97 272.985 87.32 273.055 ;
      RECT 86.97 273.125 87.32 273.195 ;
      RECT 86.965 161.785 87.315 161.855 ;
      RECT 86.965 161.925 87.315 161.995 ;
      RECT 86.96 206.265 87.31 206.335 ;
      RECT 86.96 206.405 87.31 206.475 ;
      RECT 86.96 289.665 87.31 289.735 ;
      RECT 86.96 289.805 87.31 289.875 ;
      RECT 86.955 106.185 87.305 106.255 ;
      RECT 86.955 106.325 87.305 106.395 ;
      RECT 86.955 189.585 87.305 189.655 ;
      RECT 86.955 189.725 87.305 189.795 ;
      RECT 86.95 122.865 87.3 122.935 ;
      RECT 86.95 123.005 87.3 123.075 ;
      RECT 86.95 150.665 87.3 150.735 ;
      RECT 86.95 150.805 87.3 150.875 ;
      RECT 86.945 11.665 87.295 11.735 ;
      RECT 86.945 11.805 87.295 11.875 ;
      RECT 86.945 167.345 87.295 167.415 ;
      RECT 86.945 167.485 87.295 167.555 ;
      RECT 86.945 195.145 87.295 195.215 ;
      RECT 86.945 195.285 87.295 195.355 ;
      RECT 86.94 56.145 87.29 56.215 ;
      RECT 86.94 56.285 87.29 56.355 ;
      RECT 86.94 239.625 87.29 239.695 ;
      RECT 86.94 239.765 87.29 239.835 ;
      RECT 86.935 100.625 87.285 100.695 ;
      RECT 86.935 100.765 87.285 100.835 ;
      RECT 86.935 184.025 87.285 184.095 ;
      RECT 86.935 184.165 87.285 184.235 ;
      RECT 86.935 245.185 87.285 245.255 ;
      RECT 86.935 245.325 87.285 245.395 ;
      RECT 86.93 228.505 87.28 228.575 ;
      RECT 86.93 228.645 87.28 228.715 ;
      RECT 86.925 45.025 87.275 45.095 ;
      RECT 86.925 45.165 87.275 45.235 ;
      RECT 86.925 145.105 87.275 145.175 ;
      RECT 86.925 145.245 87.275 145.315 ;
      RECT 86.92 89.505 87.27 89.575 ;
      RECT 86.92 89.645 87.27 89.715 ;
      RECT 86.92 172.905 87.27 172.975 ;
      RECT 86.92 173.045 87.27 173.115 ;
      RECT 86.915 33.905 87.265 33.975 ;
      RECT 86.915 34.045 87.265 34.115 ;
      RECT 86.915 95.065 87.265 95.135 ;
      RECT 86.915 95.205 87.265 95.275 ;
      RECT 86.915 133.985 87.265 134.055 ;
      RECT 86.915 134.125 87.265 134.195 ;
      RECT 86.915 217.385 87.265 217.455 ;
      RECT 86.915 217.525 87.265 217.595 ;
      RECT 86.91 261.865 87.26 261.935 ;
      RECT 86.91 262.005 87.26 262.075 ;
      RECT 86.905 28.345 87.255 28.415 ;
      RECT 86.905 28.485 87.255 28.555 ;
      RECT 86.9 6.105 87.25 6.175 ;
      RECT 86.9 22.785 87.25 22.855 ;
      RECT 86.9 39.465 87.25 39.535 ;
      RECT 86.9 39.605 87.25 39.675 ;
      RECT 86.9 250.745 87.25 250.815 ;
      RECT 86.9 250.885 87.25 250.955 ;
      RECT 86.895 67.265 87.245 67.335 ;
      RECT 86.895 67.405 87.245 67.475 ;
      RECT 86.89 111.745 87.24 111.815 ;
      RECT 86.89 111.885 87.24 111.955 ;
      RECT 86.89 178.465 87.24 178.535 ;
      RECT 86.89 178.605 87.24 178.675 ;
      RECT 86.89 211.825 87.24 211.895 ;
      RECT 86.89 211.965 87.24 212.035 ;
      RECT 86.885 156.225 87.235 156.295 ;
      RECT 86.885 156.365 87.235 156.435 ;
      RECT 86.88 284.105 87.23 284.175 ;
      RECT 86.88 284.245 87.23 284.315 ;
      RECT 86.87 61.845 87.22 61.915 ;
      RECT 86.87 78.525 87.22 78.595 ;
      RECT 86.835 234.07 87.185 234.14 ;
      RECT 86.835 234.21 87.185 234.28 ;
      RECT 86.83 295.24 87.18 295.31 ;
      RECT 86.8 128.565 87.15 128.635 ;
      RECT 86.76 0.605 87.11 0.675 ;
      RECT 86.72 256.445 87.07 256.515 ;
      RECT 86.715 50.725 87.065 50.795 ;
      RECT 86.71 200.845 87.06 200.915 ;
    LAYER M5 SPACING 0.05 ;
      RECT 0 295.395 92.2 296 ;
      RECT 91.07 295.315 92.2 296 ;
      RECT 0 148.355 87.4 296 ;
      RECT 91.07 295.24 91.23 296 ;
      RECT 90.88 295.24 91.23 295.31 ;
      RECT 0 295.24 87.63 295.31 ;
      RECT 0 290.235 90.56 294.885 ;
      RECT 0 290.315 92.2 294.805 ;
      RECT 0 289.805 87.76 289.875 ;
      RECT 0 289.665 87.76 289.735 ;
      RECT 91.47 284.715 92.2 289.405 ;
      RECT 0 284.715 92.2 289.325 ;
      RECT 0 284.675 90.56 289.325 ;
      RECT 0 284.245 87.68 284.315 ;
      RECT 0 284.105 87.68 284.175 ;
      RECT 91.47 279.115 92.2 283.805 ;
      RECT 0 279.115 92.2 283.765 ;
      RECT 0 278.6 87.635 278.67 ;
      RECT 0 273.555 92.2 278.205 ;
      RECT 91.47 273.515 92.2 278.205 ;
      RECT 0 273.125 87.77 273.195 ;
      RECT 0 272.985 87.77 273.055 ;
      RECT 0 267.995 90.56 272.645 ;
      RECT 0 267.995 92.2 272.605 ;
      RECT 91.47 267.915 92.2 272.605 ;
      RECT 0 267.53 87.795 267.6 ;
      RECT 0 262.435 90.56 267.085 ;
      RECT 0 262.515 92.2 267.005 ;
      RECT 0 262.005 87.71 262.075 ;
      RECT 0 261.865 87.71 261.935 ;
      RECT 91.47 256.915 92.2 261.605 ;
      RECT 0 256.915 92.2 261.525 ;
      RECT 0 256.875 90.56 261.525 ;
      RECT 0 256.445 87.52 256.515 ;
      RECT 0 256.305 87.52 256.375 ;
      RECT 91.47 251.315 92.2 256.005 ;
      RECT 0 251.315 92.2 255.965 ;
      RECT 0 250.885 87.7 250.955 ;
      RECT 0 250.745 87.7 250.815 ;
      RECT 0 245.755 92.2 250.405 ;
      RECT 91.47 245.715 92.2 250.405 ;
      RECT 0 245.325 87.735 245.395 ;
      RECT 0 245.185 87.735 245.255 ;
      RECT 0 240.195 90.56 244.845 ;
      RECT 0 240.195 92.2 244.805 ;
      RECT 91.47 240.115 92.2 244.805 ;
      RECT 0 239.765 87.74 239.835 ;
      RECT 0 239.625 87.74 239.695 ;
      RECT 0 234.635 90.56 239.285 ;
      RECT 0 234.715 92.2 239.205 ;
      RECT 0 234.21 87.635 234.28 ;
      RECT 0 234.07 87.635 234.14 ;
      RECT 91.47 229.115 92.2 233.805 ;
      RECT 0 229.115 92.2 233.725 ;
      RECT 0 229.075 90.56 233.725 ;
      RECT 0 228.645 87.73 228.715 ;
      RECT 0 228.505 87.73 228.575 ;
      RECT 91.47 223.515 92.2 228.205 ;
      RECT 0 223.515 92.2 228.165 ;
      RECT 0 223 87.795 223.07 ;
      RECT 0 217.955 92.2 222.605 ;
      RECT 91.47 217.915 92.2 222.605 ;
      RECT 0 217.525 87.715 217.595 ;
      RECT 0 217.385 87.715 217.455 ;
      RECT 0 212.395 90.56 217.045 ;
      RECT 0 212.395 92.2 217.005 ;
      RECT 91.47 212.315 92.2 217.005 ;
      RECT 0 211.965 87.69 212.035 ;
      RECT 0 211.825 87.69 211.895 ;
      RECT 0 206.835 90.56 211.485 ;
      RECT 0 206.915 92.2 211.405 ;
      RECT 0 206.405 87.76 206.475 ;
      RECT 0 206.265 87.76 206.335 ;
      RECT 91.47 201.315 92.2 206.005 ;
      RECT 0 201.315 92.2 205.925 ;
      RECT 0 201.275 90.56 205.925 ;
      RECT 0 200.845 87.51 200.915 ;
      RECT 0 200.705 87.51 200.775 ;
      RECT 91.47 195.715 92.2 200.405 ;
      RECT 0 195.715 92.2 200.365 ;
      RECT 0 195.285 87.745 195.355 ;
      RECT 0 195.145 87.745 195.215 ;
      RECT 0 190.155 92.2 194.805 ;
      RECT 91.47 190.115 92.2 194.805 ;
      RECT 0 189.725 87.755 189.795 ;
      RECT 0 189.585 87.755 189.655 ;
      RECT 0 184.595 90.56 189.245 ;
      RECT 0 184.595 92.2 189.205 ;
      RECT 91.47 184.515 92.2 189.205 ;
      RECT 0 184.165 87.735 184.235 ;
      RECT 0 184.025 87.735 184.095 ;
      RECT 0 179.035 90.56 183.685 ;
      RECT 0 179.115 92.2 183.605 ;
      RECT 0 178.605 87.69 178.675 ;
      RECT 0 178.465 87.69 178.535 ;
      RECT 91.47 173.515 92.2 178.205 ;
      RECT 0 173.515 92.2 178.125 ;
      RECT 0 173.475 90.56 178.125 ;
      RECT 0 173.045 87.72 173.115 ;
      RECT 0 172.905 87.72 172.975 ;
      RECT 91.47 167.915 92.2 172.605 ;
      RECT 0 167.915 92.2 172.565 ;
      RECT 0 167.485 87.745 167.555 ;
      RECT 0 167.345 87.745 167.415 ;
      RECT 0 162.355 92.2 167.005 ;
      RECT 91.47 162.315 92.2 167.005 ;
      RECT 0 161.925 87.765 161.995 ;
      RECT 0 161.785 87.765 161.855 ;
      RECT 0 156.795 90.56 161.445 ;
      RECT 0 156.795 92.2 161.405 ;
      RECT 91.47 156.715 92.2 161.405 ;
      RECT 0 156.365 87.685 156.435 ;
      RECT 0 156.225 87.685 156.295 ;
      RECT 0 151.235 90.56 155.885 ;
      RECT 0 151.315 92.2 155.805 ;
      RECT 0 150.805 87.75 150.875 ;
      RECT 0 150.665 87.75 150.735 ;
      RECT 91.47 148.355 92.2 150.405 ;
      RECT 0 148.355 92.2 150.325 ;
      RECT 0 0 87.38 296 ;
      RECT 0 145.715 92.2 147.645 ;
      RECT 0 145.675 90.56 147.645 ;
      RECT 0 0 87.4 147.645 ;
      RECT 0 145.245 87.725 145.315 ;
      RECT 0 145.105 87.725 145.175 ;
      RECT 91.47 140.115 92.2 144.805 ;
      RECT 0 140.115 92.2 144.765 ;
      RECT 0 139.665 87.795 139.735 ;
      RECT 0 134.555 92.2 139.205 ;
      RECT 91.47 134.515 92.2 139.205 ;
      RECT 0 134.125 87.715 134.195 ;
      RECT 0 133.985 87.715 134.055 ;
      RECT 0 128.995 90.56 133.645 ;
      RECT 0 128.995 92.2 133.605 ;
      RECT 91.47 128.915 92.2 133.605 ;
      RECT 0 128.565 87.6 128.635 ;
      RECT 0 128.425 87.6 128.495 ;
      RECT 0 123.435 90.56 128.085 ;
      RECT 0 123.515 92.2 128.005 ;
      RECT 0 123.005 87.75 123.075 ;
      RECT 0 122.865 87.75 122.935 ;
      RECT 91.47 117.915 92.2 122.605 ;
      RECT 0 117.915 92.2 122.525 ;
      RECT 0 117.875 90.56 122.525 ;
      RECT 0 117.445 87.77 117.515 ;
      RECT 0 117.305 87.77 117.375 ;
      RECT 91.47 112.315 92.2 117.005 ;
      RECT 0 112.315 92.2 116.965 ;
      RECT 0 111.885 87.69 111.955 ;
      RECT 0 111.745 87.69 111.815 ;
      RECT 0 106.755 92.2 111.405 ;
      RECT 91.47 106.715 92.2 111.405 ;
      RECT 0 106.325 87.755 106.395 ;
      RECT 0 106.185 87.755 106.255 ;
      RECT 0 101.195 90.56 105.845 ;
      RECT 0 101.195 92.2 105.805 ;
      RECT 91.47 101.115 92.2 105.805 ;
      RECT 0 100.765 87.735 100.835 ;
      RECT 0 100.625 87.735 100.695 ;
      RECT 0 95.635 90.56 100.285 ;
      RECT 0 95.715 92.2 100.205 ;
      RECT 0 95.205 87.715 95.275 ;
      RECT 0 95.065 87.715 95.135 ;
      RECT 91.47 90.115 92.2 94.805 ;
      RECT 0 90.115 92.2 94.725 ;
      RECT 0 90.075 90.56 94.725 ;
      RECT 0 89.645 87.72 89.715 ;
      RECT 0 89.505 87.72 89.575 ;
      RECT 91.47 84.515 92.2 89.205 ;
      RECT 0 84.515 92.2 89.165 ;
      RECT 0 84.06 87.795 84.13 ;
      RECT 0 78.955 92.2 83.605 ;
      RECT 91.47 78.915 92.2 83.605 ;
      RECT 0 78.525 87.67 78.595 ;
      RECT 0 78.385 87.67 78.455 ;
      RECT 0 73.395 90.56 78.045 ;
      RECT 0 73.395 92.2 78.005 ;
      RECT 91.47 73.315 92.2 78.005 ;
      RECT 0 72.96 87.795 73.03 ;
      RECT 0 67.835 90.56 72.485 ;
      RECT 0 67.915 92.2 72.405 ;
      RECT 0 67.405 87.695 67.475 ;
      RECT 0 67.265 87.695 67.335 ;
      RECT 91.47 62.315 92.2 67.005 ;
      RECT 0 62.315 92.2 66.925 ;
      RECT 0 62.275 90.56 66.925 ;
      RECT 0 61.845 87.67 61.915 ;
      RECT 0 61.705 87.67 61.775 ;
      RECT 91.47 56.715 92.2 61.405 ;
      RECT 0 56.715 92.2 61.365 ;
      RECT 0 56.285 87.74 56.355 ;
      RECT 0 56.145 87.74 56.215 ;
      RECT 0 51.155 92.2 55.805 ;
      RECT 91.47 51.115 92.2 55.805 ;
      RECT 0 50.725 87.515 50.795 ;
      RECT 0 50.585 87.515 50.655 ;
      RECT 0 45.595 90.56 50.245 ;
      RECT 0 45.595 92.2 50.205 ;
      RECT 91.47 45.515 92.2 50.205 ;
      RECT 0 45.165 87.725 45.235 ;
      RECT 0 45.025 87.725 45.095 ;
      RECT 0 40.035 90.56 44.685 ;
      RECT 0 40.115 92.2 44.605 ;
      RECT 0 39.605 87.7 39.675 ;
      RECT 0 39.465 87.7 39.535 ;
      RECT 91.47 34.515 92.2 39.205 ;
      RECT 0 34.515 92.2 39.125 ;
      RECT 0 34.475 90.56 39.125 ;
      RECT 0 34.045 87.715 34.115 ;
      RECT 0 33.905 87.715 33.975 ;
      RECT 91.47 28.915 92.2 33.605 ;
      RECT 0 28.915 92.2 33.565 ;
      RECT 0 28.485 87.705 28.555 ;
      RECT 0 28.345 87.705 28.415 ;
      RECT 0 23.355 92.2 28.005 ;
      RECT 91.47 23.315 92.2 28.005 ;
      RECT 0 22.925 87.7 22.995 ;
      RECT 0 22.785 87.7 22.855 ;
      RECT 0 17.795 90.56 22.445 ;
      RECT 0 17.795 92.2 22.405 ;
      RECT 91.605 17.715 92.2 22.405 ;
      RECT 0 12.235 90.695 16.885 ;
      RECT 0 12.315 92.2 16.805 ;
      RECT 0 11.805 87.745 11.875 ;
      RECT 0 11.665 87.745 11.735 ;
      RECT 91.605 6.715 92.2 11.405 ;
      RECT 0 6.715 92.2 11.325 ;
      RECT 0 6.675 90.695 11.325 ;
      RECT 0 6.245 87.7 6.315 ;
      RECT 0 6.105 87.7 6.175 ;
      RECT 91.605 1.115 92.2 5.805 ;
      RECT 0 1.115 92.2 5.765 ;
      RECT 90.81 0 91.16 0.675 ;
      RECT 90.36 0 90.71 0.675 ;
      RECT 89.91 0 90.26 0.675 ;
      RECT 89.46 0 89.81 0.675 ;
      RECT 89.01 0 89.36 0.675 ;
      RECT 88.56 0 88.91 0.675 ;
      RECT 88.11 0 88.46 0.675 ;
      RECT 87.66 0 88.01 0.675 ;
      RECT 0 0 87.56 0.675 ;
      RECT 0 0 92.2 0.605 ;
      RECT 91.22 256.305 91.57 256.375 ;
      RECT 91.22 256.445 91.57 256.515 ;
      RECT 91.215 50.585 91.565 50.655 ;
      RECT 91.215 50.725 91.565 50.795 ;
      RECT 91.21 200.705 91.56 200.775 ;
      RECT 91.21 200.845 91.56 200.915 ;
      RECT 91.09 17.265 91.44 17.335 ;
      RECT 91.045 72.96 91.395 73.03 ;
      RECT 91.045 84.06 91.395 84.13 ;
      RECT 91.045 139.665 91.395 139.735 ;
      RECT 91.045 223 91.395 223.07 ;
      RECT 91.045 267.53 91.395 267.6 ;
      RECT 91.02 117.305 91.37 117.375 ;
      RECT 91.02 117.445 91.37 117.515 ;
      RECT 91.02 272.985 91.37 273.055 ;
      RECT 91.02 273.125 91.37 273.195 ;
      RECT 91.015 161.785 91.365 161.855 ;
      RECT 91.015 161.925 91.365 161.995 ;
      RECT 91.01 206.265 91.36 206.335 ;
      RECT 91.01 206.405 91.36 206.475 ;
      RECT 91.01 289.665 91.36 289.735 ;
      RECT 91.01 289.805 91.36 289.875 ;
      RECT 91.005 106.185 91.355 106.255 ;
      RECT 91.005 106.325 91.355 106.395 ;
      RECT 91.005 189.585 91.355 189.655 ;
      RECT 91.005 189.725 91.355 189.795 ;
      RECT 91 122.865 91.35 122.935 ;
      RECT 91 123.005 91.35 123.075 ;
      RECT 91 150.665 91.35 150.735 ;
      RECT 91 150.805 91.35 150.875 ;
      RECT 90.995 11.665 91.345 11.735 ;
      RECT 90.995 11.805 91.345 11.875 ;
      RECT 90.995 167.345 91.345 167.415 ;
      RECT 90.995 167.485 91.345 167.555 ;
      RECT 90.995 195.145 91.345 195.215 ;
      RECT 90.995 195.285 91.345 195.355 ;
      RECT 90.99 56.145 91.34 56.215 ;
      RECT 90.99 56.285 91.34 56.355 ;
      RECT 90.99 239.625 91.34 239.695 ;
      RECT 90.99 239.765 91.34 239.835 ;
      RECT 90.985 100.625 91.335 100.695 ;
      RECT 90.985 100.765 91.335 100.835 ;
      RECT 90.985 184.025 91.335 184.095 ;
      RECT 90.985 184.165 91.335 184.235 ;
      RECT 90.985 245.185 91.335 245.255 ;
      RECT 90.985 245.325 91.335 245.395 ;
      RECT 90.98 228.505 91.33 228.575 ;
      RECT 90.98 228.645 91.33 228.715 ;
      RECT 90.975 45.025 91.325 45.095 ;
      RECT 90.975 45.165 91.325 45.235 ;
      RECT 90.975 145.105 91.325 145.175 ;
      RECT 90.975 145.245 91.325 145.315 ;
      RECT 90.97 89.505 91.32 89.575 ;
      RECT 90.97 89.645 91.32 89.715 ;
      RECT 90.97 172.905 91.32 172.975 ;
      RECT 90.97 173.045 91.32 173.115 ;
      RECT 90.965 33.905 91.315 33.975 ;
      RECT 90.965 34.045 91.315 34.115 ;
      RECT 90.965 95.065 91.315 95.135 ;
      RECT 90.965 95.205 91.315 95.275 ;
      RECT 90.965 133.985 91.315 134.055 ;
      RECT 90.965 134.125 91.315 134.195 ;
      RECT 90.965 217.385 91.315 217.455 ;
      RECT 90.965 217.525 91.315 217.595 ;
      RECT 90.96 261.865 91.31 261.935 ;
      RECT 90.96 262.005 91.31 262.075 ;
      RECT 90.955 28.345 91.305 28.415 ;
      RECT 90.955 28.485 91.305 28.555 ;
      RECT 90.95 6.105 91.3 6.175 ;
      RECT 90.95 6.245 91.3 6.315 ;
      RECT 90.95 22.785 91.3 22.855 ;
      RECT 90.95 22.925 91.3 22.995 ;
      RECT 90.95 39.465 91.3 39.535 ;
      RECT 90.95 39.605 91.3 39.675 ;
      RECT 90.95 250.745 91.3 250.815 ;
      RECT 90.95 250.885 91.3 250.955 ;
      RECT 90.945 67.265 91.295 67.335 ;
      RECT 90.945 67.405 91.295 67.475 ;
      RECT 90.94 111.745 91.29 111.815 ;
      RECT 90.94 111.885 91.29 111.955 ;
      RECT 90.94 178.465 91.29 178.535 ;
      RECT 90.94 178.605 91.29 178.675 ;
      RECT 90.94 211.825 91.29 211.895 ;
      RECT 90.94 211.965 91.29 212.035 ;
      RECT 90.935 156.225 91.285 156.295 ;
      RECT 90.935 156.365 91.285 156.435 ;
      RECT 90.93 284.105 91.28 284.175 ;
      RECT 90.93 284.245 91.28 284.315 ;
      RECT 90.92 61.705 91.27 61.775 ;
      RECT 90.92 61.845 91.27 61.915 ;
      RECT 90.92 78.385 91.27 78.455 ;
      RECT 90.92 78.525 91.27 78.595 ;
      RECT 90.885 234.07 91.235 234.14 ;
      RECT 90.885 234.21 91.235 234.28 ;
      RECT 90.885 278.6 91.235 278.67 ;
      RECT 90.85 128.425 91.2 128.495 ;
      RECT 90.85 128.565 91.2 128.635 ;
      RECT 90.77 256.305 91.12 256.375 ;
      RECT 90.77 256.445 91.12 256.515 ;
      RECT 90.765 50.585 91.115 50.655 ;
      RECT 90.765 50.725 91.115 50.795 ;
      RECT 90.76 200.705 91.11 200.775 ;
      RECT 90.76 200.845 91.11 200.915 ;
      RECT 90.64 17.265 90.99 17.335 ;
      RECT 90.595 72.96 90.945 73.03 ;
      RECT 90.595 84.06 90.945 84.13 ;
      RECT 90.595 139.665 90.945 139.735 ;
      RECT 90.595 223 90.945 223.07 ;
      RECT 90.595 267.53 90.945 267.6 ;
      RECT 90.57 117.305 90.92 117.375 ;
      RECT 90.57 117.445 90.92 117.515 ;
      RECT 90.57 272.985 90.92 273.055 ;
      RECT 90.57 273.125 90.92 273.195 ;
      RECT 90.565 161.785 90.915 161.855 ;
      RECT 90.565 161.925 90.915 161.995 ;
      RECT 90.56 206.265 90.91 206.335 ;
      RECT 90.56 206.405 90.91 206.475 ;
      RECT 90.56 289.665 90.91 289.735 ;
      RECT 90.56 289.805 90.91 289.875 ;
      RECT 90.555 106.185 90.905 106.255 ;
      RECT 90.555 106.325 90.905 106.395 ;
      RECT 90.555 189.585 90.905 189.655 ;
      RECT 90.555 189.725 90.905 189.795 ;
      RECT 90.55 122.865 90.9 122.935 ;
      RECT 90.55 123.005 90.9 123.075 ;
      RECT 90.55 150.665 90.9 150.735 ;
      RECT 90.55 150.805 90.9 150.875 ;
      RECT 90.545 11.665 90.895 11.735 ;
      RECT 90.545 11.805 90.895 11.875 ;
      RECT 90.545 167.345 90.895 167.415 ;
      RECT 90.545 167.485 90.895 167.555 ;
      RECT 90.545 195.145 90.895 195.215 ;
      RECT 90.545 195.285 90.895 195.355 ;
      RECT 90.54 56.145 90.89 56.215 ;
      RECT 90.54 56.285 90.89 56.355 ;
      RECT 90.54 239.625 90.89 239.695 ;
      RECT 90.54 239.765 90.89 239.835 ;
      RECT 90.535 100.625 90.885 100.695 ;
      RECT 90.535 100.765 90.885 100.835 ;
      RECT 90.535 184.025 90.885 184.095 ;
      RECT 90.535 184.165 90.885 184.235 ;
      RECT 90.535 245.185 90.885 245.255 ;
      RECT 90.535 245.325 90.885 245.395 ;
      RECT 90.53 228.505 90.88 228.575 ;
      RECT 90.53 228.645 90.88 228.715 ;
      RECT 90.525 45.025 90.875 45.095 ;
      RECT 90.525 45.165 90.875 45.235 ;
      RECT 90.525 145.105 90.875 145.175 ;
      RECT 90.525 145.245 90.875 145.315 ;
      RECT 90.52 89.505 90.87 89.575 ;
      RECT 90.52 89.645 90.87 89.715 ;
      RECT 90.52 172.905 90.87 172.975 ;
      RECT 90.52 173.045 90.87 173.115 ;
      RECT 90.515 33.905 90.865 33.975 ;
      RECT 90.515 34.045 90.865 34.115 ;
      RECT 90.515 95.065 90.865 95.135 ;
      RECT 90.515 95.205 90.865 95.275 ;
      RECT 90.515 133.985 90.865 134.055 ;
      RECT 90.515 134.125 90.865 134.195 ;
      RECT 90.515 217.385 90.865 217.455 ;
      RECT 90.515 217.525 90.865 217.595 ;
      RECT 90.51 261.865 90.86 261.935 ;
      RECT 90.51 262.005 90.86 262.075 ;
      RECT 90.505 28.345 90.855 28.415 ;
      RECT 90.505 28.485 90.855 28.555 ;
      RECT 90.5 6.105 90.85 6.175 ;
      RECT 90.5 6.245 90.85 6.315 ;
      RECT 90.5 22.785 90.85 22.855 ;
      RECT 90.5 22.925 90.85 22.995 ;
      RECT 90.5 39.465 90.85 39.535 ;
      RECT 90.5 39.605 90.85 39.675 ;
      RECT 90.5 250.745 90.85 250.815 ;
      RECT 90.5 250.885 90.85 250.955 ;
      RECT 90.495 67.265 90.845 67.335 ;
      RECT 90.495 67.405 90.845 67.475 ;
      RECT 90.49 111.745 90.84 111.815 ;
      RECT 90.49 111.885 90.84 111.955 ;
      RECT 90.49 178.465 90.84 178.535 ;
      RECT 90.49 178.605 90.84 178.675 ;
      RECT 90.49 211.825 90.84 211.895 ;
      RECT 90.49 211.965 90.84 212.035 ;
      RECT 90.485 156.225 90.835 156.295 ;
      RECT 90.485 156.365 90.835 156.435 ;
      RECT 90.48 284.105 90.83 284.175 ;
      RECT 90.48 284.245 90.83 284.315 ;
      RECT 90.47 61.705 90.82 61.775 ;
      RECT 90.47 61.845 90.82 61.915 ;
      RECT 90.47 78.385 90.82 78.455 ;
      RECT 90.47 78.525 90.82 78.595 ;
      RECT 90.435 234.07 90.785 234.14 ;
      RECT 90.435 234.21 90.785 234.28 ;
      RECT 90.435 278.6 90.785 278.67 ;
      RECT 90.43 295.24 90.78 295.31 ;
      RECT 90.4 128.425 90.75 128.495 ;
      RECT 90.4 128.565 90.75 128.635 ;
      RECT 90.32 256.305 90.67 256.375 ;
      RECT 90.32 256.445 90.67 256.515 ;
      RECT 90.315 50.585 90.665 50.655 ;
      RECT 90.315 50.725 90.665 50.795 ;
      RECT 90.31 200.705 90.66 200.775 ;
      RECT 90.31 200.845 90.66 200.915 ;
      RECT 90.19 17.265 90.54 17.335 ;
      RECT 90.145 72.96 90.495 73.03 ;
      RECT 90.145 84.06 90.495 84.13 ;
      RECT 90.145 139.665 90.495 139.735 ;
      RECT 90.145 223 90.495 223.07 ;
      RECT 90.145 267.53 90.495 267.6 ;
      RECT 90.12 117.305 90.47 117.375 ;
      RECT 90.12 117.445 90.47 117.515 ;
      RECT 90.12 272.985 90.47 273.055 ;
      RECT 90.12 273.125 90.47 273.195 ;
      RECT 90.115 161.785 90.465 161.855 ;
      RECT 90.115 161.925 90.465 161.995 ;
      RECT 90.11 206.265 90.46 206.335 ;
      RECT 90.11 206.405 90.46 206.475 ;
      RECT 90.11 289.665 90.46 289.735 ;
      RECT 90.11 289.805 90.46 289.875 ;
      RECT 90.105 106.185 90.455 106.255 ;
      RECT 90.105 106.325 90.455 106.395 ;
      RECT 90.105 189.585 90.455 189.655 ;
      RECT 90.105 189.725 90.455 189.795 ;
      RECT 90.1 122.865 90.45 122.935 ;
      RECT 90.1 123.005 90.45 123.075 ;
      RECT 90.1 150.665 90.45 150.735 ;
      RECT 90.1 150.805 90.45 150.875 ;
      RECT 90.095 11.665 90.445 11.735 ;
      RECT 90.095 11.805 90.445 11.875 ;
      RECT 90.095 167.345 90.445 167.415 ;
      RECT 90.095 167.485 90.445 167.555 ;
      RECT 90.095 195.145 90.445 195.215 ;
      RECT 90.095 195.285 90.445 195.355 ;
      RECT 90.09 56.145 90.44 56.215 ;
      RECT 90.09 56.285 90.44 56.355 ;
      RECT 90.09 239.625 90.44 239.695 ;
      RECT 90.09 239.765 90.44 239.835 ;
      RECT 90.085 100.625 90.435 100.695 ;
      RECT 90.085 100.765 90.435 100.835 ;
      RECT 90.085 184.025 90.435 184.095 ;
      RECT 90.085 184.165 90.435 184.235 ;
      RECT 90.085 245.185 90.435 245.255 ;
      RECT 90.085 245.325 90.435 245.395 ;
      RECT 90.08 228.505 90.43 228.575 ;
      RECT 90.08 228.645 90.43 228.715 ;
      RECT 90.075 45.025 90.425 45.095 ;
      RECT 90.075 45.165 90.425 45.235 ;
      RECT 90.075 145.105 90.425 145.175 ;
      RECT 90.075 145.245 90.425 145.315 ;
      RECT 90.07 89.505 90.42 89.575 ;
      RECT 90.07 89.645 90.42 89.715 ;
      RECT 90.07 172.905 90.42 172.975 ;
      RECT 90.07 173.045 90.42 173.115 ;
      RECT 90.065 33.905 90.415 33.975 ;
      RECT 90.065 34.045 90.415 34.115 ;
      RECT 90.065 95.065 90.415 95.135 ;
      RECT 90.065 95.205 90.415 95.275 ;
      RECT 90.065 133.985 90.415 134.055 ;
      RECT 90.065 134.125 90.415 134.195 ;
      RECT 90.065 217.385 90.415 217.455 ;
      RECT 90.065 217.525 90.415 217.595 ;
      RECT 90.06 261.865 90.41 261.935 ;
      RECT 90.06 262.005 90.41 262.075 ;
      RECT 90.055 28.345 90.405 28.415 ;
      RECT 90.055 28.485 90.405 28.555 ;
      RECT 90.05 6.105 90.4 6.175 ;
      RECT 90.05 6.245 90.4 6.315 ;
      RECT 90.05 22.785 90.4 22.855 ;
      RECT 90.05 22.925 90.4 22.995 ;
      RECT 90.05 39.465 90.4 39.535 ;
      RECT 90.05 39.605 90.4 39.675 ;
      RECT 90.05 250.745 90.4 250.815 ;
      RECT 90.05 250.885 90.4 250.955 ;
      RECT 90.045 67.265 90.395 67.335 ;
      RECT 90.045 67.405 90.395 67.475 ;
      RECT 90.04 111.745 90.39 111.815 ;
      RECT 90.04 111.885 90.39 111.955 ;
      RECT 90.04 178.465 90.39 178.535 ;
      RECT 90.04 178.605 90.39 178.675 ;
      RECT 90.04 211.825 90.39 211.895 ;
      RECT 90.04 211.965 90.39 212.035 ;
      RECT 90.035 156.225 90.385 156.295 ;
      RECT 90.035 156.365 90.385 156.435 ;
      RECT 90.03 284.105 90.38 284.175 ;
      RECT 90.03 284.245 90.38 284.315 ;
      RECT 90.02 61.705 90.37 61.775 ;
      RECT 90.02 61.845 90.37 61.915 ;
      RECT 90.02 78.385 90.37 78.455 ;
      RECT 90.02 78.525 90.37 78.595 ;
      RECT 89.985 234.07 90.335 234.14 ;
      RECT 89.985 234.21 90.335 234.28 ;
      RECT 89.985 278.6 90.335 278.67 ;
      RECT 89.98 295.24 90.33 295.31 ;
      RECT 89.95 128.425 90.3 128.495 ;
      RECT 89.95 128.565 90.3 128.635 ;
      RECT 89.87 256.305 90.22 256.375 ;
      RECT 89.87 256.445 90.22 256.515 ;
      RECT 89.865 50.585 90.215 50.655 ;
      RECT 89.865 50.725 90.215 50.795 ;
      RECT 89.86 200.705 90.21 200.775 ;
      RECT 89.86 200.845 90.21 200.915 ;
      RECT 89.74 17.265 90.09 17.335 ;
      RECT 89.695 72.96 90.045 73.03 ;
      RECT 89.695 84.06 90.045 84.13 ;
      RECT 89.695 139.665 90.045 139.735 ;
      RECT 89.695 223 90.045 223.07 ;
      RECT 89.695 267.53 90.045 267.6 ;
      RECT 89.67 117.305 90.02 117.375 ;
      RECT 89.67 117.445 90.02 117.515 ;
      RECT 89.67 272.985 90.02 273.055 ;
      RECT 89.67 273.125 90.02 273.195 ;
      RECT 89.665 161.785 90.015 161.855 ;
      RECT 89.665 161.925 90.015 161.995 ;
      RECT 89.66 206.265 90.01 206.335 ;
      RECT 89.66 206.405 90.01 206.475 ;
      RECT 89.66 289.665 90.01 289.735 ;
      RECT 89.66 289.805 90.01 289.875 ;
      RECT 89.655 106.185 90.005 106.255 ;
      RECT 89.655 106.325 90.005 106.395 ;
      RECT 89.655 189.585 90.005 189.655 ;
      RECT 89.655 189.725 90.005 189.795 ;
      RECT 89.65 122.865 90 122.935 ;
      RECT 89.65 123.005 90 123.075 ;
      RECT 89.65 150.665 90 150.735 ;
      RECT 89.65 150.805 90 150.875 ;
      RECT 89.645 11.665 89.995 11.735 ;
      RECT 89.645 11.805 89.995 11.875 ;
      RECT 89.645 167.345 89.995 167.415 ;
      RECT 89.645 167.485 89.995 167.555 ;
      RECT 89.645 195.145 89.995 195.215 ;
      RECT 89.645 195.285 89.995 195.355 ;
      RECT 89.64 56.145 89.99 56.215 ;
      RECT 89.64 56.285 89.99 56.355 ;
      RECT 89.64 239.625 89.99 239.695 ;
      RECT 89.64 239.765 89.99 239.835 ;
      RECT 89.635 100.625 89.985 100.695 ;
      RECT 89.635 100.765 89.985 100.835 ;
      RECT 89.635 184.025 89.985 184.095 ;
      RECT 89.635 184.165 89.985 184.235 ;
      RECT 89.635 245.185 89.985 245.255 ;
      RECT 89.635 245.325 89.985 245.395 ;
      RECT 89.63 228.505 89.98 228.575 ;
      RECT 89.63 228.645 89.98 228.715 ;
      RECT 89.625 45.025 89.975 45.095 ;
      RECT 89.625 45.165 89.975 45.235 ;
      RECT 89.625 145.105 89.975 145.175 ;
      RECT 89.625 145.245 89.975 145.315 ;
      RECT 89.62 89.505 89.97 89.575 ;
      RECT 89.62 89.645 89.97 89.715 ;
      RECT 89.62 172.905 89.97 172.975 ;
      RECT 89.62 173.045 89.97 173.115 ;
      RECT 89.615 33.905 89.965 33.975 ;
      RECT 89.615 34.045 89.965 34.115 ;
      RECT 89.615 95.065 89.965 95.135 ;
      RECT 89.615 95.205 89.965 95.275 ;
      RECT 89.615 133.985 89.965 134.055 ;
      RECT 89.615 134.125 89.965 134.195 ;
      RECT 89.615 217.385 89.965 217.455 ;
      RECT 89.615 217.525 89.965 217.595 ;
      RECT 89.61 261.865 89.96 261.935 ;
      RECT 89.61 262.005 89.96 262.075 ;
      RECT 89.605 28.345 89.955 28.415 ;
      RECT 89.605 28.485 89.955 28.555 ;
      RECT 89.6 6.105 89.95 6.175 ;
      RECT 89.6 6.245 89.95 6.315 ;
      RECT 89.6 22.785 89.95 22.855 ;
      RECT 89.6 22.925 89.95 22.995 ;
      RECT 89.6 39.465 89.95 39.535 ;
      RECT 89.6 39.605 89.95 39.675 ;
      RECT 89.6 250.745 89.95 250.815 ;
      RECT 89.6 250.885 89.95 250.955 ;
      RECT 89.595 67.265 89.945 67.335 ;
      RECT 89.595 67.405 89.945 67.475 ;
      RECT 89.59 111.745 89.94 111.815 ;
      RECT 89.59 111.885 89.94 111.955 ;
      RECT 89.59 178.465 89.94 178.535 ;
      RECT 89.59 178.605 89.94 178.675 ;
      RECT 89.59 211.825 89.94 211.895 ;
      RECT 89.59 211.965 89.94 212.035 ;
      RECT 89.585 156.225 89.935 156.295 ;
      RECT 89.585 156.365 89.935 156.435 ;
      RECT 89.58 284.105 89.93 284.175 ;
      RECT 89.58 284.245 89.93 284.315 ;
      RECT 89.57 61.705 89.92 61.775 ;
      RECT 89.57 61.845 89.92 61.915 ;
      RECT 89.57 78.385 89.92 78.455 ;
      RECT 89.57 78.525 89.92 78.595 ;
      RECT 89.535 234.07 89.885 234.14 ;
      RECT 89.535 234.21 89.885 234.28 ;
      RECT 89.535 278.6 89.885 278.67 ;
      RECT 89.53 295.24 89.88 295.31 ;
      RECT 89.5 128.425 89.85 128.495 ;
      RECT 89.5 128.565 89.85 128.635 ;
      RECT 89.42 256.305 89.77 256.375 ;
      RECT 89.42 256.445 89.77 256.515 ;
      RECT 89.415 50.585 89.765 50.655 ;
      RECT 89.415 50.725 89.765 50.795 ;
      RECT 89.41 200.705 89.76 200.775 ;
      RECT 89.41 200.845 89.76 200.915 ;
      RECT 89.29 17.265 89.64 17.335 ;
      RECT 89.245 72.96 89.595 73.03 ;
      RECT 89.245 84.06 89.595 84.13 ;
      RECT 89.245 139.665 89.595 139.735 ;
      RECT 89.245 223 89.595 223.07 ;
      RECT 89.245 267.53 89.595 267.6 ;
      RECT 89.22 117.305 89.57 117.375 ;
      RECT 89.22 117.445 89.57 117.515 ;
      RECT 89.22 272.985 89.57 273.055 ;
      RECT 89.22 273.125 89.57 273.195 ;
      RECT 89.215 161.785 89.565 161.855 ;
      RECT 89.215 161.925 89.565 161.995 ;
      RECT 89.21 206.265 89.56 206.335 ;
      RECT 89.21 206.405 89.56 206.475 ;
      RECT 89.21 289.665 89.56 289.735 ;
      RECT 89.21 289.805 89.56 289.875 ;
      RECT 89.205 106.185 89.555 106.255 ;
      RECT 89.205 106.325 89.555 106.395 ;
      RECT 89.205 189.585 89.555 189.655 ;
      RECT 89.205 189.725 89.555 189.795 ;
      RECT 89.2 122.865 89.55 122.935 ;
      RECT 89.2 123.005 89.55 123.075 ;
      RECT 89.2 150.665 89.55 150.735 ;
      RECT 89.2 150.805 89.55 150.875 ;
      RECT 89.195 11.665 89.545 11.735 ;
      RECT 89.195 11.805 89.545 11.875 ;
      RECT 89.195 167.345 89.545 167.415 ;
      RECT 89.195 167.485 89.545 167.555 ;
      RECT 89.195 195.145 89.545 195.215 ;
      RECT 89.195 195.285 89.545 195.355 ;
      RECT 89.19 56.145 89.54 56.215 ;
      RECT 89.19 56.285 89.54 56.355 ;
      RECT 89.19 239.625 89.54 239.695 ;
      RECT 89.19 239.765 89.54 239.835 ;
      RECT 89.185 100.625 89.535 100.695 ;
      RECT 89.185 100.765 89.535 100.835 ;
      RECT 89.185 184.025 89.535 184.095 ;
      RECT 89.185 184.165 89.535 184.235 ;
      RECT 89.185 245.185 89.535 245.255 ;
      RECT 89.185 245.325 89.535 245.395 ;
      RECT 89.18 228.505 89.53 228.575 ;
      RECT 89.18 228.645 89.53 228.715 ;
      RECT 89.175 45.025 89.525 45.095 ;
      RECT 89.175 45.165 89.525 45.235 ;
      RECT 89.175 145.105 89.525 145.175 ;
      RECT 89.175 145.245 89.525 145.315 ;
      RECT 89.17 89.505 89.52 89.575 ;
      RECT 89.17 89.645 89.52 89.715 ;
      RECT 89.17 172.905 89.52 172.975 ;
      RECT 89.17 173.045 89.52 173.115 ;
      RECT 89.165 33.905 89.515 33.975 ;
      RECT 89.165 34.045 89.515 34.115 ;
      RECT 89.165 95.065 89.515 95.135 ;
      RECT 89.165 95.205 89.515 95.275 ;
      RECT 89.165 133.985 89.515 134.055 ;
      RECT 89.165 134.125 89.515 134.195 ;
      RECT 89.165 217.385 89.515 217.455 ;
      RECT 89.165 217.525 89.515 217.595 ;
      RECT 89.16 261.865 89.51 261.935 ;
      RECT 89.16 262.005 89.51 262.075 ;
      RECT 89.155 28.345 89.505 28.415 ;
      RECT 89.155 28.485 89.505 28.555 ;
      RECT 89.15 6.105 89.5 6.175 ;
      RECT 89.15 6.245 89.5 6.315 ;
      RECT 89.15 22.785 89.5 22.855 ;
      RECT 89.15 22.925 89.5 22.995 ;
      RECT 89.15 39.465 89.5 39.535 ;
      RECT 89.15 39.605 89.5 39.675 ;
      RECT 89.15 250.745 89.5 250.815 ;
      RECT 89.15 250.885 89.5 250.955 ;
      RECT 89.145 67.265 89.495 67.335 ;
      RECT 89.145 67.405 89.495 67.475 ;
      RECT 89.14 111.745 89.49 111.815 ;
      RECT 89.14 111.885 89.49 111.955 ;
      RECT 89.14 178.465 89.49 178.535 ;
      RECT 89.14 178.605 89.49 178.675 ;
      RECT 89.14 211.825 89.49 211.895 ;
      RECT 89.14 211.965 89.49 212.035 ;
      RECT 89.135 156.225 89.485 156.295 ;
      RECT 89.135 156.365 89.485 156.435 ;
      RECT 89.13 284.105 89.48 284.175 ;
      RECT 89.13 284.245 89.48 284.315 ;
      RECT 89.12 61.705 89.47 61.775 ;
      RECT 89.12 61.845 89.47 61.915 ;
      RECT 89.12 78.385 89.47 78.455 ;
      RECT 89.12 78.525 89.47 78.595 ;
      RECT 89.085 234.07 89.435 234.14 ;
      RECT 89.085 234.21 89.435 234.28 ;
      RECT 89.085 278.6 89.435 278.67 ;
      RECT 89.08 295.24 89.43 295.31 ;
      RECT 89.05 128.425 89.4 128.495 ;
      RECT 89.05 128.565 89.4 128.635 ;
      RECT 88.97 256.305 89.32 256.375 ;
      RECT 88.97 256.445 89.32 256.515 ;
      RECT 88.965 50.585 89.315 50.655 ;
      RECT 88.965 50.725 89.315 50.795 ;
      RECT 88.96 200.705 89.31 200.775 ;
      RECT 88.96 200.845 89.31 200.915 ;
      RECT 88.84 17.265 89.19 17.335 ;
      RECT 88.795 72.96 89.145 73.03 ;
      RECT 88.795 84.06 89.145 84.13 ;
      RECT 88.795 139.665 89.145 139.735 ;
      RECT 88.795 223 89.145 223.07 ;
      RECT 88.795 267.53 89.145 267.6 ;
      RECT 88.77 117.305 89.12 117.375 ;
      RECT 88.77 117.445 89.12 117.515 ;
      RECT 88.77 272.985 89.12 273.055 ;
      RECT 88.77 273.125 89.12 273.195 ;
      RECT 88.765 161.785 89.115 161.855 ;
      RECT 88.765 161.925 89.115 161.995 ;
      RECT 88.76 206.265 89.11 206.335 ;
      RECT 88.76 206.405 89.11 206.475 ;
      RECT 88.76 289.665 89.11 289.735 ;
      RECT 88.76 289.805 89.11 289.875 ;
      RECT 88.755 106.185 89.105 106.255 ;
      RECT 88.755 106.325 89.105 106.395 ;
      RECT 88.755 189.585 89.105 189.655 ;
      RECT 88.755 189.725 89.105 189.795 ;
      RECT 88.75 122.865 89.1 122.935 ;
      RECT 88.75 123.005 89.1 123.075 ;
      RECT 88.75 150.665 89.1 150.735 ;
      RECT 88.75 150.805 89.1 150.875 ;
      RECT 88.745 11.665 89.095 11.735 ;
      RECT 88.745 11.805 89.095 11.875 ;
      RECT 88.745 167.345 89.095 167.415 ;
      RECT 88.745 167.485 89.095 167.555 ;
      RECT 88.745 195.145 89.095 195.215 ;
      RECT 88.745 195.285 89.095 195.355 ;
      RECT 88.74 56.145 89.09 56.215 ;
      RECT 88.74 56.285 89.09 56.355 ;
      RECT 88.74 239.625 89.09 239.695 ;
      RECT 88.74 239.765 89.09 239.835 ;
      RECT 88.735 100.625 89.085 100.695 ;
      RECT 88.735 100.765 89.085 100.835 ;
      RECT 88.735 184.025 89.085 184.095 ;
      RECT 88.735 184.165 89.085 184.235 ;
      RECT 88.735 245.185 89.085 245.255 ;
      RECT 88.735 245.325 89.085 245.395 ;
      RECT 88.73 228.505 89.08 228.575 ;
      RECT 88.73 228.645 89.08 228.715 ;
      RECT 88.725 45.025 89.075 45.095 ;
      RECT 88.725 45.165 89.075 45.235 ;
      RECT 88.725 145.105 89.075 145.175 ;
      RECT 88.725 145.245 89.075 145.315 ;
      RECT 88.72 89.505 89.07 89.575 ;
      RECT 88.72 89.645 89.07 89.715 ;
      RECT 88.72 172.905 89.07 172.975 ;
      RECT 88.72 173.045 89.07 173.115 ;
      RECT 88.715 33.905 89.065 33.975 ;
      RECT 88.715 34.045 89.065 34.115 ;
      RECT 88.715 95.065 89.065 95.135 ;
      RECT 88.715 95.205 89.065 95.275 ;
      RECT 88.715 133.985 89.065 134.055 ;
      RECT 88.715 134.125 89.065 134.195 ;
      RECT 88.715 217.385 89.065 217.455 ;
      RECT 88.715 217.525 89.065 217.595 ;
      RECT 88.71 261.865 89.06 261.935 ;
      RECT 88.71 262.005 89.06 262.075 ;
      RECT 88.705 28.345 89.055 28.415 ;
      RECT 88.705 28.485 89.055 28.555 ;
      RECT 88.7 6.105 89.05 6.175 ;
      RECT 88.7 6.245 89.05 6.315 ;
      RECT 88.7 22.785 89.05 22.855 ;
      RECT 88.7 22.925 89.05 22.995 ;
      RECT 88.7 39.465 89.05 39.535 ;
      RECT 88.7 39.605 89.05 39.675 ;
      RECT 88.7 250.745 89.05 250.815 ;
      RECT 88.7 250.885 89.05 250.955 ;
      RECT 88.695 67.265 89.045 67.335 ;
      RECT 88.695 67.405 89.045 67.475 ;
      RECT 88.69 111.745 89.04 111.815 ;
      RECT 88.69 111.885 89.04 111.955 ;
      RECT 88.69 178.465 89.04 178.535 ;
      RECT 88.69 178.605 89.04 178.675 ;
      RECT 88.69 211.825 89.04 211.895 ;
      RECT 88.69 211.965 89.04 212.035 ;
      RECT 88.685 156.225 89.035 156.295 ;
      RECT 88.685 156.365 89.035 156.435 ;
      RECT 88.68 284.105 89.03 284.175 ;
      RECT 88.68 284.245 89.03 284.315 ;
      RECT 88.67 61.705 89.02 61.775 ;
      RECT 88.67 61.845 89.02 61.915 ;
      RECT 88.67 78.385 89.02 78.455 ;
      RECT 88.67 78.525 89.02 78.595 ;
      RECT 88.635 234.07 88.985 234.14 ;
      RECT 88.635 234.21 88.985 234.28 ;
      RECT 88.635 278.6 88.985 278.67 ;
      RECT 88.63 295.24 88.98 295.31 ;
      RECT 88.6 128.425 88.95 128.495 ;
      RECT 88.6 128.565 88.95 128.635 ;
      RECT 88.52 256.305 88.87 256.375 ;
      RECT 88.52 256.445 88.87 256.515 ;
      RECT 88.515 50.585 88.865 50.655 ;
      RECT 88.515 50.725 88.865 50.795 ;
      RECT 88.51 200.705 88.86 200.775 ;
      RECT 88.51 200.845 88.86 200.915 ;
      RECT 88.39 17.265 88.74 17.335 ;
      RECT 88.345 72.96 88.695 73.03 ;
      RECT 88.345 84.06 88.695 84.13 ;
      RECT 88.345 139.665 88.695 139.735 ;
      RECT 88.345 223 88.695 223.07 ;
      RECT 88.345 267.53 88.695 267.6 ;
      RECT 88.32 117.305 88.67 117.375 ;
      RECT 88.32 117.445 88.67 117.515 ;
      RECT 88.32 272.985 88.67 273.055 ;
      RECT 88.32 273.125 88.67 273.195 ;
      RECT 88.315 161.785 88.665 161.855 ;
      RECT 88.315 161.925 88.665 161.995 ;
      RECT 88.31 206.265 88.66 206.335 ;
      RECT 88.31 206.405 88.66 206.475 ;
      RECT 88.31 289.665 88.66 289.735 ;
      RECT 88.31 289.805 88.66 289.875 ;
      RECT 88.305 106.185 88.655 106.255 ;
      RECT 88.305 106.325 88.655 106.395 ;
      RECT 88.305 189.585 88.655 189.655 ;
      RECT 88.305 189.725 88.655 189.795 ;
      RECT 88.3 122.865 88.65 122.935 ;
      RECT 88.3 123.005 88.65 123.075 ;
      RECT 88.3 150.665 88.65 150.735 ;
      RECT 88.3 150.805 88.65 150.875 ;
      RECT 88.295 11.665 88.645 11.735 ;
      RECT 88.295 11.805 88.645 11.875 ;
      RECT 88.295 167.345 88.645 167.415 ;
      RECT 88.295 167.485 88.645 167.555 ;
      RECT 88.295 195.145 88.645 195.215 ;
      RECT 88.295 195.285 88.645 195.355 ;
      RECT 88.29 56.145 88.64 56.215 ;
      RECT 88.29 56.285 88.64 56.355 ;
      RECT 88.29 239.625 88.64 239.695 ;
      RECT 88.29 239.765 88.64 239.835 ;
      RECT 88.285 100.625 88.635 100.695 ;
      RECT 88.285 100.765 88.635 100.835 ;
      RECT 88.285 184.025 88.635 184.095 ;
      RECT 88.285 184.165 88.635 184.235 ;
      RECT 88.285 245.185 88.635 245.255 ;
      RECT 88.285 245.325 88.635 245.395 ;
      RECT 88.28 228.505 88.63 228.575 ;
      RECT 88.28 228.645 88.63 228.715 ;
      RECT 88.275 45.025 88.625 45.095 ;
      RECT 88.275 45.165 88.625 45.235 ;
      RECT 88.275 145.105 88.625 145.175 ;
      RECT 88.275 145.245 88.625 145.315 ;
      RECT 88.27 89.505 88.62 89.575 ;
      RECT 88.27 89.645 88.62 89.715 ;
      RECT 88.27 172.905 88.62 172.975 ;
      RECT 88.27 173.045 88.62 173.115 ;
      RECT 88.265 33.905 88.615 33.975 ;
      RECT 88.265 34.045 88.615 34.115 ;
      RECT 88.265 95.065 88.615 95.135 ;
      RECT 88.265 95.205 88.615 95.275 ;
      RECT 88.265 133.985 88.615 134.055 ;
      RECT 88.265 134.125 88.615 134.195 ;
      RECT 88.265 217.385 88.615 217.455 ;
      RECT 88.265 217.525 88.615 217.595 ;
      RECT 88.26 261.865 88.61 261.935 ;
      RECT 88.26 262.005 88.61 262.075 ;
      RECT 88.255 28.345 88.605 28.415 ;
      RECT 88.255 28.485 88.605 28.555 ;
      RECT 88.25 6.105 88.6 6.175 ;
      RECT 88.25 6.245 88.6 6.315 ;
      RECT 88.25 22.785 88.6 22.855 ;
      RECT 88.25 22.925 88.6 22.995 ;
      RECT 88.25 39.465 88.6 39.535 ;
      RECT 88.25 39.605 88.6 39.675 ;
      RECT 88.25 250.745 88.6 250.815 ;
      RECT 88.25 250.885 88.6 250.955 ;
      RECT 88.245 67.265 88.595 67.335 ;
      RECT 88.245 67.405 88.595 67.475 ;
      RECT 88.24 111.745 88.59 111.815 ;
      RECT 88.24 111.885 88.59 111.955 ;
      RECT 88.24 178.465 88.59 178.535 ;
      RECT 88.24 178.605 88.59 178.675 ;
      RECT 88.24 211.825 88.59 211.895 ;
      RECT 88.24 211.965 88.59 212.035 ;
      RECT 88.235 156.225 88.585 156.295 ;
      RECT 88.235 156.365 88.585 156.435 ;
      RECT 88.23 284.105 88.58 284.175 ;
      RECT 88.23 284.245 88.58 284.315 ;
      RECT 88.22 61.705 88.57 61.775 ;
      RECT 88.22 61.845 88.57 61.915 ;
      RECT 88.22 78.385 88.57 78.455 ;
      RECT 88.22 78.525 88.57 78.595 ;
      RECT 88.185 234.07 88.535 234.14 ;
      RECT 88.185 234.21 88.535 234.28 ;
      RECT 88.185 278.6 88.535 278.67 ;
      RECT 88.18 295.24 88.53 295.31 ;
      RECT 88.15 128.425 88.5 128.495 ;
      RECT 88.15 128.565 88.5 128.635 ;
      RECT 88.07 256.305 88.42 256.375 ;
      RECT 88.07 256.445 88.42 256.515 ;
      RECT 88.065 50.585 88.415 50.655 ;
      RECT 88.065 50.725 88.415 50.795 ;
      RECT 88.06 200.705 88.41 200.775 ;
      RECT 88.06 200.845 88.41 200.915 ;
      RECT 87.94 17.265 88.29 17.335 ;
      RECT 87.895 72.96 88.245 73.03 ;
      RECT 87.895 84.06 88.245 84.13 ;
      RECT 87.895 139.665 88.245 139.735 ;
      RECT 87.895 223 88.245 223.07 ;
      RECT 87.895 267.53 88.245 267.6 ;
      RECT 87.87 117.305 88.22 117.375 ;
      RECT 87.87 117.445 88.22 117.515 ;
      RECT 87.87 272.985 88.22 273.055 ;
      RECT 87.87 273.125 88.22 273.195 ;
      RECT 87.865 161.785 88.215 161.855 ;
      RECT 87.865 161.925 88.215 161.995 ;
      RECT 87.86 206.265 88.21 206.335 ;
      RECT 87.86 206.405 88.21 206.475 ;
      RECT 87.86 289.665 88.21 289.735 ;
      RECT 87.86 289.805 88.21 289.875 ;
      RECT 87.855 106.185 88.205 106.255 ;
      RECT 87.855 106.325 88.205 106.395 ;
      RECT 87.855 189.585 88.205 189.655 ;
      RECT 87.855 189.725 88.205 189.795 ;
      RECT 87.85 122.865 88.2 122.935 ;
      RECT 87.85 123.005 88.2 123.075 ;
      RECT 87.85 150.665 88.2 150.735 ;
      RECT 87.85 150.805 88.2 150.875 ;
      RECT 87.845 11.665 88.195 11.735 ;
      RECT 87.845 11.805 88.195 11.875 ;
      RECT 87.845 167.345 88.195 167.415 ;
      RECT 87.845 167.485 88.195 167.555 ;
      RECT 87.845 195.145 88.195 195.215 ;
      RECT 87.845 195.285 88.195 195.355 ;
      RECT 87.84 56.145 88.19 56.215 ;
      RECT 87.84 56.285 88.19 56.355 ;
      RECT 87.84 239.625 88.19 239.695 ;
      RECT 87.84 239.765 88.19 239.835 ;
      RECT 87.835 100.625 88.185 100.695 ;
      RECT 87.835 100.765 88.185 100.835 ;
      RECT 87.835 184.025 88.185 184.095 ;
      RECT 87.835 184.165 88.185 184.235 ;
      RECT 87.835 245.185 88.185 245.255 ;
      RECT 87.835 245.325 88.185 245.395 ;
      RECT 87.83 228.505 88.18 228.575 ;
      RECT 87.83 228.645 88.18 228.715 ;
      RECT 87.825 45.025 88.175 45.095 ;
      RECT 87.825 45.165 88.175 45.235 ;
      RECT 87.825 145.105 88.175 145.175 ;
      RECT 87.825 145.245 88.175 145.315 ;
      RECT 87.82 89.505 88.17 89.575 ;
      RECT 87.82 89.645 88.17 89.715 ;
      RECT 87.82 172.905 88.17 172.975 ;
      RECT 87.82 173.045 88.17 173.115 ;
      RECT 87.815 33.905 88.165 33.975 ;
      RECT 87.815 34.045 88.165 34.115 ;
      RECT 87.815 95.065 88.165 95.135 ;
      RECT 87.815 95.205 88.165 95.275 ;
      RECT 87.815 133.985 88.165 134.055 ;
      RECT 87.815 134.125 88.165 134.195 ;
      RECT 87.815 217.385 88.165 217.455 ;
      RECT 87.815 217.525 88.165 217.595 ;
      RECT 87.81 261.865 88.16 261.935 ;
      RECT 87.81 262.005 88.16 262.075 ;
      RECT 87.805 28.345 88.155 28.415 ;
      RECT 87.805 28.485 88.155 28.555 ;
      RECT 87.8 6.105 88.15 6.175 ;
      RECT 87.8 6.245 88.15 6.315 ;
      RECT 87.8 22.785 88.15 22.855 ;
      RECT 87.8 22.925 88.15 22.995 ;
      RECT 87.8 39.465 88.15 39.535 ;
      RECT 87.8 39.605 88.15 39.675 ;
      RECT 87.8 250.745 88.15 250.815 ;
      RECT 87.8 250.885 88.15 250.955 ;
      RECT 87.795 67.265 88.145 67.335 ;
      RECT 87.795 67.405 88.145 67.475 ;
      RECT 87.79 111.745 88.14 111.815 ;
      RECT 87.79 111.885 88.14 111.955 ;
      RECT 87.79 178.465 88.14 178.535 ;
      RECT 87.79 178.605 88.14 178.675 ;
      RECT 87.79 211.825 88.14 211.895 ;
      RECT 87.79 211.965 88.14 212.035 ;
      RECT 87.785 156.225 88.135 156.295 ;
      RECT 87.785 156.365 88.135 156.435 ;
      RECT 87.78 284.105 88.13 284.175 ;
      RECT 87.78 284.245 88.13 284.315 ;
      RECT 87.77 61.705 88.12 61.775 ;
      RECT 87.77 61.845 88.12 61.915 ;
      RECT 87.77 78.385 88.12 78.455 ;
      RECT 87.77 78.525 88.12 78.595 ;
      RECT 87.735 234.07 88.085 234.14 ;
      RECT 87.735 234.21 88.085 234.28 ;
      RECT 87.735 278.6 88.085 278.67 ;
      RECT 87.73 295.24 88.08 295.31 ;
      RECT 87.7 128.425 88.05 128.495 ;
      RECT 87.7 128.565 88.05 128.635 ;
      RECT 87.62 256.305 87.97 256.375 ;
      RECT 87.62 256.445 87.97 256.515 ;
      RECT 87.615 50.585 87.965 50.655 ;
      RECT 87.615 50.725 87.965 50.795 ;
      RECT 87.61 200.705 87.96 200.775 ;
      RECT 87.61 200.845 87.96 200.915 ;
      RECT 87.49 17.265 87.84 17.335 ;
    LAYER M6 SPACING 0.05 ;
      RECT 0 0 92.2 296 ;
    LAYER M7 ;
      RECT 67.545 56.345 67.665 57.345 ;
      RECT 67.545 138.7 67.665 139.7 ;
      RECT 67.545 221.055 67.665 222.055 ;
      RECT 67.54 18.8 67.66 19.8 ;
      RECT 67.54 101.155 67.66 102.155 ;
      RECT 67.54 183.51 67.66 184.51 ;
      RECT 67.54 265.865 67.66 266.865 ;
      RECT 67.535 63.61 67.655 64.61 ;
      RECT 67.535 145.965 67.655 146.965 ;
      RECT 67.535 228.32 67.655 229.32 ;
      RECT 67.53 26.065 67.65 27.065 ;
      RECT 67.53 108.42 67.65 109.42 ;
      RECT 67.53 190.775 67.65 191.775 ;
      RECT 67.53 273.13 67.65 274.13 ;
      RECT 67.525 70.875 67.645 71.875 ;
      RECT 67.525 153.23 67.645 154.23 ;
      RECT 67.525 235.585 67.645 236.585 ;
      RECT 67.52 33.33 67.64 34.33 ;
      RECT 67.52 115.685 67.64 116.685 ;
      RECT 67.52 198.04 67.64 199.04 ;
      RECT 67.52 280.395 67.64 281.395 ;
      RECT 67.515 78.14 67.635 79.14 ;
      RECT 67.515 160.495 67.635 161.495 ;
      RECT 67.515 242.85 67.635 243.85 ;
      RECT 67.51 40.595 67.63 41.595 ;
      RECT 67.51 122.95 67.63 123.95 ;
      RECT 67.51 205.305 67.63 206.305 ;
      RECT 67.51 287.66 67.63 288.66 ;
      RECT 67.505 3.05 67.625 4.05 ;
      RECT 67.505 85.405 67.625 86.405 ;
      RECT 67.505 167.76 67.625 168.76 ;
      RECT 67.505 250.115 67.625 251.115 ;
      RECT 67.5 47.86 67.62 48.86 ;
      RECT 67.5 130.215 67.62 131.215 ;
      RECT 67.5 212.57 67.62 213.57 ;
      RECT 67.495 10.315 67.615 11.315 ;
      RECT 67.495 92.67 67.615 93.67 ;
      RECT 67.495 175.025 67.615 176.025 ;
      RECT 67.495 257.38 67.615 258.38 ;
      RECT 67.49 55.125 67.61 56.125 ;
      RECT 67.49 137.48 67.61 138.48 ;
      RECT 67.49 219.835 67.61 220.835 ;
      RECT 67.485 17.58 67.605 18.58 ;
      RECT 67.485 99.935 67.605 100.935 ;
      RECT 67.485 182.29 67.605 183.29 ;
      RECT 67.485 264.645 67.605 265.645 ;
      RECT 67.48 62.39 67.6 63.39 ;
      RECT 67.48 144.745 67.6 145.745 ;
      RECT 67.48 227.1 67.6 228.1 ;
      RECT 67.475 24.845 67.595 25.845 ;
      RECT 67.475 107.2 67.595 108.2 ;
      RECT 67.475 189.555 67.595 190.555 ;
      RECT 67.475 271.91 67.595 272.91 ;
      RECT 67.47 69.655 67.59 70.655 ;
      RECT 67.47 152.01 67.59 153.01 ;
      RECT 67.47 234.365 67.59 235.365 ;
      RECT 67.465 32.11 67.585 33.11 ;
      RECT 67.465 114.465 67.585 115.465 ;
      RECT 67.465 196.82 67.585 197.82 ;
      RECT 67.465 279.175 67.585 280.175 ;
      RECT 67.46 76.92 67.58 77.92 ;
      RECT 67.46 159.275 67.58 160.275 ;
      RECT 67.46 241.63 67.58 242.63 ;
      RECT 67.455 39.375 67.575 40.375 ;
      RECT 67.455 121.73 67.575 122.73 ;
      RECT 67.455 204.085 67.575 205.085 ;
      RECT 67.455 286.44 67.575 287.44 ;
      RECT 67.45 1.83 67.57 2.83 ;
      RECT 67.45 84.185 67.57 85.185 ;
      RECT 67.45 166.54 67.57 167.54 ;
      RECT 67.45 248.895 67.57 249.895 ;
      RECT 67.445 46.64 67.565 47.64 ;
      RECT 67.445 128.995 67.565 129.995 ;
      RECT 67.445 211.35 67.565 212.35 ;
      RECT 67.445 293.705 67.565 294.705 ;
      RECT 67.44 9.095 67.56 10.095 ;
      RECT 67.44 91.45 67.56 92.45 ;
      RECT 67.44 173.805 67.56 174.805 ;
      RECT 67.44 256.16 67.56 257.16 ;
      RECT 67.435 53.905 67.555 54.905 ;
      RECT 67.435 136.26 67.555 137.26 ;
      RECT 67.435 218.615 67.555 219.615 ;
      RECT 67.43 16.36 67.55 17.36 ;
      RECT 67.43 98.715 67.55 99.715 ;
      RECT 67.43 181.07 67.55 182.07 ;
      RECT 67.43 263.425 67.55 264.425 ;
      RECT 67.425 61.17 67.545 62.17 ;
      RECT 67.425 143.525 67.545 144.525 ;
      RECT 67.425 225.88 67.545 226.88 ;
      RECT 67.42 23.625 67.54 24.625 ;
      RECT 67.42 105.98 67.54 106.98 ;
      RECT 67.42 188.335 67.54 189.335 ;
      RECT 67.42 270.69 67.54 271.69 ;
      RECT 67.415 68.435 67.535 69.435 ;
      RECT 67.415 150.79 67.535 151.79 ;
      RECT 67.415 233.145 67.535 234.145 ;
      RECT 67.41 30.89 67.53 31.89 ;
      RECT 67.41 113.245 67.53 114.245 ;
      RECT 67.41 195.6 67.53 196.6 ;
      RECT 67.41 277.955 67.53 278.955 ;
      RECT 67.405 75.7 67.525 76.7 ;
      RECT 67.405 158.055 67.525 159.055 ;
      RECT 67.405 240.41 67.525 241.41 ;
      RECT 67.4 38.155 67.52 39.155 ;
      RECT 67.17 46.195 67.52 46.265 ;
      RECT 67.17 46.335 67.52 46.405 ;
      RECT 67.17 53.46 67.52 53.53 ;
      RECT 67.17 53.6 67.52 53.67 ;
      RECT 67.4 120.51 67.52 121.51 ;
      RECT 67.17 128.55 67.52 128.62 ;
      RECT 67.17 128.69 67.52 128.76 ;
      RECT 67.17 135.815 67.52 135.885 ;
      RECT 67.17 135.955 67.52 136.025 ;
      RECT 67.4 202.865 67.52 203.865 ;
      RECT 67.17 210.905 67.52 210.975 ;
      RECT 67.17 211.045 67.52 211.115 ;
      RECT 67.17 218.17 67.52 218.24 ;
      RECT 67.17 218.31 67.52 218.38 ;
      RECT 67.4 285.22 67.52 286.22 ;
      RECT 67.17 293.26 67.52 293.33 ;
      RECT 67.17 293.4 67.52 293.47 ;
      RECT 67.45 294.905 67.52 295.255 ;
      RECT 67.395 0.61 67.515 1.61 ;
      RECT 67.395 7.905 67.515 8.405 ;
      RECT 67.395 15.17 67.515 15.67 ;
      RECT 67.395 45.45 67.515 45.95 ;
      RECT 67.395 52.715 67.515 53.215 ;
      RECT 67.395 59.98 67.515 60.48 ;
      RECT 67.395 82.965 67.515 83.965 ;
      RECT 67.395 90.26 67.515 90.76 ;
      RECT 67.395 97.525 67.515 98.025 ;
      RECT 67.395 127.805 67.515 128.305 ;
      RECT 67.395 135.07 67.515 135.57 ;
      RECT 67.395 142.335 67.515 142.835 ;
      RECT 67.395 165.32 67.515 166.32 ;
      RECT 67.395 172.615 67.515 173.115 ;
      RECT 67.395 179.88 67.515 180.38 ;
      RECT 67.395 210.16 67.515 210.66 ;
      RECT 67.395 217.425 67.515 217.925 ;
      RECT 67.395 224.69 67.515 225.19 ;
      RECT 67.395 247.675 67.515 248.675 ;
      RECT 67.395 254.97 67.515 255.47 ;
      RECT 67.395 262.235 67.515 262.735 ;
      RECT 67.395 292.515 67.515 293.015 ;
      RECT 67.31 5.555 67.38 5.905 ;
      RECT 67.31 6.005 67.38 6.355 ;
      RECT 67.31 6.455 67.38 6.805 ;
      RECT 67.31 6.905 67.38 7.255 ;
      RECT 67.31 7.355 67.38 7.705 ;
      RECT 67.31 12.755 67.38 13.105 ;
      RECT 67.31 13.205 67.38 13.555 ;
      RECT 67.31 13.655 67.38 14.005 ;
      RECT 67.31 14.105 67.38 14.455 ;
      RECT 67.31 14.555 67.38 14.905 ;
      RECT 67.31 20.405 67.38 20.755 ;
      RECT 67.31 20.855 67.38 21.205 ;
      RECT 67.31 21.305 67.38 21.655 ;
      RECT 67.31 21.755 67.38 22.105 ;
      RECT 67.31 22.205 67.38 22.555 ;
      RECT 67.31 22.655 67.38 23.005 ;
      RECT 67.31 27.605 67.38 27.955 ;
      RECT 67.31 28.055 67.38 28.405 ;
      RECT 67.31 28.505 67.38 28.855 ;
      RECT 67.31 28.955 67.38 29.305 ;
      RECT 67.31 29.405 67.38 29.755 ;
      RECT 67.31 29.855 67.38 30.205 ;
      RECT 67.31 30.305 67.38 30.655 ;
      RECT 67.31 36.155 67.38 36.505 ;
      RECT 67.31 36.605 67.38 36.955 ;
      RECT 67.31 37.055 67.38 37.405 ;
      RECT 67.31 37.505 67.38 37.855 ;
      RECT 67.31 43.355 67.38 43.705 ;
      RECT 67.31 43.805 67.38 44.155 ;
      RECT 67.31 44.255 67.38 44.605 ;
      RECT 67.31 44.705 67.38 45.055 ;
      RECT 67.31 50.555 67.38 50.905 ;
      RECT 67.31 51.005 67.38 51.355 ;
      RECT 67.31 51.455 67.38 51.805 ;
      RECT 67.31 51.905 67.38 52.255 ;
      RECT 67.31 57.755 67.38 58.105 ;
      RECT 67.31 58.205 67.38 58.555 ;
      RECT 67.31 58.655 67.38 59.005 ;
      RECT 67.31 59.105 67.38 59.455 ;
      RECT 67.31 64.955 67.38 65.305 ;
      RECT 67.31 65.405 67.38 65.755 ;
      RECT 67.31 65.855 67.38 66.205 ;
      RECT 67.31 66.305 67.38 66.655 ;
      RECT 67.31 66.755 67.38 67.105 ;
      RECT 67.31 67.205 67.38 67.555 ;
      RECT 67.31 67.655 67.38 68.005 ;
      RECT 67.31 72.155 67.38 72.505 ;
      RECT 67.31 72.605 67.38 72.955 ;
      RECT 67.31 73.055 67.38 73.405 ;
      RECT 67.31 73.505 67.38 73.855 ;
      RECT 67.31 73.955 67.38 74.305 ;
      RECT 67.31 74.405 67.38 74.755 ;
      RECT 67.31 74.855 67.38 75.205 ;
      RECT 67.31 80.705 67.38 81.055 ;
      RECT 67.31 81.155 67.38 81.505 ;
      RECT 67.31 81.605 67.38 81.955 ;
      RECT 67.31 82.055 67.38 82.405 ;
      RECT 67.31 87.905 67.38 88.255 ;
      RECT 67.31 88.355 67.38 88.705 ;
      RECT 67.31 88.805 67.38 89.155 ;
      RECT 67.31 89.255 67.38 89.605 ;
      RECT 67.31 89.705 67.38 90.055 ;
      RECT 67.31 95.105 67.38 95.455 ;
      RECT 67.31 95.555 67.38 95.905 ;
      RECT 67.31 96.005 67.38 96.355 ;
      RECT 67.31 96.455 67.38 96.805 ;
      RECT 67.31 96.905 67.38 97.255 ;
      RECT 67.31 102.755 67.38 103.105 ;
      RECT 67.31 103.205 67.38 103.555 ;
      RECT 67.31 103.655 67.38 104.005 ;
      RECT 67.31 104.105 67.38 104.455 ;
      RECT 67.31 104.555 67.38 104.905 ;
      RECT 67.31 105.005 67.38 105.355 ;
      RECT 67.31 109.955 67.38 110.305 ;
      RECT 67.31 110.405 67.38 110.755 ;
      RECT 67.31 110.855 67.38 111.205 ;
      RECT 67.31 111.305 67.38 111.655 ;
      RECT 67.31 111.755 67.38 112.105 ;
      RECT 67.31 112.205 67.38 112.555 ;
      RECT 67.31 112.655 67.38 113.005 ;
      RECT 67.31 118.505 67.38 118.855 ;
      RECT 67.31 118.955 67.38 119.305 ;
      RECT 67.31 119.405 67.38 119.755 ;
      RECT 67.31 119.855 67.38 120.205 ;
      RECT 67.31 125.705 67.38 126.055 ;
      RECT 67.31 126.155 67.38 126.505 ;
      RECT 67.31 126.605 67.38 126.955 ;
      RECT 67.31 127.055 67.38 127.405 ;
      RECT 67.31 132.905 67.38 133.255 ;
      RECT 67.31 133.355 67.38 133.705 ;
      RECT 67.31 133.805 67.38 134.155 ;
      RECT 67.31 134.255 67.38 134.605 ;
      RECT 67.31 140.105 67.38 140.455 ;
      RECT 67.31 140.555 67.38 140.905 ;
      RECT 67.31 141.005 67.38 141.355 ;
      RECT 67.31 141.455 67.38 141.805 ;
      RECT 67.31 147.305 67.38 147.655 ;
      RECT 67.31 147.755 67.38 148.105 ;
      RECT 67.31 148.205 67.38 148.555 ;
      RECT 67.31 148.655 67.38 149.005 ;
      RECT 67.31 149.105 67.38 149.455 ;
      RECT 67.31 149.555 67.38 149.905 ;
      RECT 67.31 150.005 67.38 150.355 ;
      RECT 67.31 154.505 67.38 154.855 ;
      RECT 67.31 154.955 67.38 155.305 ;
      RECT 67.31 155.405 67.38 155.755 ;
      RECT 67.31 155.855 67.38 156.205 ;
      RECT 67.31 156.305 67.38 156.655 ;
      RECT 67.31 156.755 67.38 157.105 ;
      RECT 67.31 157.205 67.38 157.555 ;
      RECT 67.31 163.055 67.38 163.405 ;
      RECT 67.31 163.505 67.38 163.855 ;
      RECT 67.31 163.955 67.38 164.305 ;
      RECT 67.31 164.405 67.38 164.755 ;
      RECT 67.31 170.255 67.38 170.605 ;
      RECT 67.31 170.705 67.38 171.055 ;
      RECT 67.31 171.155 67.38 171.505 ;
      RECT 67.31 171.605 67.38 171.955 ;
      RECT 67.31 172.055 67.38 172.405 ;
      RECT 67.31 177.455 67.38 177.805 ;
      RECT 67.31 177.905 67.38 178.255 ;
      RECT 67.31 178.355 67.38 178.705 ;
      RECT 67.31 178.805 67.38 179.155 ;
      RECT 67.31 179.255 67.38 179.605 ;
      RECT 67.31 185.105 67.38 185.455 ;
      RECT 67.31 185.555 67.38 185.905 ;
      RECT 67.31 186.005 67.38 186.355 ;
      RECT 67.31 186.455 67.38 186.805 ;
      RECT 67.31 186.905 67.38 187.255 ;
      RECT 67.31 187.355 67.38 187.705 ;
      RECT 67.31 192.305 67.38 192.655 ;
      RECT 67.31 192.755 67.38 193.105 ;
      RECT 67.31 193.205 67.38 193.555 ;
      RECT 67.31 193.655 67.38 194.005 ;
      RECT 67.31 194.105 67.38 194.455 ;
      RECT 67.31 194.555 67.38 194.905 ;
      RECT 67.31 195.005 67.38 195.355 ;
      RECT 67.31 200.855 67.38 201.205 ;
      RECT 67.31 201.305 67.38 201.655 ;
      RECT 67.31 201.755 67.38 202.105 ;
      RECT 67.31 202.205 67.38 202.555 ;
      RECT 67.31 208.055 67.38 208.405 ;
      RECT 67.31 208.505 67.38 208.855 ;
      RECT 67.31 208.955 67.38 209.305 ;
      RECT 67.31 209.405 67.38 209.755 ;
      RECT 67.31 215.255 67.38 215.605 ;
      RECT 67.31 215.705 67.38 216.055 ;
      RECT 67.31 216.155 67.38 216.505 ;
      RECT 67.31 216.605 67.38 216.955 ;
      RECT 67.31 222.455 67.38 222.805 ;
      RECT 67.31 222.905 67.38 223.255 ;
      RECT 67.31 223.355 67.38 223.705 ;
      RECT 67.31 223.805 67.38 224.155 ;
      RECT 67.31 229.655 67.38 230.005 ;
      RECT 67.31 230.105 67.38 230.455 ;
      RECT 67.31 230.555 67.38 230.905 ;
      RECT 67.31 231.005 67.38 231.355 ;
      RECT 67.31 231.455 67.38 231.805 ;
      RECT 67.31 231.905 67.38 232.255 ;
      RECT 67.31 232.355 67.38 232.705 ;
      RECT 67.31 236.855 67.38 237.205 ;
      RECT 67.31 237.305 67.38 237.655 ;
      RECT 67.31 237.755 67.38 238.105 ;
      RECT 67.31 238.205 67.38 238.555 ;
      RECT 67.31 238.655 67.38 239.005 ;
      RECT 67.31 239.105 67.38 239.455 ;
      RECT 67.31 239.555 67.38 239.905 ;
      RECT 67.31 245.405 67.38 245.755 ;
      RECT 67.31 245.855 67.38 246.205 ;
      RECT 67.31 246.305 67.38 246.655 ;
      RECT 67.31 246.755 67.38 247.105 ;
      RECT 67.31 252.605 67.38 252.955 ;
      RECT 67.31 253.055 67.38 253.405 ;
      RECT 67.31 253.505 67.38 253.855 ;
      RECT 67.31 253.955 67.38 254.305 ;
      RECT 67.31 254.405 67.38 254.755 ;
      RECT 67.31 259.805 67.38 260.155 ;
      RECT 67.31 260.255 67.38 260.605 ;
      RECT 67.31 260.705 67.38 261.055 ;
      RECT 67.31 261.155 67.38 261.505 ;
      RECT 67.31 261.605 67.38 261.955 ;
      RECT 67.31 267.455 67.38 267.805 ;
      RECT 67.31 267.905 67.38 268.255 ;
      RECT 67.31 268.355 67.38 268.705 ;
      RECT 67.31 268.805 67.38 269.155 ;
      RECT 67.31 269.255 67.38 269.605 ;
      RECT 67.31 269.705 67.38 270.055 ;
      RECT 67.31 274.655 67.38 275.005 ;
      RECT 67.31 275.105 67.38 275.455 ;
      RECT 67.31 275.555 67.38 275.905 ;
      RECT 67.31 276.005 67.38 276.355 ;
      RECT 67.31 276.455 67.38 276.805 ;
      RECT 67.31 276.905 67.38 277.255 ;
      RECT 67.31 277.355 67.38 277.705 ;
      RECT 67.31 283.205 67.38 283.555 ;
      RECT 67.31 283.655 67.38 284.005 ;
      RECT 67.31 284.105 67.38 284.455 ;
      RECT 67.31 284.555 67.38 284.905 ;
      RECT 67.31 290.405 67.38 290.755 ;
      RECT 67.31 290.855 67.38 291.205 ;
      RECT 67.31 291.305 67.38 291.655 ;
      RECT 67.31 291.755 67.38 292.105 ;
      RECT 67.31 294.905 67.38 295.255 ;
      RECT 67.17 1.955 67.24 2.305 ;
      RECT 67.17 2.405 67.24 2.755 ;
      RECT 67.17 2.855 67.24 3.205 ;
      RECT 67.17 3.305 67.24 3.655 ;
      RECT 67.17 3.755 67.24 4.105 ;
      RECT 67.17 4.205 67.24 4.555 ;
      RECT 67.17 4.655 67.24 5.005 ;
      RECT 67.17 5.105 67.24 5.455 ;
      RECT 67.17 5.555 67.24 5.905 ;
      RECT 67.17 6.005 67.24 6.355 ;
      RECT 67.17 6.455 67.24 6.805 ;
      RECT 67.17 6.905 67.24 7.255 ;
      RECT 67.17 7.355 67.24 7.705 ;
      RECT 67.17 8.705 67.24 9.055 ;
      RECT 67.17 9.155 67.24 9.505 ;
      RECT 67.17 9.605 67.24 9.955 ;
      RECT 67.17 10.055 67.24 10.405 ;
      RECT 67.17 10.505 67.24 10.855 ;
      RECT 67.17 10.955 67.24 11.305 ;
      RECT 67.17 11.405 67.24 11.755 ;
      RECT 67.17 11.855 67.24 12.205 ;
      RECT 67.17 12.305 67.24 12.655 ;
      RECT 67.17 12.755 67.24 13.105 ;
      RECT 67.17 13.205 67.24 13.555 ;
      RECT 67.17 13.655 67.24 14.005 ;
      RECT 67.17 14.105 67.24 14.455 ;
      RECT 67.17 14.555 67.24 14.905 ;
      RECT 67.17 17.705 67.24 18.055 ;
      RECT 67.17 18.155 67.24 18.505 ;
      RECT 67.17 18.605 67.24 18.955 ;
      RECT 67.17 19.055 67.24 19.405 ;
      RECT 67.17 19.505 67.24 19.855 ;
      RECT 67.17 19.955 67.24 20.305 ;
      RECT 67.17 20.405 67.24 20.755 ;
      RECT 67.17 20.855 67.24 21.205 ;
      RECT 67.17 21.305 67.24 21.655 ;
      RECT 67.17 21.755 67.24 22.105 ;
      RECT 67.17 22.205 67.24 22.555 ;
      RECT 67.17 22.655 67.24 23.005 ;
      RECT 67.17 24.905 67.24 25.255 ;
      RECT 67.17 25.355 67.24 25.705 ;
      RECT 67.17 25.805 67.24 26.155 ;
      RECT 67.17 26.255 67.24 26.605 ;
      RECT 67.17 26.705 67.24 27.055 ;
      RECT 67.17 27.155 67.24 27.505 ;
      RECT 67.17 27.605 67.24 27.955 ;
      RECT 67.17 28.055 67.24 28.405 ;
      RECT 67.17 28.505 67.24 28.855 ;
      RECT 67.17 28.955 67.24 29.305 ;
      RECT 67.17 29.405 67.24 29.755 ;
      RECT 67.17 29.855 67.24 30.205 ;
      RECT 67.17 30.305 67.24 30.655 ;
      RECT 67.17 32.105 67.24 32.455 ;
      RECT 67.17 32.555 67.24 32.905 ;
      RECT 67.17 33.005 67.24 33.355 ;
      RECT 67.17 33.455 67.24 33.805 ;
      RECT 67.17 33.905 67.24 34.255 ;
      RECT 67.17 34.355 67.24 34.705 ;
      RECT 67.17 34.805 67.24 35.155 ;
      RECT 67.17 35.255 67.24 35.605 ;
      RECT 67.17 35.705 67.24 36.055 ;
      RECT 67.17 36.155 67.24 36.505 ;
      RECT 67.17 36.605 67.24 36.955 ;
      RECT 67.17 37.055 67.24 37.405 ;
      RECT 67.17 37.505 67.24 37.855 ;
      RECT 67.17 39.755 67.24 40.105 ;
      RECT 67.17 40.205 67.24 40.555 ;
      RECT 67.17 40.655 67.24 41.005 ;
      RECT 67.17 41.105 67.24 41.455 ;
      RECT 67.17 41.555 67.24 41.905 ;
      RECT 67.17 42.005 67.24 42.355 ;
      RECT 67.17 42.455 67.24 42.805 ;
      RECT 67.17 42.905 67.24 43.255 ;
      RECT 67.17 43.355 67.24 43.705 ;
      RECT 67.17 43.805 67.24 44.155 ;
      RECT 67.17 44.255 67.24 44.605 ;
      RECT 67.17 44.705 67.24 45.055 ;
      RECT 67.17 46.505 67.24 46.855 ;
      RECT 67.17 46.955 67.24 47.305 ;
      RECT 67.17 47.405 67.24 47.755 ;
      RECT 67.17 47.855 67.24 48.205 ;
      RECT 67.17 48.305 67.24 48.655 ;
      RECT 67.17 48.755 67.24 49.105 ;
      RECT 67.17 49.205 67.24 49.555 ;
      RECT 67.17 49.655 67.24 50.005 ;
      RECT 67.17 50.105 67.24 50.455 ;
      RECT 67.17 50.555 67.24 50.905 ;
      RECT 67.17 51.005 67.24 51.355 ;
      RECT 67.17 51.455 67.24 51.805 ;
      RECT 67.17 51.905 67.24 52.255 ;
      RECT 67.17 55.505 67.24 55.855 ;
      RECT 67.17 55.955 67.24 56.305 ;
      RECT 67.17 56.405 67.24 56.755 ;
      RECT 67.17 56.855 67.24 57.205 ;
      RECT 67.17 57.305 67.24 57.655 ;
      RECT 67.17 57.755 67.24 58.105 ;
      RECT 67.17 58.205 67.24 58.555 ;
      RECT 67.17 58.655 67.24 59.005 ;
      RECT 67.17 59.105 67.24 59.455 ;
      RECT 67.17 62.705 67.24 63.055 ;
      RECT 67.17 63.155 67.24 63.505 ;
      RECT 67.17 63.605 67.24 63.955 ;
      RECT 67.17 64.055 67.24 64.405 ;
      RECT 67.17 64.505 67.24 64.855 ;
      RECT 67.17 64.955 67.24 65.305 ;
      RECT 67.17 65.405 67.24 65.755 ;
      RECT 67.17 65.855 67.24 66.205 ;
      RECT 67.17 66.305 67.24 66.655 ;
      RECT 67.17 66.755 67.24 67.105 ;
      RECT 67.17 67.205 67.24 67.555 ;
      RECT 67.17 67.655 67.24 68.005 ;
      RECT 67.17 69.905 67.24 70.255 ;
      RECT 67.17 70.355 67.24 70.705 ;
      RECT 67.17 70.805 67.24 71.155 ;
      RECT 67.17 71.255 67.24 71.605 ;
      RECT 67.17 71.705 67.24 72.055 ;
      RECT 67.17 72.155 67.24 72.505 ;
      RECT 67.17 72.605 67.24 72.955 ;
      RECT 67.17 73.055 67.24 73.405 ;
      RECT 67.17 73.505 67.24 73.855 ;
      RECT 67.17 73.955 67.24 74.305 ;
      RECT 67.17 74.405 67.24 74.755 ;
      RECT 67.17 74.855 67.24 75.205 ;
      RECT 67.17 77.105 67.24 77.455 ;
      RECT 67.17 77.555 67.24 77.905 ;
      RECT 67.17 78.005 67.24 78.355 ;
      RECT 67.17 78.455 67.24 78.805 ;
      RECT 67.17 78.905 67.24 79.255 ;
      RECT 67.17 79.355 67.24 79.705 ;
      RECT 67.17 79.805 67.24 80.155 ;
      RECT 67.17 80.255 67.24 80.605 ;
      RECT 67.17 80.705 67.24 81.055 ;
      RECT 67.17 81.155 67.24 81.505 ;
      RECT 67.17 81.605 67.24 81.955 ;
      RECT 67.17 82.055 67.24 82.405 ;
      RECT 67.17 84.305 67.24 84.655 ;
      RECT 67.17 84.755 67.24 85.105 ;
      RECT 67.17 85.205 67.24 85.555 ;
      RECT 67.17 85.655 67.24 86.005 ;
      RECT 67.17 86.105 67.24 86.455 ;
      RECT 67.17 86.555 67.24 86.905 ;
      RECT 67.17 87.005 67.24 87.355 ;
      RECT 67.17 87.455 67.24 87.805 ;
      RECT 67.17 87.905 67.24 88.255 ;
      RECT 67.17 88.355 67.24 88.705 ;
      RECT 67.17 88.805 67.24 89.155 ;
      RECT 67.17 89.255 67.24 89.605 ;
      RECT 67.17 89.705 67.24 90.055 ;
      RECT 67.17 91.055 67.24 91.405 ;
      RECT 67.17 91.505 67.24 91.855 ;
      RECT 67.17 91.955 67.24 92.305 ;
      RECT 67.17 92.405 67.24 92.755 ;
      RECT 67.17 92.855 67.24 93.205 ;
      RECT 67.17 93.305 67.24 93.655 ;
      RECT 67.17 93.755 67.24 94.105 ;
      RECT 67.17 94.205 67.24 94.555 ;
      RECT 67.17 94.655 67.24 95.005 ;
      RECT 67.17 95.105 67.24 95.455 ;
      RECT 67.17 95.555 67.24 95.905 ;
      RECT 67.17 96.005 67.24 96.355 ;
      RECT 67.17 96.455 67.24 96.805 ;
      RECT 67.17 96.905 67.24 97.255 ;
      RECT 67.17 100.055 67.24 100.405 ;
      RECT 67.17 100.505 67.24 100.855 ;
      RECT 67.17 100.955 67.24 101.305 ;
      RECT 67.17 101.405 67.24 101.755 ;
      RECT 67.17 101.855 67.24 102.205 ;
      RECT 67.17 102.305 67.24 102.655 ;
      RECT 67.17 102.755 67.24 103.105 ;
      RECT 67.17 103.205 67.24 103.555 ;
      RECT 67.17 103.655 67.24 104.005 ;
      RECT 67.17 104.105 67.24 104.455 ;
      RECT 67.17 104.555 67.24 104.905 ;
      RECT 67.17 105.005 67.24 105.355 ;
      RECT 67.17 107.255 67.24 107.605 ;
      RECT 67.17 107.705 67.24 108.055 ;
      RECT 67.17 108.155 67.24 108.505 ;
      RECT 67.17 108.605 67.24 108.955 ;
      RECT 67.17 109.055 67.24 109.405 ;
      RECT 67.17 109.505 67.24 109.855 ;
      RECT 67.17 109.955 67.24 110.305 ;
      RECT 67.17 110.405 67.24 110.755 ;
      RECT 67.17 110.855 67.24 111.205 ;
      RECT 67.17 111.305 67.24 111.655 ;
      RECT 67.17 111.755 67.24 112.105 ;
      RECT 67.17 112.205 67.24 112.555 ;
      RECT 67.17 112.655 67.24 113.005 ;
      RECT 67.17 114.455 67.24 114.805 ;
      RECT 67.17 114.905 67.24 115.255 ;
      RECT 67.17 115.355 67.24 115.705 ;
      RECT 67.17 115.805 67.24 116.155 ;
      RECT 67.17 116.255 67.24 116.605 ;
      RECT 67.17 116.705 67.24 117.055 ;
      RECT 67.17 117.155 67.24 117.505 ;
      RECT 67.17 117.605 67.24 117.955 ;
      RECT 67.17 118.055 67.24 118.405 ;
      RECT 67.17 118.505 67.24 118.855 ;
      RECT 67.17 118.955 67.24 119.305 ;
      RECT 67.17 119.405 67.24 119.755 ;
      RECT 67.17 119.855 67.24 120.205 ;
      RECT 67.17 122.105 67.24 122.455 ;
      RECT 67.17 122.555 67.24 122.905 ;
      RECT 67.17 123.005 67.24 123.355 ;
      RECT 67.17 123.455 67.24 123.805 ;
      RECT 67.17 123.905 67.24 124.255 ;
      RECT 67.17 124.355 67.24 124.705 ;
      RECT 67.17 124.805 67.24 125.155 ;
      RECT 67.17 125.255 67.24 125.605 ;
      RECT 67.17 125.705 67.24 126.055 ;
      RECT 67.17 126.155 67.24 126.505 ;
      RECT 67.17 126.605 67.24 126.955 ;
      RECT 67.17 127.055 67.24 127.405 ;
      RECT 67.17 128.855 67.24 129.205 ;
      RECT 67.17 129.305 67.24 129.655 ;
      RECT 67.17 129.755 67.24 130.105 ;
      RECT 67.17 130.205 67.24 130.555 ;
      RECT 67.17 130.655 67.24 131.005 ;
      RECT 67.17 131.105 67.24 131.455 ;
      RECT 67.17 131.555 67.24 131.905 ;
      RECT 67.17 132.005 67.24 132.355 ;
      RECT 67.17 132.455 67.24 132.805 ;
      RECT 67.17 132.905 67.24 133.255 ;
      RECT 67.17 133.355 67.24 133.705 ;
      RECT 67.17 133.805 67.24 134.155 ;
      RECT 67.17 134.255 67.24 134.605 ;
      RECT 67.17 137.855 67.24 138.205 ;
      RECT 67.17 138.305 67.24 138.655 ;
      RECT 67.17 138.755 67.24 139.105 ;
      RECT 67.17 139.205 67.24 139.555 ;
      RECT 67.17 139.655 67.24 140.005 ;
      RECT 67.17 140.105 67.24 140.455 ;
      RECT 67.17 140.555 67.24 140.905 ;
      RECT 67.17 141.005 67.24 141.355 ;
      RECT 67.17 141.455 67.24 141.805 ;
      RECT 67.17 145.055 67.24 145.405 ;
      RECT 67.17 145.505 67.24 145.855 ;
      RECT 67.17 145.955 67.24 146.305 ;
      RECT 67.17 146.405 67.24 146.755 ;
      RECT 67.17 146.855 67.24 147.205 ;
      RECT 67.17 147.305 67.24 147.655 ;
      RECT 67.17 147.755 67.24 148.105 ;
      RECT 67.17 148.205 67.24 148.555 ;
      RECT 67.17 148.655 67.24 149.005 ;
      RECT 67.17 149.105 67.24 149.455 ;
      RECT 67.17 149.555 67.24 149.905 ;
      RECT 67.17 150.005 67.24 150.355 ;
      RECT 67.17 152.255 67.24 152.605 ;
      RECT 67.17 152.705 67.24 153.055 ;
      RECT 67.17 153.155 67.24 153.505 ;
      RECT 67.17 153.605 67.24 153.955 ;
      RECT 67.17 154.055 67.24 154.405 ;
      RECT 67.17 154.505 67.24 154.855 ;
      RECT 67.17 154.955 67.24 155.305 ;
      RECT 67.17 155.405 67.24 155.755 ;
      RECT 67.17 155.855 67.24 156.205 ;
      RECT 67.17 156.305 67.24 156.655 ;
      RECT 67.17 156.755 67.24 157.105 ;
      RECT 67.17 157.205 67.24 157.555 ;
      RECT 67.17 159.455 67.24 159.805 ;
      RECT 67.17 159.905 67.24 160.255 ;
      RECT 67.17 160.355 67.24 160.705 ;
      RECT 67.17 160.805 67.24 161.155 ;
      RECT 67.17 161.255 67.24 161.605 ;
      RECT 67.17 161.705 67.24 162.055 ;
      RECT 67.17 162.155 67.24 162.505 ;
      RECT 67.17 162.605 67.24 162.955 ;
      RECT 67.17 163.055 67.24 163.405 ;
      RECT 67.17 163.505 67.24 163.855 ;
      RECT 67.17 163.955 67.24 164.305 ;
      RECT 67.17 164.405 67.24 164.755 ;
      RECT 67.17 166.655 67.24 167.005 ;
      RECT 67.17 167.105 67.24 167.455 ;
      RECT 67.17 167.555 67.24 167.905 ;
      RECT 67.17 168.005 67.24 168.355 ;
      RECT 67.17 168.455 67.24 168.805 ;
      RECT 67.17 168.905 67.24 169.255 ;
      RECT 67.17 169.355 67.24 169.705 ;
      RECT 67.17 169.805 67.24 170.155 ;
      RECT 67.17 170.255 67.24 170.605 ;
      RECT 67.17 170.705 67.24 171.055 ;
      RECT 67.17 171.155 67.24 171.505 ;
      RECT 67.17 171.605 67.24 171.955 ;
      RECT 67.17 172.055 67.24 172.405 ;
      RECT 67.17 173.405 67.24 173.755 ;
      RECT 67.17 173.855 67.24 174.205 ;
      RECT 67.17 174.305 67.24 174.655 ;
      RECT 67.17 174.755 67.24 175.105 ;
      RECT 67.17 175.205 67.24 175.555 ;
      RECT 67.17 175.655 67.24 176.005 ;
      RECT 67.17 176.105 67.24 176.455 ;
      RECT 67.17 176.555 67.24 176.905 ;
      RECT 67.17 177.005 67.24 177.355 ;
      RECT 67.17 177.455 67.24 177.805 ;
      RECT 67.17 177.905 67.24 178.255 ;
      RECT 67.17 178.355 67.24 178.705 ;
      RECT 67.17 178.805 67.24 179.155 ;
      RECT 67.17 179.255 67.24 179.605 ;
      RECT 67.17 182.405 67.24 182.755 ;
      RECT 67.17 182.855 67.24 183.205 ;
      RECT 67.17 183.305 67.24 183.655 ;
      RECT 67.17 183.755 67.24 184.105 ;
      RECT 67.17 184.205 67.24 184.555 ;
      RECT 67.17 184.655 67.24 185.005 ;
      RECT 67.17 185.105 67.24 185.455 ;
      RECT 67.17 185.555 67.24 185.905 ;
      RECT 67.17 186.005 67.24 186.355 ;
      RECT 67.17 186.455 67.24 186.805 ;
      RECT 67.17 186.905 67.24 187.255 ;
      RECT 67.17 187.355 67.24 187.705 ;
      RECT 67.17 189.605 67.24 189.955 ;
      RECT 67.17 190.055 67.24 190.405 ;
      RECT 67.17 190.505 67.24 190.855 ;
      RECT 67.17 190.955 67.24 191.305 ;
      RECT 67.17 191.405 67.24 191.755 ;
      RECT 67.17 191.855 67.24 192.205 ;
      RECT 67.17 192.305 67.24 192.655 ;
      RECT 67.17 192.755 67.24 193.105 ;
      RECT 67.17 193.205 67.24 193.555 ;
      RECT 67.17 193.655 67.24 194.005 ;
      RECT 67.17 194.105 67.24 194.455 ;
      RECT 67.17 194.555 67.24 194.905 ;
      RECT 67.17 195.005 67.24 195.355 ;
      RECT 67.17 196.805 67.24 197.155 ;
      RECT 67.17 197.255 67.24 197.605 ;
      RECT 67.17 197.705 67.24 198.055 ;
      RECT 67.17 198.155 67.24 198.505 ;
      RECT 67.17 198.605 67.24 198.955 ;
      RECT 67.17 199.055 67.24 199.405 ;
      RECT 67.17 199.505 67.24 199.855 ;
      RECT 67.17 199.955 67.24 200.305 ;
      RECT 67.17 200.405 67.24 200.755 ;
      RECT 67.17 200.855 67.24 201.205 ;
      RECT 67.17 201.305 67.24 201.655 ;
      RECT 67.17 201.755 67.24 202.105 ;
      RECT 67.17 202.205 67.24 202.555 ;
      RECT 67.17 204.455 67.24 204.805 ;
      RECT 67.17 204.905 67.24 205.255 ;
      RECT 67.17 205.355 67.24 205.705 ;
      RECT 67.17 205.805 67.24 206.155 ;
      RECT 67.17 206.255 67.24 206.605 ;
      RECT 67.17 206.705 67.24 207.055 ;
      RECT 67.17 207.155 67.24 207.505 ;
      RECT 67.17 207.605 67.24 207.955 ;
      RECT 67.17 208.055 67.24 208.405 ;
      RECT 67.17 208.505 67.24 208.855 ;
      RECT 67.17 208.955 67.24 209.305 ;
      RECT 67.17 209.405 67.24 209.755 ;
      RECT 67.17 211.205 67.24 211.555 ;
      RECT 67.17 211.655 67.24 212.005 ;
      RECT 67.17 212.105 67.24 212.455 ;
      RECT 67.17 212.555 67.24 212.905 ;
      RECT 67.17 213.005 67.24 213.355 ;
      RECT 67.17 213.455 67.24 213.805 ;
      RECT 67.17 213.905 67.24 214.255 ;
      RECT 67.17 214.355 67.24 214.705 ;
      RECT 67.17 214.805 67.24 215.155 ;
      RECT 67.17 215.255 67.24 215.605 ;
      RECT 67.17 215.705 67.24 216.055 ;
      RECT 67.17 216.155 67.24 216.505 ;
      RECT 67.17 216.605 67.24 216.955 ;
      RECT 67.17 220.205 67.24 220.555 ;
      RECT 67.17 220.655 67.24 221.005 ;
      RECT 67.17 221.105 67.24 221.455 ;
      RECT 67.17 221.555 67.24 221.905 ;
      RECT 67.17 222.005 67.24 222.355 ;
      RECT 67.17 222.455 67.24 222.805 ;
      RECT 67.17 222.905 67.24 223.255 ;
      RECT 67.17 223.355 67.24 223.705 ;
      RECT 67.17 223.805 67.24 224.155 ;
      RECT 67.17 227.405 67.24 227.755 ;
      RECT 67.17 227.855 67.24 228.205 ;
      RECT 67.17 228.305 67.24 228.655 ;
      RECT 67.17 228.755 67.24 229.105 ;
      RECT 67.17 229.205 67.24 229.555 ;
      RECT 67.17 229.655 67.24 230.005 ;
      RECT 67.17 230.105 67.24 230.455 ;
      RECT 67.17 230.555 67.24 230.905 ;
      RECT 67.17 231.005 67.24 231.355 ;
      RECT 67.17 231.455 67.24 231.805 ;
      RECT 67.17 231.905 67.24 232.255 ;
      RECT 67.17 232.355 67.24 232.705 ;
      RECT 67.17 234.605 67.24 234.955 ;
      RECT 67.17 235.055 67.24 235.405 ;
      RECT 67.17 235.505 67.24 235.855 ;
      RECT 67.17 235.955 67.24 236.305 ;
      RECT 67.17 236.405 67.24 236.755 ;
      RECT 67.17 236.855 67.24 237.205 ;
      RECT 67.17 237.305 67.24 237.655 ;
      RECT 67.17 237.755 67.24 238.105 ;
      RECT 67.17 238.205 67.24 238.555 ;
      RECT 67.17 238.655 67.24 239.005 ;
      RECT 67.17 239.105 67.24 239.455 ;
      RECT 67.17 239.555 67.24 239.905 ;
      RECT 67.17 241.805 67.24 242.155 ;
      RECT 67.17 242.255 67.24 242.605 ;
      RECT 67.17 242.705 67.24 243.055 ;
      RECT 67.17 243.155 67.24 243.505 ;
      RECT 67.17 243.605 67.24 243.955 ;
      RECT 67.17 244.055 67.24 244.405 ;
      RECT 67.17 244.505 67.24 244.855 ;
      RECT 67.17 244.955 67.24 245.305 ;
      RECT 67.17 245.405 67.24 245.755 ;
      RECT 67.17 245.855 67.24 246.205 ;
      RECT 67.17 246.305 67.24 246.655 ;
      RECT 67.17 246.755 67.24 247.105 ;
      RECT 67.17 249.005 67.24 249.355 ;
      RECT 67.17 249.455 67.24 249.805 ;
      RECT 67.17 249.905 67.24 250.255 ;
      RECT 67.17 250.355 67.24 250.705 ;
      RECT 67.17 250.805 67.24 251.155 ;
      RECT 67.17 251.255 67.24 251.605 ;
      RECT 67.17 251.705 67.24 252.055 ;
      RECT 67.17 252.155 67.24 252.505 ;
      RECT 67.17 252.605 67.24 252.955 ;
      RECT 67.17 253.055 67.24 253.405 ;
      RECT 67.17 253.505 67.24 253.855 ;
      RECT 67.17 253.955 67.24 254.305 ;
      RECT 67.17 254.405 67.24 254.755 ;
      RECT 67.17 255.755 67.24 256.105 ;
      RECT 67.17 256.205 67.24 256.555 ;
      RECT 67.17 256.655 67.24 257.005 ;
      RECT 67.17 257.105 67.24 257.455 ;
      RECT 67.17 257.555 67.24 257.905 ;
      RECT 67.17 258.005 67.24 258.355 ;
      RECT 67.17 258.455 67.24 258.805 ;
      RECT 67.17 258.905 67.24 259.255 ;
      RECT 67.17 259.355 67.24 259.705 ;
      RECT 67.17 259.805 67.24 260.155 ;
      RECT 67.17 260.255 67.24 260.605 ;
      RECT 67.17 260.705 67.24 261.055 ;
      RECT 67.17 261.155 67.24 261.505 ;
      RECT 67.17 261.605 67.24 261.955 ;
      RECT 67.17 264.755 67.24 265.105 ;
      RECT 67.17 265.205 67.24 265.555 ;
      RECT 67.17 265.655 67.24 266.005 ;
      RECT 67.17 266.105 67.24 266.455 ;
      RECT 67.17 266.555 67.24 266.905 ;
      RECT 67.17 267.005 67.24 267.355 ;
      RECT 67.17 267.455 67.24 267.805 ;
      RECT 67.17 267.905 67.24 268.255 ;
      RECT 67.17 268.355 67.24 268.705 ;
      RECT 67.17 268.805 67.24 269.155 ;
      RECT 67.17 269.255 67.24 269.605 ;
      RECT 67.17 269.705 67.24 270.055 ;
      RECT 67.17 271.955 67.24 272.305 ;
      RECT 67.17 272.405 67.24 272.755 ;
      RECT 67.17 272.855 67.24 273.205 ;
      RECT 67.17 273.305 67.24 273.655 ;
      RECT 67.17 273.755 67.24 274.105 ;
      RECT 67.17 274.205 67.24 274.555 ;
      RECT 67.17 274.655 67.24 275.005 ;
      RECT 67.17 275.105 67.24 275.455 ;
      RECT 67.17 275.555 67.24 275.905 ;
      RECT 67.17 276.005 67.24 276.355 ;
      RECT 67.17 276.455 67.24 276.805 ;
      RECT 67.17 276.905 67.24 277.255 ;
      RECT 67.17 277.355 67.24 277.705 ;
      RECT 67.17 279.155 67.24 279.505 ;
      RECT 67.17 279.605 67.24 279.955 ;
      RECT 67.17 280.055 67.24 280.405 ;
      RECT 67.17 280.505 67.24 280.855 ;
      RECT 67.17 280.955 67.24 281.305 ;
      RECT 67.17 281.405 67.24 281.755 ;
      RECT 67.17 281.855 67.24 282.205 ;
      RECT 67.17 282.305 67.24 282.655 ;
      RECT 67.17 282.755 67.24 283.105 ;
      RECT 67.17 283.205 67.24 283.555 ;
      RECT 67.17 283.655 67.24 284.005 ;
      RECT 67.17 284.105 67.24 284.455 ;
      RECT 67.17 284.555 67.24 284.905 ;
      RECT 67.17 286.805 67.24 287.155 ;
      RECT 67.17 287.255 67.24 287.605 ;
      RECT 67.17 287.705 67.24 288.055 ;
      RECT 67.17 288.155 67.24 288.505 ;
      RECT 67.17 288.605 67.24 288.955 ;
      RECT 67.17 289.055 67.24 289.405 ;
      RECT 67.17 289.505 67.24 289.855 ;
      RECT 67.17 289.955 67.24 290.305 ;
      RECT 67.17 290.405 67.24 290.755 ;
      RECT 67.17 290.855 67.24 291.205 ;
      RECT 67.17 291.305 67.24 291.655 ;
      RECT 67.17 291.755 67.24 292.105 ;
      RECT 67.17 293.555 67.24 293.905 ;
      RECT 67.17 294.005 67.24 294.355 ;
      RECT 67.17 294.455 67.24 294.805 ;
      RECT 67.17 294.905 67.24 295.255 ;
      RECT 24.89 3.305 24.96 3.655 ;
      RECT 24.89 3.755 24.96 4.105 ;
      RECT 24.89 4.205 24.96 4.555 ;
      RECT 24.89 4.655 24.96 5.005 ;
      RECT 24.89 5.105 24.96 5.455 ;
      RECT 24.89 5.555 24.96 5.905 ;
      RECT 24.89 6.005 24.96 6.355 ;
      RECT 24.89 6.455 24.96 6.805 ;
      RECT 24.89 6.905 24.96 7.255 ;
      RECT 24.89 7.355 24.96 7.705 ;
      RECT 24.89 10.955 24.96 11.305 ;
      RECT 24.89 11.405 24.96 11.755 ;
      RECT 24.89 11.855 24.96 12.205 ;
      RECT 24.89 12.305 24.96 12.655 ;
      RECT 24.89 12.755 24.96 13.105 ;
      RECT 24.89 13.205 24.96 13.555 ;
      RECT 24.89 13.655 24.96 14.005 ;
      RECT 24.89 14.105 24.96 14.455 ;
      RECT 24.89 14.555 24.96 14.905 ;
      RECT 24.89 15.005 24.96 15.355 ;
      RECT 24.89 15.455 24.96 15.805 ;
      RECT 24.89 15.905 24.96 16.255 ;
      RECT 24.89 18.605 24.96 18.955 ;
      RECT 24.89 19.055 24.96 19.405 ;
      RECT 24.89 19.505 24.96 19.855 ;
      RECT 24.89 19.955 24.96 20.305 ;
      RECT 24.89 20.405 24.96 20.755 ;
      RECT 24.89 20.855 24.96 21.205 ;
      RECT 24.89 21.305 24.96 21.655 ;
      RECT 24.89 21.755 24.96 22.105 ;
      RECT 24.89 22.205 24.96 22.555 ;
      RECT 24.89 22.655 24.96 23.005 ;
      RECT 24.89 23.105 24.96 23.455 ;
      RECT 24.89 25.805 24.96 26.155 ;
      RECT 24.89 26.255 24.96 26.605 ;
      RECT 24.89 26.705 24.96 27.055 ;
      RECT 24.89 27.155 24.96 27.505 ;
      RECT 24.89 27.605 24.96 27.955 ;
      RECT 24.89 28.055 24.96 28.405 ;
      RECT 24.89 28.505 24.96 28.855 ;
      RECT 24.89 28.955 24.96 29.305 ;
      RECT 24.89 29.405 24.96 29.755 ;
      RECT 24.89 29.855 24.96 30.205 ;
      RECT 24.89 30.305 24.96 30.655 ;
      RECT 24.89 33.905 24.96 34.255 ;
      RECT 24.89 34.355 24.96 34.705 ;
      RECT 24.89 34.805 24.96 35.155 ;
      RECT 24.89 35.255 24.96 35.605 ;
      RECT 24.89 35.705 24.96 36.055 ;
      RECT 24.89 36.155 24.96 36.505 ;
      RECT 24.89 36.605 24.96 36.955 ;
      RECT 24.89 37.055 24.96 37.405 ;
      RECT 24.89 37.505 24.96 37.855 ;
      RECT 24.89 41.105 24.96 41.455 ;
      RECT 24.89 41.555 24.96 41.905 ;
      RECT 24.89 42.005 24.96 42.355 ;
      RECT 24.89 42.455 24.96 42.805 ;
      RECT 24.89 42.905 24.96 43.255 ;
      RECT 24.89 43.355 24.96 43.705 ;
      RECT 24.89 43.805 24.96 44.155 ;
      RECT 24.89 44.255 24.96 44.605 ;
      RECT 24.89 44.705 24.96 45.055 ;
      RECT 24.89 48.305 24.96 48.655 ;
      RECT 24.89 48.755 24.96 49.105 ;
      RECT 24.89 49.205 24.96 49.555 ;
      RECT 24.89 49.655 24.96 50.005 ;
      RECT 24.89 50.105 24.96 50.455 ;
      RECT 24.89 50.555 24.96 50.905 ;
      RECT 24.89 51.005 24.96 51.355 ;
      RECT 24.89 51.455 24.96 51.805 ;
      RECT 24.89 51.905 24.96 52.255 ;
      RECT 24.89 52.355 24.96 52.705 ;
      RECT 24.89 52.805 24.96 53.155 ;
      RECT 24.89 53.255 24.96 53.605 ;
      RECT 24.89 56.405 24.96 56.755 ;
      RECT 24.89 56.855 24.96 57.205 ;
      RECT 24.89 57.305 24.96 57.655 ;
      RECT 24.89 57.755 24.96 58.105 ;
      RECT 24.89 58.205 24.96 58.555 ;
      RECT 24.89 58.655 24.96 59.005 ;
      RECT 24.89 59.105 24.96 59.455 ;
      RECT 24.89 59.555 24.96 59.905 ;
      RECT 24.89 60.005 24.96 60.355 ;
      RECT 24.89 60.455 24.96 60.805 ;
      RECT 24.89 63.605 24.96 63.955 ;
      RECT 24.89 64.055 24.96 64.405 ;
      RECT 24.89 64.505 24.96 64.855 ;
      RECT 24.89 64.955 24.96 65.305 ;
      RECT 24.89 65.405 24.96 65.755 ;
      RECT 24.89 65.855 24.96 66.205 ;
      RECT 24.89 66.305 24.96 66.655 ;
      RECT 24.89 66.755 24.96 67.105 ;
      RECT 24.89 67.205 24.96 67.555 ;
      RECT 24.89 67.655 24.96 68.005 ;
      RECT 24.89 68.105 24.96 68.455 ;
      RECT 24.89 70.805 24.96 71.155 ;
      RECT 24.89 71.255 24.96 71.605 ;
      RECT 24.89 71.705 24.96 72.055 ;
      RECT 24.89 72.155 24.96 72.505 ;
      RECT 24.89 72.605 24.96 72.955 ;
      RECT 24.89 73.055 24.96 73.405 ;
      RECT 24.89 73.505 24.96 73.855 ;
      RECT 24.89 73.955 24.96 74.305 ;
      RECT 24.89 74.405 24.96 74.755 ;
      RECT 24.89 74.855 24.96 75.205 ;
      RECT 24.89 75.305 24.96 75.655 ;
      RECT 24.89 78.455 24.96 78.805 ;
      RECT 24.89 78.905 24.96 79.255 ;
      RECT 24.89 79.355 24.96 79.705 ;
      RECT 24.89 79.805 24.96 80.155 ;
      RECT 24.89 80.255 24.96 80.605 ;
      RECT 24.89 80.705 24.96 81.055 ;
      RECT 24.89 81.155 24.96 81.505 ;
      RECT 24.89 81.605 24.96 81.955 ;
      RECT 24.89 82.055 24.96 82.405 ;
      RECT 24.89 82.505 24.96 82.855 ;
      RECT 24.89 85.655 24.96 86.005 ;
      RECT 24.89 86.105 24.96 86.455 ;
      RECT 24.89 86.555 24.96 86.905 ;
      RECT 24.89 87.005 24.96 87.355 ;
      RECT 24.89 87.455 24.96 87.805 ;
      RECT 24.89 87.905 24.96 88.255 ;
      RECT 24.89 88.355 24.96 88.705 ;
      RECT 24.89 88.805 24.96 89.155 ;
      RECT 24.89 89.255 24.96 89.605 ;
      RECT 24.89 89.705 24.96 90.055 ;
      RECT 24.89 93.305 24.96 93.655 ;
      RECT 24.89 93.755 24.96 94.105 ;
      RECT 24.89 94.205 24.96 94.555 ;
      RECT 24.89 94.655 24.96 95.005 ;
      RECT 24.89 95.105 24.96 95.455 ;
      RECT 24.89 95.555 24.96 95.905 ;
      RECT 24.89 96.005 24.96 96.355 ;
      RECT 24.89 96.455 24.96 96.805 ;
      RECT 24.89 96.905 24.96 97.255 ;
      RECT 24.89 97.355 24.96 97.705 ;
      RECT 24.89 97.805 24.96 98.155 ;
      RECT 24.89 98.255 24.96 98.605 ;
      RECT 24.89 100.955 24.96 101.305 ;
      RECT 24.89 101.405 24.96 101.755 ;
      RECT 24.89 101.855 24.96 102.205 ;
      RECT 24.89 102.305 24.96 102.655 ;
      RECT 24.89 102.755 24.96 103.105 ;
      RECT 24.89 103.205 24.96 103.555 ;
      RECT 24.89 103.655 24.96 104.005 ;
      RECT 24.89 104.105 24.96 104.455 ;
      RECT 24.89 104.555 24.96 104.905 ;
      RECT 24.89 105.005 24.96 105.355 ;
      RECT 24.89 105.455 24.96 105.805 ;
      RECT 24.89 108.155 24.96 108.505 ;
      RECT 24.89 108.605 24.96 108.955 ;
      RECT 24.89 109.055 24.96 109.405 ;
      RECT 24.89 109.505 24.96 109.855 ;
      RECT 24.89 109.955 24.96 110.305 ;
      RECT 24.89 110.405 24.96 110.755 ;
      RECT 24.89 110.855 24.96 111.205 ;
      RECT 24.89 111.305 24.96 111.655 ;
      RECT 24.89 111.755 24.96 112.105 ;
      RECT 24.89 112.205 24.96 112.555 ;
      RECT 24.89 112.655 24.96 113.005 ;
      RECT 24.89 116.255 24.96 116.605 ;
      RECT 24.89 116.705 24.96 117.055 ;
      RECT 24.89 117.155 24.96 117.505 ;
      RECT 24.89 117.605 24.96 117.955 ;
      RECT 24.89 118.055 24.96 118.405 ;
      RECT 24.89 118.505 24.96 118.855 ;
      RECT 24.89 118.955 24.96 119.305 ;
      RECT 24.89 119.405 24.96 119.755 ;
      RECT 24.89 119.855 24.96 120.205 ;
      RECT 24.89 123.455 24.96 123.805 ;
      RECT 24.89 123.905 24.96 124.255 ;
      RECT 24.89 124.355 24.96 124.705 ;
      RECT 24.89 124.805 24.96 125.155 ;
      RECT 24.89 125.255 24.96 125.605 ;
      RECT 24.89 125.705 24.96 126.055 ;
      RECT 24.89 126.155 24.96 126.505 ;
      RECT 24.89 126.605 24.96 126.955 ;
      RECT 24.89 127.055 24.96 127.405 ;
      RECT 24.89 130.655 24.96 131.005 ;
      RECT 24.89 131.105 24.96 131.455 ;
      RECT 24.89 131.555 24.96 131.905 ;
      RECT 24.89 132.005 24.96 132.355 ;
      RECT 24.89 132.455 24.96 132.805 ;
      RECT 24.89 132.905 24.96 133.255 ;
      RECT 24.89 133.355 24.96 133.705 ;
      RECT 24.89 133.805 24.96 134.155 ;
      RECT 24.89 134.255 24.96 134.605 ;
      RECT 24.89 134.705 24.96 135.055 ;
      RECT 24.89 135.155 24.96 135.505 ;
      RECT 24.89 135.605 24.96 135.955 ;
      RECT 24.89 138.755 24.96 139.105 ;
      RECT 24.89 139.205 24.96 139.555 ;
      RECT 24.89 139.655 24.96 140.005 ;
      RECT 24.89 140.105 24.96 140.455 ;
      RECT 24.89 140.555 24.96 140.905 ;
      RECT 24.89 141.005 24.96 141.355 ;
      RECT 24.89 141.455 24.96 141.805 ;
      RECT 24.89 141.905 24.96 142.255 ;
      RECT 24.89 142.355 24.96 142.705 ;
      RECT 24.89 142.805 24.96 143.155 ;
      RECT 24.89 145.955 24.96 146.305 ;
      RECT 24.89 146.405 24.96 146.755 ;
      RECT 24.89 146.855 24.96 147.205 ;
      RECT 24.89 147.305 24.96 147.655 ;
      RECT 24.89 147.755 24.96 148.105 ;
      RECT 24.89 148.205 24.96 148.555 ;
      RECT 24.89 148.655 24.96 149.005 ;
      RECT 24.89 149.105 24.96 149.455 ;
      RECT 24.89 149.555 24.96 149.905 ;
      RECT 24.89 150.005 24.96 150.355 ;
      RECT 24.89 150.455 24.96 150.805 ;
      RECT 24.89 153.155 24.96 153.505 ;
      RECT 24.89 153.605 24.96 153.955 ;
      RECT 24.89 154.055 24.96 154.405 ;
      RECT 24.89 154.505 24.96 154.855 ;
      RECT 24.89 154.955 24.96 155.305 ;
      RECT 24.89 155.405 24.96 155.755 ;
      RECT 24.89 155.855 24.96 156.205 ;
      RECT 24.89 156.305 24.96 156.655 ;
      RECT 24.89 156.755 24.96 157.105 ;
      RECT 24.89 157.205 24.96 157.555 ;
      RECT 24.89 157.655 24.96 158.005 ;
      RECT 24.89 160.805 24.96 161.155 ;
      RECT 24.89 161.255 24.96 161.605 ;
      RECT 24.89 161.705 24.96 162.055 ;
      RECT 24.89 162.155 24.96 162.505 ;
      RECT 24.89 162.605 24.96 162.955 ;
      RECT 24.89 163.055 24.96 163.405 ;
      RECT 24.89 163.505 24.96 163.855 ;
      RECT 24.89 163.955 24.96 164.305 ;
      RECT 24.89 164.405 24.96 164.755 ;
      RECT 24.89 164.855 24.96 165.205 ;
      RECT 24.89 168.005 24.96 168.355 ;
      RECT 24.89 168.455 24.96 168.805 ;
      RECT 24.89 168.905 24.96 169.255 ;
      RECT 24.89 169.355 24.96 169.705 ;
      RECT 24.89 169.805 24.96 170.155 ;
      RECT 24.89 170.255 24.96 170.605 ;
      RECT 24.89 170.705 24.96 171.055 ;
      RECT 24.89 171.155 24.96 171.505 ;
      RECT 24.89 171.605 24.96 171.955 ;
      RECT 24.89 172.055 24.96 172.405 ;
      RECT 24.89 175.655 24.96 176.005 ;
      RECT 24.89 176.105 24.96 176.455 ;
      RECT 24.89 176.555 24.96 176.905 ;
      RECT 24.89 177.005 24.96 177.355 ;
      RECT 24.89 177.455 24.96 177.805 ;
      RECT 24.89 177.905 24.96 178.255 ;
      RECT 24.89 178.355 24.96 178.705 ;
      RECT 24.89 178.805 24.96 179.155 ;
      RECT 24.89 179.255 24.96 179.605 ;
      RECT 24.89 179.705 24.96 180.055 ;
      RECT 24.89 180.155 24.96 180.505 ;
      RECT 24.89 180.605 24.96 180.955 ;
      RECT 24.89 183.305 24.96 183.655 ;
      RECT 24.89 183.755 24.96 184.105 ;
      RECT 24.89 184.205 24.96 184.555 ;
      RECT 24.89 184.655 24.96 185.005 ;
      RECT 24.89 185.105 24.96 185.455 ;
      RECT 24.89 185.555 24.96 185.905 ;
      RECT 24.89 186.005 24.96 186.355 ;
      RECT 24.89 186.455 24.96 186.805 ;
      RECT 24.89 186.905 24.96 187.255 ;
      RECT 24.89 187.355 24.96 187.705 ;
      RECT 24.89 187.805 24.96 188.155 ;
      RECT 24.89 190.505 24.96 190.855 ;
      RECT 24.89 190.955 24.96 191.305 ;
      RECT 24.89 191.405 24.96 191.755 ;
      RECT 24.89 191.855 24.96 192.205 ;
      RECT 24.89 192.305 24.96 192.655 ;
      RECT 24.89 192.755 24.96 193.105 ;
      RECT 24.89 193.205 24.96 193.555 ;
      RECT 24.89 193.655 24.96 194.005 ;
      RECT 24.89 194.105 24.96 194.455 ;
      RECT 24.89 194.555 24.96 194.905 ;
      RECT 24.89 195.005 24.96 195.355 ;
      RECT 24.89 198.605 24.96 198.955 ;
      RECT 24.89 199.055 24.96 199.405 ;
      RECT 24.89 199.505 24.96 199.855 ;
      RECT 24.89 199.955 24.96 200.305 ;
      RECT 24.89 200.405 24.96 200.755 ;
      RECT 24.89 200.855 24.96 201.205 ;
      RECT 24.89 201.305 24.96 201.655 ;
      RECT 24.89 201.755 24.96 202.105 ;
      RECT 24.89 202.205 24.96 202.555 ;
      RECT 24.89 205.805 24.96 206.155 ;
      RECT 24.89 206.255 24.96 206.605 ;
      RECT 24.89 206.705 24.96 207.055 ;
      RECT 24.89 207.155 24.96 207.505 ;
      RECT 24.89 207.605 24.96 207.955 ;
      RECT 24.89 208.055 24.96 208.405 ;
      RECT 24.89 208.505 24.96 208.855 ;
      RECT 24.89 208.955 24.96 209.305 ;
      RECT 24.89 209.405 24.96 209.755 ;
      RECT 24.89 213.005 24.96 213.355 ;
      RECT 24.89 213.455 24.96 213.805 ;
      RECT 24.89 213.905 24.96 214.255 ;
      RECT 24.89 214.355 24.96 214.705 ;
      RECT 24.89 214.805 24.96 215.155 ;
      RECT 24.89 215.255 24.96 215.605 ;
      RECT 24.89 215.705 24.96 216.055 ;
      RECT 24.89 216.155 24.96 216.505 ;
      RECT 24.89 216.605 24.96 216.955 ;
      RECT 24.89 217.055 24.96 217.405 ;
      RECT 24.89 217.505 24.96 217.855 ;
      RECT 24.89 217.955 24.96 218.305 ;
      RECT 24.89 221.105 24.96 221.455 ;
      RECT 24.89 221.555 24.96 221.905 ;
      RECT 24.89 222.005 24.96 222.355 ;
      RECT 24.89 222.455 24.96 222.805 ;
      RECT 24.89 222.905 24.96 223.255 ;
      RECT 24.89 223.355 24.96 223.705 ;
      RECT 24.89 223.805 24.96 224.155 ;
      RECT 24.89 224.255 24.96 224.605 ;
      RECT 24.89 224.705 24.96 225.055 ;
      RECT 24.89 225.155 24.96 225.505 ;
      RECT 24.89 228.305 24.96 228.655 ;
      RECT 24.89 228.755 24.96 229.105 ;
      RECT 24.89 229.205 24.96 229.555 ;
      RECT 24.89 229.655 24.96 230.005 ;
      RECT 24.89 230.105 24.96 230.455 ;
      RECT 24.89 230.555 24.96 230.905 ;
      RECT 24.89 231.005 24.96 231.355 ;
      RECT 24.89 231.455 24.96 231.805 ;
      RECT 24.89 231.905 24.96 232.255 ;
      RECT 24.89 232.355 24.96 232.705 ;
      RECT 24.89 232.805 24.96 233.155 ;
      RECT 24.89 235.505 24.96 235.855 ;
      RECT 24.89 235.955 24.96 236.305 ;
      RECT 24.89 236.405 24.96 236.755 ;
      RECT 24.89 236.855 24.96 237.205 ;
      RECT 24.89 237.305 24.96 237.655 ;
      RECT 24.89 237.755 24.96 238.105 ;
      RECT 24.89 238.205 24.96 238.555 ;
      RECT 24.89 238.655 24.96 239.005 ;
      RECT 24.89 239.105 24.96 239.455 ;
      RECT 24.89 239.555 24.96 239.905 ;
      RECT 24.89 240.005 24.96 240.355 ;
      RECT 24.89 243.155 24.96 243.505 ;
      RECT 24.89 243.605 24.96 243.955 ;
      RECT 24.89 244.055 24.96 244.405 ;
      RECT 24.89 244.505 24.96 244.855 ;
      RECT 24.89 244.955 24.96 245.305 ;
      RECT 24.89 245.405 24.96 245.755 ;
      RECT 24.89 245.855 24.96 246.205 ;
      RECT 24.89 246.305 24.96 246.655 ;
      RECT 24.89 246.755 24.96 247.105 ;
      RECT 24.89 247.205 24.96 247.555 ;
      RECT 24.89 250.355 24.96 250.705 ;
      RECT 24.89 250.805 24.96 251.155 ;
      RECT 24.89 251.255 24.96 251.605 ;
      RECT 24.89 251.705 24.96 252.055 ;
      RECT 24.89 252.155 24.96 252.505 ;
      RECT 24.89 252.605 24.96 252.955 ;
      RECT 24.89 253.055 24.96 253.405 ;
      RECT 24.89 253.505 24.96 253.855 ;
      RECT 24.89 253.955 24.96 254.305 ;
      RECT 24.89 254.405 24.96 254.755 ;
      RECT 24.89 258.005 24.96 258.355 ;
      RECT 24.89 258.455 24.96 258.805 ;
      RECT 24.89 258.905 24.96 259.255 ;
      RECT 24.89 259.355 24.96 259.705 ;
      RECT 24.89 259.805 24.96 260.155 ;
      RECT 24.89 260.255 24.96 260.605 ;
      RECT 24.89 260.705 24.96 261.055 ;
      RECT 24.89 261.155 24.96 261.505 ;
      RECT 24.89 261.605 24.96 261.955 ;
      RECT 24.89 262.055 24.96 262.405 ;
      RECT 24.89 262.505 24.96 262.855 ;
      RECT 24.89 262.955 24.96 263.305 ;
      RECT 24.89 265.655 24.96 266.005 ;
      RECT 24.89 266.105 24.96 266.455 ;
      RECT 24.89 266.555 24.96 266.905 ;
      RECT 24.89 267.005 24.96 267.355 ;
      RECT 24.89 267.455 24.96 267.805 ;
      RECT 24.89 267.905 24.96 268.255 ;
      RECT 24.89 268.355 24.96 268.705 ;
      RECT 24.89 268.805 24.96 269.155 ;
      RECT 24.89 269.255 24.96 269.605 ;
      RECT 24.89 269.705 24.96 270.055 ;
      RECT 24.89 270.155 24.96 270.505 ;
      RECT 24.89 272.855 24.96 273.205 ;
      RECT 24.89 273.305 24.96 273.655 ;
      RECT 24.89 273.755 24.96 274.105 ;
      RECT 24.89 274.205 24.96 274.555 ;
      RECT 24.89 274.655 24.96 275.005 ;
      RECT 24.89 275.105 24.96 275.455 ;
      RECT 24.89 275.555 24.96 275.905 ;
      RECT 24.89 276.005 24.96 276.355 ;
      RECT 24.89 276.455 24.96 276.805 ;
      RECT 24.89 276.905 24.96 277.255 ;
      RECT 24.89 277.355 24.96 277.705 ;
      RECT 24.89 280.955 24.96 281.305 ;
      RECT 24.89 281.405 24.96 281.755 ;
      RECT 24.89 281.855 24.96 282.205 ;
      RECT 24.89 282.305 24.96 282.655 ;
      RECT 24.89 282.755 24.96 283.105 ;
      RECT 24.89 283.205 24.96 283.555 ;
      RECT 24.89 283.655 24.96 284.005 ;
      RECT 24.89 284.105 24.96 284.455 ;
      RECT 24.89 284.555 24.96 284.905 ;
      RECT 24.89 288.155 24.96 288.505 ;
      RECT 24.89 288.605 24.96 288.955 ;
      RECT 24.89 289.055 24.96 289.405 ;
      RECT 24.89 289.505 24.96 289.855 ;
      RECT 24.89 289.955 24.96 290.305 ;
      RECT 24.89 290.405 24.96 290.755 ;
      RECT 24.89 290.855 24.96 291.205 ;
      RECT 24.89 291.305 24.96 291.655 ;
      RECT 24.89 291.755 24.96 292.105 ;
      RECT 24.75 3.305 24.82 3.655 ;
      RECT 24.75 3.755 24.82 4.105 ;
      RECT 24.75 4.205 24.82 4.555 ;
      RECT 24.75 4.655 24.82 5.005 ;
      RECT 24.75 5.105 24.82 5.455 ;
      RECT 24.75 10.955 24.82 11.305 ;
      RECT 24.75 11.405 24.82 11.755 ;
      RECT 24.75 11.855 24.82 12.205 ;
      RECT 24.75 12.305 24.82 12.655 ;
      RECT 24.75 18.605 24.82 18.955 ;
      RECT 24.75 19.055 24.82 19.405 ;
      RECT 24.75 19.505 24.82 19.855 ;
      RECT 24.75 25.805 24.82 26.155 ;
      RECT 24.75 26.255 24.82 26.605 ;
      RECT 24.75 26.705 24.82 27.055 ;
      RECT 24.75 33.905 24.82 34.255 ;
      RECT 24.75 34.355 24.82 34.705 ;
      RECT 24.75 34.805 24.82 35.155 ;
      RECT 24.75 35.255 24.82 35.605 ;
      RECT 24.75 41.105 24.82 41.455 ;
      RECT 24.75 41.555 24.82 41.905 ;
      RECT 24.75 42.005 24.82 42.355 ;
      RECT 24.75 42.455 24.82 42.805 ;
      RECT 24.75 48.305 24.82 48.655 ;
      RECT 24.75 48.755 24.82 49.105 ;
      RECT 24.75 49.205 24.82 49.555 ;
      RECT 24.75 49.655 24.82 50.005 ;
      RECT 24.75 56.405 24.82 56.755 ;
      RECT 24.75 56.855 24.82 57.205 ;
      RECT 24.75 63.605 24.82 63.955 ;
      RECT 24.75 64.055 24.82 64.405 ;
      RECT 24.75 70.805 24.82 71.155 ;
      RECT 24.75 71.255 24.82 71.605 ;
      RECT 24.75 71.705 24.82 72.055 ;
      RECT 24.75 72.155 24.82 72.505 ;
      RECT 24.75 72.605 24.82 72.955 ;
      RECT 24.75 78.455 24.82 78.805 ;
      RECT 24.75 78.905 24.82 79.255 ;
      RECT 24.75 79.355 24.82 79.705 ;
      RECT 24.75 79.805 24.82 80.155 ;
      RECT 24.75 85.655 24.82 86.005 ;
      RECT 24.75 86.105 24.82 86.455 ;
      RECT 24.75 86.555 24.82 86.905 ;
      RECT 24.75 87.005 24.82 87.355 ;
      RECT 24.75 87.455 24.82 87.805 ;
      RECT 24.75 93.305 24.82 93.655 ;
      RECT 24.75 93.755 24.82 94.105 ;
      RECT 24.75 94.205 24.82 94.555 ;
      RECT 24.75 94.655 24.82 95.005 ;
      RECT 24.75 100.955 24.82 101.305 ;
      RECT 24.75 101.405 24.82 101.755 ;
      RECT 24.75 101.855 24.82 102.205 ;
      RECT 24.75 108.155 24.82 108.505 ;
      RECT 24.75 108.605 24.82 108.955 ;
      RECT 24.75 109.055 24.82 109.405 ;
      RECT 24.75 116.255 24.82 116.605 ;
      RECT 24.75 116.705 24.82 117.055 ;
      RECT 24.75 117.155 24.82 117.505 ;
      RECT 24.75 117.605 24.82 117.955 ;
      RECT 24.75 123.455 24.82 123.805 ;
      RECT 24.75 123.905 24.82 124.255 ;
      RECT 24.75 124.355 24.82 124.705 ;
      RECT 24.75 124.805 24.82 125.155 ;
      RECT 24.75 130.655 24.82 131.005 ;
      RECT 24.75 131.105 24.82 131.455 ;
      RECT 24.75 131.555 24.82 131.905 ;
      RECT 24.75 132.005 24.82 132.355 ;
      RECT 24.75 138.755 24.82 139.105 ;
      RECT 24.75 139.205 24.82 139.555 ;
      RECT 24.75 145.955 24.82 146.305 ;
      RECT 24.75 146.405 24.82 146.755 ;
      RECT 24.75 153.155 24.82 153.505 ;
      RECT 24.75 153.605 24.82 153.955 ;
      RECT 24.75 154.055 24.82 154.405 ;
      RECT 24.75 154.505 24.82 154.855 ;
      RECT 24.75 154.955 24.82 155.305 ;
      RECT 24.75 160.805 24.82 161.155 ;
      RECT 24.75 161.255 24.82 161.605 ;
      RECT 24.75 161.705 24.82 162.055 ;
      RECT 24.75 162.155 24.82 162.505 ;
      RECT 24.75 168.005 24.82 168.355 ;
      RECT 24.75 168.455 24.82 168.805 ;
      RECT 24.75 168.905 24.82 169.255 ;
      RECT 24.75 169.355 24.82 169.705 ;
      RECT 24.75 169.805 24.82 170.155 ;
      RECT 24.75 175.655 24.82 176.005 ;
      RECT 24.75 176.105 24.82 176.455 ;
      RECT 24.75 176.555 24.82 176.905 ;
      RECT 24.75 177.005 24.82 177.355 ;
      RECT 24.75 183.305 24.82 183.655 ;
      RECT 24.75 183.755 24.82 184.105 ;
      RECT 24.75 184.205 24.82 184.555 ;
      RECT 24.75 190.505 24.82 190.855 ;
      RECT 24.75 190.955 24.82 191.305 ;
      RECT 24.75 191.405 24.82 191.755 ;
      RECT 24.75 198.605 24.82 198.955 ;
      RECT 24.75 199.055 24.82 199.405 ;
      RECT 24.75 199.505 24.82 199.855 ;
      RECT 24.75 199.955 24.82 200.305 ;
      RECT 24.75 205.805 24.82 206.155 ;
      RECT 24.75 206.255 24.82 206.605 ;
      RECT 24.75 206.705 24.82 207.055 ;
      RECT 24.75 207.155 24.82 207.505 ;
      RECT 24.75 213.005 24.82 213.355 ;
      RECT 24.75 213.455 24.82 213.805 ;
      RECT 24.75 213.905 24.82 214.255 ;
      RECT 24.75 214.355 24.82 214.705 ;
      RECT 24.75 221.105 24.82 221.455 ;
      RECT 24.75 221.555 24.82 221.905 ;
      RECT 24.75 228.305 24.82 228.655 ;
      RECT 24.75 228.755 24.82 229.105 ;
      RECT 24.75 235.505 24.82 235.855 ;
      RECT 24.75 235.955 24.82 236.305 ;
      RECT 24.75 236.405 24.82 236.755 ;
      RECT 24.75 236.855 24.82 237.205 ;
      RECT 24.75 237.305 24.82 237.655 ;
      RECT 24.75 243.155 24.82 243.505 ;
      RECT 24.75 243.605 24.82 243.955 ;
      RECT 24.75 244.055 24.82 244.405 ;
      RECT 24.75 244.505 24.82 244.855 ;
      RECT 24.75 250.355 24.82 250.705 ;
      RECT 24.75 250.805 24.82 251.155 ;
      RECT 24.75 251.255 24.82 251.605 ;
      RECT 24.75 251.705 24.82 252.055 ;
      RECT 24.75 252.155 24.82 252.505 ;
      RECT 24.75 258.005 24.82 258.355 ;
      RECT 24.75 258.455 24.82 258.805 ;
      RECT 24.75 258.905 24.82 259.255 ;
      RECT 24.75 259.355 24.82 259.705 ;
      RECT 24.75 265.655 24.82 266.005 ;
      RECT 24.75 266.105 24.82 266.455 ;
      RECT 24.75 266.555 24.82 266.905 ;
      RECT 24.75 272.855 24.82 273.205 ;
      RECT 24.75 273.305 24.82 273.655 ;
      RECT 24.75 273.755 24.82 274.105 ;
      RECT 24.75 280.955 24.82 281.305 ;
      RECT 24.75 281.405 24.82 281.755 ;
      RECT 24.75 281.855 24.82 282.205 ;
      RECT 24.75 282.305 24.82 282.655 ;
      RECT 24.75 288.155 24.82 288.505 ;
      RECT 24.75 288.605 24.82 288.955 ;
      RECT 24.75 289.055 24.82 289.405 ;
      RECT 24.75 289.505 24.82 289.855 ;
      RECT 24.655 32.355 24.775 33.355 ;
      RECT 24.655 55.345 24.775 55.845 ;
      RECT 24.655 114.71 24.775 115.71 ;
      RECT 24.655 137.7 24.775 138.2 ;
      RECT 24.655 197.065 24.775 198.065 ;
      RECT 24.655 220.055 24.775 220.555 ;
      RECT 24.655 279.42 24.775 280.42 ;
      RECT 24.65 17.8 24.77 18.3 ;
      RECT 24.65 77.165 24.77 78.165 ;
      RECT 24.65 100.155 24.77 100.655 ;
      RECT 24.65 159.52 24.77 160.52 ;
      RECT 24.65 182.51 24.77 183.01 ;
      RECT 24.65 241.875 24.77 242.875 ;
      RECT 24.65 264.865 24.77 265.365 ;
      RECT 24.645 39.62 24.765 40.62 ;
      RECT 24.645 62.61 24.765 63.11 ;
      RECT 24.645 121.975 24.765 122.975 ;
      RECT 24.645 144.965 24.765 145.465 ;
      RECT 24.645 204.33 24.765 205.33 ;
      RECT 24.645 227.32 24.765 227.82 ;
      RECT 24.645 286.685 24.765 287.685 ;
      RECT 24.64 2.075 24.76 3.075 ;
      RECT 24.64 25.065 24.76 25.565 ;
      RECT 24.64 84.43 24.76 85.43 ;
      RECT 24.64 107.42 24.76 107.92 ;
      RECT 24.64 166.785 24.76 167.785 ;
      RECT 24.64 189.775 24.76 190.275 ;
      RECT 24.64 249.14 24.76 250.14 ;
      RECT 24.64 272.13 24.76 272.63 ;
      RECT 24.635 46.885 24.755 47.885 ;
      RECT 24.635 69.875 24.755 70.375 ;
      RECT 24.635 129.24 24.755 130.24 ;
      RECT 24.635 152.23 24.755 152.73 ;
      RECT 24.635 211.595 24.755 212.595 ;
      RECT 24.635 234.585 24.755 235.085 ;
      RECT 24.635 293.95 24.755 294.95 ;
      RECT 24.63 9.34 24.75 10.34 ;
      RECT 24.63 91.695 24.75 92.695 ;
      RECT 24.63 174.05 24.75 175.05 ;
      RECT 24.63 256.405 24.75 257.405 ;
      RECT 24.625 54.15 24.745 55.15 ;
      RECT 24.625 136.505 24.745 137.505 ;
      RECT 24.625 218.86 24.745 219.86 ;
      RECT 24.62 16.605 24.74 17.605 ;
      RECT 24.62 98.96 24.74 99.96 ;
      RECT 24.62 181.315 24.74 182.315 ;
      RECT 24.62 263.67 24.74 264.67 ;
      RECT 24.615 61.415 24.735 62.415 ;
      RECT 24.615 143.77 24.735 144.77 ;
      RECT 24.615 226.125 24.735 227.125 ;
      RECT 24.61 23.87 24.73 24.87 ;
      RECT 24.61 106.225 24.73 107.225 ;
      RECT 24.61 188.58 24.73 189.58 ;
      RECT 24.61 270.935 24.73 271.935 ;
      RECT 24.605 68.68 24.725 69.68 ;
      RECT 24.605 151.035 24.725 152.035 ;
      RECT 24.605 233.39 24.725 234.39 ;
      RECT 24.6 31.135 24.72 32.135 ;
      RECT 24.6 113.49 24.72 114.49 ;
      RECT 24.6 195.845 24.72 196.845 ;
      RECT 24.6 278.2 24.72 279.2 ;
      RECT 24.595 75.945 24.715 76.945 ;
      RECT 24.595 158.3 24.715 159.3 ;
      RECT 24.595 240.655 24.715 241.655 ;
      RECT 24.59 38.4 24.71 39.4 ;
      RECT 24.59 120.755 24.71 121.755 ;
      RECT 24.59 203.11 24.71 204.11 ;
      RECT 24.59 285.465 24.71 286.465 ;
      RECT 24.585 0.855 24.705 1.855 ;
      RECT 24.585 83.21 24.705 84.21 ;
      RECT 24.585 165.565 24.705 166.565 ;
      RECT 24.585 247.92 24.705 248.92 ;
      RECT 24.58 45.665 24.7 46.665 ;
      RECT 24.58 128.02 24.7 129.02 ;
      RECT 24.58 210.375 24.7 211.375 ;
      RECT 24.58 292.73 24.7 293.73 ;
      RECT 24.575 8.12 24.695 9.12 ;
      RECT 24.575 90.475 24.695 91.475 ;
      RECT 24.575 172.83 24.695 173.83 ;
      RECT 24.575 255.185 24.695 256.185 ;
      RECT 24.57 52.93 24.69 53.93 ;
      RECT 24.57 135.285 24.69 136.285 ;
      RECT 24.57 217.64 24.69 218.64 ;
      RECT 24.565 15.385 24.685 16.385 ;
      RECT 24.565 97.74 24.685 98.74 ;
      RECT 24.565 180.095 24.685 181.095 ;
      RECT 24.565 262.45 24.685 263.45 ;
      RECT 24.56 60.195 24.68 61.195 ;
      RECT 24.56 142.55 24.68 143.55 ;
      RECT 24.56 224.905 24.68 225.905 ;
      RECT 24.555 22.65 24.675 23.65 ;
      RECT 24.555 105.005 24.675 106.005 ;
      RECT 24.555 187.36 24.675 188.36 ;
      RECT 24.555 269.715 24.675 270.715 ;
      RECT 24.55 67.46 24.67 68.46 ;
      RECT 24.55 149.815 24.67 150.815 ;
      RECT 24.55 232.17 24.67 233.17 ;
      RECT 24.545 29.915 24.665 30.915 ;
      RECT 24.545 112.27 24.665 113.27 ;
      RECT 24.545 194.625 24.665 195.625 ;
      RECT 24.545 276.98 24.665 277.98 ;
      RECT 24.54 74.725 24.66 75.725 ;
      RECT 24.54 157.08 24.66 158.08 ;
      RECT 24.54 239.435 24.66 240.435 ;
      RECT 24.31 295.255 24.66 295.325 ;
      RECT 24.535 37.18 24.655 38.18 ;
      RECT 24.535 119.535 24.655 120.535 ;
      RECT 24.535 201.89 24.655 202.89 ;
      RECT 24.535 284.245 24.655 285.245 ;
      RECT 24.53 81.99 24.65 82.99 ;
      RECT 24.53 164.345 24.65 165.345 ;
      RECT 24.53 246.7 24.65 247.7 ;
      RECT 24.525 44.445 24.645 45.445 ;
      RECT 24.525 126.8 24.645 127.8 ;
      RECT 24.525 209.155 24.645 210.155 ;
      RECT 24.525 291.51 24.645 292.51 ;
      RECT 24.52 6.9 24.64 7.9 ;
      RECT 24.52 89.255 24.64 90.255 ;
      RECT 24.52 171.61 24.64 172.61 ;
      RECT 24.52 253.965 24.64 254.965 ;
      RECT 24.515 51.71 24.635 52.71 ;
      RECT 24.515 134.065 24.635 135.065 ;
      RECT 24.515 216.42 24.635 217.42 ;
      RECT 24.51 14.165 24.63 15.165 ;
      RECT 24.51 96.52 24.63 97.52 ;
      RECT 24.51 178.875 24.63 179.875 ;
      RECT 24.51 261.23 24.63 262.23 ;
      RECT 24.505 58.975 24.625 59.975 ;
      RECT 24.505 141.33 24.625 142.33 ;
      RECT 24.505 223.685 24.625 224.685 ;
    LAYER M7 SPACING 0.05 ;
      RECT 67.095 0 92.2 296 ;
      RECT 0 0 25.075 296 ;
  END
  PROPERTY CatenaDesignType "chipAssembly" ;
END phy_spine_d

END LIBRARY
